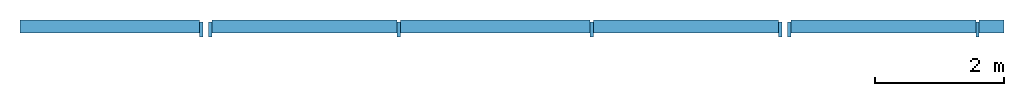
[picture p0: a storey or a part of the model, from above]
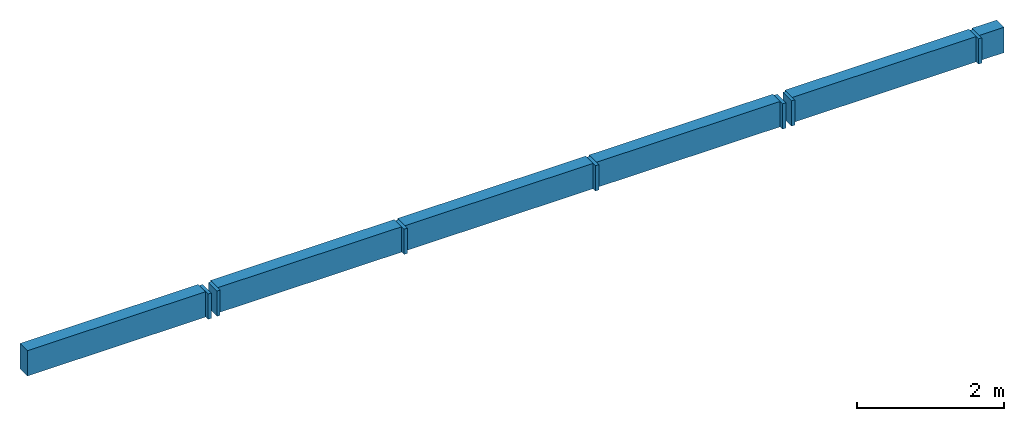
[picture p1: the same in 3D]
Properties of the parts of a building model (IFC2X3), part 1 of 7

# File
Description: ViewDefinition [CoordinationView]
File name: GM.TO-350-207.1 (EDITED).ifc (Edited by Naviate Simple BIM 2022 version 6)
Time: 2026-03-17T17:16:46+01:00
Written by: ODA SDAI 24.12
Made in: Autodesk Revit 25.4.20.11 (ENU) - IFC 25.4.0.27

# IfcProject, 10004870
LongName: 10004870; Phase: Detaljprosjekt

# IfcSite (6)
Name | RefLatitude | RefLongitude | RefElevation (mm) | Reference longitude | Reference elevation | Reference latitude | Name
ENGM | 59, 54, 57, 601318 | 10, 44, 59, 999999 | -4.85124e-10
ENGM | 42, 12, 46, 799999 | -71, -1, -58, -799999 | 0 | -71, -1, -58, -799999 | 0 | 42, 12, 46, 799999 | ENGM
ENGM | 59, 54, 57, 599999 | 10, 44, 59, 999999 | 0 | 10, 44, 59, 999999 | 0 | 59, 54, 57, 599999 | ENGM
ENGM | 42, 24, 53, 508911 | -71, -15, -29, -58837 | 0 | -71, -15, -29, -58837 | 0 | 42, 24, 53, 508911 | ENGM
ENGM | 59, 54, 49, 759826 | 10, 44, 19, 467315 | 0 | 10, 44, 19, 467315 | 0 | 59, 54, 49, 759826 | ENGM
Gardermoen

# IfcBuilding (6)
Name | Building name
TH | LongName: TH; Pset_BuildingCommon - NumberOfStoreys: 14
4 x TH | TH
TH

# IfcBuildingStorey (13)
In: TH
Name | Elevation (mm) | Name
4 x Nivå D + 1,2 m | 205200 | Nivå D + 1,2 m
4 x Nivå F - 0,7 m | 210200 | Nivå F - 0,7 m
Nivå G - 2,0m | 213700 | Nivå G - 2,0m
Nivå F | 210900 | Nivå F
D | 0
G | 0
F | 0

# IfcBuildingStorey: Level:T2 - Kote (7)
In: TH
Name | LongName | Elevation (mm) | Pset_ProductRequirements, Name | Pset_ProductRequirements, sets with these values
Nivå B | Nivå B | 197000 | Nivå B | 2
Nivå D + 1,2 m | Nivå D + 1,2 m | 205200 | Pset_AirSideSystemInformation - Name: Nivå D + 1,2 m; sets with these values: 2
Nivå E | Nivå E | 207370 | Nivå E | 2
Nivå F - 0,7 m | Nivå F - 0,7 m | 210200 | Nivå F - 0,7 m | 2
Nivå F | Nivå F | 210900 | Pset_AirSideSystemInformation - Name: Nivå F; sets with these values: 2
Nivå G - 2,0 m | Nivå G - 2,0 m | 213700 | Nivå G - 2,0 m | 2
Nivå G | Nivå G | 215700 | Pset_AirSideSystemInformation - Name: Nivå G; sets with these values: 2

# IfcBeam: 10*150 (9)
In: G
Description: 10*150; Material: STEEL/S355
AVINOR - 07_Fase: F90; 02_Prosjekt: T1; 04_Kontrakt: FDV; 03_Ansvar: FDV; 08_Status: S2; 10_Objektstatus: 3_Eksisterende/ Existing; 06_Omrade: TH; 01_Lufthavnkode: ENGM
Tekla Common - Grade: S355; Name: STÅLBJELKE; Profile: 10*150; Assembly mark: SB-10449(?); Class: 330
ePset_LocationTool - Splitting: ORIGINAL
Tekla Status - Status: Unknown; Assigned By: Me; Actual: 1; Scheduled: 0; Erection Comment: Missing Value
Pset_BeamCommon - LoadBearing: no
Tekla Quantity - Heigth: 10 mm; Width: 150 mm
ePset_Simplebim - Assembly Level: Leaf
Name | Part mark = Reference | Top elevation | Bottom elevation | Weight, as steel (Simplebim) (kg) | Volume, net (Simplebim) (m3) | Area, sides, net (Simplebim) (m2) = AREA_GROSS (m2) = AREA_NET (m2) | Height (Simplebim) (mm) | Width (Simplebim) (mm) | Length (Simplebim) (mm) | WEIGTH_NET (kg) = WEIGTH_GROSS (kg) | VOLUME_NET (m3) = VOLUME_GROSS (m3) | Length (mm)
3 x STÅLBJELKE | DSB-21652(?) | +213.570 | +213.560 | 4.12125 | 0.000525 | 0.115 | 10 | 150 | 350 | 4.12125 | 0.00054 | 350
3 x STÅLBJELKE | DSB-21605(?) | +213.580 | +213.570 | 3.88575 | 0.000495 | 0.1086 | 10 | 150 | 330 | 3.8858 | 0.00049 | 330.004
3 x STÅLBJELKE | DSB-21653(?) | +213.620 | +213.350 | 3.17925 | 0.000405 | 0.0894 | 270 | 10 | 150 | 3.17925 | 0.00041 | 270

# IfcBeam: 20*140 (2)
In: G
Description: 20*140; Material: STEEL/S355
AVINOR - 07_Fase: F90; 02_Prosjekt: T1; 04_Kontrakt: FDV; 03_Ansvar: FDV; 08_Status: S2; 10_Objektstatus: 3_Eksisterende/ Existing; 06_Omrade: TH; 01_Lufthavnkode: ENGM
Pset_BeamCommon - LoadBearing: no; Reference: DSB-19066(?)
Tekla Quantity - VOLUME_NET: 0.00015 m3; VOLUME_GROSS: 0.00015 m3; Length: 49.9999 mm; WEIGTH_NET: 1.099 kg; WEIGTH_GROSS: 1.099 kg; Heigth: 20 mm; Width: 140 mm; AREA_NET: 0.0216 m2; AREA_GROSS: 0.0216 m2
Tekla Common - Grade: S355; Bottom elevation: +213.560; Top elevation: +213.580; Name: STÅLBJELKE; Profile: 20*140; Assembly mark: SB-10449(?); Part mark: DSB-19066(?); Class: 330
ePset_SimplebimBasicQuantities - Volume, net (Simplebim): 0.00014 m3; Weight, as steel (Simplebim): 1.099 kg; Height (Simplebim): 20 mm; Width (Simplebim): 50 mm; Length (Simplebim): 140 mm; Area, sides, net (Simplebim): 0.0216 m2
Tekla Status - Status: Unknown; Assigned By: Me; Actual: 1; Scheduled: 0; Erection Comment: Missing Value
ePset_LocationTool - Splitting: ORIGINAL
ePset_Simplebim - Assembly Level: Leaf

# IfcBeam: 25*140 (2)
In: G
Description: 25*140; Material: STEEL/S355
AVINOR - 07_Fase: F90; 02_Prosjekt: T1; 04_Kontrakt: FDV; 03_Ansvar: FDV; 08_Status: S2; 10_Objektstatus: 3_Eksisterende/ Existing; 06_Omrade: TH; 01_Lufthavnkode: ENGM
Tekla Common - Grade: S355; Bottom elevation: +213.411; Profile: 25*140; Name: STÅLBJELKE; Part mark: DSB-20613(?); Assembly mark: SB-12403(?); Top elevation: +213.541; Class: 330
ePset_SimplebimBasicQuantities - Weight, as steel (Simplebim): 3.57175 kg; Area, sides, net (Simplebim): 0.0499 m2; Volume, net (Simplebim): 0.000455 m3; Width (Simplebim): 25 mm; Height (Simplebim): 130 mm; Length (Simplebim): 140 mm
ePset_LocationTool - Splitting: ORIGINAL
Tekla Status - Status: Unknown; Assigned By: Me; Actual: 1; Scheduled: 0; Erection Comment: Missing Value
Tekla Quantity - WEIGTH_NET: 3.57175 kg; WEIGTH_GROSS: 3.57175 kg; AREA_GROSS: 0.0499 m2; AREA_NET: 0.0499 m2; Heigth: 25 mm; Length: 130 mm; Width: 140 mm; VOLUME_GROSS: 0.00045 m3; VOLUME_NET: 0.00045 m3
ePset_Simplebim - Assembly Level: Leaf
Pset_BeamCommon - Reference: DSB-20613(?); LoadBearing: no

# IfcBeam: 60*5 (15)
In: G
Description: 60*5; Material: STEEL/S355
Pset_BeamCommon - LoadBearing: no; Reference: DSB-18871(?)
AVINOR - 07_Fase: F90; 02_Prosjekt: T1; 04_Kontrakt: FDV; 03_Ansvar: FDV; 08_Status: S2; 10_Objektstatus: 3_Eksisterende/ Existing; 06_Omrade: TH; 01_Lufthavnkode: ENGM
ePset_SimplebimBasicQuantities - Weight, as steel (Simplebim): 0.35325 kg; Volume, net (Simplebim): 0.000045 m3; Area, sides, net (Simplebim): 0.0201 m2; Height (Simplebim): 5 mm; Width (Simplebim): 60 mm; Length (Simplebim): 150 mm
Tekla Status - Status: Unknown; Assigned By: Me; Actual: 1; Scheduled: 0; Erection Comment: Missing Value
ePset_LocationTool - Splitting: ORIGINAL
Tekla Quantity - VOLUME_NET: 0.00005 m3; VOLUME_GROSS: 0.00005 m3; WEIGTH_GROSS: 0.35325 kg; WEIGTH_NET: 0.35325 kg; AREA_NET: 0.0201 m2; AREA_GROSS: 0.0201 m2; Width: 5 mm; Heigth: 60 mm; Length: 150 mm
Tekla Common - Grade: S355; Name: STÅLBJELKE; Assembly mark: SB-10449(?); Top elevation: +213.665; Bottom elevation: +213.660; Part mark: DSB-18871(?); Class: 330; Profile: 60*5
ePset_Simplebim - Assembly Level: Leaf

# IfcBeam: AAJKORS265*195*30*900*150*700*700 (2)
In: F
Description: AAJKORS265*195*30*900*150*700*700
Tekla Common - Name: PREFABBJELKE; Top elevation: +210.030; Bottom elevation: +209.130; Profile: AAJKORS265*195*30*900*150*700*700; Grade: C45/55; Class: 130
Pset_BeamCommon - LoadBearing: no
ePset_SimplebimBasicQuantities - Height (Simplebim): 900 mm; Width (Simplebim): 1000 mm; Length (Simplebim): 8775 mm
Tekla Status - Status: Unknown; Assigned By: Me; Actual: 1; Scheduled: 0; Erection Comment: Missing Value
ePset_LocationTool - Splitting: RESULT
AVINOR - 07_Fase: F90; 02_Prosjekt: T1; 04_Kontrakt: FDV; 03_Ansvar: FDV; 08_Status: S2; 05_ID-nummer: +TA=223.001; 10_Objektstatus: 3_Eksisterende/ Existing; 06_Omrade: TH; 01_Lufthavnkode: ENGM
ePset_Simplebim - Assembly Level: Leaf
Name | Assembly mark | Part mark = Reference | Volume, net (Simplebim) (m3) | Area, sides, net (Simplebim) (m2) | Weight, as steel (Simplebim) (kg)
PREFABBJELKE | PB-639 | Concrete_PB-1-34 | 5.44013 | 34.8306 | 42705
PREFABBJELKE | PB-644 | Concrete_PB-1-39 | 5.44051 | 34.8266 | 42708

# IfcBeam: B223 - Bjelke - Flatstål:B223 - Bjelke - Flatstål - w240 h 8 (3)
In: Nivå G - 2,0 m
Type - PredefinedType: BEAM
Type - Pset_BeamCommon - LoadBearing: yes
AVINOR - 07_Fase: F90; 03_Ansvar: FDV; 08_Status: S2; 06_Omrade: TH; 01_Lufthavnkode: ENGM
Pset_QuantityTakeOff - Reference: B223 - Bjelke - Flatstål - w240 h 8; sets with these values: 2
ePset_SimplebimBasicQuantities - Width (Simplebim): 8 mm; Height (Simplebim): 240 mm
Pset_BeamCommon - IsExternal: no; Reference: B223 - Bjelke - Flatstål - w240 h 8
ePset_Simplebim - Assembly Level: Leaf
Name (B223 - Bjelke - Flatstål:B223 - Bjelke - Flatstål - w240 h 8:...) | Splitting | Volume, net (Simplebim) (m3) | Weight, as steel (Simplebim) (kg) | Area, sides, net (Simplebim) (m2) | Length (Simplebim) (mm) | Group
37630491 | ORIGINAL | 0.01728 | 135.648 | 4.46784 | 9000 | Model Group:A240 - eksisterende gallerivegg i pir G-2 / generell (members excluded):37630519 | Material: _NSW Stål; Pset_BeamCommon - Slope: 0 deg; Span: 9000 mm
37559219 | RESULT | 0.00554514 | 43.5294 | 1.43633 | 2888 | Model Group:A240 - eksisterende gallerivegg i pir G-2 / bak sjakt (members excluded):37559234
37630725 | RESULT | 0.00654832 | 51.4043 | 1.69549 | 3411 | Model Group:A240 - eksisterende gallerivegg i pir G-2 / generell (members excluded):37630753

# IfcBeam: B223 - Bjelke - HUP2:B223 - HUP 50x50x5mm 2 (15)
In: Nivå F - 0,7 m
Type - PredefinedType: BEAM
Type - Pset_BeamCommon - LoadBearing: yes
Material: _NSW Stål; Group: Model Group:A184862 - Kiosk NSOPØ 05.235 2 (members excluded):47061109
ePset_SimplebimBasicQuantities - Height (Simplebim): 50 mm; Width (Simplebim): 50 mm
Pset_QuantityTakeOff - Reference: B223 - HUP 50x50x5mm 2; sets with these values: 2
ePset_LocationTool - Splitting: ORIGINAL
AVINOR - 08_Status: S4; 07_Fase: F90; 03_Ansvar: 182412; 06_Omrade: TH; 02_Prosjekt: A184862; 05_ID-nummer: +TH=223.042; 01_Lufthavnkode: ENGM
Pset_BeamCommon - IsExternal: no; Slope: 0 deg; Reference: B223 - HUP 50x50x5mm 2
ePset_Simplebim - Assembly Level: Leaf
Name (B223 - Bjelke - HUP2:B223 - HUP 50x50x5mm 2:...) | Volume, net (Simplebim) (m3) | Area, sides, net (Simplebim) (m2) | Length (Simplebim) (mm) = Span (mm) | Weight, as steel (Simplebim) (kg)
47060724 | 0.000333 | 0.135 | 370 | 2.61405
47060726 | 0.000378 | 0.153 | 420 | 2.9673
47060728 | 0.000841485 | 0.338394 | 934.983 | 6.60565
47060730 | 0.000333 | 0.135 | 370 | 2.61405
47060732 | 0.000333 | 0.135 | 370 | 2.61405
47060734 | 0.000333 | 0.135 | 370 | 2.61405
47060736 | 0.000333 | 0.135 | 370 | 2.61405
47060738 | 0.000333 | 0.135 | 370 | 2.61405
47060740 | 0.000333 | 0.135 | 370 | 2.61405
47060742 | 0.000333 | 0.135 | 370 | 2.61405
47060744 | 0.000333 | 0.135 | 370 | 2.61405
47060746 | 0.000333 | 0.135 | 370 | 2.61405
47060752 | 0.000333 | 0.135 | 370 | 2.61405
47060758 | 0.000378 | 0.153 | 420 | 2.9673
47060760 | 0.000333 | 0.135 | 370 | 2.61405

# IfcBeam: B223 - Bjelke - HUP:B223 - HUP 40x80x4mm (3)
In: Nivå G - 2,0 m
Type - PredefinedType: BEAM
Type - Pset_BeamCommon - LoadBearing: yes
ePset_SimplebimBasicQuantities - Height (Simplebim): 80 mm; Width (Simplebim): 40 mm
AVINOR - 07_Fase: F90; 03_Ansvar: FDV; 08_Status: S2; 06_Omrade: TH; 01_Lufthavnkode: ENGM
Pset_QuantityTakeOff - Reference: B223 - HUP 40x80x4mm; sets with these values: 2
Pset_BeamCommon - Reference: B223 - HUP 40x80x4mm; IsExternal: no
ePset_Simplebim - Assembly Level: Leaf
Name (B223 - Bjelke - HUP:B223 - HUP 40x80x4mm:...) | Volume, net (Simplebim) (m3) | Area, sides, net (Simplebim) (m2) | Length (Simplebim) (mm) | Weight, as steel (Simplebim) (kg) | Splitting | Group
37451390 | 0.008064 | 4.03379 | 9000 | 63.3024 | ORIGINAL | Model Group:A254 - eksisterende glassgulv i pir G ved fasade / __generell (members excluded):37451392 | Material: _NSW Stål; Pset_BeamCommon - Slope: 0 deg; Span: 9000 mm
37451328 | 0.00258773 | 1.29566 | 2888 | 20.3137 | RESULT | Model Group:A254 - eksisterende glassgulv i pir G ved fasade / __generell (members excluded):37451330
37451477 | 0.00305588 | 1.52973 | 3411 | 23.9887 | RESULT | Model Group:A254 - eksisterende glassgulv i pir G ved fasade / __generell (members excluded):37451479

# IfcBeam: B223 - Bjelke - L2:B223 - L-profil - 25 x 25 x 5 mm (3)
In: Nivå G - 2,0 m
Type - PredefinedType: BEAM
Type - Pset_BeamCommon - LoadBearing: yes
Material: _NSW Stål; Group: Model Group:A240 - eksisterende gallerivegg i pir G-2 / bak sjakt (members excluded):37559234
AVINOR - 07_Fase: F90; 03_Ansvar: FDV; 08_Status: S2; 06_Omrade: TH; 01_Lufthavnkode: ENGM
Pset_ReinforcementBarPitchOfBeam - Reference: B223 - L-profil - 25 x 25 x 5 mm; sets with these values: 2
Pset_BeamCommon - Reference: B223 - L-profil - 25 x 25 x 5 mm; IsExternal: no; Slope: 0 deg
ePset_LocationTool - Splitting: ORIGINAL
ePset_SimplebimBasicQuantities - Width (Simplebim): 25 mm; Height (Simplebim): 25 mm
ePset_Simplebim - Assembly Level: Leaf
Name (B223 - Bjelke - L2:B223 - L-profil - 25 x 25 x 5 mm:...) | Span (mm) = Length (Simplebim) (mm) | Weight, as steel (Simplebim) (kg) | Volume, net (Simplebim) (m3) | Area, sides, net (Simplebim) (m2)
37559249 | 1335 | 2.35794 | 0.000300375 | 0.13395
37559287 | 590.155 | 1.04236 | 0.000132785 | 0.0594655
37559298 | 285 | 0.503381 | 0.000064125 | 0.02895

# IfcBeam: B223 - Bjelke - L2:B223 - L-profil - 70 x 70 x 7 mm, B223 - Bjelke - L2:B223 - L-profil - 70 x 70 x 7 mm:37559289
In: Nivå G - 2,0 m
Type - PredefinedType: BEAM
Type - Pset_BeamCommon - LoadBearing: yes
Material: _NSW Stål; Group: Model Group:A240 - eksisterende gallerivegg i pir G-2 / bak sjakt (members excluded):37559234
ePset_SimplebimBasicQuantities - Area, sides, net (Simplebim): 0.138639 m2; Volume, net (Simplebim): 0.000454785 m3; Height (Simplebim): 70 mm; Width (Simplebim): 70 mm; Length (Simplebim): 488.491 mm; Weight, as steel (Simplebim): 3.57006 kg
ePset_LocationTool - Splitting: ORIGINAL
AVINOR - 07_Fase: F90; 03_Ansvar: FDV; 08_Status: S2; 06_Omrade: TH; 01_Lufthavnkode: ENGM
Pset_QuantityTakeOff - Reference: B223 - L-profil - 70 x 70 x 7 mm; sets with these values: 2
Pset_BeamCommon - IsExternal: no; Slope: 0 deg; Reference: B223 - L-profil - 70 x 70 x 7 mm; Span: 488.491 mm
ePset_Simplebim - Assembly Level: Leaf

# IfcBeam: B223 - Bjelke - L2:B223 - L-profil - 80 x 25 x 4 mm, B223 - Bjelke - L2:B223 - L-profil - 80 x 25 x 4 mm:37559270
In: Nivå G - 2,0 m
Type - PredefinedType: BEAM
Type - Pset_BeamCommon - LoadBearing: yes
Material: _NSW Stål; Group: Model Group:A240 - eksisterende gallerivegg i pir G-2 / bak sjakt (members excluded):37559234
Pset_ReinforcementBarPitchOfBeam - Reference: B223 - L-profil - 80 x 25 x 4 mm; sets with these values: 2
AVINOR - 07_Fase: F90; 03_Ansvar: FDV; 08_Status: S2; 06_Omrade: TH; 01_Lufthavnkode: ENGM
ePset_SimplebimBasicQuantities - Weight, as steel (Simplebim): 6.6525 kg; Height (Simplebim): 25 mm; Width (Simplebim): 80 mm; Volume, net (Simplebim): 0.000847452 m3; Length (Simplebim): 2097.65 mm; Area, sides, net (Simplebim): 0.441315 m2
ePset_LocationTool - Splitting: ORIGINAL
Pset_BeamCommon - Reference: B223 - L-profil - 80 x 25 x 4 mm; IsExternal: no; Slope: 0 deg; Span: 2097.73 mm
ePset_Simplebim - Assembly Level: Leaf

# IfcBeam: B223 - Bjelke - L:B223 - 25x25x5 (10)
In: Nivå G - 2,0 m
Type - PredefinedType: BEAM
Type - Pset_BeamCommon - LoadBearing: yes
Pset_BeamCommon - Reference: B223 - 25x25x5; IsExternal: no
Pset_QuantityTakeOff - Reference: B223 - 25x25x5; sets with these values: 2
AVINOR - 07_Fase: F90; 03_Ansvar: FDV; 08_Status: S2; 06_Omrade: TH; 01_Lufthavnkode: ENGM
ePset_SimplebimBasicQuantities - Width (Simplebim): 25 mm; Height (Simplebim): 25 mm
ePset_Simplebim - Assembly Level: Leaf
Name (B223 - Bjelke - L:B223 - 25x25x5:...) | Material | Slope (deg) | Span (mm) | Splitting | Volume, net (Simplebim) (m3) | Area, sides, net (Simplebim) (m2) | Length (Simplebim) (mm) | Weight, as steel (Simplebim) (kg) | Group
37630528 | _NSW Stål | 0 | 1485 | ORIGINAL | 0.000334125 | 0.14895 | 1485 | 2.62288 | Model Group:A240 - eksisterende gallerivegg i pir G-2 / generell (members excluded):37630519
37630531 | _NSW Stål | 0 | 1335 | ORIGINAL | 0.000300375 | 0.13395 | 1335 | 2.35794 | Model Group:A240 - eksisterende gallerivegg i pir G-2 / generell (members excluded):37630519
37630534 | _NSW Stål | 0 | 1485 | ORIGINAL | 0.000334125 | 0.14895 | 1485 | 2.62288 | Model Group:A240 - eksisterende gallerivegg i pir G-2 / generell (members excluded):37630519
37630537 | _NSW Stål | 0 | 897.095 | ORIGINAL | 0.000201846 | 0.0901595 | 897.095 | 1.58449 | Model Group:A240 - eksisterende gallerivegg i pir G-2 / generell (members excluded):37630519
37630540 | _NSW Stål | 0 | 302.905 | ORIGINAL | 0.0000681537 | 0.0307405 | 302.905 | 0.535007 | Model Group:A240 - eksisterende gallerivegg i pir G-2 / generell (members excluded):37630519
37630543 | _NSW Stål | 0 | 1335 | ORIGINAL | 0.000300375 | 0.13395 | 1335 | 2.35794 | Model Group:A240 - eksisterende gallerivegg i pir G-2 / generell (members excluded):37630519
37630551 | _NSW Stål | 0 | 285 | ORIGINAL | 0.000064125 | 0.02895 | 285 | 0.503381 | Model Group:A240 - eksisterende gallerivegg i pir G-2 / generell (members excluded):37630519
37630762 | _NSW Stål | 0 | 1485 | ORIGINAL | 0.000334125 | 0.14895 | 1485 | 2.62288 | Model Group:A240 - eksisterende gallerivegg i pir G-2 / generell (members excluded):37630753
37630765 | _NSW Stål | 0 | 1335 | ORIGINAL | 0.000300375 | 0.13395 | 1335 | 2.35794 | Model Group:A240 - eksisterende gallerivegg i pir G-2 / generell (members excluded):37630753
37630768 |  |  |  | RESULT | 0.0000906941 | 0.0407585 | 403 | 0.711949 | Model Group:A240 - eksisterende gallerivegg i pir G-2 / generell (members excluded):37630753

# IfcBeam: B223 - Bjelke - L:B223 - 40x40x4 (6)
In: Nivå G - 2,0 m
Type - PredefinedType: BEAM
Type - Pset_BeamCommon - LoadBearing: yes
AVINOR - 07_Fase: F90; 03_Ansvar: FDV; 08_Status: S2; 06_Omrade: TH; 01_Lufthavnkode: ENGM
ePset_SimplebimBasicQuantities - Width (Simplebim): 40 mm; Height (Simplebim): 40 mm
Pset_ReinforcementBarPitchOfBeam - Reference: B223 - 40x40x4; sets with these values: 2
Pset_BeamCommon - Reference: B223 - 40x40x4; IsExternal: no
ePset_Simplebim - Assembly Level: Leaf
Name (B223 - Bjelke - L:B223 - 40x40x4:...) | Weight, as steel (Simplebim) (kg) | Area, sides, net (Simplebim) (m2) | Volume, net (Simplebim) (m3) | Length (Simplebim) (mm) | Splitting | Group
37451386 | 21.4776 | 1.44061 | 0.002736 | 9000 | ORIGINAL | Model Group:A254 - eksisterende glassgulv i pir G ved fasade / __generell (members excluded):37451392 | Material: _NSW Stål; Pset_BeamCommon - Slope: 0 deg; Span: 9000 mm
37451388 | 21.4776 | 1.44061 | 0.002736 | 9000 | ORIGINAL | Model Group:A254 - eksisterende glassgulv i pir G ved fasade / __generell (members excluded):37451392 | Material: _NSW Stål; Pset_BeamCommon - Slope: 0 deg; Span: 9000 mm
37451324 | 6.89215 | 0.462703 | 0.000877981 | 2888 | RESULT | Model Group:A254 - eksisterende glassgulv i pir G ved fasade / __generell (members excluded):37451330
37451326 | 6.89215 | 0.462703 | 0.000877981 | 2888 | RESULT | Model Group:A254 - eksisterende glassgulv i pir G ved fasade / __generell (members excluded):37451330
37451473 | 8.13902 | 0.546302 | 0.00103682 | 3411 | RESULT | Model Group:A254 - eksisterende glassgulv i pir G ved fasade / __generell (members excluded):37451479
37451475 | 8.13902 | 0.546302 | 0.00103682 | 3411 | RESULT | Model Group:A254 - eksisterende glassgulv i pir G ved fasade / __generell (members excluded):37451479

# IfcBeam: B223 - Bjelke - L:B223 -100x50x8 (3)
In: Nivå F - 0,7 m
Type - PredefinedType: BEAM
Type - Pset_BeamCommon - LoadBearing: yes
AVINOR - 07_Fase: F90; 03_Ansvar: FDV; 08_Status: S2; 06_Omrade: TH; 01_Lufthavnkode: ENGM
ePset_SimplebimBasicQuantities - Height (Simplebim): 50 mm; Width (Simplebim): 100 mm
Pset_BeamCommon - Reference: B223 -100x50x8; IsExternal: no
Pset_ReinforcementBarPitchOfBeam - Reference: B223 -100x50x8; sets with these values: 2
ePset_Simplebim - Assembly Level: Leaf
Name (B223 - Bjelke - L:B223 -100x50x8:...) | Splitting | Volume, net (Simplebim) (m3) | Weight, as steel (Simplebim) (kg) | Length (Simplebim) (mm) | Area, sides, net (Simplebim) (m2)
37344799 | ORIGINAL | 0.0102013 | 80.08 | 8980 | 2.69627 | Material: _NSW Stål; Pset_BeamCommon - Slope: 0 deg; Span: 8980 mm
37344676 | RESULT | 0.00326951 | 25.6657 | 2878 | 0.8657
37344927 | RESULT | 0.00386306 | 30.3251 | 3401 | 1.02245

# IfcBeam: B223 - Bjelke - L:B223 -80x25x4 (2)
In: Nivå G - 2,0 m
Type - PredefinedType: BEAM
Type - Pset_BeamCommon - LoadBearing: yes
AVINOR - 07_Fase: F90; 03_Ansvar: FDV; 08_Status: S2; 06_Omrade: TH; 01_Lufthavnkode: ENGM
Pset_BeamCommon - IsExternal: no; Reference: B223 -80x25x4
Pset_ReinforcementBarPitchOfBeam - Reference: B223 -80x25x4; sets with these values: 2
ePset_SimplebimBasicQuantities - Height (Simplebim): 25 mm; Width (Simplebim): 80 mm
ePset_Simplebim - Assembly Level: Leaf
Name (B223 - Bjelke - L:B223 -80x25x4:...) | Splitting | Length (Simplebim) (mm) | Area, sides, net (Simplebim) (m2) | Weight, as steel (Simplebim) (kg) | Volume, net (Simplebim) (m3) | Group
37630521 | ORIGINAL | 9001.02 | 1.89102 | 28.5458 | 0.00363641 | Model Group:A240 - eksisterende gallerivegg i pir G-2 / generell (members excluded):37630519 | Material: _NSW Stål; Pset_BeamCommon - Span: 9001.02 mm; Slope: 0 deg
37630755 | RESULT | 3411 | 0.717031 | 10.8163 | 0.00137788 | Model Group:A240 - eksisterende gallerivegg i pir G-2 / generell (members excluded):37630753

# IfcBeam: B223 - Bjelke - T:B223 - T-profil - 40 x 40 x 10 mm (5)
In: Nivå G - 2,0 m
Type - PredefinedType: BEAM
Type - Pset_BeamCommon - LoadBearing: yes
Material: _NSW Stål
Pset_ReinforcementBarPitchOfBeam - Reference: B223 - T-profil - 40 x 40 x 10 mm; sets with these values: 2
AVINOR - 07_Fase: F90; 03_Ansvar: FDV; 08_Status: S2; 06_Omrade: TH; 01_Lufthavnkode: ENGM
Pset_BeamCommon - Reference: B223 - T-profil - 40 x 40 x 10 mm; IsExternal: no; Slope: 0 deg; Span: 372 mm
ePset_LocationTool - Splitting: ORIGINAL
ePset_SimplebimBasicQuantities - Area, sides, net (Simplebim): 0.06027 m2; Height (Simplebim): 40 mm; Volume, net (Simplebim): 0.0001395 m3; Width (Simplebim): 40 mm; Length (Simplebim): 372 mm; Weight, as steel (Simplebim): 1.09507 kg
ePset_Simplebim - Assembly Level: Leaf
Name (B223 - Bjelke - T:B223 - T-profil - 40 x 40 x 10 mm:...) | Group
37451393 | Model Group:A254 - eksisterende glassgulv i pir G ved fasade / __generell (members excluded):37451392
37451395 | Model Group:A254 - eksisterende glassgulv i pir G ved fasade / __generell (members excluded):37451392
37451397 | Model Group:A254 - eksisterende glassgulv i pir G ved fasade / __generell (members excluded):37451392
37451482 | Model Group:A254 - eksisterende glassgulv i pir G ved fasade / __generell (members excluded):37451479
37451484 | Model Group:A254 - eksisterende glassgulv i pir G ved fasade / __generell (members excluded):37451479

# IfcBeam: B223 - Bjelke - UNP:B223 - UNP 240 (3)
In: Nivå G - 2,0 m
Type - PredefinedType: BEAM
Type - Pset_BeamCommon - LoadBearing: yes
Pset_BeamCommon - IsExternal: no; Reference: B223 - UNP 240
ePset_SimplebimBasicQuantities - Width (Simplebim): 85 mm; Height (Simplebim): 240 mm
AVINOR - 07_Fase: F90; 03_Ansvar: FDV; 08_Status: S2; 06_Omrade: TH; 01_Lufthavnkode: ENGM
Pset_QuantityTakeOff - Reference: B223 - UNP 240; sets with these values: 2
ePset_Simplebim - Assembly Level: Leaf
Name (B223 - Bjelke - UNP:B223 - UNP 240:...) | Area, sides, net (Simplebim) (m2) | Volume, net (Simplebim) (m3) | Weight, as steel (Simplebim) (kg) | Length (Simplebim) (mm) | Splitting | Group
37630502 | 7.13458 | 0.0377809 | 296.58 | 9000 | ORIGINAL | Model Group:A240 - eksisterende gallerivegg i pir G-2 / generell (members excluded):37630519 | Material: _NSW Stål; Pset_BeamCommon - Slope: 0 deg; Span: 9000 mm
37559226 | 2.29518 | 0.0121239 | 95.1723 | 2888 | RESULT | Model Group:A240 - eksisterende gallerivegg i pir G-2 / bak sjakt (members excluded):37559234
37630736 | 2.70889 | 0.0143172 | 112.39 | 3411 | RESULT | Model Group:A240 - eksisterende gallerivegg i pir G-2 / generell (members excluded):37630753

# IfcBeam: B223 - Bjelke - eks. pir fasade:B223 - 400x100x8 (3)
In: Nivå F - 0,7 m
Type - PredefinedType: BEAM; Material: <Unnamed>, _NSW Stål
Type - Pset_BeamCommon - LoadBearing: yes
AVINOR - 07_Fase: F90; 03_Ansvar: FDV; 08_Status: S2; 06_Omrade: TH; 01_Lufthavnkode: ENGM
ePset_SimplebimBasicQuantities - Width (Simplebim): 100 mm; Height (Simplebim): 400 mm
Pset_BeamCommon - IsExternal: no; Reference: B223 - 400x100x8
Pset_ReinforcementBarPitchOfBeam - Reference: B223 - 400x100x8; sets with these values: 2
ePset_Simplebim - Assembly Level: Leaf
Name (B223 - Bjelke - eks. pir fasade:B223 - 400x100x8:...) | Splitting | Area, sides, net (Simplebim) (m2) | Volume, net (Simplebim) (m3) | Length (Simplebim) (mm) | Weight, as steel (Simplebim) (kg)
37344797 | ORIGINAL | 10.7205 | 0.0429117 | 8980 | 336.857 | Pset_BeamCommon - Slope: 0 deg; Span: 8980 mm
37344674 | RESULT | 3.47039 | 0.0138546 | 2878 | 108.758
37344925 | RESULT | 4.08451 | 0.0163185 | 3401 | 128.1

# IfcBeam: HEA260 (2)
In: F
Description: HEA260
Tekla Common - Bottom elevation: +209.765; Grade: S355; Name: STÅLBJELKE; Top elevation: +210.015; Profile: HEA260; Assembly mark: SB-7607(?); Part mark: DSB-5678(?); Class: 330
Pset_BeamCommon - LoadBearing: no; Reference: DSB-5678(?)
ePset_SimplebimBasicQuantities - Area, sides, net (Simplebim): 3.75315 m2; Height (Simplebim): 250 mm; Width (Simplebim): 260 mm; Length (Simplebim): 2518 mm; Volume, net (Simplebim): 0.0218913 m3; Weight, as steel (Simplebim): 171.847 kg
Tekla Status - Status: Unknown; Assigned By: Me; Actual: 1; Scheduled: 0; Erection Comment: Missing Value
ePset_LocationTool - Splitting: RESULT
AVINOR - 07_Fase: F90; 02_Prosjekt: T1; 04_Kontrakt: FDV; 03_Ansvar: FDV; 08_Status: S2; 05_ID-nummer: +TA=223.002; 10_Objektstatus: 3_Eksisterende/ Existing; 06_Omrade: TH; 01_Lufthavnkode: ENGM
ePset_Simplebim - Assembly Level: Leaf

# IfcBeam: HEA300, STÅLBJELKE
In: D
Description: HEA300
AVINOR - 07_Fase: F90; 02_Prosjekt: T1; 04_Kontrakt: FDV; 03_Ansvar: FDV; 08_Status: S2; 10_Objektstatus: 3_Eksisterende/ Existing; 06_Omrade: TH; 01_Lufthavnkode: ENGM
Tekla Common - Grade: S355; Name: STÅLBJELKE; Top elevation: +209.385; Assembly mark: SB-11844(?); Bottom elevation: +209.095; Part mark: DSB-5549(?); Class: 330; Profile: HEA300
ePset_SimplebimBasicQuantities - Weight, as steel (Simplebim): 303.656 kg; Area, sides, net (Simplebim): 5.91501 m2; Width (Simplebim): 300 mm; Height (Simplebim): 290 mm; Length (Simplebim): 3433 mm; Volume, net (Simplebim): 0.0386823 m3
Pset_BeamCommon - LoadBearing: no; Reference: DSB-5549(?)
Tekla Status - Status: Unknown; Assigned By: Me; Actual: 1; Scheduled: 0; Erection Comment: Missing Value
ePset_LocationTool - Splitting: RESULT
ePset_Simplebim - Assembly Level: Leaf

# IfcBeam: HEB300 (7)
Description: HEB300
ePset_SimplebimBasicQuantities - Width (Simplebim): 300 mm; Height (Simplebim): 300 mm
AVINOR - 10_Objektstatus: 0_Nytt/ New; 08_Status: S4; 07_Fase: F90; 04_Kontrakt: 182251; 06_Omrade: TH; 02_Prosjekt: A146091-1; 03_Ansvar: 181605; 09_Arbeidspakke: AP01; 01_Lufthavnkode: ENGM
Tekla Common - Grade: S355; Name: STÅLBJELKE; Part mark: DSB-0(?); Assembly mark: SB-0(?); Class: 330; Profile: HEB300
Tekla Status - Status: Unknown; Assigned By: Me; Actual: 1; Scheduled: 0; Erection Comment: Missing Value
Pset_BeamCommon - LoadBearing: no; Reference: DSB-0(?)
ePset_Simplebim - Assembly Level: Leaf
Name | In | Volume, net (Simplebim) (m3) | Area, sides, net (Simplebim) (m2) | Length (Simplebim) (mm) | Weight, as steel (Simplebim) (kg) | 05_ID-nummer | Bottom elevation | Top elevation | Splitting
STÅLBJELKE | F | 0.1301 | 15.1679 | 8940 | 1021.28 | +TH=223.017 | +213.120 | +213.420 | ORIGINAL | Material: STEEL/S355; Tekla Quantity - WEIGTH_NET: 977.645 kg; AREA_NET: 15.5713 m2; WEIGTH_GROSS: 1046.37 kg; AREA_GROSS: 15.4841 m2; Width: 300 mm; Heigth: 300 mm; Length: 8940 mm; VOLUME_NET: 0.12454 m3; VOLUME_GROSS: 0.1333 m3
STÅLBJELKE | D | 0.103562 | 12.0456 | 6940 | 812.961 | +TH=223.013 | +209.740 | +210.040 | ORIGINAL | Material: STEEL/S355; Tekla Quantity - WEIGTH_NET: 778.069 kg; AREA_NET: 12.3679 m2; WEIGTH_GROSS: 812.282 kg; AREA_GROSS: 12.0201 m2; Width: 300 mm; Heigth: 300 mm; Length: 6940 mm; VOLUME_NET: 0.09912 m3; VOLUME_GROSS: 0.10348 m3
STÅLBJELKE | F | 0.0409962 | 4.80805 | 2858 | 321.82 | +TH=223.017 | +213.120 | +213.420 | RESULT
2 x STÅLBJELKE | F | 0.037286 | 4.35142 | 2508 | 292.695 | +TH=223.017 | +213.120 | +213.420 | RESULT
STÅLBJELKE | F | 0.0487642 | 5.71269 | 3381 | 382.799 | +TH=223.017 | +213.120 | +213.420 | RESULT
STÅLBJELKE | D | 0.0206017 | 2.42015 | 1381 | 161.724 | +TH=223.013 | +209.740 | +210.040 | RESULT

# IfcBeam: HEB600 (6)
In: D
Description: HEB600
ePset_SimplebimBasicQuantities - Width (Simplebim): 300 mm; Height (Simplebim): 600 mm
AVINOR - 10_Objektstatus: 0_Nytt/ New; 08_Status: S4; 07_Fase: F90; 05_ID-nummer: +TH=223.009; 04_Kontrakt: 182251; 06_Omrade: TH; 02_Prosjekt: A146091-1; 03_Ansvar: 181605; 09_Arbeidspakke: AP01; 01_Lufthavnkode: ENGM
Tekla Status - Status: Unknown; Assigned By: Me; Actual: 1; Scheduled: 0; Erection Comment: Missing Value
Tekla Common - Grade: S355; Bottom elevation: +209.140; Name: STÅLBJELKE; Profile: HEB600; Part mark: DSB-0(?); Assembly mark: SB-0(?); Class: 330
Pset_BeamCommon - LoadBearing: no; Reference: DSB-0(?)
ePset_Simplebim - Assembly Level: Leaf
Name | Weight, as steel (Simplebim) (kg) | Volume, net (Simplebim) (m3) | Area, sides, net (Simplebim) (m2) | Length (Simplebim) (mm) | Top elevation | Splitting
2 x STÅLBJELKE | 848.055 | 0.108032 | 9.83085 | 4735 | +209.740 | ORIGINAL | Material: STEEL/S355; Tekla Quantity - VOLUME_NET: 0.10557 m3; VOLUME_GROSS: 0.12785 m3; WEIGTH_NET: 828.691 kg; AREA_GROSS: 10.9994 m2; AREA_NET: 9.96522 m2; WEIGTH_GROSS: 1003.58 kg; Width: 300 mm; Heigth: 600 mm; Length: 4735 mm
STÅLBJELKE | 1031.26 | 0.131371 | 11.3537 | 4900 | +209.740 | ORIGINAL | Material: STEEL/S355; Tekla Quantity - VOLUME_NET: 0.12825 m3; VOLUME_GROSS: 0.1323 m3; WEIGTH_NET: 1006.78 kg; AREA_GROSS: 11.3827 m2; AREA_NET: 11.5794 m2; WEIGTH_GROSS: 1038.56 kg; Width: 300 mm; Heigth: 600 mm; Length: 4900 mm
STÅLBJELKE | 405.095 | 0.0516045 | 4.59581 | 2239 | +210.040 | RESULT
2 x STÅLBJELKE | 430.786 | 0.0548772 | 4.91618 | 2549 | +210.040 | RESULT

# IfcBeam: HI500-20-70*300, STÅLBJELKE
In: D
Description: HI500-20-70*300
Tekla Common - Grade: S355; Top elevation: +210.040; Name: STÅLBJELKE; Profile: HI500-20-70*300; Part mark: DSB-0(?); Assembly mark: SB-0(?); Class: 330; Bottom elevation: +209.540
AVINOR - 10_Objektstatus: 0_Nytt/ New; 08_Status: S4; 07_Fase: F90; 04_Kontrakt: 182251; 06_Omrade: TH; 05_ID-nummer: +TH=223.013; 02_Prosjekt: A146091-1; 03_Ansvar: 181605; 09_Arbeidspakke: AP01; 01_Lufthavnkode: ENGM
Tekla Status - Status: Unknown; Assigned By: Me; Actual: 1; Scheduled: 0; Erection Comment: Missing Value
ePset_SimplebimBasicQuantities - Volume, net (Simplebim): 0.320547 m3; Area, sides, net (Simplebim): 14.1302 m2; Weight, as steel (Simplebim): 2516.29 kg; Height (Simplebim): 500 mm; Width (Simplebim): 300 mm; Length (Simplebim): 6858 mm
ePset_LocationTool - Splitting: RESULT
Pset_BeamCommon - LoadBearing: no; Reference: DSB-0(?)
ePset_Simplebim - Assembly Level: Leaf

# IfcBeam: HQ265*5-40*130-12*440 (2)
In: G
Description: HQ265*5-40*130-12*440; Material: STEEL/S355
AVINOR - 07_Fase: F90; 02_Prosjekt: T1; 04_Kontrakt: FDV; 03_Ansvar: FDV; 08_Status: S2; 10_Objektstatus: 3_Eksisterende/ Existing; 06_Omrade: TH; 01_Lufthavnkode: ENGM
Tekla Common - Grade: S355; Top elevation: +213.560; Name: STÅLBJELKE; Part mark: DSB-24230(?); Assembly mark: SB-12403(?); Bottom elevation: +213.283; Profile: HQ265*5-40*130-12*440; Class: 330
ePset_SimplebimBasicQuantities - Weight, as steel (Simplebim): 408.16 kg; Length (Simplebim): 4096 mm; Volume, net (Simplebim): 0.0519949 m3; Width (Simplebim): 440.001 mm; Height (Simplebim): 277 mm; Area, sides, net (Simplebim): 8.51048 m2
ePset_LocationTool - Splitting: ORIGINAL
Tekla Quantity - WEIGTH_NET: 408.161 kg; AREA_NET: 8.51048 m2; AREA_GROSS: 8.80808 m2; Width: 440 mm; Heigth: 277 mm; Length: 4096 mm; VOLUME_NET: 0.052 m3; WEIGTH_GROSS: 422.177 kg; VOLUME_GROSS: 0.05378 m3
Tekla Status - Status: Unknown; Assigned By: Me; Actual: 1; Scheduled: 0; Erection Comment: Missing Value
Pset_BeamCommon - Reference: DSB-24230(?); LoadBearing: no
ePset_Simplebim - Assembly Level: Leaf

# IfcBeam: IPE220 (18)
Description: IPE220
AVINOR - 10_Objektstatus: 0_Nytt/ New; 08_Status: S4; 07_Fase: F90; 04_Kontrakt: 182251; 06_Omrade: TH; 02_Prosjekt: A146091-1; 03_Ansvar: 181605; 09_Arbeidspakke: AP01; 01_Lufthavnkode: ENGM
Tekla Status - Status: Unknown; Assigned By: Me; Actual: 1; Scheduled: 0; Erection Comment: Missing Value
Pset_BeamCommon - LoadBearing: no; Reference: DSB-0(?)
Tekla Common - Grade: S355; Name: STÅLBJELKE; Part mark: DSB-0(?); Assembly mark: SB-0(?); Profile: IPE220; Class: 330
ePset_SimplebimBasicQuantities - Width (Simplebim): 110 mm; Height (Simplebim): 220 mm; Length (Simplebim): 2318 mm
ePset_Simplebim - Assembly Level: Leaf
ePset_LocationTool - Splitting: RESULT
Name | In | 05_ID-nummer | Top elevation | Bottom elevation | Weight, as steel (Simplebim) (kg) | Volume, net (Simplebim) (m3) | Area, sides, net (Simplebim) (m2)
8 x STÅLBJELKE | F | +TH=223.017 | +213.420 | +213.200 | 58.5361 | 0.00745683 | 1.90354
4 x STÅLBJELKE | D | +TH=223.013 | +210.040 | +209.820 | 58.8795 | 0.00750058 | 1.91606
6 x STÅLBJELKE | D | +TH=223.013 | +210.040 | +209.820 | 59.1018 | 0.00752889 | 1.92565

# IfcBeam: IPE270 (4)
In: D
Description: IPE270
Tekla Common - Grade: S355; Name: STÅLBJELKE; Assembly mark: SB-11844(?); Profile: IPE270; Part mark: DSB-5549(?); Class: 330
ePset_SimplebimBasicQuantities - Height (Simplebim): 270 mm
Pset_BeamCommon - LoadBearing: no; Reference: DSB-5549(?)
Tekla Status - Status: Unknown; Assigned By: Me; Actual: 1; Scheduled: 0; Erection Comment: Missing Value
AVINOR - 07_Fase: F90; 02_Prosjekt: T1; 04_Kontrakt: FDV; 03_Ansvar: FDV; 08_Status: S2; 10_Objektstatus: 3_Eksisterende/ Existing; 06_Omrade: TH; 13_Undersortering: Eksisterende udokumentert; 11_Delmengde: BHST1; 01_Lufthavnkode: ENGM
ePset_Simplebim - Assembly Level: Leaf
Name | Top elevation | Bottom elevation | Volume, net (Simplebim) (m3) | Area, sides, net (Simplebim) (m2) | Weight, as steel (Simplebim) (kg) | Width (Simplebim) (mm) | Length (Simplebim) (mm) | Splitting
2 x STÅLBJELKE | +209.535 | +209.265 | 0.0352263 | 7.98194 | 276.527 | 135 | 7659.5 | ORIGINAL | Material: STEEL/S355; Tekla Quantity - VOLUME_NET: 0.03371 m3; AREA_GROSS: 7.97354 m2; VOLUME_GROSS: 0.03516 m3; AREA_NET: 8.17996 m2; WEIGTH_GROSS: 275.983 kg; Width: 135 mm; Heigth: 270 mm; Length: 7659.5 mm; WEIGTH_NET: 264.641 kg
2 x STÅLBJELKE | +209.495 | +209.225 | 0.0114338 | 2.59701 | 89.7555 | 136 | 2486 | RESULT

# IfcBeam: L40*4 (2)
In: G
Description: L40*4
AVINOR - 07_Fase: F90; 02_Prosjekt: T1; 04_Kontrakt: FDV; 03_Ansvar: FDV; 08_Status: S2; 10_Objektstatus: 3_Eksisterende/ Existing; 06_Omrade: TH; 01_Lufthavnkode: ENGM
Tekla Common - Grade: S355; Profile: L40*4; Top elevation: +213.700; Name: STÅLBJELKE; Assembly mark: SB-10449(?); Bottom elevation: +213.660; Part mark: DSB-5519(?); Class: 330
ePset_LocationTool - Splitting: RESULT
Tekla Status - Status: Unknown; Assigned By: Me; Actual: 1; Scheduled: 0; Erection Comment: Missing Value
Pset_BeamCommon - LoadBearing: no; Reference: DSB-5519(?)
ePset_Simplebim - Assembly Level: Leaf
ePset_SimplebimBasicQuantities - Weight, as steel (Simplebim): 36.9836 kg; Volume, net (Simplebim): 0.00471128 m3; Width (Simplebim): 40 mm; Height (Simplebim): 40 mm; Length (Simplebim): 15299 mm; Area, sides, net (Simplebim): 2.36915 m2

# IfcBeam: L70*7 (2)
In: F
Description: L70*7; Material: STEEL/AISI304
Pset_BeamCommon - LoadBearing: no; Reference: DSSP-7689
AVINOR - 10_Objektstatus: 0_Nytt/ New; 08_Status: S4; 07_Fase: F90; 04_Kontrakt: 182251; 06_Omrade: TH; 05_ID-nummer: +TH=223.017; 02_Prosjekt: A146091-1; 03_Ansvar: 181605; 09_Arbeidspakke: AP01; 01_Lufthavnkode: ENGM
Tekla Quantity - AREA_GROSS: 0.03264 m2; VOLUME_GROSS: 0.00011 m3; VOLUME_NET: 0.00011 m3; AREA_NET: 0.0356 m2; WEIGTH_NET: 0.85879 kg; WEIGTH_GROSS: 0.88548 kg; Length: 120 mm; Width: 70 mm; Heigth: 70 mm
ePset_LocationTool - Splitting: ORIGINAL
Tekla Status - Status: Unknown; Assigned By: Me; Actual: 1; Scheduled: 0; Erection Comment: Missing Value
Tekla Common - Profile: L70*7; Top elevation: +213.795; Bottom elevation: +213.725; Class: 380; Grade: AISI304; Assembly mark: SSP-691; Part mark: DSSP-7689; Name: STÅLSPESIAL
ePset_SimplebimBasicQuantities - Area, sides, net (Simplebim): 0.0346383 m2; Volume, net (Simplebim): 0.000110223 m3; Weight, as steel (Simplebim): 0.865254 kg; Length (Simplebim): 120 mm; Width (Simplebim): 70 mm; Height (Simplebim): 70 mm
ePset_Simplebim - Assembly Level: Leaf

# IfcBeam: PL10*100 (4)
In: F
Description: PL10*100; Material: STEEL/S355
Tekla Quantity - VOLUME_GROSS: 0.00011 m3; VOLUME_NET: 0.00011 m3; WEIGTH_NET: 0.82425 kg; WEIGTH_GROSS: 0.82425 kg; Width: 10 mm; Heigth: 100 mm; Length: 105 mm; AREA_GROSS: 0.0251 m2; AREA_NET: 0.0251 m2
ePset_LocationTool - Splitting: ORIGINAL
Pset_BeamCommon - Reference: DSSP-7649; LoadBearing: no
Tekla Common - Grade: S355; Bottom elevation: +213.550; Part mark: DSSP-7649; Class: 380; Assembly mark: SSP-694; Profile: PL10*100; Top elevation: +213.650; Name: STÅLSPESIAL
ePset_SimplebimBasicQuantities - Weight, as steel (Simplebim): 0.82425 kg; Width (Simplebim): 10 mm; Height (Simplebim): 100 mm; Length (Simplebim): 105 mm; Area, sides, net (Simplebim): 0.0251 m2; Volume, net (Simplebim): 0.000105 m3
AVINOR - 10_Objektstatus: 0_Nytt/ New; 08_Status: S4; 07_Fase: F90; 04_Kontrakt: 182251; 06_Omrade: TH; 05_ID-nummer: +TH=223.017; 02_Prosjekt: A146091-1; 03_Ansvar: 181605; 09_Arbeidspakke: AP01; 01_Lufthavnkode: ENGM
Tekla Status - Status: Unknown; Assigned By: Me; Actual: 1; Scheduled: 0; Erection Comment: Missing Value
ePset_Simplebim - Assembly Level: Leaf

# IfcBeam: PL10*110, STÅLBJELKE
In: G
Description: PL10*110; Material: STEEL/S355
Tekla Common - Grade: S355; Name: STÅLBJELKE; Bottom elevation: +213.170; Part mark: DSB-5108(?); Profile: PL10*110; Class: 330; Assembly mark: SB-10478(?); Top elevation: +213.280
AVINOR - 07_Fase: F90; 02_Prosjekt: T1; 04_Kontrakt: FDV; 03_Ansvar: FDV; 08_Status: S2; 10_Objektstatus: 3_Eksisterende/ Existing; 06_Omrade: TH; 01_Lufthavnkode: ENGM
ePset_SimplebimBasicQuantities - Width (Simplebim): 10 mm; Height (Simplebim): 110 mm; Length (Simplebim): 315 mm; Weight, as steel (Simplebim): 2.56695 kg; Volume, net (Simplebim): 0.000327 m3; Area, sides, net (Simplebim): 0.0739 m2
Pset_BeamCommon - LoadBearing: no; Reference: DSB-5108(?)
ePset_LocationTool - Splitting: ORIGINAL
Tekla Status - Status: Unknown; Assigned By: Me; Actual: 1; Scheduled: 0; Erection Comment: Missing Value
Tekla Quantity - VOLUME_NET: 0.00034 m3; VOLUME_GROSS: 0.00034 m3; AREA_GROSS: 0.03465 m2; Width: 10 mm; Heigth: 110 mm; Length: 315 mm; WEIGTH_NET: 2.56695 kg; WEIGTH_GROSS: 2.72003 kg; AREA_NET: 0.0739 m2
ePset_Simplebim - Assembly Level: Leaf

# IfcBeam: PL10*120 (4)
In: F
Description: PL10*120; Material: STEEL/S355
Tekla Common - Grade: S355; Bottom elevation: +213.540; Class: 380; Assembly mark: SSP-691; Part mark: DSSP-7687; Profile: PL10*120; Top elevation: +213.660; Name: STÅLSPESIAL
Pset_BeamCommon - LoadBearing: no; Reference: DSSP-7687
ePset_SimplebimBasicQuantities - Area, sides, net (Simplebim): 0.0375 m2; Weight, as steel (Simplebim): 1.2717 kg; Width (Simplebim): 10 mm; Height (Simplebim): 120 mm; Length (Simplebim): 135 mm; Volume, net (Simplebim): 0.000162 m3
AVINOR - 10_Objektstatus: 0_Nytt/ New; 08_Status: S4; 07_Fase: F90; 04_Kontrakt: 182251; 06_Omrade: TH; 05_ID-nummer: +TH=223.017; 02_Prosjekt: A146091-1; 03_Ansvar: 181605; 09_Arbeidspakke: AP01; 01_Lufthavnkode: ENGM
Tekla Status - Status: Unknown; Assigned By: Me; Actual: 1; Scheduled: 0; Erection Comment: Missing Value
Tekla Quantity - AREA_GROSS: 0.0375 m2; AREA_NET: 0.0375 m2; VOLUME_NET: 0.00015 m3; VOLUME_GROSS: 0.00015 m3; WEIGTH_NET: 1.2717 kg; WEIGTH_GROSS: 1.2717 kg; Width: 10 mm; Heigth: 120 mm; Length: 135 mm
ePset_LocationTool - Splitting: ORIGINAL
ePset_Simplebim - Assembly Level: Leaf

# IfcBeam: PL10*150 (2)
In: F
Description: PL10*150; Material: STEEL/S355
AVINOR - 07_Fase: F90; 02_Prosjekt: T1; 04_Kontrakt: FDV; 03_Ansvar: FDV; 08_Status: S2; 10_Objektstatus: 3_Eksisterende/ Existing; 06_Omrade: TH; 01_Lufthavnkode: ENGM
Tekla Quantity - AREA_GROSS: 0.03 m2; VOLUME_NET: 0.0003 m3; VOLUME_GROSS: 0.0003 m3; Width: 10 mm; Length: 200 mm; Heigth: 150 mm; AREA_NET: 0.067 m2; WEIGTH_NET: 2.355 kg; WEIGTH_GROSS: 2.355 kg
ePset_SimplebimBasicQuantities - Volume, net (Simplebim): 0.0003 m3; Height (Simplebim): 10 mm; Length (Simplebim): 200 mm; Width (Simplebim): 150 mm; Area, sides, net (Simplebim): 0.067 m2; Weight, as steel (Simplebim): 2.355 kg
Tekla Common - Top elevation: +209.765; Bottom elevation: +209.755; Grade: S355; Name: INNSTØPNGODS; Part mark: DINN-190; Assembly mark: INN-155; Class: 371; Profile: PL10*150
ePset_LocationTool - Splitting: ORIGINAL
Tekla Status - Status: Unknown; Assigned By: Me; Actual: 1; Scheduled: 0; Erection Comment: Missing Value
Pset_BeamCommon - Reference: DINN-190; LoadBearing: no
ePset_Simplebim - Assembly Level: Leaf

# IfcBeam: PL10*160 (2)
In: G
Description: PL10*160; Material: STEEL/S355J0
AVINOR - 07_Fase: F90; 02_Prosjekt: T1; 04_Kontrakt: FDV; 03_Ansvar: FDV; 08_Status: S2; 10_Objektstatus: 3_Eksisterende/ Existing; 06_Omrade: TH; 01_Lufthavnkode: ENGM
Tekla Common - Name: STÅLBJELKE; Bottom elevation: +213.292; Assembly mark: SB-12403(?); Grade: S355J0; Part mark: DSS-0(?); Profile: PL10*160; Top elevation: +213.552; Class: 330
Pset_BeamCommon - LoadBearing: no; Reference: DSS-0(?)
ePset_SimplebimBasicQuantities - Weight, as steel (Simplebim): 3.2656 kg; Area, sides, net (Simplebim): 0.0916 m2; Width (Simplebim): 10 mm; Length (Simplebim): 160 mm; Height (Simplebim): 260 mm; Volume, net (Simplebim): 0.000416 m3
ePset_LocationTool - Splitting: ORIGINAL
Tekla Status - Status: Unknown; Assigned By: Me; Actual: 1; Scheduled: 0; Erection Comment: Missing Value
Tekla Quantity - WEIGTH_GROSS: 3.2656 kg; WEIGTH_NET: 3.2656 kg; VOLUME_NET: 0.00041 m3; VOLUME_GROSS: 0.00041 m3; AREA_GROSS: 0.0916 m2; AREA_NET: 0.0916 m2; Width: 10 mm; Heigth: 160 mm; Length: 260 mm
ePset_Simplebim - Assembly Level: Leaf

# IfcBeam: PL10*200, INNSTØPNGODS
In: F
Description: PL10*200; Material: STEEL/S355
AVINOR - 07_Fase: F90; 02_Prosjekt: T1; 04_Kontrakt: FDV; 03_Ansvar: FDV; 08_Status: S2; 10_Objektstatus: 3_Eksisterende/ Existing; 06_Omrade: TH; 01_Lufthavnkode: ENGM
Tekla Common - Grade: S355; Assembly mark: INN-161; Name: INNSTØPNGODS; Profile: PL10*200; Part mark: DINN-195; Class: 371; Bottom elevation: +209.570; Top elevation: +209.580
Tekla Quantity - VOLUME_GROSS: 0.00039 m3; VOLUME_NET: 0.00039 m3; WEIGTH_NET: 3.14 kg; WEIGTH_GROSS: 3.14 kg; AREA_NET: 0.088 m2; Width: 10 mm; Heigth: 200 mm; Length: 200 mm; AREA_GROSS: 0.04 m2
ePset_SimplebimBasicQuantities - Weight, as steel (Simplebim): 3.14 kg; Height (Simplebim): 200 mm; Volume, net (Simplebim): 0.0004 m3; Width (Simplebim): 10 mm; Length (Simplebim): 200 mm; Area, sides, net (Simplebim): 0.088 m2
Pset_BeamCommon - Reference: DINN-195; LoadBearing: no
Tekla Status - Status: Unknown; Assigned By: Me; Actual: 1; Scheduled: 0; Erection Comment: Missing Value
ePset_LocationTool - Splitting: ORIGINAL
ePset_Simplebim - Assembly Level: Leaf

# IfcBeam: PL10*210 (3)
In: G
Description: PL10*210; Material: STEEL/S355
AVINOR - 07_Fase: F90; 02_Prosjekt: T1; 04_Kontrakt: FDV; 03_Ansvar: FDV; 08_Status: S2; 10_Objektstatus: 3_Eksisterende/ Existing; 06_Omrade: TH; 01_Lufthavnkode: ENGM
Tekla Quantity - AREA_NET: 0.12906 m2; WEIGTH_GROSS: 5.44012 kg; Length: 330.004 mm; WEIGTH_NET: 4.66296 kg; AREA_GROSS: 0.0693 m2; Width: 10 mm; Heigth: 210 mm; VOLUME_GROSS: 0.00059 m3; VOLUME_NET: 0.00059 m3
Pset_BeamCommon - LoadBearing: no; Reference: DSB-17468(?)
ePset_SimplebimBasicQuantities - Length (Simplebim): 330.004 mm; Area, sides, net (Simplebim): 0.129056 m2; Volume, net (Simplebim): 0.000594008 m3; Weight, as steel (Simplebim): 4.66296 kg; Width (Simplebim): 10 mm; Height (Simplebim): 210 mm
Tekla Status - Status: Unknown; Assigned By: Me; Actual: 1; Scheduled: 0; Erection Comment: Missing Value
ePset_LocationTool - Splitting: ORIGINAL
Tekla Common - Grade: S355; Top elevation: +213.570; Name: STÅLBJELKE; Profile: PL10*210; Bottom elevation: +213.360; Assembly mark: SB-10449(?); Part mark: DSB-17468(?); Class: 330
ePset_Simplebim - Assembly Level: Leaf

# IfcBeam: PL10*50 (4)
In: G
Description: PL10*50; Material: STEEL/S355
AVINOR - 07_Fase: F90; 02_Prosjekt: T1; 04_Kontrakt: FDV; 03_Ansvar: FDV; 08_Status: S2; 10_Objektstatus: 3_Eksisterende/ Existing; 06_Omrade: TH; 01_Lufthavnkode: ENGM
ePset_SimplebimBasicQuantities - Volume, net (Simplebim): 0.000025 m3; Area, sides, net (Simplebim): 0.007 m2; Height (Simplebim): 10 mm; Width (Simplebim): 50 mm; Length (Simplebim): 50 mm; Weight, as steel (Simplebim): 0.19625 kg
Tekla Common - Grade: S355; Name: STÅLBJELKE; Part mark: DSB-17592(?); Profile: PL10*50; Top elevation: +213.410; Bottom elevation: +213.400; Class: 330; Assembly mark: SB-10478(?)
ePset_LocationTool - Splitting: ORIGINAL
Tekla Quantity - AREA_NET: 0.007 m2; Width: 10 mm; Heigth: 50 mm; Length: 50 mm; WEIGTH_NET: 0.19625 kg; WEIGTH_GROSS: 0.19625 kg; VOLUME_GROSS: 0.00003 m3; VOLUME_NET: 0.00003 m3; AREA_GROSS: 0.0025 m2
Tekla Status - Status: Unknown; Assigned By: Me; Actual: 1; Scheduled: 0; Erection Comment: Missing Value
Pset_BeamCommon - Reference: DSB-17592(?); LoadBearing: no
ePset_Simplebim - Assembly Level: Leaf

# IfcBeam: PL10*76 (4)
In: G
Description: PL10*76; Material: STEEL/S355
AVINOR - 07_Fase: F90; 02_Prosjekt: T1; 04_Kontrakt: FDV; 03_Ansvar: FDV; 08_Status: S2; 10_Objektstatus: 3_Eksisterende/ Existing; 06_Omrade: TH; 01_Lufthavnkode: ENGM
Tekla Status - Status: Unknown; Assigned By: Me; Actual: 1; Scheduled: 0; Erection Comment: Missing Value
ePset_LocationTool - Splitting: ORIGINAL
ePset_SimplebimBasicQuantities - Area, sides, net (Simplebim): 0.0382388 m2; Volume, net (Simplebim): 0.000162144 m3; Height (Simplebim): 220.8 mm; Weight, as steel (Simplebim): 1.27283 kg; Width (Simplebim): 10 mm; Length (Simplebim): 75.5 mm
Tekla Common - Grade: S355; Name: STÅLBJELKE; Bottom elevation: +213.170; Part mark: DSB-17516(?); Top elevation: +213.390; Profile: PL10*76; Class: 330; Assembly mark: SB-10478(?)
Tekla Quantity - WEIGTH_NET: 1.27283 kg; Length: 220.8 mm; AREA_GROSS: 0.01667 m2; VOLUME_NET: 0.00015 m3; VOLUME_GROSS: 0.00015 m3; WEIGTH_GROSS: 1.30863 kg; Width: 10 mm; Heigth: 75.5 mm; AREA_NET: 0.03824 m2
Pset_BeamCommon - Reference: DSB-17516(?); LoadBearing: no
ePset_Simplebim - Assembly Level: Leaf

# IfcBeam: PL12*140 (4)
In: F
Description: PL12*140; Material: STEEL/S355
Pset_BeamCommon - LoadBearing: no
ePset_LocationTool - Splitting: ORIGINAL
Tekla Quantity - WEIGTH_GROSS: 1.45068 kg; WEIGTH_NET: 1.45068 kg; VOLUME_NET: 0.00018 m3; VOLUME_GROSS: 0.00018 m3; AREA_NET: 0.0368 m2; AREA_GROSS: 0.0368 m2; Width: 12 mm; Length: 110 mm; Heigth: 140 mm
ePset_SimplebimBasicQuantities - Volume, net (Simplebim): 0.0001848 m3; Weight, as steel (Simplebim): 1.45068 kg; Area, sides, net (Simplebim): 0.0368 m2; Height (Simplebim): 12 mm; Width (Simplebim): 110 mm; Length (Simplebim): 140 mm
Tekla Status - Status: Unknown; Assigned By: Me; Actual: 1; Scheduled: 0; Erection Comment: Missing Value
Tekla Common - Grade: S355; Profile: PL12*140
AVINOR - 10_Objektstatus: 0_Nytt/ New; 08_Status: S4; 07_Fase: F90; 04_Kontrakt: 182251; 06_Omrade: TH; 02_Prosjekt: A146091-1; 03_Ansvar: 181605; 09_Arbeidspakke: AP01; 01_Lufthavnkode: ENGM
ePset_Simplebim - Assembly Level: Leaf
Name | Reference = Part mark | Bottom elevation | Top elevation | Assembly mark | Class | Name | 05_ID-nummer
2 x STÅLSØYLE | 0(?) | +213.096 | +213.108 | SS-0(?) | 320 | STÅLSØYLE | +TH=222.012
2 x STÅLSPESIAL | DSSP-7666 | +213.108 | +213.120 | SSP-714 | 380 | STÅLSPESIAL | +TH=223.017

# IfcBeam: PL12*200 (4)
In: F
Description: PL12*200; Material: STEEL/S355
Pset_BeamCommon - Reference: 0(?); LoadBearing: no
Tekla Common - Grade: S355; Part mark: 0(?); Assembly mark: SS-0(?); Class: 320; Profile: PL12*200; Name: STÅLSØYLE
Tekla Status - Status: Unknown; Assigned By: Me; Actual: 1; Scheduled: 0; Erection Comment: Missing Value
AVINOR - 10_Objektstatus: 0_Nytt/ New; 08_Status: S4; 07_Fase: F90; 04_Kontrakt: 182251; 06_Omrade: TH; 05_ID-nummer: +TH=222.012; 02_Prosjekt: A146091-1; 03_Ansvar: 181605; 09_Arbeidspakke: AP01; 01_Lufthavnkode: ENGM
Tekla Quantity - Width: 12 mm; Heigth: 200 mm
ePset_LocationTool - Splitting: ORIGINAL
ePset_SimplebimBasicQuantities - Height (Simplebim): 12 mm; Width (Simplebim): 200 mm
ePset_Simplebim - Assembly Level: Leaf
Name | Bottom elevation | Top elevation | AREA_GROSS (m2) = AREA_NET (m2) | VOLUME_NET (m3) = VOLUME_GROSS (m3) | WEIGTH_GROSS (kg) = WEIGTH_NET (kg) = Weight, as steel (Simplebim) (kg) | Length (mm) = Length (Simplebim) (mm) | Volume, net (Simplebim) (m3) | Area, sides, net (Simplebim) (m2)
2 x STÅLSØYLE | +213.108 | +213.120 | 0.12776 | 0.0007 | 5.4636 | 290 | 0.000696 | 0.12776
2 x STÅLSØYLE | +210.040 | +210.052 | 0.10147 | 0.00055 | 4.29552 | 228 | 0.0005472 | 0.101472

# IfcBeam: PL15*200, STÅLBJELKE
In: G
Description: PL15*200; Material: STEEL/S355
ePset_SimplebimBasicQuantities - Weight, as steel (Simplebim): 5.8875 kg; Volume, net (Simplebim): 0.00075 m3; Area, sides, net (Simplebim): 0.1135 m2; Height (Simplebim): 15 mm; Width (Simplebim): 200 mm; Length (Simplebim): 250 mm
AVINOR - 07_Fase: F90; 02_Prosjekt: T1; 04_Kontrakt: FDV; 03_Ansvar: FDV; 08_Status: S2; 10_Objektstatus: 3_Eksisterende/ Existing; 06_Omrade: TH; 01_Lufthavnkode: ENGM
Tekla Common - Grade: S355; Name: STÅLBJELKE; Profile: PL15*200; Part mark: DSB-5124(?); Top elevation: +213.295; Class: 330; Assembly mark: SB-10478(?); Bottom elevation: +213.280
Tekla Status - Status: Unknown; Assigned By: Me; Actual: 1; Scheduled: 0; Erection Comment: Missing Value
ePset_LocationTool - Splitting: ORIGINAL
Tekla Quantity - VOLUME_NET: 0.00075 m3; VOLUME_GROSS: 0.00075 m3; WEIGTH_GROSS: 5.8875 kg; WEIGTH_NET: 5.8875 kg; AREA_GROSS: 0.05 m2; AREA_NET: 0.1135 m2; Width: 15 mm; Heigth: 200 mm; Length: 250 mm
Pset_BeamCommon - Reference: DSB-5124(?); LoadBearing: no
ePset_Simplebim - Assembly Level: Leaf

# IfcBeam: PL16*140 (4)
In: D
Description: PL16*140; Material: STEEL/S355
AVINOR - 07_Fase: F90; 02_Prosjekt: T1; 04_Kontrakt: FDV; 03_Ansvar: FDV; 08_Status: S2; 10_Objektstatus: 3_Eksisterende/ Existing; 06_Omrade: TH; 01_Lufthavnkode: ENGM
ePset_SimplebimBasicQuantities - Area, sides, net (Simplebim): 0.0838616 m2; Weight, as steel (Simplebim): 4.49397 kg; Width (Simplebim): 16 mm; Length (Simplebim): 140 mm; Height (Simplebim): 262 mm; Volume, net (Simplebim): 0.00057248 m3
Tekla Common - Grade: S355; Name: STÅLBJELKE; Profile: PL16*140; Assembly mark: SB-11844(?); Top elevation: +209.371; Bottom elevation: +209.109; Class: 330; Part mark: DSB-19646(?)
Tekla Status - Status: Unknown; Assigned By: Me; Actual: 1; Scheduled: 0; Erection Comment: Missing Value
Pset_BeamCommon - LoadBearing: no; Reference: DSB-19646(?)
Tekla Quantity - VOLUME_GROSS: 0.00057 m3; VOLUME_NET: 0.00057 m3; AREA_GROSS: 0.03668 m2; WEIGTH_NET: 4.49397 kg; Width: 16 mm; Heigth: 140 mm; Length: 262 mm; WEIGTH_GROSS: 4.60701 kg; AREA_NET: 0.08386 m2
ePset_LocationTool - Splitting: ORIGINAL
ePset_Simplebim - Assembly Level: Leaf

# IfcBeam: PL30*300 (3)
In: D
Description: PL30*300; Material: STEEL/S355
ePset_LocationTool - Splitting: ORIGINAL
ePset_SimplebimBasicQuantities - Area, sides, net (Simplebim): 0.595119 m2; Length (Simplebim): 875.863 mm; Volume, net (Simplebim): 0.00786918 m3; Height (Simplebim): 30 mm; Width (Simplebim): 300 mm; Weight, as steel (Simplebim): 61.773 kg
AVINOR - 10_Objektstatus: 0_Nytt/ New; 08_Status: S4; 07_Fase: F90; 05_ID-nummer: +TH=223.009; 04_Kontrakt: 182251; 06_Omrade: TH; 02_Prosjekt: A146091-1; 03_Ansvar: 181605; 09_Arbeidspakke: AP01; 01_Lufthavnkode: ENGM
Tekla Status - Status: Unknown; Assigned By: Me; Actual: 1; Scheduled: 0; Erection Comment: Missing Value
Tekla Quantity - WEIGTH_NET: 61.773 kg; VOLUME_NET: 0.00787 m3; VOLUME_GROSS: 0.00787 m3; WEIGTH_GROSS: 61.8798 kg; Length: 875.863 mm; AREA_GROSS: 0.59512 m2; AREA_NET: 0.59512 m2; Width: 30 mm; Heigth: 300 mm
Pset_BeamCommon - LoadBearing: no; Reference: DSB-0(?)
Tekla Common - Grade: S355; Bottom elevation: +210.010; Top elevation: +210.040; Name: STÅLBJELKE; Part mark: DSB-0(?); Assembly mark: SB-0(?); Profile: PL30*300; Class: 330
ePset_Simplebim - Assembly Level: Leaf

# IfcBeam: PL30*330, STÅLSPESIAL
In: D
Description: PL30*330; Material: STEEL/S355
ePset_SimplebimBasicQuantities - Volume, net (Simplebim): 0.010296 m3; Weight, as steel (Simplebim): 80.8236 kg; Area, sides, net (Simplebim): 0.7686 m2; Height (Simplebim): 30 mm; Width (Simplebim): 330 mm; Length (Simplebim): 1040 mm
Pset_BeamCommon - LoadBearing: no; Reference: DSSP-7657
Tekla Common - Grade: S355; Class: 380; Assembly mark: SSP-706; Profile: PL30*330; Name: STÅLSPESIAL; Part mark: DSSP-7657; Top elevation: +209.540; Bottom elevation: +209.510
AVINOR - 10_Objektstatus: 0_Nytt/ New; 08_Status: S4; 07_Fase: F90; 04_Kontrakt: 182251; 06_Omrade: TH; 05_ID-nummer: +TH=223.013; 02_Prosjekt: A146091-1; 03_Ansvar: 181605; 09_Arbeidspakke: AP01; 01_Lufthavnkode: ENGM
Tekla Quantity - WEIGTH_GROSS: 80.8236 kg; WEIGTH_NET: 80.8236 kg; VOLUME_GROSS: 0.0103 m3; VOLUME_NET: 0.0103 m3; AREA_GROSS: 0.7686 m2; AREA_NET: 0.7686 m2; Width: 30 mm; Heigth: 330 mm; Length: 1040 mm
Tekla Status - Status: Unknown; Assigned By: Me; Actual: 1; Scheduled: 0; Erection Comment: Missing Value
ePset_LocationTool - Splitting: ORIGINAL
ePset_Simplebim - Assembly Level: Leaf

# IfcBeam: PL5*100 (4)
In: F
Description: PL5*100; Material: STEEL/AISI304
ePset_LocationTool - Splitting: ORIGINAL
Tekla Common - Bottom elevation: +213.550; Name: STÅLMONTASJE; Class: 370; Profile: PL5*100; Grade: AISI304; Top elevation: +213.650; Part mark: DSM-683; Assembly mark: SM-0(?)
Tekla Quantity - VOLUME_NET: 0.00005 m3; VOLUME_GROSS: 0.00005 m3; AREA_GROSS: 0.022 m2; AREA_NET: 0.022 m2; Width: 5 mm; Heigth: 100 mm; Length: 100 mm; WEIGTH_NET: 0.3925 kg; WEIGTH_GROSS: 0.3925 kg
AVINOR - 10_Objektstatus: 0_Nytt/ New; 08_Status: S4; 07_Fase: F90; 04_Kontrakt: 182251; 06_Omrade: TH; 05_ID-nummer: +TH=223.017; 02_Prosjekt: A146091-1; 03_Ansvar: 181605; 09_Arbeidspakke: AP01; 01_Lufthavnkode: ENGM
Tekla Status - Status: Unknown; Assigned By: Me; Actual: 1; Scheduled: 0; Erection Comment: Missing Value
ePset_SimplebimBasicQuantities - Volume, net (Simplebim): 0.00005 m3; Area, sides, net (Simplebim): 0.022 m2; Width (Simplebim): 5 mm; Height (Simplebim): 100 mm; Length (Simplebim): 100 mm; Weight, as steel (Simplebim): 0.3925 kg
Pset_BeamCommon - LoadBearing: no; Reference: DSM-683
ePset_Simplebim - Assembly Level: Leaf

# IfcBeam: PL5*140 (2)
In: G
Description: PL5*140; Material: STEEL/S355J0
AVINOR - 07_Fase: F90; 02_Prosjekt: T1; 04_Kontrakt: FDV; 03_Ansvar: FDV; 08_Status: S2; 10_Objektstatus: 3_Eksisterende/ Existing; 06_Omrade: TH; 01_Lufthavnkode: ENGM
Pset_BeamCommon - LoadBearing: no; Reference: DSS-0(?)
ePset_SimplebimBasicQuantities - Weight, as steel (Simplebim): 1.41221 kg; Volume, net (Simplebim): 0.0001799 m3; Area, sides, net (Simplebim): 0.07593 m2; Width (Simplebim): 5 mm; Length (Simplebim): 140 mm; Height (Simplebim): 257 mm
ePset_LocationTool - Splitting: ORIGINAL
Tekla Status - Status: Unknown; Assigned By: Me; Actual: 1; Scheduled: 0; Erection Comment: Missing Value
Tekla Quantity - WEIGTH_GROSS: 1.41222 kg; WEIGTH_NET: 1.41222 kg; VOLUME_NET: 0.00018 m3; VOLUME_GROSS: 0.00018 m3; AREA_NET: 0.07593 m2; AREA_GROSS: 0.07593 m2; Width: 5 mm; Heigth: 140 mm; Length: 257 mm
Tekla Common - Top elevation: +213.550; Name: STÅLBJELKE; Assembly mark: SB-12403(?); Grade: S355J0; Bottom elevation: +213.293; Part mark: DSS-0(?); Class: 330; Profile: PL5*140
ePset_Simplebim - Assembly Level: Leaf

# IfcBeam: PLANJA70 (4)
In: F
Description: PLANJA70
Pset_BeamCommon - LoadBearing: no
ePset_SimplebimBasicQuantities - Height (Simplebim): 68 mm; Length (Simplebim): 15299 mm
AVINOR - 10_Objektstatus: 0_Nytt/ New; 08_Status: S4; 07_Fase: F90; 05_ID-nummer: +TH=261.003; 04_Kontrakt: 182251; 06_Omrade: TH; 02_Prosjekt: A146091-1; 03_Ansvar: 181605; 09_Arbeidspakke: AP01; 01_Lufthavnkode: ENGM
Tekla Status - Status: Unknown; Assigned By: Me; Actual: 1; Scheduled: 0; Erection Comment: Missing Value
ePset_LocationTool - Splitting: RESULT
Tekla Common - Profile: PLANJA70; Name: STÅLTAK; Top elevation: +213.488; Bottom elevation: +213.420; Class: 361; Grade: Steel_Undefined
ePset_Simplebim - Assembly Level: Leaf
Name | Reference = Part mark | Area, sides, net (Simplebim) (m2) | Weight, as steel (Simplebim) (kg) | Volume, net (Simplebim) (m3) | Width (Simplebim) (mm) | Assembly mark
3 x STÅLTAK | DST-965 | 34.7673 | 136.333 | 0.0173672 | 750 | ST-837
STÅLTAK | DST-966 | 27.2368 | 106.777 | 0.0136022 | 600 | ST-838

# IfcBeam: PLANNJACD45_H (3)
In: D
Description: PLANNJACD45_H
Tekla Common - Bottom elevation: +210.040; Profile: PLANNJACD45_H; Name: STÅLDEKKE; Class: 360; Top elevation: +210.086; Grade: Steel_Undefined
AVINOR - 10_Objektstatus: 0_Nytt/ New; 08_Status: S4; 07_Fase: F90; 04_Kontrakt: 182251; 06_Omrade: TH; 02_Prosjekt: A146091-1; 05_ID-nummer: +TH=251.011; 03_Ansvar: 181605; 09_Arbeidspakke: AP01; 01_Lufthavnkode: ENGM
ePset_LocationTool - Splitting: RESULT
ePset_SimplebimBasicQuantities - Height (Simplebim): 46 mm; Length (Simplebim): 15299 mm
Tekla Status - Status: Unknown; Assigned By: Me; Actual: 1; Scheduled: 0; Erection Comment: Missing Value
Pset_BeamCommon - LoadBearing: no
ePset_Simplebim - Assembly Level: Leaf
Name | Assembly mark | Part mark = Reference | Area, sides, net (Simplebim) (m2) | Weight, as steel (Simplebim) (kg) | Width (Simplebim) (mm) | Volume, net (Simplebim) (m3)
2 x STÅLDEKKE | SDE-776 | DSDE-860 | 19.8766 | 66.8225 | 448 | 0.00851243
STÅLDEKKE | SDE-778 | DSDE-862 | 16.7978 | 56.334 | 381 | 0.0071763

# IfcBeam: PLANNJACD45_V (3)
In: D
Description: PLANNJACD45_V
ePset_SimplebimBasicQuantities - Area, sides, net (Simplebim): 21.2155 m2; Weight, as steel (Simplebim): 71.289 kg; Height (Simplebim): 46 mm; Width (Simplebim): 488 mm; Length (Simplebim): 15299 mm; Volume, net (Simplebim): 0.0090814 m3
ePset_LocationTool - Splitting: RESULT
AVINOR - 10_Objektstatus: 0_Nytt/ New; 08_Status: S4; 07_Fase: F90; 04_Kontrakt: 182251; 06_Omrade: TH; 02_Prosjekt: A146091-1; 05_ID-nummer: +TH=251.011; 03_Ansvar: 181605; 09_Arbeidspakke: AP01; 01_Lufthavnkode: ENGM
Pset_BeamCommon - Reference: DSDE-861; LoadBearing: no
Tekla Status - Status: Unknown; Assigned By: Me; Actual: 1; Scheduled: 0; Erection Comment: Missing Value
Tekla Common - Bottom elevation: +210.040; Profile: PLANNJACD45_V; Part mark: DSDE-861; Assembly mark: SDE-777; Name: STÅLDEKKE; Class: 360; Top elevation: +210.086; Grade: Steel_Undefined
ePset_Simplebim - Assembly Level: Leaf

# IfcBeam: RHS100*60*6.3 (5)
In: F
Description: RHS100*60*6.3; Material: STEEL/S355
Tekla Quantity - VOLUME_GROSS: 0.00049 m3; VOLUME_NET: 0.00049 m3; Length: 265 mm; AREA_NET: 0.08536 m2; WEIGTH_NET: 3.86353 kg; Width: 60 mm; Heigth: 100 mm; AREA_GROSS: 0.08109 m2; WEIGTH_GROSS: 3.82766 kg
Pset_BeamCommon - Reference: DSSP-7648; LoadBearing: no
ePset_LocationTool - Splitting: ORIGINAL
AVINOR - 10_Objektstatus: 0_Nytt/ New; 08_Status: S4; 07_Fase: F90; 04_Kontrakt: 182251; 06_Omrade: TH; 05_ID-nummer: +TH=223.017; 02_Prosjekt: A146091-1; 03_Ansvar: 181605; 09_Arbeidspakke: AP01; 01_Lufthavnkode: ENGM
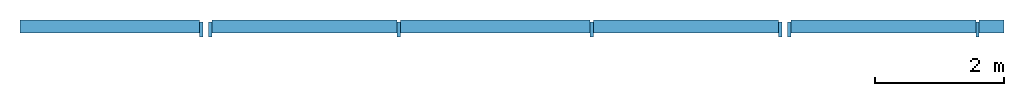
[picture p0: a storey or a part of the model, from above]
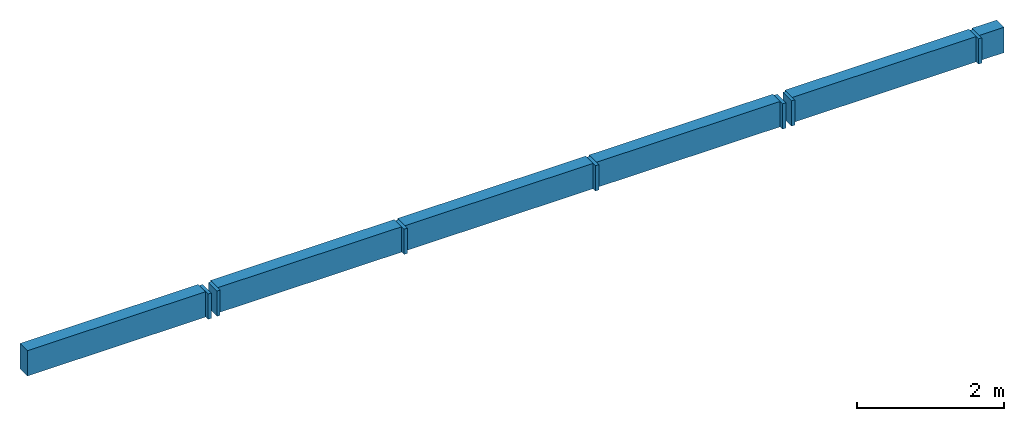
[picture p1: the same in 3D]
Properties of the parts of a building model (IFC2X3), part 2 of 7

# IfcBeam: RHS100*60*6.3 (5)
ePset_SimplebimBasicQuantities - Area, sides, net (Simplebim): 0.1481 m2; Height (Simplebim): 60 mm; Width (Simplebim): 100 mm; Length (Simplebim): 265 mm; Volume, net (Simplebim): 0.00045506 m3; Weight, as steel (Simplebim): 3.57222 kg
Tekla Status - Status: Unknown; Assigned By: Me; Actual: 1; Scheduled: 0; Erection Comment: Missing Value
Tekla Common - Grade: S355; Part mark: DSSP-7648; Class: 380; Profile: RHS100*60*6.3; Name: STÅLSPESIAL
ePset_Simplebim - Assembly Level: Leaf
Name | Bottom elevation | Assembly mark | Top elevation
2 x STÅLSPESIAL | +213.560 | SSP-691 | +213.620
3 x STÅLSPESIAL | +213.580 | SSP-693 | +213.640

# IfcBeam: RHS100*8, STÅLBJELKE
In: D
Description: RHS100*8; Material: STEEL/S355
AVINOR - 07_Fase: F90; 02_Prosjekt: T1; 04_Kontrakt: FDV; 03_Ansvar: FDV; 08_Status: S2; 10_Objektstatus: 3_Eksisterende/ Existing; 06_Omrade: TH; 01_Lufthavnkode: ENGM
Pset_BeamCommon - LoadBearing: no; Reference: DSS-0(?)
Tekla Status - Status: Unknown; Assigned By: Me; Actual: 1; Scheduled: 0; Erection Comment: Missing Value
ePset_SimplebimBasicQuantities - Width (Simplebim): 100 mm; Length (Simplebim): 100 mm; Height (Simplebim): 120 mm; Area, sides, net (Simplebim): 0.0871269 m2; Volume, net (Simplebim): 0.000326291 m3; Weight, as steel (Simplebim): 2.56138 kg
Tekla Quantity - WEIGTH_GROSS: 2.74122 kg; AREA_GROSS: 0.04596 m2; AREA_NET: 0.0512 m2; WEIGTH_NET: 2.77325 kg; VOLUME_NET: 0.00036 m3; VOLUME_GROSS: 0.00036 m3; Width: 100 mm; Heigth: 100 mm; Length: 120 mm
Tekla Common - Grade: S355; Name: STÅLBJELKE; Profile: RHS100*8; Assembly mark: SB-11844(?); Bottom elevation: +209.450; Part mark: DSS-0(?); Class: 330; Top elevation: +209.570
ePset_Simplebim - Assembly Level: Leaf
ePset_LocationTool - Splitting: ORIGINAL

# IfcBeam: RHS120*80*5 (4)
In: F
Description: RHS120*80*5
AVINOR - 07_Fase: F90; 02_Prosjekt: T1; 04_Kontrakt: FDV; 03_Ansvar: FDV; 08_Status: S2; 10_Objektstatus: 3_Eksisterende/ Existing; 06_Omrade: TH; 01_Lufthavnkode: ENGM
Pset_BeamCommon - LoadBearing: no
Tekla Common - Grade: S355; Name: STÅLBJELKE; Assembly mark: SS-578(?); Profile: RHS120*80*5; Class: 330
ePset_SimplebimBasicQuantities - Height (Simplebim): 120 mm; Width (Simplebim): 80 mm
Tekla Status - Status: Unknown; Assigned By: Me; Actual: 1; Scheduled: 0; Erection Comment: Missing Value
ePset_Simplebim - Assembly Level: Leaf
Name | Reference = Part mark | Splitting | Top elevation | Bottom elevation | Volume, net (Simplebim) (m3) | Weight, as steel (Simplebim) (kg) | Area, sides, net (Simplebim) (m2) | Length (Simplebim) (mm)
STÅLBJELKE | DSB-5598(?) | ORIGINAL | +212.510 | +212.390 | 0.00338871 | 26.6014 | 1.36024 | 1870 | Material: STEEL/S355; Tekla Quantity - VOLUME_NET: 0.00355 m3; WEIGTH_GROSS: 27.7443 kg; WEIGTH_NET: 27.891 kg; AREA_NET: 0.74348 m2; Heigth: 120 mm; Width: 80 mm; Length: 1870 mm; VOLUME_GROSS: 0.00353 m3; AREA_GROSS: 0.72743 m2
2 x STÅLBJELKE | DSB-5597(?) | RESULT | +212.510 | +212.390 | 0.00167278 | 13.1313 | 0.673294 | 923
STÅLBJELKE | DSB-5597(?) | RESULT | +211.760 | +211.640 | 0.00167278 | 13.1313 | 0.673294 | 923

# IfcBeam: RHS160*80*6.3 (3)
In: F
Description: RHS160*80*6.3
AVINOR - 07_Fase: F90; 02_Prosjekt: T1; 04_Kontrakt: FDV; 03_Ansvar: FDV; 08_Status: S2; 10_Objektstatus: 3_Eksisterende/ Existing; 06_Omrade: TH; 01_Lufthavnkode: ENGM
Pset_BeamCommon - LoadBearing: no
Tekla Common - Grade: S355; Top elevation: +213.500; Name: STÅLBJELKE; Assembly mark: SS-578(?); Bottom elevation: +213.340; Profile: RHS160*80*6.3; Class: 330
Tekla Status - Status: Unknown; Assigned By: Me; Actual: 1; Scheduled: 0; Erection Comment: Missing Value
ePset_SimplebimBasicQuantities - Width (Simplebim): 80 mm; Height (Simplebim): 160 mm
ePset_Simplebim - Assembly Level: Leaf
Name | Reference = Part mark | Splitting | Volume, net (Simplebim) (m3) | Weight, as steel (Simplebim) (kg) | Length (Simplebim) (mm) | Area, sides, net (Simplebim) (m2)
STÅLBJELKE | DSB-5619(?) | ORIGINAL | 0.00509614 | 40.0047 | 1870 | 1.6247 | Material: STEEL/S355; Tekla Quantity - WEIGTH_NET: 42.0603 kg; AREA_GROSS: 0.87142 m2; AREA_NET: 0.88832 m2; VOLUME_NET: 0.00536 m3; Width: 80 mm; Heigth: 160 mm; Length: 1870 mm; WEIGTH_GROSS: 41.8366 kg; VOLUME_GROSS: 0.00534 m3
2 x STÅLBJELKE | DSB-5618(?) | RESULT | 0.00273364 | 21.4591 | 1003 | 0.874039

# IfcBeam: RHS80*40*5, STÅLBJELKE
In: G
Description: RHS80*40*5
AVINOR - 07_Fase: F90; 02_Prosjekt: T1; 04_Kontrakt: FDV; 03_Ansvar: FDV; 08_Status: S2; 10_Objektstatus: 3_Eksisterende/ Existing; 06_Omrade: TH; 01_Lufthavnkode: ENGM
ePset_SimplebimBasicQuantities - Volume, net (Simplebim): 0.0158205 m3; Width (Simplebim): 40 mm; Height (Simplebim): 80 mm; Length (Simplebim): 15299 mm; Weight, as steel (Simplebim): 124.191 kg; Area, sides, net (Simplebim): 6.3372 m2
Tekla Common - Grade: S355; Bottom elevation: +213.580; Profile: RHS80*40*5; Name: STÅLBJELKE; Assembly mark: SB-10449(?); Top elevation: +213.660; Part mark: DSB-5516(?); Class: 330
Pset_BeamCommon - LoadBearing: no; Reference: DSB-5516(?)
ePset_LocationTool - Splitting: RESULT
Tekla Status - Status: Unknown; Assigned By: Me; Actual: 1; Scheduled: 0; Erection Comment: Missing Value
ePset_Simplebim - Assembly Level: Leaf

# IfcBeam: RHS80*5, STÅLBJELKE
In: D
Description: RHS80*5; Material: STEEL/S355
AVINOR - 07_Fase: F90; 02_Prosjekt: T1; 04_Kontrakt: FDV; 03_Ansvar: FDV; 08_Status: S2; 10_Objektstatus: 3_Eksisterende/ Existing; 06_Omrade: TH; 01_Lufthavnkode: ENGM
Tekla Common - Grade: S355; Profile: RHS80*5; Top elevation: +209.505; Name: STÅLBJELKE; Bottom elevation: +209.385; Assembly mark: SB-11844(?); Part mark: DSS-0(?); Class: 330
Pset_BeamCommon - LoadBearing: no; Reference: DSS-0(?)
ePset_LocationTool - Splitting: ORIGINAL
Tekla Status - Status: Unknown; Assigned By: Me; Actual: 1; Scheduled: 0; Erection Comment: Missing Value
Tekla Quantity - WEIGTH_NET: 1.413 kg; VOLUME_NET: 0.00018 m3; VOLUME_GROSS: 0.00018 m3; Length: 120 mm; Width: 80 mm; Heigth: 80 mm; AREA_GROSS: 0.03708 m2; WEIGTH_GROSS: 1.40358 kg; AREA_NET: 0.04 m2
ePset_SimplebimBasicQuantities - Area, sides, net (Simplebim): 0.0706797 m2; Weight, as steel (Simplebim): 1.33024 kg; Height (Simplebim): 120 mm; Width (Simplebim): 80 mm; Length (Simplebim): 80 mm; Volume, net (Simplebim): 0.000169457 m3
ePset_Simplebim - Assembly Level: Leaf

# IfcBeam: RHS80*60*4 (2)
In: F
Description: RHS80*60*4; Material: STEEL/AISI304
ePset_LocationTool - Splitting: ORIGINAL
Pset_BeamCommon - LoadBearing: no; Reference: DSSP-7686
AVINOR - 10_Objektstatus: 0_Nytt/ New; 08_Status: S4; 07_Fase: F90; 04_Kontrakt: 182251; 06_Omrade: TH; 05_ID-nummer: +TH=223.017; 02_Prosjekt: A146091-1; 03_Ansvar: 181605; 09_Arbeidspakke: AP01; 01_Lufthavnkode: ENGM
Tekla Quantity - AREA_NET: 0.0484 m2; AREA_GROSS: 0.0484 m2; WEIGTH_GROSS: 1.41086 kg; WEIGTH_NET: 1.41086 kg; Length: 171.073 mm; VOLUME_NET: 0.00018 m3; VOLUME_GROSS: 0.00018 m3; Width: 60 mm; Heigth: 80 mm
Tekla Status - Status: Unknown; Assigned By: Me; Actual: 1; Scheduled: 0; Erection Comment: Missing Value
Tekla Common - Top elevation: +213.730; Class: 380; Profile: RHS80*60*4; Grade: AISI304; Assembly mark: SSP-691; Bottom elevation: +213.665; Part mark: DSSP-7686; Name: STÅLSPESIAL
ePset_SimplebimBasicQuantities - Volume, net (Simplebim): 0.00017255 m3; Area, sides, net (Simplebim): 0.0883646 m2; Length (Simplebim): 171.073 mm; Weight, as steel (Simplebim): 1.35451 kg; Height (Simplebim): 60 mm; Width (Simplebim): 80 mm
ePset_Simplebim - Assembly Level: Leaf

# IfcBeam: T40 (5)
In: G
Description: T40; Material: STEEL/S355
Tekla Quantity - AREA_GROSS: 0.05952 m2; VOLUME_GROSS: 0.00015 m3; WEIGTH_NET: 0.98203 kg; AREA_NET: 0.05451 m2; Width: 40 mm; Heigth: 40 mm; Length: 372 mm; VOLUME_NET: 0.00012 m3; WEIGTH_GROSS: 1.10092 kg
AVINOR - 07_Fase: F90; 02_Prosjekt: T1; 04_Kontrakt: FDV; 03_Ansvar: FDV; 08_Status: S2; 10_Objektstatus: 3_Eksisterende/ Existing; 06_Omrade: TH; 01_Lufthavnkode: ENGM
ePset_SimplebimBasicQuantities - Volume, net (Simplebim): 0.000108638 m3; Weight, as steel (Simplebim): 0.852809 kg; Height (Simplebim): 40.0006 mm; Area, sides, net (Simplebim): 0.056198 m2; Length (Simplebim): 372 mm; Width (Simplebim): 40 mm
ePset_LocationTool - Splitting: ORIGINAL
Tekla Status - Status: Unknown; Assigned By: Me; Actual: 1; Scheduled: 0; Erection Comment: Missing Value
Tekla Common - Grade: S355; Profile: T40; Top elevation: +213.700; Name: STÅLBJELKE; Assembly mark: SB-10449(?); Part mark: DSB-18617(?); Bottom elevation: +213.660; Class: 330
Pset_BeamCommon - LoadBearing: no; Reference: DSB-18617(?)
ePset_Simplebim - Assembly Level: Leaf

# IfcBeam: UNP240 (3)
In: G
Description: UNP240
ePset_SimplebimBasicQuantities - Height (Simplebim): 240 mm
AVINOR - 07_Fase: F90; 02_Prosjekt: T1; 04_Kontrakt: FDV; 03_Ansvar: FDV; 08_Status: S2; 10_Objektstatus: 3_Eksisterende/ Existing; 06_Omrade: TH; 01_Lufthavnkode: ENGM
Pset_BeamCommon - LoadBearing: no; Reference: DSB-5420(?)
Tekla Common - Grade: S355; Profile: UNP240; Name: STÅLBJELKE; Bottom elevation: +213.160; Top elevation: +213.400; Class: 330; Part mark: DSB-5420(?); Assembly mark: SB-10478(?)
Tekla Status - Status: Unknown; Assigned By: Me; Actual: 1; Scheduled: 0; Erection Comment: Missing Value
ePset_Simplebim - Assembly Level: Leaf
Name | Area, sides, net (Simplebim) (m2) | Volume, net (Simplebim) (m3) | Width (Simplebim) (mm) | Length (Simplebim) (mm) | Weight, as steel (Simplebim) (kg) | Splitting
STÅLBJELKE | 6.89589 | 0.038655 | 85 | 8980 | 303.442 | ORIGINAL | Material: STEEL/S355; Tekla Quantity - AREA_NET: 7.04412 m2; WEIGTH_NET: 292.788 kg; VOLUME_GROSS: 0.03799 m3; WEIGTH_GROSS: 298.185 kg; Width: 85 mm; Heigth: 240 mm; Length: 8980 mm; AREA_GROSS: 6.9595 m2; VOLUME_NET: 0.0373 m3
STÅLBJELKE | 2.20671 | 0.0123352 | 85 | 2878 | 96.831 | RESULT
STÅLBJELKE | 2.61046 | 0.0146017 | 84 | 3401 | 114.623 | RESULT

# IfcBuildingElementProxy: A225 - Plateinnkledning bjelker - nordside:A225 - Plateinnkledning bjelker - nordside, A225 - Plateinnkledning bjelker - nordside:A225 - Plateinnkledning bjelker - nordside:45659436
In: Nivå E
Type - Material: <Unnamed>
ePset_Simplebim - Assembly Level: Leaf
Pset_BuildingElementProxyCommon - Reference: A225 - Plateinnkledning bjelker - nordside; sets with these values: 2
AVINOR - 08_Status: S4; 07_Fase: F90; 06_Omrade: TH; 03_Ansvar: 182410; 01_Lufthavnkode: ENGM
ePset_LocationTool - Splitting: RESULT
ePset_SimplebimBasicQuantities - Volume, net (Simplebim): 0.666164 m3; Area, largest surface, net (Simplebim): 0.97713 m2; Height (Simplebim): 317 mm; Thickness (Simplebim): 2640 mm; Length (Simplebim): 9105 mm
Group: Model Group:TH - Karnapper (members excluded):45660468

# IfcBuildingElementProxy: A234 - Gitter1:A241 - Gitter 350 x 350_UK_2690_offset 25 (2)
In: Nivå F - 0,7 m
Type - Material: <Unnamed>
ePset_Simplebim - Assembly Level: Leaf
ePset_SimplebimBasicQuantities - Height (Simplebim): 350 mm; Thickness (Simplebim): 350 mm
AVINOR - 08_Status: S4; 07_Fase: F90; 03_Ansvar: 182412; 06_Omrade: TH; 02_Prosjekt: A184862; 01_Lufthavnkode: ENGM
ePset_LocationTool - Splitting: ORIGINAL
Pset_QuantityTakeOff - Reference: A241 - Gitter 350 x 350_UK_2690_offset 25; sets with these values: 2
Group: Model Group:A184862 - Kiosk NSOPØ 05.235 2 (members excluded):47061109
Name (A234 - Gitter1:A241 - Gitter 350 x 350_UK_2690_offset 25:...) | Volume, net (Simplebim) (m3) | Area, largest surface, net (Simplebim) (m2) | Length (Simplebim) (mm) | 05_ID-nummer
47060593 | 0.477361 | 1.36389 | 3896.82 | +TH=243.001-IR0011
47060601 | 0.318111 | 0.908888 | 2596.82 | +TH=243.001-IR0005

# IfcBuildingElementProxy: A240 - eksisterende dekkeforkantbeslag nivå G:A240 - Eksisterende dekkeforkantbeslag - Plate - 1500 mm (13)
In: Nivå F
Type - Material: <Unnamed>
ePset_Simplebim - Assembly Level: Leaf
AVINOR - 07_Fase: F90; 03_Ansvar: FDV; 08_Status: S2; 06_Omrade: TH; 01_Lufthavnkode: ENGM
Pset_QuantityTakeOff - Reference: A240 - Eksisterende dekkeforkantbeslag - Plate - 1500 mm; sets with these values: 2
ePset_SimplebimBasicQuantities - Thickness (Simplebim): 26 mm; Height (Simplebim): 295 mm
Name (A240 - eksisterende dekkeforkantbeslag nivå G:A240 - Eksisterende dekkeforkantbeslag - Plate - 1500 mm:...) | Volume, net (Simplebim) (m3) | Area, largest surface, net (Simplebim) (m2) | Length (Simplebim) (mm) | Splitting | Group
37559248 | 0.00043065 | 0.35235 | 1305 | ORIGINAL | Model Group:A240 - eksisterende gallerivegg i pir G-2 / bak sjakt (members excluded):37559234
37559286 | 0.000189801 | 0.155292 | 575.155 | ORIGINAL | Model Group:A240 - eksisterende gallerivegg i pir G-2 / bak sjakt (members excluded):37559234
37559297 | 0.00008415 | 0.06885 | 255 | ORIGINAL | Model Group:A240 - eksisterende gallerivegg i pir G-2 / bak sjakt (members excluded):37559234
37630520 | 0.00048015 | 0.39285 | 1455 | ORIGINAL | Model Group:A240 - eksisterende gallerivegg i pir G-2 / generell (members excluded):37630519
37630530 | 0.00043065 | 0.35235 | 1305 | ORIGINAL | Model Group:A240 - eksisterende gallerivegg i pir G-2 / generell (members excluded):37630519
37630533 | 0.00048015 | 0.39285 | 1455 | ORIGINAL | Model Group:A240 - eksisterende gallerivegg i pir G-2 / generell (members excluded):37630519
37630536 | 0.00048015 | 0.39285 | 1455 | ORIGINAL | Model Group:A240 - eksisterende gallerivegg i pir G-2 / generell (members excluded):37630519
37630539 | 0.00048015 | 0.39285 | 1455 | ORIGINAL | Model Group:A240 - eksisterende gallerivegg i pir G-2 / generell (members excluded):37630519
37630542 | 0.00043065 | 0.35235 | 1305 | ORIGINAL | Model Group:A240 - eksisterende gallerivegg i pir G-2 / generell (members excluded):37630519
37630550 | 0.00008415 | 0.06885 | 255 | ORIGINAL | Model Group:A240 - eksisterende gallerivegg i pir G-2 / generell (members excluded):37630519
37630754 | 0.00048015 | 0.39285 | 1455 | ORIGINAL | Model Group:A240 - eksisterende gallerivegg i pir G-2 / generell (members excluded):37630753
37630764 | 0.00043065 | 0.35235 | 1305 | ORIGINAL | Model Group:A240 - eksisterende gallerivegg i pir G-2 / generell (members excluded):37630753
37630767 | 0.000128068 | 0.104783 | 388 | RESULT | Model Group:A240 - eksisterende gallerivegg i pir G-2 / generell (members excluded):37630753

# IfcBuildingElementProxy: A267 - FALLSIKRING VAIER - 7mm7:A267 - FALLSIKRING VAIER - 7mm, A267 - FALLSIKRING VAIER - 7mm7:A267 - FALLSIKRING VAIER - 7mm:45659860
In: Nivå G - 2,0 m
Type - Material: <Unnamed>
ePset_Simplebim - Assembly Level: Leaf
AVINOR - 08_Status: S4; 07_Fase: F90; 06_Omrade: TH; 03_Ansvar: 182410; 01_Lufthavnkode: ENGM; 05_ID-nummer: +TH=267.001-IH0016
ePset_SimplebimBasicQuantities - Volume, net (Simplebim): 0.0000839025 m3; Area, largest surface, net (Simplebim): 0.00516522 m2; Height (Simplebim): 7 mm; Thickness (Simplebim): 36 mm; Length (Simplebim): 3375 mm
ePset_LocationTool - Splitting: RESULT
Pset_BuildingElementProxyCommon - Reference: A267 - FALLSIKRING VAIER - 7mm; sets with these values: 2
Group: Model Group:TH - Karnapper (members excluded):45660468

# IfcBuildingElementProxy: A267 - FALLSIKRING VAIER - 7mm8:A267 - FALLSIKRING VAIER - 7mm, A267 - FALLSIKRING VAIER - 7mm8:A267 - FALLSIKRING VAIER - 7mm:45659881
In: Nivå G - 2,0 m
Type - Material: <Unnamed>
ePset_Simplebim - Assembly Level: Leaf
ePset_SimplebimBasicQuantities - Volume, net (Simplebim): 0.000221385 m3; Length (Simplebim): 8927 mm; Height (Simplebim): 7 mm; Thickness (Simplebim): 35.5457 mm; Area, largest surface, net (Simplebim): 0.177625 m2
AVINOR - 08_Status: S4; 07_Fase: F90; 06_Omrade: TH; 03_Ansvar: 182410; 01_Lufthavnkode: ENGM; 05_ID-nummer: +TH=267.001-IH0016
ePset_LocationTool - Splitting: ORIGINAL
Pset_BuildingElementProxyCommon - Reference: A267 - FALLSIKRING VAIER - 7mm; sets with these values: 2
Group: Model Group:TH - Karnapper (members excluded):45660468

# IfcBuildingElementProxy: A267 - FALLSIKRING VAIER - 7mm9:A267 - FALLSIKRING VAIER - 7mm, A267 - FALLSIKRING VAIER - 7mm9:A267 - FALLSIKRING VAIER - 7mm:45659902
In: Nivå G - 2,0 m
Type - Material: <Unnamed>
ePset_Simplebim - Assembly Level: Leaf
ePset_SimplebimBasicQuantities - Area, largest surface, net (Simplebim): 0.000255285 m2; Height (Simplebim): 7 mm; Thickness (Simplebim): 36 mm; Length (Simplebim): 2851 mm; Volume, net (Simplebim): 0.0000713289 m3
ePset_LocationTool - Splitting: RESULT
AVINOR - 08_Status: S4; 07_Fase: F90; 06_Omrade: TH; 03_Ansvar: 182410; 01_Lufthavnkode: ENGM; 05_ID-nummer: +TH=267.001-IH0016
Pset_BuildingElementProxyCommon - Reference: A267 - FALLSIKRING VAIER - 7mm; sets with these values: 2
Group: Model Group:TH - Karnapper (members excluded):45660468

# IfcBuildingElementProxy: B220 - konsoll eksyst pir Vest:B220 - Konsoll eksyst. pir Vest (3)
In: Nivå G - 2,0 m
Type - Material: _NSW Stål
ePset_Simplebim - Assembly Level: Leaf
Pset_BuildingElementProxyCommon - Reference: B220 - Konsoll eksyst. pir Vest; sets with these values: 2
AVINOR - 07_Fase: F90; 03_Ansvar: FDV; 08_Status: S2; 06_Omrade: TH; 01_Lufthavnkode: ENGM
ePset_LocationTool - Splitting: ORIGINAL
ePset_SimplebimBasicQuantities - Area, largest surface, net (Simplebim): 0.0594036 m2; Height (Simplebim): 269.993 mm; Thickness (Simplebim): 150.019 mm; Volume, net (Simplebim): 0.00149397 m3; Length (Simplebim): 339.998 mm
Name (B220 - konsoll eksyst pir Vest:B220 - Konsoll eksyst. pir Vest:...) | Group
37451399 | Model Group:A254 - eksisterende glassgulv i pir G ved fasade / __generell (members excluded):37451392
37451400 | Model Group:A254 - eksisterende glassgulv i pir G ved fasade / __generell (members excluded):37451392
37451487 | Model Group:A254 - eksisterende glassgulv i pir G ved fasade / __generell (members excluded):37451479

# IfcBuildingElementProxy: Stål rekkverk unit + 285 ned:B280 - Stål rekkverk unit + 285 ned (10)
In: Nivå B
Type - Material: <Unnamed>, Steel, Cast
ePset_Simplebim - Assembly Level: Leaf
ePset_SimplebimBasicQuantities - Area, largest surface, net (Simplebim): 0.038675 m2; Thickness (Simplebim): 122 mm; Length (Simplebim): 145 mm; Height (Simplebim): 455 mm; Volume, net (Simplebim): 0.000705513 m3
AVINOR - 07_Fase: F90; 03_Ansvar: FDV; 08_Status: S2; 06_Omrade: TH; 01_Lufthavnkode: ENGM
Pset_QuantityTakeOff - Reference: B280 - Stål rekkverk unit + 285 ned; sets with these values: 2
ePset_LocationTool - Splitting: RESULT
Name (Stål rekkverk unit + 285 ned:B280 - Stål rekkverk unit + 285 ned:...) | Group
37559231 | Model Group:A240 - eksisterende gallerivegg i pir G-2 / bak sjakt (members excluded):37559234
37559292 | Model Group:A240 - eksisterende gallerivegg i pir G-2 / bak sjakt (members excluded):37559234
37630499 | Model Group:A240 - eksisterende gallerivegg i pir G-2 / generell (members excluded):37630519
37630504 | Model Group:A240 - eksisterende gallerivegg i pir G-2 / generell (members excluded):37630519
37630507 | Model Group:A240 - eksisterende gallerivegg i pir G-2 / generell (members excluded):37630519
37630510 | Model Group:A240 - eksisterende gallerivegg i pir G-2 / generell (members excluded):37630519
37630545 | Model Group:A240 - eksisterende gallerivegg i pir G-2 / generell (members excluded):37630519
37630733 | Model Group:A240 - eksisterende gallerivegg i pir G-2 / generell (members excluded):37630753
37630738 | Model Group:A240 - eksisterende gallerivegg i pir G-2 / generell (members excluded):37630753
37630741 | Model Group:A240 - eksisterende gallerivegg i pir G-2 / generell (members excluded):37630753

# IfcColumn: 140*10, STÅLSØYLE
In: D
Description: 140*10; Material: STEEL/S355
ePset_Simplebim - Assembly Level: Leaf
Tekla Common - Top elevation: +209.765; Bottom elevation: +209.755; Grade: S355; Assembly mark: SS-9417(?); Class: 320; Name: STÅLSØYLE; Part mark: DSS-7176(?); Profile: 140*10
Pset_ColumnCommon - LoadBearing: no; Reference: DSS-7176(?)
AVINOR - 07_Fase: F90; 02_Prosjekt: T1; 03_Ansvar: FDV; 04_Kontrakt: FDV; 08_Status: S2; 10_Objektstatus: 3_Eksisterende/ Existing; 06_Omrade: TH; 01_Lufthavnkode: ENGM
ePset_LocationTool - Splitting: ORIGINAL
ePset_SimplebimBasicQuantities - Area, sides, net (Simplebim): 0.0056 m2; Volume, net (Simplebim): 0.000196 m3; Weight, as steel (Simplebim): 1.5386 kg; Width (Simplebim): 10 mm; Height (Simplebim): 140 mm; Depth (Simplebim): 140 mm
Tekla Status - Status: Unknown; Assigned By: Me; Actual: 1; Scheduled: 0; Erection Comment: Missing Value
Tekla Quantity - AREA_NET: 0.0448 m2; AREA_GROSS: 0.0448 m2; VOLUME_NET: 0.0002 m3; VOLUME_GROSS: 0.0002 m3; WEIGTH_NET: 1.5386 kg; WEIGTH_GROSS: 1.5386 kg; Width: 10 mm; Length: 140 mm; Heigth: 140 mm

# IfcColumn: A241 - Glassramme Book Shop:A241 - 100x40mm (8)
Type - PredefinedType: COLUMN; Material: _NSW Stål
Type - Pset_ColumnCommon - LoadBearing: yes
ePset_Simplebim - Assembly Level: Leaf
ePset_LocationTool - Splitting: ORIGINAL
AVINOR - 08_Status: S4; 07_Fase: F90; 03_Ansvar: 182412; 06_Omrade: TH; 02_Prosjekt: A184862; 01_Lufthavnkode: ENGM
ePset_SimplebimBasicQuantities - Width (Simplebim): 40 mm; Depth (Simplebim): 100 mm
Pset_ColumnCommon - Reference: A241 - 100x40mm; IsExternal: no
Pset_ReinforcementBarPitchOfColumn - Reference: A241 - 100x40mm; sets with these values: 2
Group: Model Group:A184862 - Kiosk NSOPØ 05.235 2 (members excluded):47061109
Name (A241 - Glassramme Book Shop:A241 - 100x40mm:...) | In | 05_ID-nummer | Weight, as steel (Simplebim) (kg) | Area, sides, net (Simplebim) (m2) | Height (Simplebim) (mm) | Volume, net (Simplebim) (m3)
47060602 | Nivå F - 0,7 m | +TH = 243.001- IG0037 | 6.31925 | 0.329 | 700 | 0.000805
47060602 | Nivå F | +TH = 243.001- IG0037 | 17.4682 | 0.90945 | 1935 | 0.00222525
47061044 | Nivå F - 0,7 m | +TH = 243.001- IG0037 | 6.31925 | 0.329 | 700 | 0.000805
47061044 | Nivå F | +TH = 243.001- IG0037 | 17.4682 | 0.90945 | 1935 | 0.00222525
47061053 | Nivå F - 0,7 m | +TH = 243.001- IG0037 | 6.31925 | 0.329 | 700 | 0.000805
47061053 | Nivå F | +TH = 243.001- IG0037 | 17.4682 | 0.90945 | 1935 | 0.00222525
47061062 | Nivå F - 0,7 m | +TH = 243.001- IG0036 | 6.31925 | 0.329 | 700 | 0.000805
47061062 | Nivå F | +TH = 243.001- IG0036 | 17.4682 | 0.90945 | 1935 | 0.00222525

# IfcColumn: A241 - Glassramme Book Shop:A241 - 30x27mm (4)
Type - PredefinedType: COLUMN; Material: _NSW Stål
Type - Pset_ColumnCommon - LoadBearing: yes
ePset_Simplebim - Assembly Level: Leaf
ePset_LocationTool - Splitting: ORIGINAL
ePset_SimplebimBasicQuantities - Width (Simplebim): 27 mm; Depth (Simplebim): 30 mm
AVINOR - 08_Status: S4; 07_Fase: F90; 03_Ansvar: 182412; 06_Omrade: TH; 02_Prosjekt: A184862; 01_Lufthavnkode: ENGM
Pset_ColumnCommon - IsExternal: no; Reference: A241 - 30x27mm
Pset_ReinforcementBarPitchOfColumn - Reference: A241 - 30x27mm; sets with these values: 2
Group: Model Group:A184862 - Kiosk NSOPØ 05.235 2 (members excluded):47061109
Name (A241 - Glassramme Book Shop:A241 - 30x27mm:...) | In | Area, sides, net (Simplebim) (m2) | Volume, net (Simplebim) (m3) | Weight, as steel (Simplebim) (kg) | Height (Simplebim) (mm) | 05_ID-nummer
47060594 | Nivå F - 0,7 m | 0.119 | 0.0001162 | 0.91217 | 700 | +TH = 243.001- IG0035
47060594 | Nivå F | 0.32895 | 0.00032121 | 2.5215 | 1935 | +TH = 243.001- IG0035
47060608 | Nivå F - 0,7 m | 0.119 | 0.0001162 | 0.91217 | 700 | +TH = 243.001- IG0038
47060608 | Nivå F | 0.32895 | 0.00032121 | 2.5215 | 1935 | +TH = 243.001- IG0038

# IfcColumn: A243 - Rullegardinskinner:A243 - Portskinne Book Shop (8)
Type - PredefinedType: COLUMN; Material: _NSW Stål
Type - Pset_ColumnCommon - LoadBearing: yes
ePset_Simplebim - Assembly Level: Leaf
Pset_ColumnCommon - IsExternal: no; Reference: A243 - Portskinne Book Shop
Pset_ReinforcementBarPitchOfColumn - Reference: A243 - Portskinne Book Shop; sets with these values: 2
ePset_LocationTool - Splitting: ORIGINAL
AVINOR - 08_Status: S4; 07_Fase: F90; 03_Ansvar: 182412; 06_Omrade: TH; 02_Prosjekt: A184862; 01_Lufthavnkode: ENGM
ePset_SimplebimBasicQuantities - Width (Simplebim): 40 mm; Depth (Simplebim): 100 mm
Group: Model Group:A184862 - Kiosk NSOPØ 05.235 2 (members excluded):47061109
Name (A243 - Rullegardinskinner:A243 - Portskinne Book Shop:...) | In | 05_ID-nummer | Weight, as steel (Simplebim) (kg) | Volume, net (Simplebim) (m3) | Area, sides, net (Simplebim) (m2) | Height (Simplebim) (mm)
47060599 | Nivå F - 0,7 m | +TH=243.001-IR0005 | 4.74768 | 0.0006048 | 0.3836 | 700
47060599 | Nivå F | +TH=243.001-IR0005 | 13.09 | 0.00166752 | 1.05764 | 1930
47061042 | Nivå F - 0,7 m | +TH=243.001-IR0005 | 4.74768 | 0.0006048 | 0.3836 | 700
47061042 | Nivå F | +TH=243.001-IR0005 | 13.09 | 0.00166752 | 1.05764 | 1930
47061051 | Nivå F - 0,7 m | +TH=243.001-IR0011 | 4.74768 | 0.0006048 | 0.3836 | 700
47061051 | Nivå F | +TH=243.001-IR0011 | 13.09 | 0.00166752 | 1.05764 | 1930
47061060 | Nivå F - 0,7 m | +TH=243.001-IR0011 | 4.74768 | 0.0006048 | 0.3836 | 700
47061060 | Nivå F | +TH=243.001-IR0011 | 13.09 | 0.00166752 | 1.05764 | 1930

# IfcColumn: AAJOVAL470*770 (2)
In: F
Description: AAJOVAL470*770; Material: CONCRETE/C45/55
Pset_ColumnCommon - Reference: Concrete-820; LoadBearing: no
ePset_Simplebim - Assembly Level: Leaf
Tekla Common - Name: PREFABSØYLE; Bottom elevation: +210.080; Class: 120; Part mark: Concrete-820; Top elevation: +210.350; Assembly mark: PS-370; Grade: C45/55; Profile: AAJOVAL470*770
ePset_SimplebimBasicQuantities - Weight, as steel (Simplebim): 666.129 kg; Height (Simplebim): 769.577 mm; Volume, net (Simplebim): 0.0848572 m3; Area, sides, net (Simplebim): 0.560548 m2; Depth (Simplebim): 470 mm; Width (Simplebim): 270 mm
Tekla Quantity - AREA_GROSS: 1.18912 m2; AREA_NET: 1.18912 m2; VOLUME_NET: 0.08486 m3; VOLUME_GROSS: 0.08486 m3; Heigth: 769.577 mm; Length: 270 mm; Width: 470 mm; WEIGTH_NET: 203.657 kg; WEIGTH_GROSS: 203.657 kg
ePset_LocationTool - Splitting: ORIGINAL
AVINOR - 07_Fase: F90; 02_Prosjekt: T1; 03_Ansvar: FDV; 04_Kontrakt: FDV; 08_Status: S2; 05_ID-nummer: +TA=222.001; 10_Objektstatus: 3_Eksisterende/ Existing; 06_Omrade: TH; 01_Lufthavnkode: ENGM
Tekla Status - Status: Unknown; Assigned By: Me; Actual: 1; Scheduled: 0; Erection Comment: Missing Value

# IfcColumn: AAJOVAL500*800 (2)
In: F
Description: AAJOVAL500*800
ePset_Simplebim - Assembly Level: Leaf
ePset_SimplebimBasicQuantities - Width (Simplebim): 500 mm; Depth (Simplebim): 800 mm; Height (Simplebim): 3550 mm; Area, sides, net (Simplebim): 7.69494 m2; Volume, net (Simplebim): 1.22602 m3; Weight, as steel (Simplebim): 9624.22 kg
ePset_LocationTool - Splitting: RESULT
AVINOR - 07_Fase: F90; 02_Prosjekt: T1; 03_Ansvar: FDV; 04_Kontrakt: FDV; 08_Status: S2; 05_ID-nummer: +TA=222.001; 10_Objektstatus: 3_Eksisterende/ Existing; 06_Omrade: TH; 01_Lufthavnkode: ENGM
Tekla Status - Status: Unknown; Assigned By: Me; Actual: 1; Scheduled: 0; Erection Comment: Missing Value
Pset_ColumnCommon - Reference: Concrete_PS-1-21; LoadBearing: no
Tekla Common - Name: PREFABSØYLE; Part mark: Concrete_PS-1-21; Class: 120; Bottom elevation: +210.350; Assembly mark: PS-370; Top elevation: +216.206; Grade: C45/55; Profile: AAJOVAL500*800

# IfcColumn: B222 - HUP7:B222 - HUP 100x50x5 (16)
Type - PredefinedType: COLUMN; Material: _NSW Stål
Type - Pset_ColumnCommon - LoadBearing: yes
ePset_Simplebim - Assembly Level: Leaf
Pset_QuantityTakeOff - Reference: B222 - HUP 100x50x5; sets with these values: 2
Pset_ColumnCommon - Reference: B222 - HUP 100x50x5; IsExternal: no
ePset_LocationTool - Splitting: ORIGINAL
ePset_SimplebimBasicQuantities - Width (Simplebim): 50 mm; Depth (Simplebim): 100 mm
AVINOR - 08_Status: S4; 07_Fase: F90; 05_ID-nummer: +TH=222.031; 03_Ansvar: 182412; 06_Omrade: TH; 02_Prosjekt: A184862; 01_Lufthavnkode: ENGM
Group: Model Group:A184862 - Kiosk NSOPØ 05.235 2 (members excluded):47061109
Name (B222 - HUP7:B222 - HUP 100x50x5:...) | In | Weight, as steel (Simplebim) (kg) | Volume, net (Simplebim) (m3) | Area, sides, net (Simplebim) (m2) | Height (Simplebim) (mm)
47060762 | Nivå F - 0,7 m | 7.693 | 0.00098 | 0.392 | 700
47060762 | Nivå F | 21.2657 | 0.002709 | 1.0836 | 1935
47060785 | Nivå F - 0,7 m | 7.693 | 0.00098 | 0.392 | 700
47060785 | Nivå F | 21.2657 | 0.002709 | 1.0836 | 1935
47061047 | Nivå F - 0,7 m | 7.693 | 0.00098 | 0.392 | 700
47061047 | Nivå F | 21.2657 | 0.002709 | 1.0836 | 1935
47061049 | Nivå F - 0,7 m | 7.693 | 0.00098 | 0.392 | 700
47061049 | Nivå F | 21.2657 | 0.002709 | 1.0836 | 1935
47061056 | Nivå F - 0,7 m | 7.693 | 0.00098 | 0.392 | 700
47061056 | Nivå F | 21.2657 | 0.002709 | 1.0836 | 1935
47061058 | Nivå F - 0,7 m | 7.693 | 0.00098 | 0.392 | 700
47061058 | Nivå F | 21.2657 | 0.002709 | 1.0836 | 1935
47061065 | Nivå F - 0,7 m | 7.693 | 0.00098 | 0.392 | 700
47061065 | Nivå F | 21.2657 | 0.002709 | 1.0836 | 1935
47061067 | Nivå F - 0,7 m | 7.693 | 0.00098 | 0.392 | 700
47061067 | Nivå F | 21.2657 | 0.002709 | 1.0836 | 1935

# IfcColumn: B222 - HUP7:B222 - HUP 50x50x5 (48)
Type - PredefinedType: COLUMN; Material: _NSW Stål
Type - Pset_ColumnCommon - LoadBearing: yes
ePset_Simplebim - Assembly Level: Leaf
ePset_SimplebimBasicQuantities - Width (Simplebim): 50 mm; Depth (Simplebim): 50 mm
Pset_ReinforcementBarPitchOfColumn - Reference: B222 - HUP 50x50x5; sets with these values: 2
Pset_ColumnCommon - IsExternal: no; Reference: B222 - HUP 50x50x5
AVINOR - 08_Status: S4; 07_Fase: F90; 05_ID-nummer: +TH=222.030; 03_Ansvar: 182412; 06_Omrade: TH; 02_Prosjekt: A184862; 01_Lufthavnkode: ENGM
ePset_LocationTool - Splitting: ORIGINAL
Group: Model Group:A184862 - Kiosk NSOPØ 05.235 2 (members excluded):47061109
Name (B222 - HUP7:B222 - HUP 50x50x5:...) | In | Volume, net (Simplebim) (m3) | Weight, as steel (Simplebim) (kg) | Area, sides, net (Simplebim) (m2) | Height (Simplebim) (mm)
47060748 | Nivå F - 0,7 m | 0.0007515 | 5.89928 | 0.3006 | 835
47060748 | Nivå F | 0.0016785 | 13.1762 | 0.6714 | 1865
47060750 | Nivå F - 0,7 m | 0.0007515 | 5.89928 | 0.3006 | 835
47060750 | Nivå F | 0.0016785 | 13.1762 | 0.6714 | 1865
47060754 | Nivå F - 0,7 m | 0.00063 | 4.9455 | 0.252 | 700
47060754 | Nivå F | 0.0016785 | 13.1762 | 0.6714 | 1865
47060756 | Nivå F - 0,7 m | 0.00063 | 4.9455 | 0.252 | 700
47060756 | Nivå F | 0.0016785 | 13.1762 | 0.6714 | 1865
47060788 | Nivå F - 0,7 m | 0.00063 | 4.9455 | 0.252 | 700
47060788 | Nivå F | 0.0016785 | 13.1762 | 0.6714 | 1865
47060790 | Nivå F - 0,7 m | 0.00063 | 4.9455 | 0.252 | 700
47060790 | Nivå F | 0.0016785 | 13.1762 | 0.6714 | 1865
47060792 | Nivå F - 0,7 m | 0.00063 | 4.9455 | 0.252 | 700
47060792 | Nivå F | 0.0016785 | 13.1762 | 0.6714 | 1865
47060794 | Nivå F - 0,7 m | 0.0007515 | 5.89928 | 0.3006 | 835
47060794 | Nivå F | 0.0016785 | 13.1762 | 0.6714 | 1865
47060796 | Nivå F - 0,7 m | 0.0007515 | 5.89928 | 0.3006 | 835
47060796 | Nivå F | 0.0016785 | 13.1762 | 0.6714 | 1865
47060798 | Nivå F - 0,7 m | 0.0007515 | 5.89928 | 0.3006 | 835
47060798 | Nivå F | 0.0016785 | 13.1762 | 0.6714 | 1865
47060800 | Nivå F - 0,7 m | 0.0007515 | 5.89928 | 0.3006 | 835
47060800 | Nivå F | 0.0016785 | 13.1762 | 0.6714 | 1865
47060802 | Nivå F - 0,7 m | 0.0007515 | 5.89928 | 0.3006 | 835
47060802 | Nivå F | 0.0016785 | 13.1762 | 0.6714 | 1865
47060804 | Nivå F - 0,7 m | 0.0007515 | 5.89928 | 0.3006 | 835
47060804 | Nivå F | 0.0016785 | 13.1762 | 0.6714 | 1865
47060806 | Nivå F - 0,7 m | 0.0007515 | 5.89928 | 0.3006 | 835
47060806 | Nivå F | 0.0016785 | 13.1762 | 0.6714 | 1865
47060808 | Nivå F - 0,7 m | 0.0007515 | 5.89928 | 0.3006 | 835
47060808 | Nivå F | 0.0016785 | 13.1762 | 0.6714 | 1865
47060810 | Nivå F - 0,7 m | 0.0007515 | 5.89928 | 0.3006 | 835
47060810 | Nivå F | 0.0016785 | 13.1762 | 0.6714 | 1865
47060812 | Nivå F - 0,7 m | 0.0007515 | 5.89928 | 0.3006 | 835
47060812 | Nivå F | 0.0016785 | 13.1762 | 0.6714 | 1865
47060814 | Nivå F - 0,7 m | 0.0007515 | 5.89928 | 0.3006 | 835
47060814 | Nivå F | 0.0016785 | 13.1762 | 0.6714 | 1865
47060816 | Nivå F - 0,7 m | 0.0007515 | 5.89928 | 0.3006 | 835
47060816 | Nivå F | 0.0016785 | 13.1762 | 0.6714 | 1865
47060818 | Nivå F - 0,7 m | 0.0007515 | 5.89928 | 0.3006 | 835
47060818 | Nivå F | 0.0016785 | 13.1762 | 0.6714 | 1865
47060820 | Nivå F - 0,7 m | 0.0007515 | 5.89928 | 0.3006 | 835
47060820 | Nivå F | 0.0016785 | 13.1762 | 0.6714 | 1865
47060822 | Nivå F - 0,7 m | 0.0007515 | 5.89928 | 0.3006 | 835
47060822 | Nivå F | 0.0016785 | 13.1762 | 0.6714 | 1865
47060824 | Nivå F - 0,7 m | 0.0007515 | 5.89928 | 0.3006 | 835
47060824 | Nivå F | 0.0016785 | 13.1762 | 0.6714 | 1865
47060826 | Nivå F - 0,7 m | 0.0007515 | 5.89928 | 0.3006 | 835
47060826 | Nivå F | 0.0016785 | 13.1762 | 0.6714 | 1865

# IfcColumn: B222 - Vinkelprofil:B222 - 100x50x8 (8)
Type - PredefinedType: COLUMN; Material: _NSW Stål
Type - Pset_ColumnCommon - LoadBearing: yes
ePset_Simplebim - Assembly Level: Leaf
ePset_LocationTool - Splitting: ORIGINAL
ePset_SimplebimBasicQuantities - Width (Simplebim): 50 mm; Depth (Simplebim): 100 mm
AVINOR - 07_Fase: F90; 03_Ansvar: FDV; 08_Status: S2; 06_Omrade: TH; 01_Lufthavnkode: ENGM
Pset_QuantityTakeOff - Reference: B222 - 100x50x8; sets with these values: 2
Pset_ColumnCommon - Reference: B222 - 100x50x8; IsExternal: no
Name (B222 - Vinkelprofil:B222 - 100x50x8:...) | In | Volume, net (Simplebim) (m3) | Weight, as steel (Simplebim) (kg) | Area, sides, net (Simplebim) (m2) | Height (Simplebim) (mm)
37344672 | Nivå F - 0,7 m | 0.000856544 | 6.72387 | 0.2262 | 754
37344672 | Nivå F | 0.0031808 | 24.9693 | 0.84 | 2800
37344795 | Nivå F - 0,7 m | 0.000856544 | 6.72387 | 0.2262 | 754
37344795 | Nivå F | 0.0031808 | 24.9693 | 0.84 | 2800
37344801 | Nivå F - 0,7 m | 0.000856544 | 6.72387 | 0.2262 | 754
37344801 | Nivå F | 0.0031808 | 24.9693 | 0.84 | 2800
37344929 | Nivå F - 0,7 m | 0.000856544 | 6.72387 | 0.2262 | 754
37344929 | Nivå F | 0.0031808 | 24.9693 | 0.84 | 2800

# IfcColumn: HEA140 (4)
In: F
Description: HEA140; Material: STEEL/S355
ePset_Simplebim - Assembly Level: Leaf
Tekla Common - Grade: S355; Class: 320; Name: STÅLSØYLE; Profile: HEA140
Tekla Quantity - Heigth: 133 mm; Width: 140 mm
Pset_ColumnCommon - LoadBearing: no
ePset_SimplebimBasicQuantities - Width (Simplebim): 133 mm; Depth (Simplebim): 140 mm
ePset_LocationTool - Splitting: ORIGINAL
Tekla Status - Status: Unknown; Assigned By: Me; Actual: 1; Scheduled: 0; Erection Comment: Missing Value
AVINOR - 07_Fase: F90; 06_Omrade: TH; 01_Lufthavnkode: ENGM
Name | Top elevation | Assembly mark | Bottom elevation | Part mark = Reference | AREA_GROSS (m2) | WEIGTH_NET (kg) | VOLUME_GROSS (m3) | AREA_NET (m2) | Length (mm) = Height (Simplebim) (mm) | VOLUME_NET (m3) | WEIGTH_GROSS (kg) | Weight, as steel (Simplebim) (kg) | Volume, net (Simplebim) (m3) | Area, sides, net (Simplebim) (m2) | 10_Objektstatus | 08_Status | 04_Kontrakt | 02_Prosjekt | 03_Ansvar
2 x STÅLSØYLE | +213.108 | SS-0(?) | +210.052 | DSS-0(?) | 2.42646 | 72.4006 | 0.0096 | 2.49668 | 3056 | 0.00922 | 75.3753 | 75.4356 | 0.00960963 | 2.42731 | 0_Nytt/ New | S4 | 182251 | A146091-1 | 181605 | AVINOR - 05_ID-nummer: +TH=222.012; 09_Arbeidspakke: AP01
2 x STÅLSØYLE | +213.273 | SS-8790(?) | +210.145 | DSS-6485(?) | 2.48363 | 74.1064 | 0.00983 | 2.55536 | 3128 | 0.00944 | 77.1512 | 77.2129 | 0.00983603 | 2.4845 | 3_Eksisterende/ Existing | S2 | FDV | T1 | FDV

# IfcColumn: PL10*120 (10)
In: F
Description: PL10*120; Material: STEEL/S355
ePset_Simplebim - Assembly Level: Leaf
ePset_SimplebimBasicQuantities - Width (Simplebim): 10 mm; Height (Simplebim): 120 mm
AVINOR - 10_Objektstatus: 0_Nytt/ New; 08_Status: S4; 07_Fase: F90; 04_Kontrakt: 182251; 06_Omrade: TH; 05_ID-nummer: +TH=223.017; 02_Prosjekt: A146091-1; 03_Ansvar: 181605; 09_Arbeidspakke: AP01; 01_Lufthavnkode: ENGM
Pset_ColumnCommon - LoadBearing: no
Tekla Status - Status: Unknown; Assigned By: Me; Actual: 1; Scheduled: 0; Erection Comment: Missing Value
ePset_LocationTool - Splitting: ORIGINAL
Tekla Common - Grade: S355; Class: 380; Profile: PL10*120; Name: STÅLSPESIAL
Tekla Quantity - Width: 10 mm; Heigth: 120 mm
Name | Volume, net (Simplebim) (m3) | Area, sides, net (Simplebim) (m2) | Depth (Simplebim) (mm) = Length (mm) | Weight, as steel (Simplebim) (kg) = WEIGTH_GROSS (kg) = WEIGTH_NET (kg) | Reference = Part mark | Bottom elevation | Assembly mark | Top elevation | AREA_NET (m2) = AREA_GROSS (m2) | VOLUME_GROSS (m3) = VOLUME_NET (m3)
2 x STÅLSPESIAL | 0.000144 | 0.0312 | 120 | 1.1304 | DSSP-7690 | +213.540 | SSP-691 | +213.660 | 0.0336 | 0.00015
2 x STÅLSPESIAL | 0.000072 | 0.0156 | 60 | 0.5652 | DSSP-7684 | +213.560 | SSP-691 | +213.620 | 0.018 | 0.00006
3 x STÅLSPESIAL | 0.000144 | 0.0312 | 120 | 1.1304 | DSSP-7690 | +213.560 | SSP-693 | +213.680 | 0.0336 | 0.00015
3 x STÅLSPESIAL | 0.000072 | 0.0156 | 60 | 0.5652 | DSSP-7684 | +213.580 | SSP-693 | +213.640 | 0.018 | 0.00006

# IfcColumn: PL10*160 (2)
In: F
Description: PL10*160; Material: STEEL/S355J0
ePset_Simplebim - Assembly Level: Leaf
AVINOR - 07_Fase: F90; 02_Prosjekt: T1; 03_Ansvar: FDV; 04_Kontrakt: FDV; 08_Status: S2; 10_Objektstatus: 3_Eksisterende/ Existing; 06_Omrade: TH; 01_Lufthavnkode: ENGM
Tekla Quantity - AREA_GROSS: 0.05522 m2; AREA_NET: 0.05522 m2; WEIGTH_NET: 1.92168 kg; WEIGTH_GROSS: 1.92168 kg; Width: 10 mm; Length: 153 mm; Heigth: 160 mm; VOLUME_GROSS: 0.00024 m3; VOLUME_NET: 0.00024 m3
Tekla Common - Part mark: DSS-5802(?); Name: STÅLBJELKE; Class: 120; Assembly mark: SS-8790(?); Grade: S355J0; Top elevation: +213.283; Bottom elevation: +213.273; Profile: PL10*160
Pset_ColumnCommon - Reference: DSS-5802(?); LoadBearing: no
Tekla Status - Status: Unknown; Assigned By: Me; Actual: 1; Scheduled: 0; Erection Comment: Missing Value
ePset_LocationTool - Splitting: ORIGINAL
ePset_SimplebimBasicQuantities - Weight, as steel (Simplebim): 1.92168 kg; Volume, net (Simplebim): 0.0002448 m3; Area, sides, net (Simplebim): 0.00626 m2; Width (Simplebim): 10 mm; Height (Simplebim): 160 mm; Depth (Simplebim): 153 mm

# IfcColumn: PL15*160 (2)
In: F
Description: PL15*160; Material: STEEL/S355J0
ePset_Simplebim - Assembly Level: Leaf
AVINOR - 07_Fase: F90; 02_Prosjekt: T1; 03_Ansvar: FDV; 04_Kontrakt: FDV; 08_Status: S2; 10_Objektstatus: 3_Eksisterende/ Existing; 06_Omrade: TH; 01_Lufthavnkode: ENGM
ePset_SimplebimBasicQuantities - Volume, net (Simplebim): 0.0003672 m3; Weight, as steel (Simplebim): 2.88252 kg; Width (Simplebim): 15 mm; Area, sides, net (Simplebim): 0.00939 m2; Height (Simplebim): 160 mm; Depth (Simplebim): 153 mm
ePset_LocationTool - Splitting: ORIGINAL
Pset_ColumnCommon - Reference: DSS-5487(?); LoadBearing: no
Tekla Common - Profile: PL15*160; Part mark: DSS-5487(?); Name: STÅLBJELKE; Class: 120; Top elevation: +210.145; Bottom elevation: +210.130; Assembly mark: SS-8790(?); Grade: S355J0
Tekla Status - Status: Unknown; Assigned By: Me; Actual: 1; Scheduled: 0; Erection Comment: Missing Value
Tekla Quantity - VOLUME_NET: 0.00037 m3; VOLUME_GROSS: 0.00037 m3; WEIGTH_GROSS: 2.88252 kg; WEIGTH_NET: 2.88252 kg; AREA_GROSS: 0.05835 m2; AREA_NET: 0.05835 m2; Width: 15 mm; Length: 153 mm; Heigth: 160 mm

# IfcColumn: PL20*180 (2)
In: F
Description: PL20*180; Material: STEEL/S355
ePset_Simplebim - Assembly Level: Leaf
Tekla Quantity - VOLUME_NET: 0.00126 m3; VOLUME_GROSS: 0.00126 m3; Length: 350 mm; WEIGTH_NET: 9.89099 kg; WEIGTH_GROSS: 9.89099 kg; AREA_GROSS: 0.1472 m2; AREA_NET: 0.1472 m2; Width: 20 mm; Heigth: 180 mm
AVINOR - 07_Fase: F90; 02_Prosjekt: T1; 03_Ansvar: FDV; 04_Kontrakt: FDV; 08_Status: S2; 10_Objektstatus: 3_Eksisterende/ Existing; 06_Omrade: TH; 01_Lufthavnkode: ENGM
ePset_SimplebimBasicQuantities - Volume, net (Simplebim): 0.00126 m3; Area, sides, net (Simplebim): 0.14 m2; Width (Simplebim): 20 mm; Height (Simplebim): 350 mm; Depth (Simplebim): 180 mm; Weight, as steel (Simplebim): 9.891 kg
Pset_ColumnCommon - Reference: DINN-185; LoadBearing: no
ePset_LocationTool - Splitting: ORIGINAL
Tekla Common - Grade: S355; Name: INNSTØPNGODS; Assembly mark: INN-150; Part mark: DINN-185; Class: 371; Top elevation: +213.615; Profile: PL20*180; Bottom elevation: +213.265
Tekla Status - Status: Unknown; Assigned By: Me; Actual: 1; Scheduled: 0; Erection Comment: Missing Value

# IfcColumn: PL30*230 (2)
In: D
Description: PL30*230; Material: STEEL/S355
ePset_Simplebim - Assembly Level: Leaf
ePset_SimplebimBasicQuantities - Area, sides, net (Simplebim): 0.182 m2; Width (Simplebim): 30 mm; Height (Simplebim): 350 mm; Weight, as steel (Simplebim): 18.9578 kg; Depth (Simplebim): 230 mm; Volume, net (Simplebim): 0.002415 m3
Pset_ColumnCommon - LoadBearing: no; Reference: DSSP-7653
AVINOR - 10_Objektstatus: 0_Nytt/ New; 08_Status: S4; 07_Fase: F90; 05_ID-nummer: +TH=223.009; 04_Kontrakt: 182251; 06_Omrade: TH; 02_Prosjekt: A146091-1; 03_Ansvar: 181605; 09_Arbeidspakke: AP01; 01_Lufthavnkode: ENGM
ePset_LocationTool - Splitting: ORIGINAL
Tekla Quantity - VOLUME_GROSS: 0.00242 m3; VOLUME_NET: 0.00242 m3; Width: 30 mm; Heigth: 230 mm; Length: 350 mm; AREA_NET: 0.1958 m2; AREA_GROSS: 0.1958 m2; WEIGTH_NET: 18.9578 kg; WEIGTH_GROSS: 18.9578 kg
Tekla Status - Status: Unknown; Assigned By: Me; Actual: 1; Scheduled: 0; Erection Comment: Missing Value
Tekla Common - Grade: S355; Top elevation: +209.525; Profile: PL30*230; Bottom elevation: +209.175; Class: 380; Name: STÅLSPESIAL; Part mark: DSSP-7653
Name | Assembly mark
STÅLSPESIAL | SSP-700
STÅLSPESIAL | SSP-699

# IfcColumn: PL30*300 (4)
In: D
Description: PL30*300; Material: STEEL/S355
ePset_Simplebim - Assembly Level: Leaf
ePset_SimplebimBasicQuantities - Volume, net (Simplebim): 0.00252 m3; Area, sides, net (Simplebim): 0.1848 m2; Width (Simplebim): 30 mm; Height (Simplebim): 300 mm; Depth (Simplebim): 280 mm; Weight, as steel (Simplebim): 19.782 kg
Tekla Common - Grade: S355; Top elevation: +210.030; Name: STÅLBJELKE; Part mark: DSS-0(?); Assembly mark: SB-0(?); Profile: PL30*300; Class: 330; Bottom elevation: +209.750
Pset_ColumnCommon - LoadBearing: no; Reference: DSS-0(?)
Tekla Quantity - AREA_NET: 0.2028 m2; AREA_GROSS: 0.2028 m2; VOLUME_NET: 0.00252 m3; VOLUME_GROSS: 0.00252 m3; Width: 30 mm; Length: 280 mm; Heigth: 300 mm; WEIGTH_NET: 19.782 kg; WEIGTH_GROSS: 19.782 kg
AVINOR - 10_Objektstatus: 0_Nytt/ New; 08_Status: S4; 07_Fase: F90; 04_Kontrakt: 182251; 06_Omrade: TH; 05_ID-nummer: +TH=223.013; 02_Prosjekt: A146091-1; 03_Ansvar: 181605; 09_Arbeidspakke: AP01; 01_Lufthavnkode: ENGM
ePset_LocationTool - Splitting: ORIGINAL
Tekla Status - Status: Unknown; Assigned By: Me; Actual: 1; Scheduled: 0; Erection Comment: Missing Value

# IfcColumn: RHS100*5 (2)
In: F
Description: RHS100*5; Material: STEEL/S355
ePset_Simplebim - Assembly Level: Leaf
Tekla Quantity - WEIGTH_GROSS: 1.48365 kg; VOLUME_GROSS: 0.00018 m3; VOLUME_NET: 0.00018 m3; AREA_NET: 0.042 m2; WEIGTH_NET: 1.4915 kg; Width: 100 mm; Length: 100 mm; Heigth: 100 mm; AREA_GROSS: 0.0389 m2
AVINOR - 07_Fase: F90; 02_Prosjekt: T1; 03_Ansvar: FDV; 04_Kontrakt: FDV; 08_Status: S2; 10_Objektstatus: 3_Eksisterende/ Existing; 06_Omrade: TH; 01_Lufthavnkode: ENGM
ePset_SimplebimBasicQuantities - Area, sides, net (Simplebim): 0.0725462 m2; Width (Simplebim): 100 mm; Height (Simplebim): 100 mm; Depth (Simplebim): 100 mm; Weight, as steel (Simplebim): 1.42253 kg; Volume, net (Simplebim): 0.000181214 m3
Tekla Common - Grade: S355; Bottom elevation: +210.030; Profile: RHS100*5; Class: 320; Top elevation: +210.130; Part mark: DSS-6795(?); Name: STÅLSØYLE; Assembly mark: SS-8790(?)
Tekla Status - Status: Unknown; Assigned By: Me; Actual: 1; Scheduled: 0; Erection Comment: Missing Value
ePset_LocationTool - Splitting: ORIGINAL
Pset_ColumnCommon - Reference: DSS-6795(?); LoadBearing: no

# IfcColumn: RHS140*8, STÅLSØYLE
In: D
Description: RHS140*8; Material: STEEL/S355
Tekla Quantity - WEIGTH_GROSS: 9.53854 kg; AREA_NET: 0.16688 m2; AREA_GROSS: 0.15747 m2; VOLUME_GROSS: 0.00122 m3; VOLUME_NET: 0.00122 m3; WEIGTH_NET: 9.61594 kg; Width: 140 mm; Heigth: 140 mm; Length: 290 mm
ePset_Simplebim - Assembly Level: Leaf
Pset_ColumnCommon - LoadBearing: no; Reference: DSS-6871(?)
AVINOR - 07_Fase: F90; 02_Prosjekt: T1; 03_Ansvar: FDV; 04_Kontrakt: FDV; 08_Status: S2; 10_Objektstatus: 3_Eksisterende/ Existing; 06_Omrade: TH; 01_Lufthavnkode: ENGM
Tekla Common - Top elevation: +209.755; Grade: S355; Assembly mark: SS-9417(?); Profile: RHS140*8; Class: 320; Bottom elevation: +209.465; Name: STÅLSØYLE; Part mark: DSS-6871(?)
ePset_SimplebimBasicQuantities - Area, sides, net (Simplebim): 0.290214 m2; Volume, net (Simplebim): 0.00115974 m3; Width (Simplebim): 140 mm; Height (Simplebim): 290 mm; Weight, as steel (Simplebim): 9.10393 kg; Depth (Simplebim): 140 mm
Tekla Status - Status: Unknown; Assigned By: Me; Actual: 1; Scheduled: 0; Erection Comment: Missing Value
ePset_LocationTool - Splitting: ORIGINAL

# IfcColumn: RHS150*5, STÅLSØYLE
In: D
Description: RHS150*5
ePset_Simplebim - Assembly Level: Leaf
Pset_ColumnCommon - LoadBearing: no; Reference: DSS-7400(?)
ePset_LocationTool - Splitting: RESULT
Tekla Common - Grade: S355; Assembly mark: SS-9417(?); Profile: RHS150*5; Class: 320; Top elevation: +209.665; Name: STÅLSØYLE; Bottom elevation: +205.240; Part mark: DSS-7400(?)
AVINOR - 07_Fase: F90; 02_Prosjekt: T1; 03_Ansvar: FDV; 04_Kontrakt: FDV; 08_Status: S2; 10_Objektstatus: 3_Eksisterende/ Existing; 06_Omrade: TH; 01_Lufthavnkode: ENGM
ePset_SimplebimBasicQuantities - Area, sides, net (Simplebim): 0.52334 m2; Width (Simplebim): 150 mm; Depth (Simplebim): 150 mm; Height (Simplebim): 465 mm; Volume, net (Simplebim): 0.00130765 m3; Weight, as steel (Simplebim): 10.265 kg
Tekla Status - Status: Unknown; Assigned By: Me; Actual: 1; Scheduled: 0; Erection Comment: Missing Value

# IfcColumn: RHS80*3 (2)
In: F
Description: RHS80*3; Material: STEEL/AISI304
ePset_Simplebim - Assembly Level: Leaf
Pset_ColumnCommon - LoadBearing: no; Reference: DSSP-7685
Tekla Quantity - WEIGTH_NET: 0.50774 kg; WEIGTH_GROSS: 0.50774 kg; AREA_NET: 0.02336 m2; AREA_GROSS: 0.02336 m2; Length: 70 mm; Width: 80 mm; Heigth: 80 mm; VOLUME_GROSS: 0.00006 m3; VOLUME_NET: 0.00006 m3
AVINOR - 10_Objektstatus: 0_Nytt/ New; 08_Status: S4; 07_Fase: F90; 04_Kontrakt: 182251; 06_Omrade: TH; 05_ID-nummer: +TH=223.017; 02_Prosjekt: A146091-1; 03_Ansvar: 181605; 09_Arbeidspakke: AP01; 01_Lufthavnkode: ENGM
Tekla Common - Profile: RHS80*3; Top elevation: +213.730; Class: 380; Grade: AISI304; Assembly mark: SSP-691; Part mark: DSSP-7685; Bottom elevation: +213.660; Name: STÅLSPESIAL
Tekla Status - Status: Unknown; Assigned By: Me; Actual: 1; Scheduled: 0; Erection Comment: Missing Value
ePset_LocationTool - Splitting: ORIGINAL
ePset_SimplebimBasicQuantities - Area, sides, net (Simplebim): 0.0420321 m2; Weight, as steel (Simplebim): 0.494703 kg; Depth (Simplebim): 80 mm; Height (Simplebim): 80 mm; Width (Simplebim): 70 mm; Volume, net (Simplebim): 0.0000630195 m3

# IfcColumn: RHS80*80*5 (6)
In: F
Description: RHS80*80*5
ePset_Simplebim - Assembly Level: Leaf
AVINOR - 07_Fase: F90; 02_Prosjekt: T1; 03_Ansvar: FDV; 04_Kontrakt: FDV; 08_Status: S2; 10_Objektstatus: 3_Eksisterende/ Existing; 06_Omrade: TH; 01_Lufthavnkode: ENGM
ePset_SimplebimBasicQuantities - Width (Simplebim): 80 mm
Pset_ColumnCommon - LoadBearing: no
Tekla Common - Grade: S355; Profile: RHS80*80*5; Class: 320; Assembly mark: SS-578(?); Name: STÅLSØYLE
Tekla Status - Status: Unknown; Assigned By: Me; Actual: 1; Scheduled: 0; Erection Comment: Missing Value
Name | Material | Depth (Simplebim) (mm) | Weight, as steel (Simplebim) (kg) | Area, sides, net (Simplebim) (m2) | Height (Simplebim) (mm) | Volume, net (Simplebim) (m3) | Reference = Part mark | Splitting | Bottom elevation | Top elevation | AREA_GROSS (m2) | VOLUME_NET (m3) | VOLUME_GROSS (m3) | WEIGTH_NET (kg) | AREA_NET (m2) | Width (mm) = Heigth (mm) | Length (mm) | WEIGTH_GROSS (kg)
2 x STÅLSØYLE | STEEL/S355 | 80.0001 | 26.2168 | 1.33732 | 2365 | 0.00333972 | DSS-815(?) | ORIGINAL | +210.025 | +212.390 | 0.73078 | 0.00355 | 0.00352 | 27.8479 | 0.7584 | 80 | 2365 | 27.6622
2 x STÅLSØYLE | STEEL/S355 | 80.0001 | 36.7479 | 1.87451 | 3315 | 0.00468126 | DSS-814(?) | ORIGINAL | +210.025 | +213.340 | 1.02433 | 0.00497 | 0.00494 | 39.0341 | 1.0624 | 80 | 3315 | 38.7739
2 x STÅLSØYLE |  | 80 | 4.43413 | 0.226185 | 400 | 0.000564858 | DSS-813(?) | RESULT | +213.500 | +215.850

# IfcCovering (117)
PredefinedType: INSULATION
ePset_Simplebim - Assembly Level: Leaf
Name | In | Description | Splitting | Width (Simplebim) (mm) | Area, largest surface, net (Simplebim) (m2) | Length (Simplebim) (mm) | Height (Simplebim) (mm) | Volume, net (Simplebim) (m3)
T=25mm | Nivå D + 1,2 m | 25mm lamellmatte | ORIGINAL | 25.8 | 0.1575 | 450 | 350 | 0.0040635 | MagiCAD Pset_Plug - ConnectionSize_mm: 0 mm; pTot_SizingFlow_kPa: 0 Pa; Insulation_thickness_mm: 25 mm
T=50mm | Nivå D + 1,2 m | BI054T - Term.isol. Lamellmatte 50mm | ORIGINAL | 50.8 | 0.4 | 800 | 500 | 0.02032 | MagiCAD Pset_Plug - ConnectionSize_mm: 0 mm; pTot_SizingFlow_kPa: 0 Pa; Insulation_thickness_mm: 50 mm; National code: VB3.29112; Description: Endelokk; Product variable 4: 2
T=25mm | Nivå D + 1,2 m | 25mm lamellmatte | ORIGINAL | 81.096 | 0.585 | 1300 | 450 | 0.0474412
BI17T - Cellegummi 13 mm SPV fett | Nivå D + 1,2 m | BI17T - Cellegummi 13 mm SPV fett | ORIGINAL | 178 | 0.0530125 | 272.365 | 242.763 | 0.00943622 | MagiCAD Pset_TBranch - qv_SizingFlow_ls: 0 m3/s; pTot_SizingFlow_Pa: 0 Pa; dpTot_SizingFlow_Pa: 0 Pa; v_SizingFlow_ms: 0 m/s; ConnectionSize_mm: 0 mm; Insulation_thickness_mm: 29 mm
BI20T - Cellegummi 13 mm kalde rør | Nivå D + 1,2 m | BI20T - Cellegummi 13 mm kalde rør | ORIGINAL | 58 | 0.00237551 | 3 | 58 | 0.00000712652 | MagiCAD Pset_Pipe - User Code: Cu; SystemName: +TH=310.001; NationalCode: UB1.111713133; qv_SizingFlow_ls: 0 m3/s; Material: Kobberrør; Length_mm: 3 mm; ConnectionSize_mm: 18 mm; Insulation_thickness_mm: 20 mm; SystemType: KV; SystemClass: Domestic Cold Water; MagiCAD Pset_Heating - v_SizingFlow_ms: 0 m/s; pTot_SizingFlow_kPa: 0 Pa; dpTot_SizingFlow_kPa: 0 Pa; MagiCAD Pset_Water - dpTot_SizingFlow_kPa: 0 Pa; pTot_SizingFlow_kPa: 0 Pa; v_SizingFlow_ms: 0 m/s
BI17T - Cellegummi 13 mm SPV fett | Nivå D + 1,2 m | BI17T - Cellegummi 13 mm SPV fett | ORIGINAL | 150.9 | 0.0795421 | 168 | 168 | 0.00190127 | MagiCAD Pset_Pipe - User Code: SUPER MA; SystemName: +TH=313.304; NationalCode: UB2.1115131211; qv_SizingFlow_ls: 0 m3/s; Material: MA; Length_mm: 150.856 mm; ConnectionSize_mm: 110 mm; Insulation_thickness_mm: 29 mm; SystemType: SPV FETT; SystemClass: Sanitary; MagiCAD Pset_Heating - v_SizingFlow_ms: 0 m/s; pTot_SizingFlow_kPa: 0 Pa; dpTot_SizingFlow_kPa: 0 Pa; MagiCAD Pset_Water - dpTot_SizingFlow_kPa: 0 Pa; pTot_SizingFlow_kPa: 0 Pa; v_SizingFlow_ms: 0 m/s
BI16T - Rørskål m/Al.folie - VV 40mm | Nivå D + 1,2 m | BI16T - Rørskål m/Al.folie - VV 40mm | ORIGINAL | 55 | 0.76063 | 4407.7 | 55 | 0.0096439 | MagiCAD Pset_Pipe - User Code: Cu; SystemName: +TH=310.002; NationalCode: UB1.111713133; qv_SizingFlow_ls: 0 m3/s; Material: Kobberrør; Length_mm: 4407.7 mm; ConnectionSize_mm: 15 mm; Insulation_thickness_mm: 20 mm; SystemType: 31 VV; SystemClass: Domestic Hot Water; MagiCAD Pset_Heating - v_SizingFlow_ms: 0 m/s; pTot_SizingFlow_kPa: 0 Pa; dpTot_SizingFlow_kPa: 0 Pa; MagiCAD Pset_Water - dpTot_SizingFlow_kPa: 0 Pa; pTot_SizingFlow_kPa: 0 Pa; v_SizingFlow_ms: 0 m/s
BI20T - Cellegummi 13 mm kalde rør | Nivå D + 1,2 m | BI20T - Cellegummi 13 mm kalde rør | ORIGINAL | 58 | 0.128497 | 706.1 | 58 | 0.00167735 | MagiCAD Pset_Pipe - User Code: Cu; SystemName: +TH=310.001; NationalCode: UB1.111713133; qv_SizingFlow_ls: 0 m3/s; Material: Kobberrør; Length_mm: 706.076 mm; ConnectionSize_mm: 18 mm; Insulation_thickness_mm: 20 mm; SystemType: KV; SystemClass: Domestic Cold Water; MagiCAD Pset_Heating - v_SizingFlow_ms: 0 m/s; pTot_SizingFlow_kPa: 0 Pa; dpTot_SizingFlow_kPa: 0 Pa; MagiCAD Pset_Water - dpTot_SizingFlow_kPa: 0 Pa; pTot_SizingFlow_kPa: 0 Pa; v_SizingFlow_ms: 0 m/s
BI16T - Rørskål m/Al.folie - VV 40mm | Nivå D + 1,2 m | BI16T - Rørskål m/Al.folie - VV 40mm | ORIGINAL | 55 | 0.132377 | 767.1 | 55 | 0.00167839 | MagiCAD Pset_Pipe - User Code: Cu; SystemName: +TH=310.002; NationalCode: UB1.111713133; qv_SizingFlow_ls: 0 m3/s; Material: Kobberrør; Length_mm: 767.079 mm; ConnectionSize_mm: 15 mm; Insulation_thickness_mm: 20 mm; SystemType: 31 VV; SystemClass: Domestic Hot Water; MagiCAD Pset_Heating - v_SizingFlow_ms: 0 m/s; pTot_SizingFlow_kPa: 0 Pa; dpTot_SizingFlow_kPa: 0 Pa; MagiCAD Pset_Water - dpTot_SizingFlow_kPa: 0 Pa; pTot_SizingFlow_kPa: 0 Pa; v_SizingFlow_ms: 0 m/s
BI20T - Cellegummi 13 mm kalde rør | Nivå D + 1,2 m | BI20T - Cellegummi 13 mm kalde rør | ORIGINAL | 47 | 0.00520671 | 58 | 47 | 0.0000756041 | MagiCAD Pset_Elbow - qv_SizingFlow_ls: 0 m3/s; pTot_SizingFlow_Pa: 0 Pa; dpTot_SizingFlow_Pa: 0 Pa; v_SizingFlow_ms: 0 m/s; ConnectionSize_mm: 0 mm; Description: MagiCAD - default bend; Insulation_thickness_mm: 20 mm
BI16T - Rørskål m/Al.folie - VV 40mm | Nivå D + 1,2 m | BI16T - Rørskål m/Al.folie - VV 40mm | ORIGINAL | 42.4999 | 0.00439111 | 55 | 42.5 | 0.0000578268 | MagiCAD Pset_Elbow - qv_SizingFlow_ls: 0 m3/s; pTot_SizingFlow_Pa: 0 Pa; dpTot_SizingFlow_Pa: 0 Pa; v_SizingFlow_ms: 0 m/s; ConnectionSize_mm: 0 mm; Description: MagiCAD - default bend; Insulation_thickness_mm: 20 mm
BI16T - Rørskål m/Al.folie - VV 40mm | Nivå D + 1,2 m | BI16T - Rørskål m/Al.folie - VV 40mm | ORIGINAL | 55 | 0.0658693 | 381.7 | 55 | 0.000835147 | MagiCAD Pset_Pipe - User Code: Cu; SystemName: +TH=310.002; NationalCode: UB1.111713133; qv_SizingFlow_ls: 0 m3/s; Material: Kobberrør; Length_mm: 381.74 mm; ConnectionSize_mm: 15 mm; Insulation_thickness_mm: 20 mm; SystemType: 31 VV; SystemClass: Domestic Hot Water; MagiCAD Pset_Heating - v_SizingFlow_ms: 0 m/s; pTot_SizingFlow_kPa: 0 Pa; dpTot_SizingFlow_kPa: 0 Pa; MagiCAD Pset_Water - dpTot_SizingFlow_kPa: 0 Pa; pTot_SizingFlow_kPa: 0 Pa; v_SizingFlow_ms: 0 m/s
BI20T - Cellegummi 13 mm kalde rør | Nivå D + 1,2 m | BI20T - Cellegummi 13 mm kalde rør | ORIGINAL | 58 | 0.0652039 | 358.3 | 58 | 0.000851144 | MagiCAD Pset_Pipe - User Code: Cu; SystemName: +TH=310.001; NationalCode: UB1.111713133; qv_SizingFlow_ls: 0 m3/s; Material: Kobberrør; Length_mm: 358.32 mm; ConnectionSize_mm: 18 mm; Insulation_thickness_mm: 20 mm; SystemType: KV; SystemClass: Domestic Cold Water; MagiCAD Pset_Heating - v_SizingFlow_ms: 0 m/s; pTot_SizingFlow_kPa: 0 Pa; dpTot_SizingFlow_kPa: 0 Pa; MagiCAD Pset_Water - dpTot_SizingFlow_kPa: 0 Pa; pTot_SizingFlow_kPa: 0 Pa; v_SizingFlow_ms: 0 m/s
BI20T - Cellegummi 13 mm kalde rør | Nivå D + 1,2 m | BI20T - Cellegummi 13 mm kalde rør | ORIGINAL | 83 | 0.0130211 | 83 | 50 | 0.000221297 | MagiCAD Pset_Pipe - User Code: Cu; SystemName: +TH=310.001; NationalCode: UB1.111713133; qv_SizingFlow_ls: 0 m3/s; Material: Kobberrør; Length_mm: 50 mm; ConnectionSize_mm: 35 mm; Insulation_thickness_mm: 24 mm; SystemType: KV; SystemClass: Domestic Cold Water; MagiCAD Pset_Heating - v_SizingFlow_ms: 0 m/s; pTot_SizingFlow_kPa: 0 Pa; dpTot_SizingFlow_kPa: 0 Pa; MagiCAD Pset_Water - dpTot_SizingFlow_kPa: 0 Pa; pTot_SizingFlow_kPa: 0 Pa; v_SizingFlow_ms: 0 m/s
Rørskål m/Al.folje - Varme 55 (uisolert oppheng) | Nivå D + 1,2 m | BI16T - Rørskål m/Al.folje - Varme 55 (uisolert oppheng)12mn | ORIGINAL | 58 | 0.18957 | 1041.7 | 58 | 0.00247457 | MagiCAD Pset_Pipe - User Code: Cu; SystemName: +TH=310.002; NationalCode: UB1.111713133; qv_SizingFlow_ls: 0 m3/s; Material: Kobberrør; Length_mm: 1041.72 mm; ConnectionSize_mm: 18 mm; Insulation_thickness_mm: 20 mm; SystemType: 31 VV; SystemClass: Domestic Hot Water; MagiCAD Pset_Heating - v_SizingFlow_ms: 0 m/s; pTot_SizingFlow_kPa: 0 Pa; dpTot_SizingFlow_kPa: 0 Pa; MagiCAD Pset_Water - dpTot_SizingFlow_kPa: 0 Pa; pTot_SizingFlow_kPa: 0 Pa; v_SizingFlow_ms: 0 m/s
Rørskål m/Al.folje - Varme 55 (uisolert oppheng) | Nivå D + 1,2 m | BI16T - Rørskål m/Al.folje - Varme 55 (uisolert oppheng)12mn | ORIGINAL | 55 | 0.00899081 | 55 | 52.1 | 0.000113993 | MagiCAD Pset_Pipe - User Code: Cu; SystemName: +TH=310.003; NationalCode: UB1.111713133; qv_SizingFlow_ls: 0 m3/s; Material: Kobberrør; Length_mm: 52.132 mm; ConnectionSize_mm: 15 mm; Insulation_thickness_mm: 20 mm; SystemType: 31 VVC; SystemClass: Hydronic Return; MagiCAD Pset_Heating - v_SizingFlow_ms: 0 m/s; pTot_SizingFlow_kPa: 0 Pa; dpTot_SizingFlow_kPa: 0 Pa; MagiCAD Pset_Water - dpTot_SizingFlow_kPa: 0 Pa; pTot_SizingFlow_kPa: 0 Pa; v_SizingFlow_ms: 0 m/s
Rørskål m/Al.folje - Varme 55 (uisolert oppheng) | Nivå D + 1,2 m | BI16T - Rørskål m/Al.folje - Varme 55 (uisolert oppheng)12mn | ORIGINAL | 55 | 0.254521 | 1474.9 | 55 | 0.00322703 | MagiCAD Pset_Pipe - User Code: Cu; SystemName: +TH=310.003; NationalCode: UB1.111713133; qv_SizingFlow_ls: 0 m3/s; Material: Kobberrør; Length_mm: 1474.93 mm; ConnectionSize_mm: 15 mm; Insulation_thickness_mm: 20 mm; SystemType: 31 VVC; SystemClass: Hydronic Return; MagiCAD Pset_Heating - v_SizingFlow_ms: 0 m/s; pTot_SizingFlow_kPa: 0 Pa; dpTot_SizingFlow_kPa: 0 Pa; MagiCAD Pset_Water - dpTot_SizingFlow_kPa: 0 Pa; pTot_SizingFlow_kPa: 0 Pa; v_SizingFlow_ms: 0 m/s
BI20T - Cellegummi 13 mm kalde rør | Nivå D + 1,2 m | BI20T - Cellegummi 13 mm kalde rør | ORIGINAL | 104 | 0.0950871 | 291.4 | 104 | 0.00189359 | MagiCAD Pset_Pipe - User Code: DN; SystemName: 32= R 27° Kopi 5; NationalCode: UB3.144613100; qv_SizingFlow_ls: 0 m3/s; Material: Stålrør normaltykke; Length_mm: 291.433 mm; ConnectionSize_mm: 50 mm; Insulation_thickness_mm: 27 mm; SystemType: GULVVARME R; SystemClass: Hydronic Return; Product variable 1: DN; MagiCAD Pset_Heating - v_SizingFlow_ms: 0 m/s; pTot_SizingFlow_kPa: 0 Pa; dpTot_SizingFlow_kPa: 0 Pa; MagiCAD Pset_Water - dpTot_SizingFlow_kPa: 0 Pa; pTot_SizingFlow_kPa: 0 Pa; v_SizingFlow_ms: 0 m/s
BI20T - Cellegummi 13 mm kalde rør | Nivå D + 1,2 m | BI20T - Cellegummi 13 mm kalde rør | ORIGINAL | 104 | 0.147754 | 452.8 | 104 | 0.00294241 | MagiCAD Pset_Pipe - User Code: DN; SystemName: 32= T 35° Kopi 1; NationalCode: UB3.144613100; qv_SizingFlow_ls: 0 m3/s; Material: Stålrør normaltykke; Length_mm: 452.781 mm; ConnectionSize_mm: 50 mm; Insulation_thickness_mm: 27 mm; SystemType: GULVVARME T; SystemClass: Hydronic Supply; Product variable 1: DN; MagiCAD Pset_Heating - v_SizingFlow_ms: 0 m/s; pTot_SizingFlow_kPa: 0 Pa; dpTot_SizingFlow_kPa: 0 Pa; MagiCAD Pset_Water - dpTot_SizingFlow_kPa: 0 Pa; pTot_SizingFlow_kPa: 0 Pa; v_SizingFlow_ms: 0 m/s
Rørskål m/Al.folje - Varme 55 (uisolert oppheng) | Nivå D + 1,2 m | BI16T - Rørskål m/Al.folje - Varme 55 (uisolert oppheng)12mn | ORIGINAL | 55 | 0.0780009 | 452 | 55 | 0.000988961 | MagiCAD Pset_Pipe - User Code: Cu; SystemName: +TH=310.003; NationalCode: UB1.111713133; qv_SizingFlow_ls: 0 m3/s; Material: Kobberrør; Length_mm: 452.009 mm; ConnectionSize_mm: 15 mm; Insulation_thickness_mm: 20 mm; SystemType: 31 VVC; SystemClass: Hydronic Return; MagiCAD Pset_Heating - v_SizingFlow_ms: 0 m/s; pTot_SizingFlow_kPa: 0 Pa; dpTot_SizingFlow_kPa: 0 Pa; MagiCAD Pset_Water - dpTot_SizingFlow_kPa: 0 Pa; pTot_SizingFlow_kPa: 0 Pa; v_SizingFlow_ms: 0 m/s
BI20T - Cellegummi 13 mm kalde rør | Nivå D + 1,2 m | BI20T - Cellegummi 13 mm kalde rør | ORIGINAL | 55 | 0.0785186 | 455 | 55 | 0.000995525 | MagiCAD Pset_Pipe - User Code: Cu; SystemName: +TH=310.001; NationalCode: UB1.111713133; qv_SizingFlow_ls: 0 m3/s; Material: Kobberrør; Length_mm: 455 mm; ConnectionSize_mm: 15 mm; Insulation_thickness_mm: 20 mm; SystemType: KV; SystemClass: Domestic Cold Water; MagiCAD Pset_Heating - v_SizingFlow_ms: 0 m/s; pTot_SizingFlow_kPa: 0 Pa; dpTot_SizingFlow_kPa: 0 Pa; MagiCAD Pset_Water - dpTot_SizingFlow_kPa: 0 Pa; pTot_SizingFlow_kPa: 0 Pa; v_SizingFlow_ms: 0 m/s
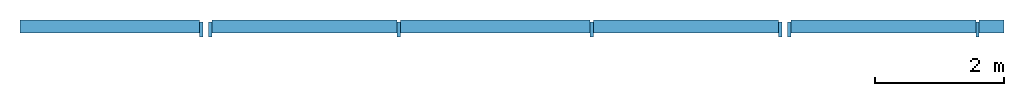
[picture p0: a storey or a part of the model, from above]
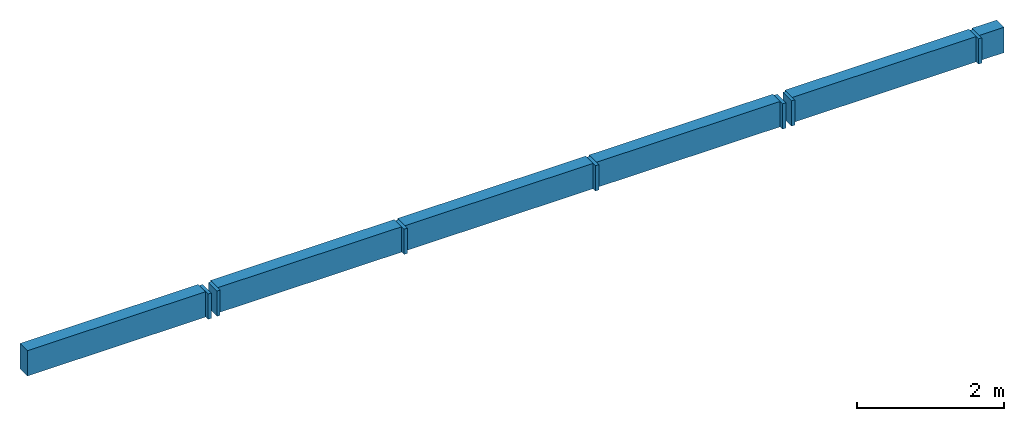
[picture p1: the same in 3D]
Properties of the parts of a building model (IFC2X3), part 3 of 7

# IfcCovering (117)
Name | In | Description | Splitting | Width (Simplebim) (mm) | Area, largest surface, net (Simplebim) (m2) | Length (Simplebim) (mm) | Height (Simplebim) (mm) | Volume, net (Simplebim) (m3)
Rørskål m/Al.folje - Varme 55 (uisolert oppheng) | Nivå D + 1,2 m | BI16T - Rørskål m/Al.folje - Varme 55 (uisolert oppheng)12mn | ORIGINAL | 58 | 0.0597626 | 328.4 | 58 | 0.000780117 | MagiCAD Pset_Pipe - User Code: Cu; SystemName: +TH=310.002; NationalCode: UB1.111713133; qv_SizingFlow_ls: 0 m3/s; Material: Kobberrør; Length_mm: 328.44 mm; ConnectionSize_mm: 18 mm; Insulation_thickness_mm: 20 mm; SystemType: 31 VV; SystemClass: Domestic Hot Water; MagiCAD Pset_Heating - v_SizingFlow_ms: 0 m/s; pTot_SizingFlow_kPa: 0 Pa; dpTot_SizingFlow_kPa: 0 Pa; MagiCAD Pset_Water - dpTot_SizingFlow_kPa: 0 Pa; pTot_SizingFlow_kPa: 0 Pa; v_SizingFlow_ms: 0 m/s
BI20T - Cellegummi 13 mm kalde rør | Nivå D + 1,2 m | BI20T - Cellegummi 13 mm kalde rør | ORIGINAL | 83 | 0.188285 | 723 | 83 | 0.00319996 | MagiCAD Pset_Pipe - User Code: Cu; SystemName: +TH=310.001; NationalCode: UB1.111713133; qv_SizingFlow_ls: 0 m3/s; Material: Kobberrør; Length_mm: 723.004 mm; ConnectionSize_mm: 35 mm; Insulation_thickness_mm: 24 mm; SystemType: KV; SystemClass: Domestic Cold Water; MagiCAD Pset_Heating - v_SizingFlow_ms: 0 m/s; pTot_SizingFlow_kPa: 0 Pa; dpTot_SizingFlow_kPa: 0 Pa; MagiCAD Pset_Water - dpTot_SizingFlow_kPa: 0 Pa; pTot_SizingFlow_kPa: 0 Pa; v_SizingFlow_ms: 0 m/s
Rørskål m/Al.folje - Varme 55 (uisolert oppheng) | Nivå D + 1,2 m | BI16T - Rørskål m/Al.folje - Varme 55 (uisolert oppheng)12mn | ORIGINAL | 58 | 0.0149771 | 82.3 | 58 | 0.000195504 | MagiCAD Pset_Pipe - User Code: Cu; SystemName: +TH=310.002; NationalCode: UB1.111713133; qv_SizingFlow_ls: 0 m3/s; Material: Kobberrør; Length_mm: 82.252 mm; ConnectionSize_mm: 18 mm; Insulation_thickness_mm: 20 mm; SystemType: 31 VV; SystemClass: Domestic Hot Water; MagiCAD Pset_Heating - v_SizingFlow_ms: 0 m/s; pTot_SizingFlow_kPa: 0 Pa; dpTot_SizingFlow_kPa: 0 Pa; MagiCAD Pset_Water - dpTot_SizingFlow_kPa: 0 Pa; pTot_SizingFlow_kPa: 0 Pa; v_SizingFlow_ms: 0 m/s
Rørskål m/Al.folje - Varme 55 (uisolert oppheng) | Nivå D + 1,2 m | BI16T - Rørskål m/Al.folje - Varme 55 (uisolert oppheng)12mn | ORIGINAL | 107.88 | 0.019601 | 58 | 107.88 | 0.000524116 | MagiCAD Pset_Valve - Description: Ball valve, threaded, brass; User Code: SMA.001; qv_SizingFlow_ls: 0 m3/s; pTot_SizingFlow_kPa: 0 Pa; dpTot_SizingFlow_kPa: 0 Pa; Manufacturer: Armatec; Product variable 2: 001; Product Code: AT3600-20; Product variable 4: 4; Insulation_thickness_mm: 30 mm; Product variable 1: SMA; NationalCode: UC1.30001
BI20T - Cellegummi 13 mm kalde rør | Nivå D + 1,2 m | BI20T - Cellegummi 13 mm kalde rør | ORIGINAL | 83 | 0.050652 | 194.5 | 83 | 0.000860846 | MagiCAD Pset_Pipe - User Code: Cu; SystemName: +TH=310.001; NationalCode: UB1.111713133; qv_SizingFlow_ls: 0 m3/s; Material: Kobberrør; Length_mm: 194.456 mm; ConnectionSize_mm: 35 mm; Insulation_thickness_mm: 24 mm; SystemType: KV; SystemClass: Domestic Cold Water; MagiCAD Pset_Heating - v_SizingFlow_ms: 0 m/s; pTot_SizingFlow_kPa: 0 Pa; dpTot_SizingFlow_kPa: 0 Pa; MagiCAD Pset_Water - dpTot_SizingFlow_kPa: 0 Pa; pTot_SizingFlow_kPa: 0 Pa; v_SizingFlow_ms: 0 m/s
BI20T - Cellegummi 13 mm kalde rør | Nivå D + 1,2 m | BI20T - Cellegummi 13 mm kalde rør | ORIGINAL | 107.64 | 0.0273129 | 81 | 107.64 | 0.000728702 | MagiCAD Pset_Valve - Description: Ball valve, threaded, brass; User Code: SMA.001; qv_SizingFlow_ls: 0 m3/s; pTot_SizingFlow_kPa: 0 Pa; dpTot_SizingFlow_kPa: 0 Pa; Manufacturer: Armatec; Product variable 2: 001; Product Code: AT3600-32; Product variable 4: 4; Insulation_thickness_mm: 24 mm; Product variable 1: SMA; NationalCode: UC1.30001
2 x Rørskål m/Al.folje - Varme 55 (uisolert oppheng) | Nivå D + 1,2 m | BI16T - Rørskål m/Al.folje - Varme 55 (uisolert oppheng)12mn | ORIGINAL | 80 | 0.0048 | 2 | 80 | 0.0000096 | MagiCAD Pset_Reduction - qv_SizingFlow_ls: 0 m3/s; pTot_SizingFlow_Pa: 0 Pa; dpTot_SizingFlow_Pa: 0 Pa; v_SizingFlow_ms: 0 m/s; ConnectionSize_mm: 0 mm; Insulation_thickness_mm: 30 mm; Description: MagiCAD - default reduction
2 x Rørskål m/Al.folje - Varme 55 (uisolert oppheng) | Nivå D + 1,2 m | BI16T - Rørskål m/Al.folje - Varme 55 (uisolert oppheng)12mn | ORIGINAL | 47 | 0.00520685 | 58 | 47 | 0.0000756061 | MagiCAD Pset_Elbow - qv_SizingFlow_ls: 0 m3/s; pTot_SizingFlow_Pa: 0 Pa; dpTot_SizingFlow_Pa: 0 Pa; v_SizingFlow_ms: 0 m/s; ConnectionSize_mm: 0 mm; Description: MagiCAD - default bend; Insulation_thickness_mm: 20 mm
2 x BI20T - Cellegummi 13 mm kalde rør | Nivå D + 1,2 m | BI20T - Cellegummi 13 mm kalde rør | ORIGINAL | 83 | 0.00516675 | 3 | 83 | 0.0000155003 | MagiCAD Pset_Reduction - qv_SizingFlow_ls: 0 m3/s; pTot_SizingFlow_Pa: 0 Pa; dpTot_SizingFlow_Pa: 0 Pa; v_SizingFlow_ms: 0 m/s; ConnectionSize_mm: 0 mm; Insulation_thickness_mm: 24 mm; Description: MagiCAD - default reduction
BI16T - Rørskål m/Al.folie - VV 40mm | Nivå D + 1,2 m | BI16T - Rørskål m/Al.folie - VV 40mm | ORIGINAL | 55 | 0.105922 | 613.8 | 55 | 0.00134297 | MagiCAD Pset_Pipe - User Code: Cu; SystemName: +TH=310.002; NationalCode: UB1.111713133; qv_SizingFlow_ls: 0 m3/s; Material: Kobberrør; Length_mm: 613.808 mm; ConnectionSize_mm: 15 mm; Insulation_thickness_mm: 20 mm; SystemType: 31 VV; SystemClass: Domestic Hot Water; MagiCAD Pset_Heating - v_SizingFlow_ms: 0 m/s; pTot_SizingFlow_kPa: 0 Pa; dpTot_SizingFlow_kPa: 0 Pa; MagiCAD Pset_Water - dpTot_SizingFlow_kPa: 0 Pa; pTot_SizingFlow_kPa: 0 Pa; v_SizingFlow_ms: 0 m/s
BI16T - Rørskål m/Al.folie - VV 40mm | Nivå D + 1,2 m | BI16T - Rørskål m/Al.folie - VV 40mm | ORIGINAL | 84.52 | 0.0129737 | 49 | 84.52 | 0.000271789 | MagiCAD Pset_Valve - Description: Ball valve, threaded, brass; User Code: SMA.001; qv_SizingFlow_ls: 0 m3/s; pTot_SizingFlow_kPa: 0 Pa; dpTot_SizingFlow_kPa: 0 Pa; Manufacturer: Armatec; Product variable 2: 001; Product Code: AT3600-15; Product variable 4: 4; Insulation_thickness_mm: 20 mm; Product variable 1: SMA; NationalCode: UC1.30001
BI20T - Cellegummi 13 mm kalde rør | Nivå D + 1,2 m | BI20T - Cellegummi 13 mm kalde rør | ORIGINAL | 58 | 0.020946 | 115.1 | 58 | 0.000273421 | MagiCAD Pset_Pipe - User Code: Cu; SystemName: +TH=310.001; NationalCode: UB1.111713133; qv_SizingFlow_ls: 0 m3/s; Material: Kobberrør; Length_mm: 115.121 mm; ConnectionSize_mm: 18 mm; Insulation_thickness_mm: 20 mm; SystemType: KV; SystemClass: Domestic Cold Water; MagiCAD Pset_Heating - v_SizingFlow_ms: 0 m/s; pTot_SizingFlow_kPa: 0 Pa; dpTot_SizingFlow_kPa: 0 Pa; MagiCAD Pset_Water - dpTot_SizingFlow_kPa: 0 Pa; pTot_SizingFlow_kPa: 0 Pa; v_SizingFlow_ms: 0 m/s
BI20T - Cellegummi 13 mm kalde rør | Nivå D + 1,2 m | BI20T - Cellegummi 13 mm kalde rør | ORIGINAL | 89.88 | 0.0163305 | 58 | 89.88 | 0.000363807 | MagiCAD Pset_Valve - Description: Ball valve, threaded, brass; User Code: SMA.001; qv_SizingFlow_ls: 0 m3/s; pTot_SizingFlow_kPa: 0 Pa; dpTot_SizingFlow_kPa: 0 Pa; Manufacturer: Armatec; Product variable 2: 001; Product Code: AT3600-20; Product variable 4: 4; Insulation_thickness_mm: 21 mm; Product variable 1: SMA; NationalCode: UC1.30001
BI20T - Cellegummi 13 mm kalde rør | Nivå D + 1,2 m | BI20T - Cellegummi 13 mm kalde rør | ORIGINAL | 62 | 0.002883 | 2 | 62 | 0.000005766 | MagiCAD Pset_Reduction - qv_SizingFlow_ls: 0 m3/s; pTot_SizingFlow_Pa: 0 Pa; dpTot_SizingFlow_Pa: 0 Pa; v_SizingFlow_ms: 0 m/s; ConnectionSize_mm: 0 mm; Insulation_thickness_mm: 21 mm; Description: MagiCAD - default reduction
6 x BI20T - Cellegummi 13 mm kalde rør | Nivå D + 1,2 m | BI20T - Cellegummi 13 mm kalde rør | ORIGINAL | 47 | 0.00520685 | 58 | 47 | 0.0000756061 | MagiCAD Pset_Elbow - qv_SizingFlow_ls: 0 m3/s; pTot_SizingFlow_Pa: 0 Pa; dpTot_SizingFlow_Pa: 0 Pa; v_SizingFlow_ms: 0 m/s; ConnectionSize_mm: 0 mm; Description: MagiCAD - default bend; Insulation_thickness_mm: 20 mm
BI17T - Cellegummi 13 mm SPV fett | Nivå D + 1,2 m | BI17T - Cellegummi 13 mm SPV fett | ORIGINAL | 168 | 1.16019 | 2201 | 168 | 0.0277316 | MagiCAD Pset_Pipe - User Code: SUPER MA; SystemName: +TH=313.304; NationalCode: UB2.1115131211; qv_SizingFlow_ls: 0 m3/s; Material: MA; Length_mm: 2201.04 mm; ConnectionSize_mm: 110 mm; Insulation_thickness_mm: 29 mm; SystemType: SPV FETT; SystemClass: Sanitary; MagiCAD Pset_Heating - v_SizingFlow_ms: 0 m/s; pTot_SizingFlow_kPa: 0 Pa; dpTot_SizingFlow_kPa: 0 Pa; MagiCAD Pset_Water - dpTot_SizingFlow_kPa: 0 Pa; pTot_SizingFlow_kPa: 0 Pa; v_SizingFlow_ms: 0 m/s
BI17T - Cellegummi 13 mm SPV fett | Nivå D + 1,2 m | BI17T - Cellegummi 13 mm SPV fett | ORIGINAL | 168 | 0.544407 | 1032.8 | 168 | 0.0130128 | MagiCAD Pset_Pipe - User Code: SUPER MA; SystemName: +TH=313.304; NationalCode: UB2.1115131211; qv_SizingFlow_ls: 0 m3/s; Material: MA; Length_mm: 1032.76 mm; ConnectionSize_mm: 110 mm; Insulation_thickness_mm: 29 mm; SystemType: SPV FETT; SystemClass: Sanitary; MagiCAD Pset_Heating - v_SizingFlow_ms: 0 m/s; pTot_SizingFlow_kPa: 0 Pa; dpTot_SizingFlow_kPa: 0 Pa; MagiCAD Pset_Water - dpTot_SizingFlow_kPa: 0 Pa; pTot_SizingFlow_kPa: 0 Pa; v_SizingFlow_ms: 0 m/s
BI17T - Cellegummi 13 mm SPV fett | Nivå D + 1,2 m | BI17T - Cellegummi 13 mm SPV fett | ORIGINAL | 168 | 0.271149 | 514.4 | 168 | 0.00648122 | MagiCAD Pset_Pipe - User Code: SUPER MA; SystemName: +TH=313.304; NationalCode: UB2.1115131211; qv_SizingFlow_ls: 0 m3/s; Material: MA; Length_mm: 514.373 mm; ConnectionSize_mm: 110 mm; Insulation_thickness_mm: 29 mm; SystemType: SPV FETT; SystemClass: Sanitary; MagiCAD Pset_Heating - v_SizingFlow_ms: 0 m/s; pTot_SizingFlow_kPa: 0 Pa; dpTot_SizingFlow_kPa: 0 Pa; MagiCAD Pset_Water - dpTot_SizingFlow_kPa: 0 Pa; pTot_SizingFlow_kPa: 0 Pa; v_SizingFlow_ms: 0 m/s
BI17T - Cellegummi 13 mm SPV fett | Nivå D + 1,2 m | BI17T - Cellegummi 13 mm SPV fett | ORIGINAL | 148.822 | 0.0530085 | 188.223 | 179 | 0.00234833 | MagiCAD Pset_Elbow - qv_SizingFlow_ls: 0 m3/s; pTot_SizingFlow_Pa: 0 Pa; dpTot_SizingFlow_Pa: 0 Pa; v_SizingFlow_ms: 0 m/s; ConnectionSize_mm: 0 mm; Insulation_thickness_mm: 29 mm
BI17T - Cellegummi 13 mm SPV fett | Nivå D + 1,2 m | BI17T - Cellegummi 13 mm SPV fett | ORIGINAL | 168 | 0.394706 | 748.8 | 168 | 0.00943455 | MagiCAD Pset_Pipe - User Code: SUPER MA; SystemName: +TH=313.304; NationalCode: UB2.1115131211; qv_SizingFlow_ls: 0 m3/s; Material: MA; Length_mm: 748.826 mm; ConnectionSize_mm: 110 mm; Insulation_thickness_mm: 29 mm; SystemType: SPV FETT; SystemClass: Sanitary; MagiCAD Pset_Heating - v_SizingFlow_ms: 0 m/s; pTot_SizingFlow_kPa: 0 Pa; dpTot_SizingFlow_kPa: 0 Pa; MagiCAD Pset_Water - dpTot_SizingFlow_kPa: 0 Pa; pTot_SizingFlow_kPa: 0 Pa; v_SizingFlow_ms: 0 m/s
2 x BI17T - Cellegummi 13 mm SPV fett | Nivå D + 1,2 m | BI17T - Cellegummi 13 mm SPV fett | ORIGINAL | 148.846 | 0.0530193 | 188.226 | 179 | 0.00234881 | MagiCAD Pset_Elbow - qv_SizingFlow_ls: 0 m3/s; pTot_SizingFlow_Pa: 0 Pa; dpTot_SizingFlow_Pa: 0 Pa; v_SizingFlow_ms: 0 m/s; ConnectionSize_mm: 0 mm; Insulation_thickness_mm: 29 mm
BI17T - Cellegummi 13 mm SPV fett | Nivå D + 1,2 m | BI17T - Cellegummi 13 mm SPV fett | ORIGINAL | 189 | 0.10984 | 215.47 | 215.059 | 0.00519465 | MagiCAD Pset_Elbow - qv_SizingFlow_ls: 0 m3/s; pTot_SizingFlow_Pa: 0 Pa; dpTot_SizingFlow_Pa: 0 Pa; v_SizingFlow_ms: 0 m/s; ConnectionSize_mm: 0 mm; Insulation_thickness_mm: 29 mm
BI17T - Cellegummi 13 mm SPV fett | Nivå D + 1,2 m | BI17T - Cellegummi 13 mm SPV fett | ORIGINAL | 168 | 0.58995 | 1119.2 | 168 | 0.0141014 | MagiCAD Pset_Pipe - User Code: SUPER MA; SystemName: 31= SPV Kopi 74; NationalCode: UB2.1115131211; qv_SizingFlow_ls: 0 m3/s; Material: MA; Length_mm: 1119.2 mm; ConnectionSize_mm: 110 mm; Insulation_thickness_mm: 29 mm; SystemType: SPV; SystemClass: Sanitary; MagiCAD Pset_Heating - v_SizingFlow_ms: 0 m/s; pTot_SizingFlow_kPa: 0 Pa; dpTot_SizingFlow_kPa: 0 Pa; MagiCAD Pset_Water - dpTot_SizingFlow_kPa: 0 Pa; pTot_SizingFlow_kPa: 0 Pa; v_SizingFlow_ms: 0 m/s
2 x BI20T - Cellegummi 13 mm kalde rør | Nivå D + 1,2 m | BI20T - Cellegummi 13 mm kalde rør | ORIGINAL | 114.4 | 0.027162 | 117.6 | 117.6 | 0.000957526 | MagiCAD Pset_Elbow - qv_SizingFlow_ls: 0 m3/s; pTot_SizingFlow_Pa: 0 Pa; dpTot_SizingFlow_Pa: 0 Pa; v_SizingFlow_ms: 0 m/s; ConnectionSize_mm: 0 mm; Insulation_thickness_mm: 27 mm
BI17T - Cellegummi 13 mm SPV fett | Nivå D + 1,2 m | BI17T - Cellegummi 13 mm SPV fett | ORIGINAL | 148.834 | 0.0530142 | 188.224 | 179 | 0.00234858 | MagiCAD Pset_Elbow - qv_SizingFlow_ls: 0 m3/s; pTot_SizingFlow_Pa: 0 Pa; dpTot_SizingFlow_Pa: 0 Pa; v_SizingFlow_ms: 0 m/s; ConnectionSize_mm: 0 mm; Insulation_thickness_mm: 29 mm
BI17T - Cellegummi 13 mm SPV fett | Nivå D + 1,2 m | BI17T - Cellegummi 13 mm SPV fett | ORIGINAL | 168 | 0.283273 | 537.4 | 168 | 0.00677101 | MagiCAD Pset_Pipe - User Code: SUPER MA; SystemName: +TH=313.304; NationalCode: UB2.1115131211; qv_SizingFlow_ls: 0 m3/s; Material: MA; Length_mm: 537.417 mm; ConnectionSize_mm: 110 mm; Insulation_thickness_mm: 29 mm; SystemType: SPV FETT; SystemClass: Sanitary; MagiCAD Pset_Heating - v_SizingFlow_ms: 0 m/s; pTot_SizingFlow_kPa: 0 Pa; dpTot_SizingFlow_kPa: 0 Pa; MagiCAD Pset_Water - dpTot_SizingFlow_kPa: 0 Pa; pTot_SizingFlow_kPa: 0 Pa; v_SizingFlow_ms: 0 m/s
BI17T - Cellegummi 13 mm SPV fett | Nivå D + 1,2 m | BI17T - Cellegummi 13 mm SPV fett | ORIGINAL | 148.827 | 0.0530109 | 188.223 | 179 | 0.00234844 | MagiCAD Pset_Elbow - qv_SizingFlow_ls: 0 m3/s; pTot_SizingFlow_Pa: 0 Pa; dpTot_SizingFlow_Pa: 0 Pa; v_SizingFlow_ms: 0 m/s; ConnectionSize_mm: 0 mm; Insulation_thickness_mm: 29 mm
BI17T - Cellegummi 13 mm SPV fett | Nivå D + 1,2 m | BI17T - Cellegummi 13 mm SPV fett | ORIGINAL | 148.835 | 0.0530142 | 188.224 | 179 | 0.00234858 | MagiCAD Pset_Elbow - qv_SizingFlow_ls: 0 m3/s; pTot_SizingFlow_Pa: 0 Pa; dpTot_SizingFlow_Pa: 0 Pa; v_SizingFlow_ms: 0 m/s; ConnectionSize_mm: 0 mm; Insulation_thickness_mm: 29 mm
BI20T - Cellegummi 13 mm kalde rør | Nivå D + 1,2 m | BI20T - Cellegummi 13 mm kalde rør | ORIGINAL | 58 | 0.423579 | 2327.6 | 58 | 0.00552923 | MagiCAD Pset_Pipe - User Code: Cu; SystemName: +TH=310.001; NationalCode: UB1.111713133; qv_SizingFlow_ls: 0 m3/s; Material: Kobberrør; Length_mm: 2327.57 mm; ConnectionSize_mm: 18 mm; Insulation_thickness_mm: 20 mm; SystemType: KV; SystemClass: Domestic Cold Water; MagiCAD Pset_Heating - v_SizingFlow_ms: 0 m/s; pTot_SizingFlow_kPa: 0 Pa; dpTot_SizingFlow_kPa: 0 Pa; MagiCAD Pset_Water - dpTot_SizingFlow_kPa: 0 Pa; pTot_SizingFlow_kPa: 0 Pa; v_SizingFlow_ms: 0 m/s
BI20T - Cellegummi 13 mm kalde rør | Nivå D + 1,2 m | BI20T - Cellegummi 13 mm kalde rør | ORIGINAL | 58 | 0.796204 | 4375.2 | 58 | 0.0103933 | MagiCAD Pset_Pipe - User Code: Cu; SystemName: +TH=310.001; NationalCode: UB1.111713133; qv_SizingFlow_ls: 0 m3/s; Material: Kobberrør; Length_mm: 4375.17 mm; ConnectionSize_mm: 18 mm; Insulation_thickness_mm: 20 mm; SystemType: KV; SystemClass: Domestic Cold Water; MagiCAD Pset_Heating - v_SizingFlow_ms: 0 m/s; pTot_SizingFlow_kPa: 0 Pa; dpTot_SizingFlow_kPa: 0 Pa; MagiCAD Pset_Water - dpTot_SizingFlow_kPa: 0 Pa; pTot_SizingFlow_kPa: 0 Pa; v_SizingFlow_ms: 0 m/s
3 x BI20T - Cellegummi 13 mm kalde rør | Nivå D + 1,2 m | BI20T - Cellegummi 13 mm kalde rør | ORIGINAL | 58 | 0.002612 | 10 | 58 | 0.00002612 | MagiCAD Pset_Joint - Description: MagiCAD - default joint; qv_SizingFlow_ls: 0 m3/s; pTot_SizingFlow_Pa: 0 Pa; dpTot_SizingFlow_Pa: 0 Pa; v_SizingFlow_ms: 0 m/s; ConnectionSize_mm: 0 mm; Insulation_thickness_mm: 20 mm
3 x BI20T - Cellegummi 13 mm kalde rør | Nivå D + 1,2 m | BI20T - Cellegummi 13 mm kalde rør | ORIGINAL | 60 | 0.0027 | 2 | 60 | 0.0000054 | MagiCAD Pset_Reduction - qv_SizingFlow_ls: 0 m3/s; pTot_SizingFlow_Pa: 0 Pa; dpTot_SizingFlow_Pa: 0 Pa; v_SizingFlow_ms: 0 m/s; ConnectionSize_mm: 0 mm; Insulation_thickness_mm: 20 mm; Description: MagiCAD - default reduction
BI20T - Cellegummi 13 mm kalde rør | Nivå D + 1,2 m | BI20T - Cellegummi 13 mm kalde rør | ORIGINAL | 58 | 0.0306638 | 168.5 | 58 | 0.000400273 | MagiCAD Pset_Pipe - User Code: Cu; SystemName: +TH=310.001; NationalCode: UB1.111713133; qv_SizingFlow_ls: 0 m3/s; Material: Kobberrør; Length_mm: 168.5 mm; ConnectionSize_mm: 18 mm; Insulation_thickness_mm: 20 mm; SystemType: KV; SystemClass: Domestic Cold Water; MagiCAD Pset_Heating - v_SizingFlow_ms: 0 m/s; pTot_SizingFlow_kPa: 0 Pa; dpTot_SizingFlow_kPa: 0 Pa; MagiCAD Pset_Water - dpTot_SizingFlow_kPa: 0 Pa; pTot_SizingFlow_kPa: 0 Pa; v_SizingFlow_ms: 0 m/s
BI20T - Cellegummi 13 mm kalde rør | Nivå D + 1,2 m | BI20T - Cellegummi 13 mm kalde rør | ORIGINAL | 36 | 0.002465 | 58 | 42.5 | 0.00008874 | MagiCAD Pset_TBranch - qv_SizingFlow_ls: 0 m3/s; pTot_SizingFlow_Pa: 0 Pa; dpTot_SizingFlow_Pa: 0 Pa; v_SizingFlow_ms: 0 m/s; ConnectionSize_mm: 0 mm; Insulation_thickness_mm: 20 mm; Description: MagiCAD - default T-branch
BI20T - Cellegummi 13 mm kalde rør | Nivå D + 1,2 m | BI20T - Cellegummi 13 mm kalde rør | ORIGINAL | 58 | 0.107278 | 589.5 | 58 | 0.00140036 | MagiCAD Pset_Pipe - User Code: Cu; SystemName: +TH=310.001; NationalCode: UB1.111713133; qv_SizingFlow_ls: 0 m3/s; Material: Kobberrør; Length_mm: 589.469 mm; ConnectionSize_mm: 18 mm; Insulation_thickness_mm: 20 mm; SystemType: KV; SystemClass: Domestic Cold Water; MagiCAD Pset_Heating - v_SizingFlow_ms: 0 m/s; pTot_SizingFlow_kPa: 0 Pa; dpTot_SizingFlow_kPa: 0 Pa; MagiCAD Pset_Water - dpTot_SizingFlow_kPa: 0 Pa; pTot_SizingFlow_kPa: 0 Pa; v_SizingFlow_ms: 0 m/s
2 x BI20T - Cellegummi 13 mm kalde rør | Nivå D + 1,2 m | BI20T - Cellegummi 13 mm kalde rør | ORIGINAL | 58 | 0.0271516 | 149.2 | 58 | 0.000354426 | MagiCAD Pset_Pipe - User Code: Cu; SystemName: +TH=310.001; NationalCode: UB1.111713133; qv_SizingFlow_ls: 0 m3/s; Material: Kobberrør; Length_mm: 149.227 mm; ConnectionSize_mm: 18 mm; Insulation_thickness_mm: 20 mm; SystemType: KV; SystemClass: Domestic Cold Water; MagiCAD Pset_Heating - v_SizingFlow_ms: 0 m/s; pTot_SizingFlow_kPa: 0 Pa; dpTot_SizingFlow_kPa: 0 Pa; MagiCAD Pset_Water - dpTot_SizingFlow_kPa: 0 Pa; pTot_SizingFlow_kPa: 0 Pa; v_SizingFlow_ms: 0 m/s
BI20T - Cellegummi 13 mm kalde rør | Nivå D + 1,2 m | BI20T - Cellegummi 13 mm kalde rør | ORIGINAL | 42.5 | 0.00439181 | 55 | 42.5 | 0.0000578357 | MagiCAD Pset_Elbow - qv_SizingFlow_ls: 0 m3/s; pTot_SizingFlow_Pa: 0 Pa; dpTot_SizingFlow_Pa: 0 Pa; v_SizingFlow_ms: 0 m/s; ConnectionSize_mm: 0 mm; Description: MagiCAD - default bend; Insulation_thickness_mm: 20 mm
BI20T - Cellegummi 13 mm kalde rør | Nivå D + 1,2 m | BI20T - Cellegummi 13 mm kalde rør | ORIGINAL | 58 | 0.002523 | 3 | 58 | 0.000007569 | MagiCAD Pset_Reduction - qv_SizingFlow_ls: 0 m3/s; pTot_SizingFlow_Pa: 0 Pa; dpTot_SizingFlow_Pa: 0 Pa; v_SizingFlow_ms: 0 m/s; ConnectionSize_mm: 0 mm; Insulation_thickness_mm: 20 mm; Description: MagiCAD - default reduction
BI20T - Cellegummi 13 mm kalde rør | Nivå D + 1,2 m | BI20T - Cellegummi 13 mm kalde rør | ORIGINAL | 87.88 | 0.0159671 | 58 | 87.88 | 0.000347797 | MagiCAD Pset_Valve - Description: Ball valve, threaded, brass; User Code: SMA.001; qv_SizingFlow_ls: 0 m3/s; pTot_SizingFlow_kPa: 0 Pa; dpTot_SizingFlow_kPa: 0 Pa; Manufacturer: Armatec; Product variable 2: 001; Product Code: AT3600-20; Product variable 4: 4; Insulation_thickness_mm: 20 mm; Product variable 1: SMA; NationalCode: UC1.30001
BI20T - Cellegummi 13 mm kalde rør | Nivå D + 1,2 m | BI20T - Cellegummi 13 mm kalde rør | ORIGINAL | 58 | 0.107278 | 589.5 | 58 | 0.00140036 | MagiCAD Pset_Pipe - User Code: Cu; SystemName: +TH=310.001; NationalCode: UB1.111713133; qv_SizingFlow_ls: 0 m3/s; Material: Kobberrør; Length_mm: 590.07 mm; ConnectionSize_mm: 18 mm; Insulation_thickness_mm: 20 mm; SystemType: KV; SystemClass: Domestic Cold Water; MagiCAD Pset_Heating - v_SizingFlow_ms: 0 m/s; pTot_SizingFlow_kPa: 0 Pa; dpTot_SizingFlow_kPa: 0 Pa; MagiCAD Pset_Water - dpTot_SizingFlow_kPa: 0 Pa; pTot_SizingFlow_kPa: 0 Pa; v_SizingFlow_ms: 0 m/s
BI20T - Cellegummi 13 mm kalde rør | Nivå D + 1,2 m | BI20T - Cellegummi 13 mm kalde rør | ORIGINAL | 36 | 0.00562325 | 83 | 67.75 | 0.000202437 | MagiCAD Pset_TBranch - qv_SizingFlow_ls: 0 m3/s; pTot_SizingFlow_Pa: 0 Pa; dpTot_SizingFlow_Pa: 0 Pa; v_SizingFlow_ms: 0 m/s; ConnectionSize_mm: 0 mm; Insulation_thickness_mm: 24 mm; Description: MagiCAD - default T-branch
BI20T - Cellegummi 13 mm kalde rør | Nivå D + 1,2 m | BI20T - Cellegummi 13 mm kalde rør | ORIGINAL | 83 | 0.0578396 | 222.1 | 83 | 0.000983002 | MagiCAD Pset_Pipe - User Code: Cu; SystemName: +TH=310.001; NationalCode: UB1.111713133; qv_SizingFlow_ls: 0 m3/s; Material: Kobberrør; Length_mm: 222.086 mm; ConnectionSize_mm: 35 mm; Insulation_thickness_mm: 24 mm; SystemType: KV; SystemClass: Domestic Cold Water; MagiCAD Pset_Heating - v_SizingFlow_ms: 0 m/s; pTot_SizingFlow_kPa: 0 Pa; dpTot_SizingFlow_kPa: 0 Pa; MagiCAD Pset_Water - dpTot_SizingFlow_kPa: 0 Pa; pTot_SizingFlow_kPa: 0 Pa; v_SizingFlow_ms: 0 m/s
BI16T - Rørskål m/Al.folie - VV 40mm | Nivå D + 1,2 m | BI16T - Rørskål m/Al.folie - VV 40mm | ORIGINAL | 55 | 0.107061 | 620.4 | 55 | 0.00135741 | MagiCAD Pset_Pipe - User Code: Cu; SystemName: +TH=310.002; NationalCode: UB1.111713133; qv_SizingFlow_ls: 0 m3/s; Material: Kobberrør; Length_mm: 620.448 mm; ConnectionSize_mm: 15 mm; Insulation_thickness_mm: 20 mm; SystemType: 31 VV; SystemClass: Domestic Hot Water; MagiCAD Pset_Heating - v_SizingFlow_ms: 0 m/s; pTot_SizingFlow_kPa: 0 Pa; dpTot_SizingFlow_kPa: 0 Pa; MagiCAD Pset_Water - dpTot_SizingFlow_kPa: 0 Pa; pTot_SizingFlow_kPa: 0 Pa; v_SizingFlow_ms: 0 m/s
Rørskål m/Al.folje - Varme 55 (uisolert oppheng) | Nivå D + 1,2 m | BI16T - Rørskål m/Al.folje - Varme 55 (uisolert oppheng)12mn | ORIGINAL | 30 | 0.002465 | 58 | 42.5 | 0.00007395 | MagiCAD Pset_TBranch - qv_SizingFlow_ls: 0 m3/s; pTot_SizingFlow_Pa: 0 Pa; dpTot_SizingFlow_Pa: 0 Pa; v_SizingFlow_ms: 0 m/s; ConnectionSize_mm: 0 mm; Insulation_thickness_mm: 20 mm; Description: MagiCAD - default T-branch
Rørskål m/Al.folje - Varme 55 (uisolert oppheng) | Nivå D + 1,2 m | BI16T - Rørskål m/Al.folje - Varme 55 (uisolert oppheng)12mn | ORIGINAL | 58 | 0.021401 | 117.6 | 58 | 0.00027936 | MagiCAD Pset_Pipe - User Code: Cu; SystemName: +TH=310.002; NationalCode: UB1.111713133; qv_SizingFlow_ls: 0 m3/s; Material: Kobberrør; Length_mm: 117.612 mm; ConnectionSize_mm: 18 mm; Insulation_thickness_mm: 20 mm; SystemType: 31 VV; SystemClass: Domestic Hot Water; MagiCAD Pset_Heating - v_SizingFlow_ms: 0 m/s; pTot_SizingFlow_kPa: 0 Pa; dpTot_SizingFlow_kPa: 0 Pa; MagiCAD Pset_Water - dpTot_SizingFlow_kPa: 0 Pa; pTot_SizingFlow_kPa: 0 Pa; v_SizingFlow_ms: 0 m/s
2 x BI20T - Cellegummi 13 mm kalde rør | Nivå D + 1,2 m | BI20T - Cellegummi 13 mm kalde rør | ORIGINAL | 76.5 | 0.0145104 | 83 | 76.5 | 0.000292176 | MagiCAD Pset_Elbow - qv_SizingFlow_ls: 0 m3/s; pTot_SizingFlow_Pa: 0 Pa; dpTot_SizingFlow_Pa: 0 Pa; v_SizingFlow_ms: 0 m/s; ConnectionSize_mm: 0 mm; Description: MagiCAD - default bend; Insulation_thickness_mm: 24 mm
2 x Rørskål m/Al.folje - Varme 55 (uisolert oppheng) | Nivå D + 1,2 m | BI16T - Rørskål m/Al.folje - Varme 55 (uisolert oppheng)12mn | ORIGINAL | 42.5 | 0.00439181 | 55 | 42.5 | 0.0000578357 | MagiCAD Pset_Elbow - qv_SizingFlow_ls: 0 m3/s; pTot_SizingFlow_Pa: 0 Pa; dpTot_SizingFlow_Pa: 0 Pa; v_SizingFlow_ms: 0 m/s; ConnectionSize_mm: 0 mm; Description: MagiCAD - default bend; Insulation_thickness_mm: 20 mm
Rørskål m/Al.folje - Varme 55 (uisolert oppheng) | Nivå D + 1,2 m | BI16T - Rørskål m/Al.folje - Varme 55 (uisolert oppheng)12mn | ORIGINAL | 55 | 0.601901 | 3487.9 | 55 | 0.00763141 | MagiCAD Pset_Pipe - User Code: Cu; SystemName: +TH=310.003; NationalCode: UB1.111713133; qv_SizingFlow_ls: 0 m3/s; Material: Kobberrør; Length_mm: 3487.87 mm; ConnectionSize_mm: 15 mm; Insulation_thickness_mm: 20 mm; SystemType: 31 VVC; SystemClass: Hydronic Return; MagiCAD Pset_Heating - v_SizingFlow_ms: 0 m/s; pTot_SizingFlow_kPa: 0 Pa; dpTot_SizingFlow_kPa: 0 Pa; MagiCAD Pset_Water - dpTot_SizingFlow_kPa: 0 Pa; pTot_SizingFlow_kPa: 0 Pa; v_SizingFlow_ms: 0 m/s
2 x Rørskål m/Al.folje - Varme 55 (uisolert oppheng) | Nivå D + 1,2 m | BI16T - Rørskål m/Al.folje - Varme 55 (uisolert oppheng)12mn | ORIGINAL | 55 | 0.00234878 | 10 | 55 | 0.0000234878 | MagiCAD Pset_Joint - Description: MagiCAD - default joint; qv_SizingFlow_ls: 0 m3/s; pTot_SizingFlow_Pa: 0 Pa; dpTot_SizingFlow_Pa: 0 Pa; v_SizingFlow_ms: 0 m/s; ConnectionSize_mm: 0 mm; Insulation_thickness_mm: 20 mm
BI20T - Cellegummi 13 mm kalde rør | Nivå D + 1,2 m | BI20T - Cellegummi 13 mm kalde rør | ORIGINAL | 58 | 0.0880789 | 484 | 58 | 0.00114975 | MagiCAD Pset_Pipe - User Code: Cu; SystemName: +TH=310.001; NationalCode: UB1.111713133; qv_SizingFlow_ls: 0 m3/s; Material: Kobberrør; Length_mm: 484 mm; ConnectionSize_mm: 18 mm; Insulation_thickness_mm: 20 mm; SystemType: KV; SystemClass: Domestic Cold Water; MagiCAD Pset_Heating - v_SizingFlow_ms: 0 m/s; pTot_SizingFlow_kPa: 0 Pa; dpTot_SizingFlow_kPa: 0 Pa; MagiCAD Pset_Water - dpTot_SizingFlow_kPa: 0 Pa; pTot_SizingFlow_kPa: 0 Pa; v_SizingFlow_ms: 0 m/s
BI16T - Rørskål m/Al.folie - VV 40mm | Nivå D + 1,2 m | BI16T - Rørskål m/Al.folie - VV 40mm | ORIGINAL | 55 | 0.0811071 | 470 | 55 | 0.00102834 | MagiCAD Pset_Pipe - User Code: Cu; SystemName: +TH=310.002; NationalCode: UB1.111713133; qv_SizingFlow_ls: 0 m3/s; Material: Kobberrør; Length_mm: 470 mm; ConnectionSize_mm: 15 mm; Insulation_thickness_mm: 20 mm; SystemType: 31 VV; SystemClass: Domestic Hot Water; MagiCAD Pset_Heating - v_SizingFlow_ms: 0 m/s; pTot_SizingFlow_kPa: 0 Pa; dpTot_SizingFlow_kPa: 0 Pa; MagiCAD Pset_Water - dpTot_SizingFlow_kPa: 0 Pa; pTot_SizingFlow_kPa: 0 Pa; v_SizingFlow_ms: 0 m/s
2 x BI16T - Rørskål m/Al.folie - VV 40mm | Nivå D + 1,2 m | BI16T - Rørskål m/Al.folie - VV 40mm | ORIGINAL | 42.5 | 0.00439181 | 55 | 42.5 | 0.0000578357 | MagiCAD Pset_Elbow - qv_SizingFlow_ls: 0 m3/s; pTot_SizingFlow_Pa: 0 Pa; dpTot_SizingFlow_Pa: 0 Pa; v_SizingFlow_ms: 0 m/s; ConnectionSize_mm: 0 mm; Description: MagiCAD - default bend; Insulation_thickness_mm: 20 mm
BI20T - Cellegummi 13 mm kalde rør | Nivå D + 1,2 m | BI20T - Cellegummi 13 mm kalde rør | ORIGINAL | 58 | 0.038944 | 214 | 58 | 0.000508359 | MagiCAD Pset_Pipe - User Code: Cu; SystemName: +TH=310.001; NationalCode: UB1.111713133; qv_SizingFlow_ls: 0 m3/s; Material: Kobberrør; Length_mm: 214 mm; ConnectionSize_mm: 18 mm; Insulation_thickness_mm: 20 mm; SystemType: KV; SystemClass: Domestic Cold Water; MagiCAD Pset_Heating - v_SizingFlow_ms: 0 m/s; pTot_SizingFlow_kPa: 0 Pa; dpTot_SizingFlow_kPa: 0 Pa; MagiCAD Pset_Water - dpTot_SizingFlow_kPa: 0 Pa; pTot_SizingFlow_kPa: 0 Pa; v_SizingFlow_ms: 0 m/s
BI16T - Rørskål m/Al.folie - VV 40mm | Nivå D + 1,2 m | BI16T - Rørskål m/Al.folie - VV 40mm | ORIGINAL | 55 | 0.00987091 | 57.2 | 55 | 0.000125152 | MagiCAD Pset_Pipe - User Code: Cu; SystemName: +TH=310.002; NationalCode: UB1.111713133; qv_SizingFlow_ls: 0 m3/s; Material: Kobberrør; Length_mm: 57.208 mm; ConnectionSize_mm: 15 mm; Insulation_thickness_mm: 20 mm; SystemType: 31 VV; SystemClass: Domestic Hot Water; MagiCAD Pset_Heating - v_SizingFlow_ms: 0 m/s; pTot_SizingFlow_kPa: 0 Pa; dpTot_SizingFlow_kPa: 0 Pa; MagiCAD Pset_Water - dpTot_SizingFlow_kPa: 0 Pa; pTot_SizingFlow_kPa: 0 Pa; v_SizingFlow_ms: 0 m/s
BI16T - Rørskål m/Al.folie - VV 40mm | Nivå D + 1,2 m | BI16T - Rørskål m/Al.folie - VV 40mm | ORIGINAL | 42.5 | 0.00439181 | 55 | 42.5 | 0.0000578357 | MagiCAD Pset_Elbow - qv_SizingFlow_ls: 0 m3/s; pTot_SizingFlow_Pa: 0 Pa; dpTot_SizingFlow_Pa: 0 Pa; v_SizingFlow_ms: 0 m/s; ConnectionSize_mm: 15 mm; Description: MagiCAD - default bend; Insulation_thickness_mm: 20 mm
BI20T - Cellegummi 13 mm kalde rør | Nivå D + 1,2 m | BI20T - Cellegummi 13 mm kalde rør | ORIGINAL | 83 | 0.0516155 | 198.2 | 83 | 0.000877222 | MagiCAD Pset_Pipe - User Code: Cu; SystemName: +TH=310.001; NationalCode: UB1.111713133; qv_SizingFlow_ls: 0 m3/s; Material: Kobberrør; Length_mm: 198.181 mm; ConnectionSize_mm: 35 mm; Insulation_thickness_mm: 24 mm; SystemType: KV; SystemClass: Domestic Cold Water; MagiCAD Pset_Heating - v_SizingFlow_ms: 0 m/s; pTot_SizingFlow_kPa: 0 Pa; dpTot_SizingFlow_kPa: 0 Pa; MagiCAD Pset_Water - dpTot_SizingFlow_kPa: 0 Pa; pTot_SizingFlow_kPa: 0 Pa; v_SizingFlow_ms: 0 m/s
BI20T - Cellegummi 13 mm kalde rør | Nivå D + 1,2 m | BI20T - Cellegummi 13 mm kalde rør | ORIGINAL | 83 | 0.00534901 | 10 | 83 | 0.0000534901 | MagiCAD Pset_Joint - Description: MagiCAD - default joint; qv_SizingFlow_ls: 0 m3/s; pTot_SizingFlow_Pa: 0 Pa; dpTot_SizingFlow_Pa: 0 Pa; v_SizingFlow_ms: 0 m/s; ConnectionSize_mm: 0 mm; Insulation_thickness_mm: 24 mm
Rørskål m/Al.folje - Varme 55 (uisolert oppheng) | Nivå D + 1,2 m | BI16T - Rørskål m/Al.folje - Varme 55 (uisolert oppheng)12mn | ORIGINAL | 58 | 0.002612 | 10 | 58 | 0.00002612 | MagiCAD Pset_Joint - Description: MagiCAD - default joint; qv_SizingFlow_ls: 0 m3/s; pTot_SizingFlow_Pa: 0 Pa; dpTot_SizingFlow_Pa: 0 Pa; v_SizingFlow_ms: 0 m/s; ConnectionSize_mm: 0 mm; Insulation_thickness_mm: 20 mm
BI20T - Cellegummi 13 mm kalde rør | Nivå D + 1,2 m | BI20T - Cellegummi 13 mm kalde rør | ORIGINAL | 58 | 0.428566 | 2355 | 58 | 0.00559432 | MagiCAD Pset_Pipe - User Code: Cu; SystemName: +TH=310.001; NationalCode: UB1.111713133; qv_SizingFlow_ls: 0 m3/s; Material: Kobberrør; Length_mm: 2355 mm; ConnectionSize_mm: 18 mm; Insulation_thickness_mm: 20 mm; SystemType: KV; SystemClass: Domestic Cold Water; MagiCAD Pset_Heating - v_SizingFlow_ms: 0 m/s; pTot_SizingFlow_kPa: 0 Pa; dpTot_SizingFlow_kPa: 0 Pa; MagiCAD Pset_Water - dpTot_SizingFlow_kPa: 0 Pa; pTot_SizingFlow_kPa: 0 Pa; v_SizingFlow_ms: 0 m/s
BI16T - Rørskål m/Al.folie - VV 40mm | Nivå D + 1,2 m | BI16T - Rørskål m/Al.folie - VV 40mm | ORIGINAL | 38.75 | 0.00213125 | 55 | 30 | 0.0000639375 | MagiCAD Pset_TBranch - qv_SizingFlow_ls: 0 m3/s; pTot_SizingFlow_Pa: 0 Pa; dpTot_SizingFlow_Pa: 0 Pa; v_SizingFlow_ms: 0 m/s; ConnectionSize_mm: 0 mm; Insulation_thickness_mm: 20 mm; Description: MagiCAD - default T-branch
BI20T - Cellegummi 13 mm kalde rør | Nivå F - 0,7 m | BI20T - Cellegummi 13 mm kalde rør | ORIGINAL | 129 | 0.0155829 | 129 | 38.5 | 0.000331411 | MagiCAD Pset_Pipe - User Code: MA; SystemName: 31= SPV Kopi 132; NationalCode: UB2.1115131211; qv_SizingFlow_ls: 0 m3/s; Material: MA; Length_mm: 38.549 mm; ConnectionSize_mm: 75 mm; Insulation_thickness_mm: 27 mm; SystemType: 31 Overvann; SystemClass: Sanitary; Product variable 1: MA; MagiCAD Pset_Heating - v_SizingFlow_ms: 0 m/s; pTot_SizingFlow_kPa: 0 Pa; dpTot_SizingFlow_kPa: 0 Pa; MagiCAD Pset_Water - dpTot_SizingFlow_kPa: 0 Pa; pTot_SizingFlow_kPa: 0 Pa; v_SizingFlow_ms: 0 m/s
BI20T - Cellegummi 13 mm kalde rør | Nivå F - 0,7 m | BI20T - Cellegummi 13 mm kalde rør | ORIGINAL | 102 | 0.0139907 | 139.387 | 125.801 | 0.00142705 | MagiCAD Pset_TBranch - qv_SizingFlow_ls: 0 m3/s; pTot_SizingFlow_Pa: 0 Pa; dpTot_SizingFlow_Pa: 0 Pa; v_SizingFlow_ms: 0 m/s; ConnectionSize_mm: 0 mm; Insulation_thickness_mm: 25 mm
BI20T - Cellegummi 13 mm kalde rør | Nivå F - 0,7 m | BI20T - Cellegummi 13 mm kalde rør | ORIGINAL | 83 | 0.00442594 | 83 | 7.4 | 0.000032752 | MagiCAD Pset_Pipe - User Code: Cu; SystemName: 31= SPV Kopi 132; NationalCode: UB1.111713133; qv_SizingFlow_ls: 0 m3/s; Material: Kobberrør; Length_mm: 7.373 mm; ConnectionSize_mm: 35 mm; Insulation_thickness_mm: 24 mm; SystemType: 31 Overvann; SystemClass: Sanitary; MagiCAD Pset_Heating - v_SizingFlow_ms: 0 m/s; pTot_SizingFlow_kPa: 0 Pa; dpTot_SizingFlow_kPa: 0 Pa; MagiCAD Pset_Water - dpTot_SizingFlow_kPa: 0 Pa; pTot_SizingFlow_kPa: 0 Pa; v_SizingFlow_ms: 0 m/s
BI20T - Cellegummi 13 mm kalde rør | Nivå F - 0,7 m | BI20T - Cellegummi 13 mm kalde rør | ORIGINAL | 83 | 0.00908871 | 34.9 | 83 | 0.000154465 | MagiCAD Pset_Pipe - User Code: Cu; SystemName: 31= SPV Kopi 132; NationalCode: UB1.111713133; qv_SizingFlow_ls: 0 m3/s; Material: Kobberrør; Length_mm: 34.875 mm; ConnectionSize_mm: 35 mm; Insulation_thickness_mm: 24 mm; SystemType: 31 Overvann; SystemClass: Sanitary; MagiCAD Pset_Heating - v_SizingFlow_ms: 0 m/s; pTot_SizingFlow_kPa: 0 Pa; dpTot_SizingFlow_kPa: 0 Pa; MagiCAD Pset_Water - dpTot_SizingFlow_kPa: 0 Pa; pTot_SizingFlow_kPa: 0 Pa; v_SizingFlow_ms: 0 m/s
BI20T - Cellegummi 13 mm kalde rør | Nivå F - 0,7 m | BI20T - Cellegummi 13 mm kalde rør | ORIGINAL | 76.3411 | 0.00623872 | 83 | 54.0937 | 0.0000995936 | MagiCAD Pset_Elbow - qv_SizingFlow_ls: 0 m3/s; pTot_SizingFlow_Pa: 0 Pa; dpTot_SizingFlow_Pa: 0 Pa; v_SizingFlow_ms: 0 m/s; ConnectionSize_mm: 0 mm; Description: MagiCAD - default bend; Insulation_thickness_mm: 24 mm
BI20T - Cellegummi 13 mm kalde rør | Nivå F - 0,7 m | BI20T - Cellegummi 13 mm kalde rør | ORIGINAL | 129 | 0.0161067 | 129 | 40 | 0.000509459 | MagiCAD Pset_Reduction - qv_SizingFlow_ls: 0 m3/s; pTot_SizingFlow_Pa: 0 Pa; dpTot_SizingFlow_Pa: 0 Pa; v_SizingFlow_ms: 0 m/s; ConnectionSize_mm: 0 mm; Insulation_thickness_mm: 27 mm; Description: MagiCAD - default reduction
2 x BI20T - Cellegummi 13 mm kalde rør | Nivå F - 0,7 m | BI20T - Cellegummi 13 mm kalde rør | ORIGINAL | 118 | 0.0326341 | 88.6 | 118 | 0.000944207 | MagiCAD Pset_Reduction - qv_SizingFlow_ls: 0 m3/s; pTot_SizingFlow_Pa: 0 Pa; dpTot_SizingFlow_Pa: 0 Pa; v_SizingFlow_ms: 0 m/s; ConnectionSize_mm: 0 mm; Insulation_thickness_mm: 25 mm
BI16T - Rørskål m/Al.folie - VV 40mm | Nivå F - 0,7 m | BI16T - Rørskål m/Al.folie - VV 40mm | ORIGINAL | 55 | 0.013978 | 81 | 55 | 0.000177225 | MagiCAD Pset_Pipe - User Code: Cu; SystemName: +TH=310.002; NationalCode: UB1.111713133; qv_SizingFlow_ls: 0 m3/s; Material: Kobberrør; Length_mm: 80.985 mm; ConnectionSize_mm: 15 mm; Insulation_thickness_mm: 20 mm; SystemType: 31 VV; SystemClass: Domestic Hot Water; MagiCAD Pset_Heating - v_SizingFlow_ms: 0 m/s; pTot_SizingFlow_kPa: 0 Pa; dpTot_SizingFlow_kPa: 0 Pa; MagiCAD Pset_Water - dpTot_SizingFlow_kPa: 0 Pa; pTot_SizingFlow_kPa: 0 Pa; v_SizingFlow_ms: 0 m/s
BI16T - Rørskål m/Al.folie - VV 40mm | Nivå F - 0,7 m | BI16T - Rørskål m/Al.folie - VV 40mm | ORIGINAL | 21.25 | 0.00194394 | 55 | 42.3266 | 0.0000192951 | MagiCAD Pset_Elbow - qv_SizingFlow_ls: 0 m3/s; pTot_SizingFlow_Pa: 0 Pa; dpTot_SizingFlow_Pa: 0 Pa; v_SizingFlow_ms: 0 m/s; ConnectionSize_mm: 0 mm; Description: MagiCAD - default bend; Insulation_thickness_mm: 20 mm
BI20T - Cellegummi 13 mm kalde rør | Nivå F - 0,7 m | BI20T - Cellegummi 13 mm kalde rør | RESULT | 108 | 0.0948846 | 10081 | 108 | 0.0653788 | MagiCAD Pset_Pipe - User Code: MA; SystemName: 31= SPV Kopi 132; NationalCode: UB2.1115131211; Material: MA; SystemType: 31 Overvann; SystemClass: Sanitary; Product variable 1: MA
BI20T - Cellegummi 13 mm kalde rør | Nivå F - 0,7 m | BI20T - Cellegummi 13 mm kalde rør | RESULT | 108 | 0.0462668 | 4915 | 108 | 0.0318794 | MagiCAD Pset_Pipe - User Code: MA; SystemName: 31= SPV Kopi 132; NationalCode: UB2.1115131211; Material: MA; SystemType: 31 Overvann; SystemClass: Sanitary; Product variable 1: MA
T=25mm | Nivå D + 1,2 m | 25mm lamellmatte | RESULT | 450 | 0.77484 | 1722 | 292 | 0.0423468 | MagiCAD Pset_Duct - NationalCode: VB2.111212; UserCode: Rect; Description: Rektangulære, Forsinket stål
BI20T - Cellegummi 13 mm kalde rør | Nivå D + 1,2 m | BI20T - Cellegummi 13 mm kalde rør | RESULT | 104 | 0.00649826 | 391 | 104 | 0.00253766 | MagiCAD Pset_Pipe - User Code: DN; SystemName: 32= T 35° Kopi 1; NationalCode: UB3.144613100; Material: Stålrør normaltykke; SystemType: GULVVARME T; SystemClass: Hydronic Supply; Product variable 1: DN
T=50mm | Nivå D + 1,2 m | BI054T - Term.isol. Lamellmatte 50mm | RESULT | 800 | 1.90845 | 2386 | 330 | 0.162218 | MagiCAD Pset_Duct - NationalCode: VB2.111212; UserCode: Rect; Description: Rektangulære, Forsinket stål
BI17T - Cellegummi 13 mm SPV fett | Nivå D + 1,2 m | BI17T - Cellegummi 13 mm SPV fett | RESULT | 168 | 0.0596227 | 4072 | 168 | 0.0512842 | MagiCAD Pset_Pipe - User Code: SUPER MA; SystemName: +TH=313.304; NationalCode: UB2.1115131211; Material: MA; SystemType: SPV FETT; SystemClass: Sanitary
T=25mm | Nivå D + 1,2 m | 25mm lamellmatte | RESULT | 1300 | 3.34154 | 2570 | 325 | 0.122095 | MagiCAD Pset_Duct - NationalCode: VB2.111212; UserCode: Rect; Description: Rektangulære, Forsinket stål

# IfcCovering: A255 - eksisterende beslag mellom himling - pirF_type__A:A255 - eksisterende beslag mellom himling - Type A (100mm sprang) (6)
In: Nivå F
Pset_QuantityTakeOff - Reference: A255 - eksisterende beslag mellom himling - Type A (100mm sprang); sets with these values: 2
ePset_Simplebim - Assembly Level: Leaf
AVINOR - 07_Fase: F90; 03_Ansvar: FDV; 08_Status: S2; 06_Omrade: TH; 01_Lufthavnkode: ENGM
ePset_SimplebimBasicQuantities - Height (Simplebim): 101 mm; Width (Simplebim): 50 mm
Name (A255 - eksisterende beslag mellom himling - pirF_type__A:A255 - eksisterende beslag mellom himling - Type A (100mm sprang):...) | Volume, net (Simplebim) (m3) | Area, largest surface, net (Simplebim) (m2) | Length (Simplebim) (mm) | Splitting | Group
38014421 | 0.000567 | 0.303 | 3000 | ORIGINAL | Model Group:A255 - eksisterende himling i pir F-0,7 / TG-TH__bak_sjakt_212,800:38014405
38014429 | 0.000567 | 0.303 | 3000 | ORIGINAL | Model Group:A255 - eksisterende himling i pir F-0,7 / TG-TH__bak_sjakt_212,800:38014405
38014508 | 0.001701 | 0.909 | 9000 | ORIGINAL | Model Group:A255 - eksisterende himling i pir F-0,7 / TG-TH__generell_(2001-A-TAG-20-6307):38014505
38014509 | 0.001701 | 0.909 | 9000 | ORIGINAL | Model Group:A255 - eksisterende himling i pir F-0,7 / TG-TH__generell_(2001-A-TAG-20-6307):38014505
38014585 | 0.000644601 | 0.344467 | 3411 | RESULT | Model Group:A255 - eksisterende himling i pir F-0,7 / TG-TH__generell_(2001-A-TAG-20-6307):38014582
38014586 | 0.000644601 | 0.344467 | 3411 | RESULT | Model Group:A255 - eksisterende himling i pir F-0,7 / TG-TH__generell_(2001-A-TAG-20-6307):38014582

# IfcCovering: A255 - eksisterende beslag mellom himling - pirF_type__B:A255 - eksisterende beslag mellom himling - Type B (305mm sprang) (3)
In: Nivå F
ePset_SimplebimBasicQuantities - Width (Simplebim): 50 mm; Height (Simplebim): 306 mm
ePset_Simplebim - Assembly Level: Leaf
AVINOR - 07_Fase: F90; 03_Ansvar: FDV; 08_Status: S2; 06_Omrade: TH; 01_Lufthavnkode: ENGM
Pset_CoveringCommon - Reference: A255 - eksisterende beslag mellom himling - Type B (305mm sprang); sets with these values: 2
Name (A255 - eksisterende beslag mellom himling - pirF_type__B:A255 - eksisterende beslag mellom himling - Type B (305mm sprang):...) | Area, largest surface, net (Simplebim) (m2) | Volume, net (Simplebim) (m3) | Length (Simplebim) (mm) | Splitting | Group
38014420 | 0.918 | 0.001182 | 3000 | ORIGINAL | Model Group:A255 - eksisterende himling i pir F-0,7 / TG-TH__bak_sjakt_212,800:38014405
38014510 | 2.754 | 0.003546 | 9000 | ORIGINAL | Model Group:A255 - eksisterende himling i pir F-0,7 / TG-TH__generell_(2001-A-TAG-20-6307):38014505
38014587 | 1.04363 | 0.00134377 | 3411 | RESULT | Model Group:A255 - eksisterende himling i pir F-0,7 / TG-TH__generell_(2001-A-TAG-20-6307):38014582

# IfcCovering: A255 - eksisterende beslag mellom himling - pirF_type__C:A255 - eksisterende beslag mellom himling - Type C (3)
In: Nivå F
ePset_Simplebim - Assembly Level: Leaf
Pset_CoveringCommon - Reference: A255 - eksisterende beslag mellom himling - Type C; sets with these values: 2
AVINOR - 07_Fase: F90; 03_Ansvar: FDV; 08_Status: S2; 06_Omrade: TH; 01_Lufthavnkode: ENGM
ePset_SimplebimBasicQuantities - Height (Simplebim): 315 mm; Width (Simplebim): 130 mm
Name (A255 - eksisterende beslag mellom himling - pirF_type__C:A255 - eksisterende beslag mellom himling - Type C:...) | Volume, net (Simplebim) (m3) | Area, largest surface, net (Simplebim) (m2) | Length (Simplebim) (mm) | Splitting | Group
38014511 | 0.00504 | 2.61 | 9000 | ORIGINAL | Model Group:A255 - eksisterende himling i pir F-0,7 / TG-TH__generell_(2001-A-TAG-20-6307):38014505
38014411 | 0.00161733 | 0.837556 | 2888 | RESULT | Model Group:A255 - eksisterende himling i pir F-0,7 / TG-TH__bak_sjakt_212,800:38014405
38014588 | 0.00190993 | 0.989063 | 3411 | RESULT | Model Group:A255 - eksisterende himling i pir F-0,7 / TG-TH__generell_(2001-A-TAG-20-6307):38014582

# IfcCovering: A255 - eksisterende beslag mellom himling - pirF_type__D:A255 - eksisterende beslag mellom himling - Type D (3)
In: Nivå F
ePset_Simplebim - Assembly Level: Leaf
AVINOR - 07_Fase: F90; 03_Ansvar: FDV; 08_Status: S2; 06_Omrade: TH; 01_Lufthavnkode: ENGM
Pset_QuantityTakeOff - Reference: A255 - eksisterende beslag mellom himling - Type D; sets with these values: 2
ePset_SimplebimBasicQuantities - Width (Simplebim): 81 mm; Height (Simplebim): 155 mm
Name (A255 - eksisterende beslag mellom himling - pirF_type__D:A255 - eksisterende beslag mellom himling - Type D:...) | Volume, net (Simplebim) (m3) | Area, largest surface, net (Simplebim) (m2) | Length (Simplebim) (mm) | Splitting | Group
38014437 | 0.001086 | 0.24 | 3000 | ORIGINAL | Model Group:A255 - eksisterende himling i pir F-0,7 / TG-TH__bak_sjakt_212,800:38014405
38014512 | 0.003258 | 0.72 | 9000 | ORIGINAL | Model Group:A255 - eksisterende himling i pir F-0,7 / TG-TH__generell_(2001-A-TAG-20-6307):38014505
38014589 | 0.00123463 | 0.272845 | 3411 | RESULT | Model Group:A255 - eksisterende himling i pir F-0,7 / TG-TH__generell_(2001-A-TAG-20-6307):38014582

# IfcCovering: Compound Ceiling:A255 - Eksisterende - Gips - 12.5 mm, Compound Ceiling:A255 - Eksisterende - Gips - 12.5 mm:38014447
In: Nivå F - 0,7 m
Type - PredefinedType: CEILING
Type - Pset_CoveringCommon - TotalThickness: 12.5 mm
Material: T2_Gips Standard 12.5 mm; Group: Model Group:A255 - eksisterende himling i pir F-0,7 / TG-TH__bak_sjakt_212,800:38014405
ePset_Simplebim - Assembly Level: Leaf
ePset_SimplebimBasicQuantities - Width (Simplebim): 376 mm; Area, largest surface, net (Simplebim): 0.329493 m2; Volume, net (Simplebim): 0.00411867 m3; Height (Simplebim): 12.5 mm; Length (Simplebim): 876.313 mm
AVINOR - 07_Fase: F90; 03_Ansvar: FDV; 08_Status: S2; 06_Omrade: TH; 01_Lufthavnkode: ENGM
Pset_CoveringCommon - Reference: A255 - Eksisterende - Gips - 12.5 mm; sets with these values: 2
ePset_LocationTool - Splitting: ORIGINAL

# IfcCovering: Compound Ceiling:A255 - HI-F02 (3)
In: Nivå F - 0,7 m
Type - PredefinedType: CEILING
Type - Pset_CoveringCommon - TotalThickness: 30 mm
Material: _NSW Himlingsplate 600x600 mm 30 mm; Group: Model Group:A184862 - Kiosk NSOPØ 05.235 2 (members excluded):47061109
ePset_Simplebim - Assembly Level: Leaf
Pset_CoveringCommon - Reference: A255 - HI-F02; sets with these values: 2
ePset_LocationTool - Splitting: ORIGINAL
AVINOR - 08_Status: S4; 07_Fase: F90; 03_Ansvar: 182412; 06_Omrade: TH; 02_Prosjekt: A184862; 01_Lufthavnkode: ENGM
ePset_SimplebimBasicQuantities - Height (Simplebim): 30 mm
Name (Compound Ceiling:A255 - HI-F02:...) | Width (Simplebim) (mm) | Volume, net (Simplebim) (m3) | Length (Simplebim) (mm) | Area, largest surface, net (Simplebim) (m2)
47060856 | 3764.5 | 1.24958 | 11166.4 | 41.6523
47060865 | 5173.95 | 0.920686 | 9669.83 | 22.9962
47061014 | 2387.99 | 0.334897 | 4913 | 11.1633

# IfcCovering: Compound Ceiling:A255 - Himling perfo. metall kassetter - 1800x600mm, Compound Ceiling:A255 - Himling perfo. metall kassetter - 1800x600mm:45657513
In: Nivå F - 0,7 m
Type - PredefinedType: CEILING
Type - Pset_CoveringCommon - TotalThickness: 30 mm
ePset_Simplebim - Assembly Level: Leaf
AVINOR - 08_Status: S4; 07_Fase: F90; 06_Omrade: TH; 03_Ansvar: 182410; 05_ID-nummer: +TH=255.001-ID0020; 01_Lufthavnkode: ENGM
ePset_LocationTool - Splitting: RESULT
Pset_CoveringCommon - Reference: A255 - Himling perfo. metall kassetter - 1800x600mm; sets with these values: 2
ePset_SimplebimBasicQuantities - Volume, net (Simplebim): 1.01321 m3; Area, largest surface, net (Simplebim): 33.7738 m2; Height (Simplebim): 30 mm; Width (Simplebim): 2208 mm; Length (Simplebim): 15299 mm
Group: Model Group:TH - Karnapper (members excluded):45660468

# IfcCovering: Compound Ceiling:A255 - Metall beslag - 2mm, Compound Ceiling:A255 - Metall beslag - 2mm:45657520
In: Nivå F - 0,7 m
Type - PredefinedType: CEILING
Type - Pset_CoveringCommon - TotalThickness: 2 mm
ePset_Simplebim - Assembly Level: Leaf
ePset_SimplebimBasicQuantities - Area, largest surface, net (Simplebim): 4.82674 m2; Height (Simplebim): 2 mm; Width (Simplebim): 315 mm; Length (Simplebim): 15299 mm; Volume, net (Simplebim): 0.00965347 m3
ePset_LocationTool - Splitting: RESULT
AVINOR - 08_Status: S4; 07_Fase: F90; 06_Omrade: TH; 03_Ansvar: 182410; 05_ID-nummer: +TH=255.001-ID0020; 01_Lufthavnkode: ENGM
Pset_CoveringCommon - Reference: A255 - Metall beslag - 2mm; sets with these values: 2
Group: Model Group:TH - Karnapper (members excluded):45660468

# IfcCovering: Compound Ceiling:A255 - Perforerte metallkasetter 3000x600 (8)
In: Nivå D + 1,2 m
Type - PredefinedType: CEILING
Type - Pset_CoveringCommon - TotalThickness: 30 mm
ePset_SimplebimBasicQuantities - Height (Simplebim): 30 mm
ePset_Simplebim - Assembly Level: Leaf
AVINOR - 08_Status: S4; 07_Fase: F90; 06_Omrade: TH; 03_Ansvar: 182410; 01_Lufthavnkode: ENGM; 05_ID-nummer: +TH=255.001-ID0032
Pset_QuantityTakeOff - Reference: A255 - Perforerte metallkasetter 3000x600; sets with these values: 2
Group: Model Group:TH - Karnapper (members excluded):45660468
Name (Compound Ceiling:A255 - Perforerte metallkasetter 3000x600:...) | Splitting | Volume, net (Simplebim) (m3) | Area, largest surface, net (Simplebim) (m2) | Length (Simplebim) (mm) | Width (Simplebim) (mm)
45658411 | ORIGINAL | 0.156689 | 5.22299 | 7304.86 | 715 | Material: T2_Himling Perforerte Metallkassetter 600 x 3000mm 30 mm
45658419 | ORIGINAL | 0.0147974 | 0.493261 | 715 | 689.856 | Material: T2_Himling Perforerte Metallkassetter 600 x 3000mm 30 mm
45657714 | RESULT | 0.218116 | 7.27056 | 3868 | 2058
45658403 | RESULT | 0.0750342 | 2.50116 | 3498 | 715
45657707 | RESULT | 0.451011 | 15.0337 | 7305 | 2058
45657672 | RESULT | 0.046871 | 1.5624 | 2058 | 1430
45657679 | RESULT | 0.16642 | 5.54729 | 2696 | 2058
45658427 | RESULT | 0.0578172 | 1.92724 | 2696 | 715

# IfcCovering: Compound Ceiling:A255 - eksisterende himling perfo. metall kassetter 600mm pir-nivåF (15)
In: Nivå F - 0,7 m
Type - PredefinedType: CEILING
Type - Pset_CoveringCommon - TotalThickness: 40 mm
ePset_Simplebim - Assembly Level: Leaf
AVINOR - 07_Fase: F90; 03_Ansvar: FDV; 08_Status: S2; 06_Omrade: TH; 01_Lufthavnkode: ENGM
ePset_SimplebimBasicQuantities - Height (Simplebim): 40 mm
Pset_CoveringCommon - Reference: A255 - eksisterende himling perfo. metall kassetter 600mm pir-nivåF; sets with these values: 2
Name (Compound Ceiling:A255 - eksisterende himling perfo. metall kassetter 600mm pir-nivåF:...) | Material | Length (Simplebim) (mm) | Area, largest surface, net (Simplebim) (m2) | Width (Simplebim) (mm) | Volume, net (Simplebim) (m3) | Splitting | Group
38014415 | _NSW Himlingsplate 600mm 40 mm | 3000 | 4.5 | 1500 | 0.18 | ORIGINAL | Model Group:A255 - eksisterende himling i pir F-0,7 / TG-TH__bak_sjakt_212,800:38014405
38014424 | _NSW Himlingsplate 600mm 40 mm | 3000 | 2.58 | 860 | 0.1032 | ORIGINAL | Model Group:A255 - eksisterende himling i pir F-0,7 / TG-TH__bak_sjakt_212,800:38014405
38014432 | _NSW Himlingsplate 600mm 40 mm | 3000 | 2.58 | 860 | 0.1032 | ORIGINAL | Model Group:A255 - eksisterende himling i pir F-0,7 / TG-TH__bak_sjakt_212,800:38014405
38014480 | _NSW Himlingsplate 600mm 40 mm | 9000 | 10.8375 | 1500 | 0.532524 | ORIGINAL | Model Group:A255 - eksisterende himling i pir F-0,7 / TG-TH__generell_(2001-A-TAG-20-6307):38014505
38014487 | _NSW Himlingsplate 600mm 40 mm | 9000 | 6.2135 | 860 | 0.305314 | ORIGINAL | Model Group:A255 - eksisterende himling i pir F-0,7 / TG-TH__generell_(2001-A-TAG-20-6307):38014505
38014494 | _NSW Himlingsplate 600mm 40 mm | 9000 | 6.2135 | 860 | 0.305314 | ORIGINAL | Model Group:A255 - eksisterende himling i pir F-0,7 / TG-TH__generell_(2001-A-TAG-20-6307):38014505
38014501 | _NSW Himlingsplate 600mm 40 mm | 9000 | 4.05 | 450 | 0.162 | ORIGINAL | Model Group:A255 - eksisterende himling i pir F-0,7 / TG-TH__generell_(2001-A-TAG-20-6307):38014505
48606585 | _NSW Himlingsplate 600mm 40 mm | 1500 | 0.2325 | 155 | 0.0093 | ORIGINAL | Model Group:A255 - eksisterende himling i pir F-0,7 / TG-TH__generell_(2001-A-TAG-20-6307):38014505
48606592 | _NSW Himlingsplate 600mm 40 mm | 860 | 0.1333 | 155 | 0.005332 | ORIGINAL | Model Group:A255 - eksisterende himling i pir F-0,7 / TG-TH__generell_(2001-A-TAG-20-6307):38014505
48606599 | _NSW Himlingsplate 600mm 40 mm | 860 | 0.1333 | 155 | 0.005332 | ORIGINAL | Model Group:A255 - eksisterende himling i pir F-0,7 / TG-TH__generell_(2001-A-TAG-20-6307):38014505
38014401 |  | 2888 | 1.29966 | 450 | 0.0519857 | RESULT | Model Group:A255 - eksisterende himling i pir F-0,7 / TG-TH__bak_sjakt_212,800:38014405
38014578 |  | 3411 | 1.53475 | 450 | 0.0613905 | RESULT | Model Group:A255 - eksisterende himling i pir F-0,7 / TG-TH__generell_(2001-A-TAG-20-6307):38014582
38014557 |  | 3411 | 5.11584 | 1500 | 0.204635 | RESULT | Model Group:A255 - eksisterende himling i pir F-0,7 / TG-TH__generell_(2001-A-TAG-20-6307):38014582
38014564 |  | 3411 | 2.93308 | 860 | 0.117324 | RESULT | Model Group:A255 - eksisterende himling i pir F-0,7 / TG-TH__generell_(2001-A-TAG-20-6307):38014582
38014571 |  | 3411 | 2.93308 | 860 | 0.117324 | RESULT | Model Group:A255 - eksisterende himling i pir F-0,7 / TG-TH__generell_(2001-A-TAG-20-6307):38014582

# IfcCovering: Compound Ceiling:A255 - eksisterende himling perfo. metall kassetter 600x600, Compound Ceiling:A255 - eksisterende himling perfo. metall kassetter 600x600:47060984
In: Nivå F - 0,7 m
Type - PredefinedType: CEILING
Type - Pset_CoveringCommon - TotalThickness: 30 mm
Material: _NSW Himlingsplate 600x600 mm 30 mm; Group: Model Group:A184862 - Kiosk NSOPØ 05.235 2 (members excluded):47061109
ePset_Simplebim - Assembly Level: Leaf
ePset_LocationTool - Splitting: ORIGINAL
ePset_SimplebimBasicQuantities - Width (Simplebim): 427.697 mm; Length (Simplebim): 2028.75 mm; Height (Simplebim): 30 mm; Area, largest surface, net (Simplebim): 0.867671 m2; Volume, net (Simplebim): 0.0260307 m3
Pset_CoveringCommon - Reference: A255 - eksisterende himling perfo. metall kassetter 600x600; sets with these values: 2
AVINOR - 08_Status: S4; 07_Fase: F90; 03_Ansvar: 182412; 06_Omrade: TH; 02_Prosjekt: A184862; 01_Lufthavnkode: ENGM

# IfcCovering: Compound Ceiling:A255 - eksisterende mineralullsystemhimling 1200x600 (2)
In: Nivå D + 1,2 m
Type - PredefinedType: CEILING
Type - Pset_CoveringCommon - TotalThickness: 50 mm
ePset_Simplebim - Assembly Level: Leaf
Pset_CoveringCommon - Reference: A255 - eksisterende mineralullsystemhimling 1200x600; sets with these values: 2
AVINOR - 07_Fase: F90; 03_Ansvar: FDV; 08_Status: S2; 06_Omrade: TH; 01_Lufthavnkode: ENGM
ePset_LocationTool - Splitting: RESULT
ePset_SimplebimBasicQuantities - Height (Simplebim): 50 mm
Name (Compound Ceiling:A255 - eksisterende mineralullsystemhimling 1200x600:...) | Area, largest surface, net (Simplebim) (m2) | Width (Simplebim) (mm) | Length (Simplebim) (mm) | Volume, net (Simplebim) (m3)
37736253 | 54.6294 | 7465 | 7800 | 2.73148
37736275 | 20.9817 | 2811 | 7465 | 1.0491

# IfcCurtainWall: Curtain Wall:A232 - UGV - Glass 30 mm (3)
In: Nivå G
AVINOR - 07_Fase: F90; 03_Ansvar: FDV; 08_Status: S2; 06_Omrade: TH; 01_Lufthavnkode: ENGM
ePset_SimplebimBasicQuantities - Length: 8910 mm; Width: 265 mm; Height: 4160 mm; Volume, net (Simplebim): 3.63083 m3
Pset_QuantityTakeOff - Reference: A232 - UGV - Glass 30 mm
Pset_CurtainWallCommon - IsExternal: yes; Reference: A232 - UGV - Glass 30 mm
ePset_Simplebim - Assembly Level: Topmost
Name (Curtain Wall:A232 - UGV - Glass 30 mm:...)
37344680
37344803
37344931

# IfcCurtainWall: Curtain Wall:A242 - IGV, Curtain Wall:A242 - IGV:45766944
In: Nivå G - 2,0 m
Pset_CurtainWallCommon - IsExternal: no; Reference: A242 - IGV
AVINOR - 08_Status: S4; 07_Fase: F90; 06_Omrade: TH; 03_Ansvar: 182410; 01_Lufthavnkode: ENGM
ePset_Simplebim - Assembly Level: Topmost
ePset_SimplebimBasicQuantities - Length: 97500 mm; Volume, net (Simplebim): 9.00534 m3; Width: 150 mm; Height: 3200 mm
Pset_QuantityTakeOff - Reference: A242 - IGV

# IfcCurtainWall: Curtain Wall:A242 - IGV 50 x 150mm (Glass 20mm) (3)
In: Nivå D + 1,2 m
Pset_CurtainWallCommon - Reference: A242 - IGV 50 x 150mm (Glass 20mm); IsExternal: no
AVINOR - 07_Fase: F90; 06_Omrade: TH; 01_Lufthavnkode: ENGM
ePset_Simplebim - Assembly Level: Topmost
Pset_QuantityTakeOff - Reference: A242 - IGV 50 x 150mm (Glass 20mm)
ePset_SimplebimBasicQuantities - Width: 200 mm
Name (Curtain Wall:A242 - IGV 50 x 150mm (Glass 20mm):...) | 08_Status | 03_Ansvar | Volume, net (Simplebim) (m3) | Height (mm) | Length (mm) | Group
6817487 | S1 | FDV | 0.798598 | 3250 | 8435
45658195 | S4 | 182410 | 0.156119 | 1700 | 2225 | Model Group:TH - Karnapper (members excluded):45660468
45658212 | S4 | 182410 | 0.124227 | 1700 | 1660 | Model Group:TH - Karnapper (members excluded):45660468

# IfcCurtainWall: Curtain Wall:A242 - T1 - IGV - Opal Glass - 14 mm, Curtain Wall:A242 - T1 - IGV - Opal Glass - 14 mm:47060834
In: Nivå F - 0,7 m
Pset_CurtainWallCommon - Reference: A242 - T1 - IGV - Opal Glass - 14 mm; IsExternal: no
Pset_QuantityTakeOff - Reference: A242 - T1 - IGV - Opal Glass - 14 mm
ePset_Simplebim - Assembly Level: Topmost
AVINOR - 08_Status: S4; 07_Fase: F90; 03_Ansvar: 182412; 06_Omrade: TH; 02_Prosjekt: A184862; 01_Lufthavnkode: ENGM
ePset_SimplebimBasicQuantities - Volume, net (Simplebim): 0.175259 m3; Width: 10 mm; Height: 2550 mm; Length: 6872.95 mm
Group: Model Group:A184862 - Kiosk NSOPØ 05.235 2 (members excluded):47061109

# IfcCurtainWall: Curtain Wall:A245 - BIM av T1 - IMK 20mm - Offset 30mm (3)
In: Nivå F - 0,7 m
Pset_QuantityTakeOff - Reference: A245 - BIM av T1 - IMK 20mm - Offset 30mm
Pset_CurtainWallCommon - Reference: A245 - BIM av T1 - IMK 20mm - Offset 30mm; IsExternal: no
AVINOR - 07_Fase: F90; 08_Status: S1; 03_Ansvar: FDV; 06_Omrade: TH; 01_Lufthavnkode: ENGM
ePset_SimplebimBasicQuantities - Width: 110 mm; Height: 5850 mm
ePset_Simplebim - Assembly Level: Topmost
Name (Curtain Wall:A245 - BIM av T1 - IMK 20mm - Offset 30mm:...) | Volume, net (Simplebim) (m3) | Length (mm)
37418633 | 0.484846 | 5280
37418738 | 0.672809 | 5390
37419040 | 0.219528 | 2082.27

# IfcCurtainWall: Curtain Wall:A245 - IMK - Metal Kledning (2)
In: Nivå F - 0,7 m
ePset_Simplebim - Assembly Level: Topmost
Pset_QuantityTakeOff - Reference: A245 - IMK - Metal Kledning
Pset_CurtainWallCommon - IsExternal: no; Reference: A245 - IMK - Metal Kledning
ePset_SimplebimBasicQuantities - Height: 2900 mm; Width: 20 mm
AVINOR - 08_Status: S4; 07_Fase: F90; 03_Ansvar: 182412; 06_Omrade: TH; 02_Prosjekt: A184862; 01_Lufthavnkode: ENGM
Group: Model Group:A184862 - Kiosk NSOPØ 05.235 2 (members excluded):47061109
Name (Curtain Wall:A245 - IMK - Metal Kledning:...) | Length (mm) | Volume, net (Simplebim) (m3)
47060833 | 2361.41 | 0.0901197
47060912 | 1392.7 | 0.0807767

# IfcDistributionControlElement: BUS Binærutgang 4-kanals
In: Nivå F - 0,7 m
Type - Description: BUS Binærutgang 4-kanals
ePset_Simplebim - Assembly Level: Leaf
ePset_LocationTool - Splitting: ORIGINAL
MagiCAD Pset_Device - System code: 5624; Host: +TH=433.065; Length [mm]: 0 mm; Height [mm]: 0 mm; Width [mm]: 0 mm; Circuit order no: 10; Manufacturer: General
Group: KNX Binærutgang

# IfcDistributionControlElement: Brann Spjeld (2)
In: Nivå F
Type - Description: Brann Spjeld
ePset_LocationTool - Splitting: ORIGINAL
ePset_Simplebim - Assembly Level: Leaf
MagiCAD Pset_Device - System code: 542; Host: +TH=434.666; Length [mm]: 0 mm; Height [mm]: 0 mm; Width [mm]: 0 mm; Product code: Addressable Luminaire; Installation Code: 2; Manufacturer: General
Group: Brannalarm
Name | Circuit order no
Brann Spjeld | 8
Brann Spjeld | 7

# IfcDistributionControlElement: Optisk Røykdetektor (7)
Type - Description: Brannalarm Røykdetektor
Classification: XJ1.1115 Not defined (NS3420); Group: Brannalarm
ePset_Simplebim - Assembly Level: Leaf
Pset_ElectricalDeviceCommon - IP_Code: IP20
ePset_LocationTool - Splitting: ORIGINAL
MagiCAD Pset_Device - System code: 542; User code: -TY; National code: XJ1.1115; IP_Code: IP20; Length [mm]: 0 mm; Installation Code: 2; Manufacturer: General
Name | In | P1 | Host | Circuit order no | Height [mm] (mm) | Width [mm] (mm)
2 x Optisk røykdetektor | Nivå D + 1,2 m | -TY | +TH=542.006 | SØLYFE 80, (17) | 45 | 100 | MagiCAD Pset_Device - Product code: Smoke detector 2
2 x Optisk Røykdetektor | Nivå D + 1,2 m | -RY |  |  | 0 | 0 | MagiCAD Pset_Device - O1: revet
3 x Optisk Røykdetektor | Nivå F | -RY | +TH=542.006 | (7) | 0 | 0

# IfcDistributionControlElement: Optisk røykdetektor over himling
In: Nivå F
Type - Description: Brannalarm Røykdetektor over himling
ePset_Simplebim - Assembly Level: Leaf
MagiCAD Pset_Device - System code: 542; User code: -TY; Host: +TH=542.006; Circuit order no: (7); Length [mm]: 0 mm; Height [mm]: 0 mm; Width [mm]: 0 mm; Installation Code: 2
ePset_LocationTool - Splitting: ORIGINAL
Group: Brannalarm

# IfcDoor: A20 - Slagdør - Enkel2:A243 - DI_LTO - 1090 x 2090 mm, A20 - Slagdør - Enkel2:A243 - DI_LTO - 1090 x 2090 mm:47060831
In: Nivå F - 0,7 m
Type - OperationType: SINGLE_SWING_RIGHT; ParameterTakesPrecedence: no; Sizeable: no; Material: N_Door - Handle, _NSW Stål - rustfritt, _NSW Dør - karm, hvit, N_Door - Threshold, N_Door - Panel
Type - IfcDoorPanelProperties - PanelOperation: SWINGING
OverallHeight: 2110 mm; OverallWidth: 1110 mm; Group: Model Group:A184862 - Kiosk NSOPØ 05.235 2 (members excluded):47061109
Pset_QuantityTakeOff - Reference: A243 - DI_LTO - 1090 x 2090 mm
ePset_Simplebim - Assembly Level: Leaf
ePset_LocationTool - Splitting: ORIGINAL
Pset_DoorCommon - Reference: A243 - DI_LTO - 1090 x 2090 mm; IsExternal: no
ePset_SimplebimBasicQuantities - Area, opening (Simplebim): 2.3421 m2; Height, opening (Simplebim): 2110 mm; Area (Simplebim): 2.2781 m2; Width, opening (Simplebim): 1110 mm; Width (Simplebim): 1090 mm; Height (Simplebim): 2090 mm; Length, frame (Simplebim): 5270 mm
AVINOR - 08_Status: S4; 07_Fase: F90; 03_Ansvar: 182412; 06_Omrade: TH; 02_Prosjekt: A184862; 05_ID-nummer: +TH=243.001-IP0243; 01_Lufthavnkode: ENGM

# IfcDoor: A20 - Slagdør - Enkel:A243 - DI_LTO - 0790 x 2240 mm, A20 - Slagdør - Enkel:A243 - DI_LTO - 0790 x 2240 mm:2640284
In: Nivå F - 0,7 m
Type - OperationType: SINGLE_SWING_RIGHT; ParameterTakesPrecedence: no; Sizeable: no; Material: N_Door - Handle, _NSW Stål - rustfritt, _NSW Dør - karm, hvit, N_Door - Threshold, N_Door - Panel
Type - IfcDoorPanelProperties - PanelOperation: SWINGING
OverallHeight: 2260 mm; OverallWidth: 810 mm
Pset_DoorCommon - Reference: A243 - DI_LTO - 0790 x 2240 mm; IsExternal: no
Pset_QuantityTakeOff - Reference: A243 - DI_LTO - 0790 x 2240 mm
ePset_Simplebim - Assembly Level: Leaf
AVINOR - 07_Fase: F90; 03_Ansvar: FDV; 08_Status: S2; 06_Omrade: TH; 01_Lufthavnkode: ENGM
ePset_SimplebimBasicQuantities - Height, opening (Simplebim): 2260 mm; Area, opening (Simplebim): 1.8306 m2; Area (Simplebim): 1.7696 m2; Width (Simplebim): 790 mm; Width, opening (Simplebim): 810 mm; Height (Simplebim): 2240 mm; Length, frame (Simplebim): 5270 mm
ePset_LocationTool - Splitting: ORIGINAL

# IfcElectricalCircuit (8)
Name | Description
Belysningsutstyr | 442
Kursopplegg belysningsutstyr | 441
Kursopplegg driftsteknisk | 461
Utstyr for nødlys | 443
Kursopplegg for underfordelinger | 4332
KNX Ventilmotor | 5625
Gulvboks | 4115
Nødlys | 443

# IfcEnergyConversionDevice: GCS2.UWW.K01 (3)
In: Nivå F - 0,7 m
Type - Description: Casette fancoil; PredefinedType: WATERHEATINGCOIL
ePset_LocationTool - Splitting: ORIGINAL
ePset_Simplebim - Assembly Level: Leaf
MagiCAD Pset_FanCoilUnit - ProductCode: GCS2.UWW.K01; Description: Casette fancoil; qv_SizingFlow_ls: 0 m3/s; dpTot_SizingFlow_Pa: 0 Pa; qv_SizingFlow_ms: 0 m/s; Manufacturer: GEA; User Code: FC05

# IfcFlowController: 2006015
In: Nivå F - 0,7 m
Type - Description: Bryter 2-polet påvegg
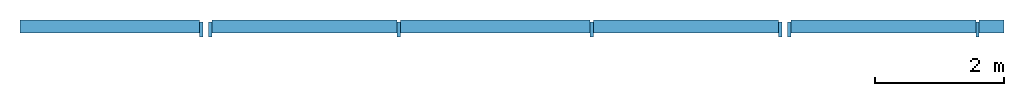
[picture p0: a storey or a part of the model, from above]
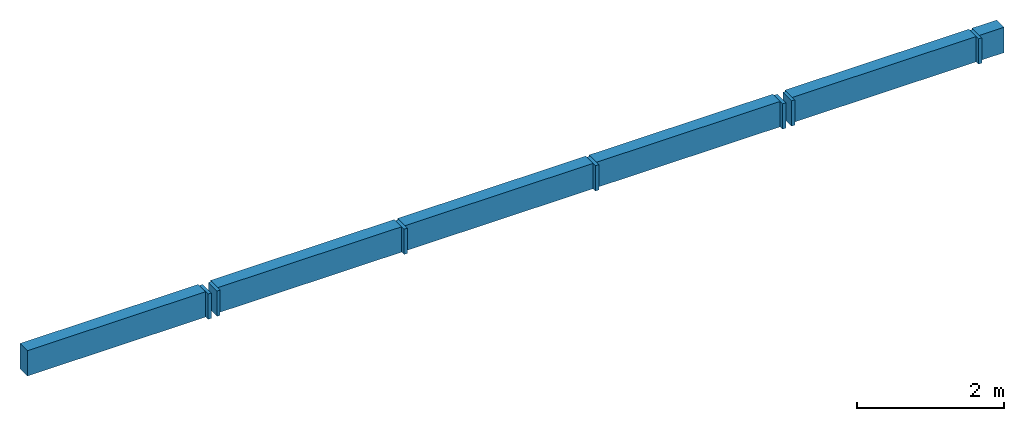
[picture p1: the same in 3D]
Properties of the parts of a building model (IFC2X3), part 4 of 7

# IfcFlowController: 2006015
Description: Bryter 1-polet påvegg; Classification: WL1.311 Not defined (NS3420); Group: Kursopplegg belysningsutstyr
Pset_ElectricalDeviceCommon - ElectricalDeviceNominalPower: 0 W; NumberOfPoles: 1; NominalVoltage: 230; IP_Code: IP21
ePset_Simplebim - Assembly Level: Leaf
MagiCAD Pset_Device - System code: 441; Product code: 2006015; National code: WL1.311; Circuit order no: 32; Switchboard: +TH=433.055; P1: -XS; Length [mm]: 0 mm; Number of Poles: 1; Active Power: 0 W; User code: 50; Manufacturer: General; Power Factor: 1; Width [mm]: 10 mm; Height [mm]: 60 mm; Voltage: 230; IP_Code: IP21
ePset_LocationTool - Splitting: ORIGINAL

# IfcFlowController: AT3600-15 (2)
In: Nivå D + 1,2 m
Type - Description: Ball valve, threaded, brass
ePset_Simplebim - Assembly Level: Leaf
MagiCAD Pset_Valve - Description: Ball valve, threaded, brass; User Code: SMA.001; qv_SizingFlow_ls: 0 m3/s; pTot_SizingFlow_kPa: 0 Pa; dpTot_SizingFlow_kPa: 0 Pa; Manufacturer: Armatec; Product variable 2: 001; Product variable 4: 4; Product variable 1: SMA; NationalCode: UC1.30001; Product Code: AT3600-15
ePset_LocationTool - Splitting: ORIGINAL
Group: +TH=310.002
Name | Insulation_thickness_mm (mm)
AT3600-15 | 20
AT3600-15 | 0

# IfcFlowController: AT3600-20 (4)
Type - Description: Ball valve, threaded, brass
ePset_Simplebim - Assembly Level: Leaf
ePset_LocationTool - Splitting: ORIGINAL
MagiCAD Pset_Valve - Description: Ball valve, threaded, brass; qv_SizingFlow_ls: 0 m3/s; pTot_SizingFlow_kPa: 0 Pa; dpTot_SizingFlow_kPa: 0 Pa; Manufacturer: Armatec; Product Code: AT3600-20
Name | In | User Code | Product variable 2 | Product variable 4 | Insulation_thickness_mm (mm) | Product variable 1 | NationalCode | Group
AT3600-20 | Nivå D + 1,2 m | SMA.001 | 001 | 4 | 30 | SMA | UC1.30001 | +TH=310.002
AT3600-20 | Nivå D + 1,2 m | SMA.001 | 001 | 4 | 21 | SMA | UC1.30001 | +TH=310.001
AT3600-20 | Nivå D + 1,2 m | SMA.001 | 001 | 4 | 20 | SMA | UC1.30001 | +TH=310.001
AT3600-20 | Nivå F - 0,7 m | SM01T |  |  | 0 |  |  | 37= T 9° Kopi 2

# IfcFlowController: AT3600-25
In: Nivå F - 0,7 m
Type - Description: Ball valve, threaded, brass
ePset_Simplebim - Assembly Level: Leaf
MagiCAD Pset_Valve - Description: Ball valve, threaded, brass; qv_SizingFlow_ls: 0 m3/s; pTot_SizingFlow_kPa: 0 Pa; dpTot_SizingFlow_kPa: 0 Pa; Insulation_thickness_mm: 0 mm; Manufacturer: Armatec; Product Code: AT3600-25; User Code: SM01T
ePset_LocationTool - Splitting: ORIGINAL
Group: 31=KV Kopi 23

# IfcFlowController: AT3600-32 (2)
Type - Description: Ball valve, threaded, brass
ePset_Simplebim - Assembly Level: Leaf
MagiCAD Pset_Valve - Product Code: AT3600-32; Description: Ball valve, threaded, brass; qv_SizingFlow_ls: 0 m3/s; pTot_SizingFlow_kPa: 0 Pa; dpTot_SizingFlow_kPa: 0 Pa; Manufacturer: Armatec
ePset_LocationTool - Splitting: ORIGINAL
Name | In | User Code | Insulation_thickness_mm (mm) | Group
AT3600-32 | Nivå D + 1,2 m | SMA.001 | 24 | +TH=310.001 | MagiCAD Pset_Valve - Product variable 2: 001; Product variable 4: 4; Product variable 1: SMA; NationalCode: UC1.30001
AT3600-32 | Nivå F - 0,7 m | SM01T | 0 | 37= T 9° Kopi 2

# IfcFlowController: IGNIS-C-EI120-400
In: Nivå D + 1,2 m
Type - Description: BRANNSPJELD EI120 Ø200; PredefinedType: FIREDAMPER
Description: CIRCULAR FIRE DAMPER CLASS EI120 ø100-160; Group: +TH=360.031 TL (1)
ePset_Simplebim - Assembly Level: Leaf
ePset_LocationTool - Splitting: ORIGINAL
MagiCAD Pset_FireDamper - Product Code: IGNIS-C-EI60-400; User Code: SWEGON 120; Manufacturer: Swegon AB; qv_SizingFlow_ls: 0 m3/s; pTot_SizingFlow_Pa: 0 Pa; dpTot_SizingFlow_Pa: 0 Pa; v_SizingFlow_ms: 0 m/s; ConnectionSize_mm: 400; Description: CIRCULAR FIRE DAMPER CLASS EI120 ø100-160

# IfcFlowController: IGNIS-C-EI60-315
In: Nivå D + 1,2 m
Type - Description: CIRCULAR FIRE DAMPER CLASS EI60; PredefinedType: FIREDAMPER
ePset_Simplebim - Assembly Level: Leaf
MagiCAD Pset_FireDamper - Product Code: IGNIS-C-EI60-315; Manufacturer: Swegon AB; qv_SizingFlow_ls: 0 m3/s; pTot_SizingFlow_Pa: 0 Pa; dpTot_SizingFlow_Pa: 0 Pa; v_SizingFlow_ms: 0 m/s; Description: CIRCULAR FIRE DAMPER CLASS EI60; User Code: SWEGON 60
ePset_LocationTool - Splitting: ORIGINAL
Group: +TH=360.031

# IfcFlowController: IRIS-160
In: Nivå F - 0,7 m
Type - Description: Balancing damper; PredefinedType: BALANCINGDAMPER
Description: INNREG SPJELD; Classification: - Not defined (NS3420); Group: 36= Avtrekk 15
ePset_Simplebim - Assembly Level: Leaf
MagiCAD Pset_FlowDamper - Manufacturer: Flakt Woods; User Code: SR001T; qv_SizingFlow_ls: 0 m3/s; pTot_SizingFlow_Pa: 0 Pa; dpTot_SizingFlow_Pa: 0 Pa; v_SizingFlow_ms: 0 m/s; ConnectionSize_mm: 400; Product variable 4: 4; NationalCode: -; Product Code: IRIS-160; Description: INNREG SPJELD
ePset_LocationTool - Splitting: ORIGINAL

# IfcFlowController: IRIS-315 2
In: Nivå F - 0,7 m
Type - PredefinedType: BALANCINGDAMPER
MagiCAD Pset_FlowDamper - ConnectionSize_mm: 315; qv_SizingFlow_ls: 0 m3/s; pTot_SizingFlow_Pa: 0 Pa; dpTot_SizingFlow_Pa: 0 Pa; v_SizingFlow_ms: 0 m/s; Product Code: IRIS-315; Manufacturer: Oeland
ePset_Simplebim - Assembly Level: Leaf
ePset_LocationTool - Splitting: ORIGINAL
Group: +TH=360.031 TL (1)

# IfcFlowController: IRIS-400
In: Nivå F - 0,7 m
Type - Description: INNREG SPJELD; PredefinedType: BALANCINGDAMPER
ePset_LocationTool - Splitting: ORIGINAL
ePset_Simplebim - Assembly Level: Leaf
MagiCAD Pset_FlowDamper - Product Code: IRIS-400; qv_SizingFlow_ls: 0 m3/s; pTot_SizingFlow_Pa: 0 Pa; dpTot_SizingFlow_Pa: 0 Pa; v_SizingFlow_ms: 0 m/s; ConnectionSize_mm: 400; Manufacturer: Oeland
Group: +TH=360.031 TL (1)

# IfcFlowController: Light dimmer (2)
In: Nivå F - 0,7 m
Type - Description: Snorbryter m/boks
Classification: WL1.311 Not defined (NS3420); Group: Kursopplegg for underfordelinger
ePset_Simplebim - Assembly Level: Leaf
ePset_LocationTool - Splitting: ORIGINAL
MagiCAD Pset_Device - National code: WL1.311; System code: 4332; P1: -XS; Length [mm]: 0 mm; Number of Poles: 1; Active Power: 0 W; IP_Code: 20; Manufacturer: General; Product code: Light dimmer; Power Factor: 1; Width [mm]: 56 mm; Height [mm]: 85 mm; Voltage: 230; User code: 06
Pset_ElectricalDeviceCommon - ElectricalDeviceNominalPower: 0 W; NumberOfPoles: 1; IP_Code: 20; NominalVoltage: 230

# IfcFlowController: STAD/F-32 (2)
In: Nivå F - 0,7 m
Type - Description: Presetting of flow, shut-off valve, flow measuring,pressure reading 10-50
MagiCAD Pset_Valve - Product Code: STAD/F-32; Manufacturer: TA; qv_SizingFlow_ls: 0 m3/s; pTot_SizingFlow_kPa: 0 Pa; dpTot_SizingFlow_kPa: 0 Pa; Insulation_thickness_mm: 0 mm; Description: Presetting of flow, shut-off valve, flow measuring,pressure reading 10-50; NationalCode: UL5.11091; User Code: SV01T
ePset_LocationTool - Splitting: ORIGINAL
ePset_Simplebim - Assembly Level: Leaf
Group: 37= R 18° Kopi 1

# IfcFlowFitting: +TH=360.030-AP9001-2000x1000x500
In: Nivå F - 0,7 m
Type - PredefinedType: BEND
MagiCAD Pset_Elbow - Insulation_thickness_mm: 0 mm; qv_SizingFlow_ls: 0 m3/s; pTot_SizingFlow_Pa: 0 Pa; dpTot_SizingFlow_Pa: 0 Pa; v_SizingFlow_ms: 0 m/s; ConnectionSize_mm: 0 mm
ePset_LocationTool - Splitting: ORIGINAL
ePset_Simplebim - Assembly Level: Leaf

# IfcFlowFitting: Kabelbro, bend
In: Nivå D + 1,2 m
Type - PredefinedType: BEND
ePset_Simplebim - Assembly Level: Leaf
ePset_LocationTool - Splitting: ORIGINAL
MagiCAD Pset_Cabletray - System code: 4111; Width [mm]: 0 mm; Height [mm]: 0 mm; Length [mm]: 0 mm
Group: Bæresystem for elkraft

# IfcFlowFitting: Kabelbro, bend vertikal (Inside) (4)
In: Nivå D + 1,2 m
Type - PredefinedType: BEND
ePset_LocationTool - Splitting: ORIGINAL
ePset_Simplebim - Assembly Level: Leaf
MagiCAD Pset_Cabletray - Width [mm]: 0 mm; Height [mm]: 0 mm; Length [mm]: 0 mm
Name | System code | Group
3 x Kabelbro, bend vertikal (Inside) | 4111 | Bæresystem for elkraft
Kabelbro, bend vertikal (Inside) | 410 | Bæresystem generelt

# IfcFlowFitting: Kabelbro, bend vertikal (Outside) (4)
In: Nivå D + 1,2 m
Type - PredefinedType: BEND
ePset_Simplebim - Assembly Level: Leaf
MagiCAD Pset_Cabletray - Width [mm]: 0 mm; Height [mm]: 0 mm; Length [mm]: 0 mm
ePset_LocationTool - Splitting: ORIGINAL
Name | System code | Group
3 x Kabelbro, bend vertikal (Outside) | 4111 | Bæresystem for elkraft
Kabelbro, bend vertikal (Outside) | 410 | Bæresystem generelt

# IfcFlowFitting: Koblingsboks åpen (12)
Type - Description: Koblingsboks åpen
Pset_ElectricalDeviceCommon - IP_Code: IP20; ElectricalDeviceNominalPower: 0 W; NumberOfPoles: 1; NominalVoltage: 230
ePset_Simplebim - Assembly Level: Leaf
ePset_LocationTool - Splitting: ORIGINAL
MagiCAD Pset_Device - IP_Code: IP20; P1: -XD; Length [mm]: 0 mm; Number of Poles: 1; Active Power: 0 W; Manufacturer: General; Power Factor: 1; Width [mm]: 46 mm; Height [mm]: 104 mm; Voltage: 230; Product code: Junction box1
Name | In | System code | Group | Circuit order no | Switchboard
Koblingsboks åpen | Nivå D + 1,2 m | 461 | Kursopplegg driftsteknisk
2 x Koblingsboks åpen | Nivå D + 1,2 m | 441 | Kursopplegg belysningsutstyr
Koblingsboks åpen | Nivå D + 1,2 m | 441 | Kursopplegg belysningsutstyr | <unnamed>
Koblingsboks åpen | Nivå D + 1,2 m | 4332 | Kursopplegg for underfordelinger | 1 | +TH=443.432 | MagiCAD Pset_Device - O1: KOBLINGSBOKS FOR: +TH=443.442-WC0601, -WD0601
2 x Koblingsboks åpen | Nivå D + 1,2 m | 4332 | Kursopplegg for underfordelinger | 1 | +TH=443.432 | MagiCAD Pset_Device - O1: KOBLINGSBOKS FOR: +TH=443.432-WC0601, -WD0601
Koblingsboks åpen | Nivå F - 0,7 m | 441 | Kursopplegg belysningsutstyr | 32 | +TH=433.055
2 x Koblingsboks åpen | Nivå F - 0,7 m | 461 | Kursopplegg driftsteknisk | 6 | +TH=433.065
2 x Koblingsboks åpen | Nivå F - 0,7 m | 4332 | Kursopplegg for underfordelinger | 7 | +TH=433.065

# IfcFlowFitting: LEPR (4)
Type - PredefinedType: OBSTRUCTION
ePset_Simplebim - Assembly Level: Leaf
Name | In | Splitting | Group
LEPR | Nivå D + 1,2 m | ORIGINAL | +TH=360.031 TL (1) | MagiCAD Pset_Plug - ConnectionSize_mm: 0 mm; pTot_SizingFlow_kPa: 0 Pa; Insulation_thickness_mm: 25 mm
LEPR | Nivå D + 1,2 m | ORIGINAL | +TH=360.031 TL (1) | MagiCAD Pset_Plug - ConnectionSize_mm: 0 mm; pTot_SizingFlow_kPa: 0 Pa; Insulation_thickness_mm: 50 mm; National code: VB3.29112; Description: Endelokk; Product variable 4: 2; Description: Endelokk
2 x LEPR | Nivå F - 0,7 m | RESULT | +TH=360.010 (28)

# IfcFlowFitting: NedføringsStaver (3)
In: Nivå F - 0,7 m
ePset_LocationTool - Splitting: ORIGINAL
ePset_Simplebim - Assembly Level: Leaf
Group: Bæresystem generelt

# IfcFlowFitting: WA
In: Nivå D + 1,2 m
Type - PredefinedType: BEND
ePset_Simplebim - Assembly Level: Leaf
ePset_LocationTool - Splitting: RESULT

# IfcFlowFitting: magi_pipe_cu_elbow_short_001 (54)
Type - Description: MagiCAD - default bend; PredefinedType: BEND
ePset_LocationTool - Splitting: ORIGINAL
ePset_Simplebim - Assembly Level: Leaf
MagiCAD Pset_Elbow - qv_SizingFlow_ls: 0 m3/s; pTot_SizingFlow_Pa: 0 Pa; dpTot_SizingFlow_Pa: 0 Pa; v_SizingFlow_ms: 0 m/s; Description: MagiCAD - default bend
Name | In | Insulation_thickness_mm (mm) | ConnectionSize_mm (mm) | Group
magi_pipe_cu_elbow_short_001 | Nivå D + 1,2 m | 0 | 0 | 31=KV Kopi 23
magi_pipe_cu_elbow_short_001 | Nivå D + 1,2 m | 0 | 0 | +TH=310.002
8 x magi_pipe_cu_elbow_short_001 | Nivå D + 1,2 m | 20 | 0 | +TH=310.001
5 x magi_pipe_cu_elbow_short_001 | Nivå D + 1,2 m | 20 | 0 | +TH=310.002
5 x magi_pipe_cu_elbow_short_001 | Nivå D + 1,2 m | 0 | 0 | 31= SPV Kopi 47
2 x magi_pipe_cu_elbow_short_001 | Nivå D + 1,2 m | 24 | 0 | +TH=310.001
2 x magi_pipe_cu_elbow_short_001 | Nivå D + 1,2 m | 20 | 0 | +TH=310.003
magi_pipe_cu_elbow_short_001 | Nivå D + 1,2 m | 0 | 0 | +TH=310.003
magi_pipe_cu_elbow_short_001 | Nivå D + 1,2 m | 20 | 15 | +TH=310.002
7 x magi_pipe_cu_elbow_short_001 | Nivå F - 0,7 m | 0 | 0 | 31=KV Kopi 23
4 x magi_pipe_cu_elbow_short_001 | Nivå F - 0,7 m | 0 | 0 | +TH=310.002
magi_pipe_cu_elbow_short_001 | Nivå F - 0,7 m | 24 | 0 | 31= SPV Kopi 132
3 x magi_pipe_cu_elbow_short_001 | Nivå F - 0,7 m | 0 | 0 | +TH=310.001
magi_pipe_cu_elbow_short_001 | Nivå F - 0,7 m | 20 | 0 | +TH=310.002
10 x magi_pipe_cu_elbow_short_001 | Nivå F - 0,7 m | 0 | 0 | 31= SPV Kopi 47
2 x magi_pipe_cu_elbow_short_001 | Nivå F - 0,7 m | 0 | 0 | +TH=310.003

# IfcFlowFitting: magi_pipe_cu_joint_001 (9)
In: Nivå D + 1,2 m
Type - PredefinedType: CONNECTOR
Description: MagiCAD - default joint
MagiCAD Pset_Joint - Description: MagiCAD - default joint; qv_SizingFlow_ls: 0 m3/s; pTot_SizingFlow_Pa: 0 Pa; dpTot_SizingFlow_Pa: 0 Pa; v_SizingFlow_ms: 0 m/s; ConnectionSize_mm: 0 mm
ePset_Simplebim - Assembly Level: Leaf
ePset_LocationTool - Splitting: ORIGINAL
Name | Insulation_thickness_mm (mm) | Group
magi_pipe_cu_joint_001 | 0 | +TH=310.001
magi_pipe_cu_joint_001 | 0 | +TH=310.002
3 x magi_pipe_cu_joint_001 | 20 | +TH=310.001
2 x magi_pipe_cu_joint_001 | 20 | +TH=310.003
magi_pipe_cu_joint_001 | 24 | +TH=310.001
magi_pipe_cu_joint_001 | 20 | +TH=310.002

# IfcFlowFitting: magi_pipe_cu_reducer_centric_short_001 (15)
Type - PredefinedType: TRANSITION
Description: MagiCAD - default reduction
ePset_Simplebim - Assembly Level: Leaf
MagiCAD Pset_Reduction - qv_SizingFlow_ls: 0 m3/s; pTot_SizingFlow_Pa: 0 Pa; dpTot_SizingFlow_Pa: 0 Pa; v_SizingFlow_ms: 0 m/s; ConnectionSize_mm: 0 mm; Description: MagiCAD - default reduction
ePset_LocationTool - Splitting: ORIGINAL
Name | In | Insulation_thickness_mm (mm) | Group
magi_pipe_cu_reducer_centric_short_001 | Nivå D + 1,2 m | 0 | +TH=310.001
2 x magi_pipe_cu_reducer_centric_short_001 | Nivå D + 1,2 m | 30 | +TH=310.002
2 x magi_pipe_cu_reducer_centric_short_001 | Nivå D + 1,2 m | 24 | +TH=310.001
magi_pipe_cu_reducer_centric_short_001 | Nivå D + 1,2 m | 21 | +TH=310.001
4 x magi_pipe_cu_reducer_centric_short_001 | Nivå D + 1,2 m | 20 | +TH=310.001
4 x magi_pipe_cu_reducer_centric_short_001 | Nivå F - 0,7 m | 0 | 31=KV Kopi 23
magi_pipe_cu_reducer_centric_short_001 | Nivå F - 0,7 m | 27 | 31= SPV Kopi 132

# IfcFlowFitting: magi_pipe_cu_tee_centric_90_001 (7)
Type - Description: MagiCAD - default T-branch; PredefinedType: JUNCTION
ePset_Simplebim - Assembly Level: Leaf
MagiCAD Pset_TBranch - qv_SizingFlow_ls: 0 m3/s; pTot_SizingFlow_Pa: 0 Pa; dpTot_SizingFlow_Pa: 0 Pa; v_SizingFlow_ms: 0 m/s; ConnectionSize_mm: 0 mm; Description: MagiCAD - default T-branch
ePset_LocationTool - Splitting: ORIGINAL
Name | In | Insulation_thickness_mm (mm) | Group
magi_pipe_cu_tee_centric_90_001 | Nivå D + 1,2 m | 0 | 31= SPV Kopi 47
magi_pipe_cu_tee_centric_90_001 | Nivå D + 1,2 m | 20 | +TH=310.001
magi_pipe_cu_tee_centric_90_001 | Nivå D + 1,2 m | 24 | +TH=310.001
2 x magi_pipe_cu_tee_centric_90_001 | Nivå D + 1,2 m | 20 | +TH=310.002
magi_pipe_cu_tee_centric_90_001 | Nivå F - 0,7 m | 0 | 31=KV Kopi 23
magi_pipe_cu_tee_centric_90_001 | Nivå F - 0,7 m | 0 | +TH=310.002

# IfcFlowFitting: magi_pipe_fe_cross_centric_90_001 (4)
In: Nivå F - 0,7 m
Type - PredefinedType: JUNCTION
MagiCAD Pset_XBranch - Insulation_thickness_mm: 0 mm; qv_SizingFlow_ls: 0 m3/s; pTot_SizingFlow_Pa: 0 Pa; dpTot_SizingFlow_Pa: 0 Pa; v_SizingFlow_ms: 0 m/s; ConnectionSize_mm: 0 mm
ePset_LocationTool - Splitting: ORIGINAL
ePset_Simplebim - Assembly Level: Leaf
Name | Group
magi_pipe_fe_cross_centric_90_001 | +TH=332.003
magi_pipe_fe_cross_centric_90_001 | 33= Våt Kopi 36
magi_pipe_fe_cross_centric_90_001 | 33= Våt Kopi 37
magi_pipe_fe_cross_centric_90_001 | 33= Våt Kopi 39

# IfcFlowFitting: magi_pipe_fe_elbow_short_001 (114)
Type - PredefinedType: BEND
MagiCAD Pset_Elbow - qv_SizingFlow_ls: 0 m3/s; pTot_SizingFlow_Pa: 0 Pa; dpTot_SizingFlow_Pa: 0 Pa; v_SizingFlow_ms: 0 m/s; ConnectionSize_mm: 0 mm
ePset_Simplebim - Assembly Level: Leaf
ePset_LocationTool - Splitting: ORIGINAL
Name | In | Insulation_thickness_mm (mm) | Group
10 x magi_pipe_fe_elbow_short_001 | Nivå D + 1,2 m | 0 | 33= Våt Kopi 163
7 x magi_pipe_fe_elbow_short_001 | Nivå F - 0,7 m | 0 | 33= Våt Kopi 64
37 x magi_pipe_fe_elbow_short_001 | Nivå F - 0,7 m | 0 | +TH=332.003
magi_pipe_fe_elbow_short_001 | Nivå F - 0,7 m | 0 | 33= Våt Kopi 98
2 x magi_pipe_fe_elbow_short_001 | Nivå F - 0,7 m | 0 | 33= Våt Kopi 36
2 x magi_pipe_fe_elbow_short_001 | Nivå F - 0,7 m | 0 | 33= Våt Kopi 37
2 x magi_pipe_fe_elbow_short_001 | Nivå F - 0,7 m | 0 | 33= Våt Kopi 39
2 x magi_pipe_fe_elbow_short_001 | Nivå D + 1,2 m | 0 | 32= R 27° Kopi 5
2 x magi_pipe_fe_elbow_short_001 | Nivå D + 1,2 m | 0 | 32= T 35° Kopi 1
4 x magi_pipe_fe_elbow_short_001 | Nivå D + 1,2 m | 0 | +TH=313.310
2 x magi_pipe_fe_elbow_short_001 | Nivå D + 1,2 m | 0 | 37= T 9° Kopi 2
2 x magi_pipe_fe_elbow_short_001 | Nivå D + 1,2 m | 0 | 37= R 18° Kopi 1
magi_pipe_fe_elbow_short_001 | Nivå D + 1,2 m | 0 | 31= SPV Kopi 61
magi_pipe_fe_elbow_short_001 | Nivå D + 1,2 m | 27 | 32= R 27° Kopi 5
magi_pipe_fe_elbow_short_001 | Nivå D + 1,2 m | 27 | 32= T 35° Kopi 1
18 x magi_pipe_fe_elbow_short_001 | Nivå F - 0,7 m | 0 | 37= T 9° Kopi 2
18 x magi_pipe_fe_elbow_short_001 | Nivå F - 0,7 m | 0 | 37= R 18° Kopi 1
magi_pipe_fe_elbow_short_001 | Nivå F - 0,7 m | 0 | 32= R 27° Kopi 5
magi_pipe_fe_elbow_short_001 | Nivå F - 0,7 m | 0 | 32= T 35° Kopi 1

# IfcFlowFitting: magi_pipe_fe_joint_001
In: Nivå D + 1,2 m
Type - PredefinedType: CONNECTOR
MagiCAD Pset_Joint - Insulation_thickness_mm: 0 mm; qv_SizingFlow_ls: 0 m3/s; pTot_SizingFlow_Pa: 0 Pa; dpTot_SizingFlow_Pa: 0 Pa; v_SizingFlow_ms: 0 m/s; ConnectionSize_mm: 0 mm
ePset_Simplebim - Assembly Level: Leaf
ePset_LocationTool - Splitting: ORIGINAL
Group: 31= SPV Kopi 61

# IfcFlowFitting: magi_pipe_fe_plug_001 (3)
In: Nivå D + 1,2 m
Type - PredefinedType: OBSTRUCTION
MagiCAD Pset_Plug - ConnectionSize_mm: 0 mm; pTot_SizingFlow_kPa: 0 Pa; Insulation_thickness_mm: 0 mm
ePset_Simplebim - Assembly Level: Leaf
ePset_LocationTool - Splitting: ORIGINAL
Name | Group
magi_pipe_fe_plug_001 | 37= R 18° Kopi 1
magi_pipe_fe_plug_001 | 37= T 9° Kopi 2
magi_pipe_fe_plug_001 | +TH=310.002

# IfcFlowFitting: magi_pipe_fe_reducer_centric_short_NOR (64)
Type - PredefinedType: TRANSITION
MagiCAD Pset_Reduction - Insulation_thickness_mm: 0 mm; qv_SizingFlow_ls: 0 m3/s; pTot_SizingFlow_Pa: 0 Pa; dpTot_SizingFlow_Pa: 0 Pa; v_SizingFlow_ms: 0 m/s; ConnectionSize_mm: 0 mm
ePset_LocationTool - Splitting: ORIGINAL
ePset_Simplebim - Assembly Level: Leaf
Name | In | Group
14 x magi_pipe_fe_reducer_centric_short_NOR | Nivå D + 1,2 m | 33= Våt Kopi 163
3 x magi_pipe_fe_reducer_centric_short_NOR | Nivå F - 0,7 m | 33= Våt Kopi 64
32 x magi_pipe_fe_reducer_centric_short_NOR | Nivå F - 0,7 m | +TH=332.003
magi_pipe_fe_reducer_centric_short_NOR | Nivå F - 0,7 m | 33= Våt Kopi 98
2 x magi_pipe_fe_reducer_centric_short_NOR | Nivå F - 0,7 m | 33= Våt Kopi 36
2 x magi_pipe_fe_reducer_centric_short_NOR | Nivå F - 0,7 m | 33= Våt Kopi 37
2 x magi_pipe_fe_reducer_centric_short_NOR | Nivå F - 0,7 m | 33= Våt Kopi 39
5 x magi_pipe_fe_reducer_centric_short_NOR | Nivå F - 0,7 m | 37= R 18° Kopi 1
3 x magi_pipe_fe_reducer_centric_short_NOR | Nivå F - 0,7 m | 37= T 9° Kopi 2

# IfcFlowFitting: magi_pipe_fe_tee_centric_90_NOR (38)
In: Nivå F - 0,7 m
Type - PredefinedType: JUNCTION
ePset_LocationTool - Splitting: ORIGINAL
MagiCAD Pset_TBranch - Insulation_thickness_mm: 0 mm; qv_SizingFlow_ls: 0 m3/s; pTot_SizingFlow_Pa: 0 Pa; dpTot_SizingFlow_Pa: 0 Pa; v_SizingFlow_ms: 0 m/s; ConnectionSize_mm: 0 mm
ePset_Simplebim - Assembly Level: Leaf
Name | Group
7 x magi_pipe_fe_tee_centric_90_NOR | 33= Våt Kopi 64
25 x magi_pipe_fe_tee_centric_90_NOR | +TH=332.003
3 x magi_pipe_fe_tee_centric_90_NOR | 37= R 18° Kopi 1
3 x magi_pipe_fe_tee_centric_90_NOR | 37= T 9° Kopi 2

# IfcFlowFitting: magi_pipe_fe_tee_centric_90_NOR 2 (6)
In: Nivå D + 1,2 m
Type - PredefinedType: JUNCTION
MagiCAD Pset_TBranch - Insulation_thickness_mm: 0 mm; qv_SizingFlow_ls: 0 m3/s; pTot_SizingFlow_Pa: 0 Pa; dpTot_SizingFlow_Pa: 0 Pa; v_SizingFlow_ms: 0 m/s; ConnectionSize_mm: 0 mm; Product variable 4: 2
ePset_Simplebim - Assembly Level: Leaf
ePset_LocationTool - Splitting: ORIGINAL
Group: 33= Våt Kopi 163

# IfcFlowFitting: magi_sewer_bend_001 (9)
In: Nivå D + 1,2 m
Type - PredefinedType: BEND
MagiCAD Pset_Elbow - qv_SizingFlow_ls: 0 m3/s; pTot_SizingFlow_Pa: 0 Pa; dpTot_SizingFlow_Pa: 0 Pa; v_SizingFlow_ms: 0 m/s; ConnectionSize_mm: 0 mm
ePset_Simplebim - Assembly Level: Leaf
ePset_LocationTool - Splitting: ORIGINAL
Name | Insulation_thickness_mm (mm) | Group
2 x magi_sewer_bend_001 | 0 | 31= SPV Kopi 74
6 x magi_sewer_bend_001 | 29 | +TH=313.304
magi_sewer_bend_001 | 29 | 31= SPV Kopi 74

# IfcFlowFitting: magi_sewer_bend_001 2 (12)
Type - PredefinedType: BEND
MagiCAD Pset_Elbow - Insulation_thickness_mm: 0 mm; qv_SizingFlow_ls: 0 m3/s; pTot_SizingFlow_Pa: 0 Pa; dpTot_SizingFlow_Pa: 0 Pa; v_SizingFlow_ms: 0 m/s; ConnectionSize_mm: 0 mm
ePset_LocationTool - Splitting: ORIGINAL
ePset_Simplebim - Assembly Level: Leaf
Name | In | Group
2 x magi_sewer_bend_001 2 | Nivå D + 1,2 m | 31= SPV Kopi 77
7 x magi_sewer_bend_001 2 | Nivå D + 1,2 m | +TH=313.000.
magi_sewer_bend_001 2 | Nivå F - 0,7 m | 31= SPV Kopi 77
2 x magi_sewer_bend_001 2 | Nivå F - 0,7 m | +TH=313.000.

# IfcFlowFitting: magi_sewer_bend_NOR (7)
In: Nivå D + 1,2 m
Type - PredefinedType: BEND
MagiCAD Pset_Elbow - Product variable 4: 2
ePset_Simplebim - Assembly Level: Leaf
Name | Insulation_thickness_mm (mm) = qv_SizingFlow_ls (m3/s) = pTot_SizingFlow_Pa (Pa) = dpTot_SizingFlow_Pa (Pa) = v_SizingFlow_ms (m/s) = ConnectionSize_mm (mm) | Splitting | Group
5 x magi_sewer_bend_NOR | 0 | ORIGINAL | +TH=313.000.
magi_sewer_bend_NOR | 0 | ORIGINAL | 31= SPV Kopi 77
magi_sewer_bend_NOR |  | RESULT | +TH=313.000.

# IfcFlowFitting: magi_sewer_endcap_001 (2)
In: Nivå D + 1,2 m
Type - Description: Generic PVC Plug; PredefinedType: OBSTRUCTION
ePset_Simplebim - Assembly Level: Leaf
ePset_LocationTool - Splitting: ORIGINAL
MagiCAD Pset_Plug - Description: Generic PVC Plug; ConnectionSize_mm: 0 mm; pTot_SizingFlow_kPa: 0 Pa; Insulation_thickness_mm: 0 mm
Name | Group
magi_sewer_endcap_001 | 31= SPV Kopi 61
magi_sewer_endcap_001 | 31= SPV Kopi 77

# IfcFlowFitting: magi_sewer_tee_wye_NOR (8)
Type - PredefinedType: JUNCTION
MagiCAD Pset_TBranch - qv_SizingFlow_ls: 0 m3/s; pTot_SizingFlow_Pa: 0 Pa; dpTot_SizingFlow_Pa: 0 Pa; v_SizingFlow_ms: 0 m/s; ConnectionSize_mm: 0 mm
ePset_Simplebim - Assembly Level: Leaf
ePset_LocationTool - Splitting: ORIGINAL
Name | In | Insulation_thickness_mm (mm) | Group
magi_sewer_tee_wye_NOR | Nivå D + 1,2 m | 0 | 31= SPV Kopi 77
magi_sewer_tee_wye_NOR | Nivå D + 1,2 m | 0 | 31= SPV Kopi 61
magi_sewer_tee_wye_NOR | Nivå D + 1,2 m | 29 | +TH=313.304
2 x magi_sewer_tee_wye_NOR | Nivå D + 1,2 m | 0 | +TH=313.310
magi_sewer_tee_wye_NOR | Nivå D + 1,2 m | 0 | +TH=313.000.
magi_sewer_tee_wye_NOR | Nivå F - 0,7 m | 25 | 31= SPV Kopi 132
magi_sewer_tee_wye_NOR | Nivå F - 0,7 m | 0 | +TH=313.000. | MagiCAD Pset_TBranch - Product variable 4: 2

# IfcFlowFitting: magi_sewer_transition_001
In: Nivå D + 1,2 m
Type - Description: Generic PVC Reducer; PredefinedType: TRANSITION
ePset_Simplebim - Assembly Level: Leaf
MagiCAD Pset_Reduction - Insulation_thickness_mm: 0 mm; qv_SizingFlow_ls: 0 m3/s; pTot_SizingFlow_Pa: 0 Pa; dpTot_SizingFlow_Pa: 0 Pa; v_SizingFlow_ms: 0 m/s; ConnectionSize_mm: 0 mm; Description: Generic PVC Reducer
ePset_LocationTool - Splitting: ORIGINAL
Group: 31= SPV Kopi 74

# IfcFlowFitting: magi_sewer_transition_NOR (2)
In: Nivå F - 0,7 m
Type - PredefinedType: TRANSITION
ePset_LocationTool - Splitting: ORIGINAL
ePset_Simplebim - Assembly Level: Leaf
MagiCAD Pset_Reduction - qv_SizingFlow_ls: 0 m3/s; pTot_SizingFlow_Pa: 0 Pa; dpTot_SizingFlow_Pa: 0 Pa; v_SizingFlow_ms: 0 m/s; ConnectionSize_mm: 0 mm; Insulation_thickness_mm: 25 mm
Group: 31= SPV Kopi 132

# IfcFlowFitting: magi_sewer_union_NOR
In: Nivå D + 1,2 m
Type - PredefinedType: CONNECTOR
MagiCAD Pset_Joint - Insulation_thickness_mm: 0 mm; qv_SizingFlow_ls: 0 m3/s; pTot_SizingFlow_Pa: 0 Pa; dpTot_SizingFlow_Pa: 0 Pa; v_SizingFlow_ms: 0 m/s; ConnectionSize_mm: 0 mm
ePset_LocationTool - Splitting: ORIGINAL
ePset_Simplebim - Assembly Level: Leaf
Group: 31= SPV Kopi 77

# IfcFlowFitting: magicirc_elbow_full_radius_001 (13)
In: Nivå D + 1,2 m
Type - Description: Bend, Sirkulært; PredefinedType: BEND
Description: Circular, smooth,R=D; Group: +TH=360.031 TL (1)
ePset_Simplebim - Assembly Level: Leaf
ePset_LocationTool - Splitting: ORIGINAL
MagiCAD Pset_Elbow - Description: Circular, smooth,R=D; Insulation_thickness_mm: 0 mm; qv_SizingFlow_ls: 0 m3/s; pTot_SizingFlow_Pa: 0 Pa; dpTot_SizingFlow_Pa: 0 Pa; v_SizingFlow_ms: 0 m/s; ConnectionSize_mm: 0 mm

# IfcFlowFitting: magicirc_elbow_short_001 (27)
Type - PredefinedType: BEND
MagiCAD Pset_Elbow - Insulation_thickness_mm: 0 mm; qv_SizingFlow_ls: 0 m3/s; pTot_SizingFlow_Pa: 0 Pa; dpTot_SizingFlow_Pa: 0 Pa; v_SizingFlow_ms: 0 m/s; ConnectionSize_mm: 0 mm
ePset_Simplebim - Assembly Level: Leaf
ePset_LocationTool - Splitting: ORIGINAL
Name | In | Group
2 x magicirc_elbow_short_001 | Nivå D + 1,2 m | +TH=360.031 TL (1)
2 x magicirc_elbow_short_001 | Nivå D + 1,2 m
18 x magicirc_elbow_short_001 | Nivå F - 0,7 m | +TH=360.031 TL (1)
4 x magicirc_elbow_short_001 | Nivå F - 0,7 m | 36= Avtrekk 15
magicirc_elbow_short_001 | Nivå F - 0,7 m | +TH=360.010 (12)

# IfcFlowFitting: magicirc_joint_001
In: Nivå D + 1,2 m
Type - PredefinedType: CONNECTOR
MagiCAD Pset_Joint - Insulation_thickness_mm: 0 mm; qv_SizingFlow_ls: 0 m3/s; pTot_SizingFlow_Pa: 0 Pa; dpTot_SizingFlow_Pa: 0 Pa; v_SizingFlow_ms: 0 m/s; ConnectionSize_mm: 0 mm
ePset_Simplebim - Assembly Level: Leaf
ePset_LocationTool - Splitting: ORIGINAL
Group: +TH=360.031

# IfcFlowFitting: magicirc_reduction_001 (6)
In: Nivå F - 0,7 m
Type - PredefinedType: TRANSITION
Description: Circular, concentric and eccentric, 60 deg (short); Group: +TH=360.031 TL (1)
MagiCAD Pset_Reduction - Description: Circular, concentric and eccentric, 60 deg (short); Insulation_thickness_mm: 0 mm; qv_SizingFlow_ls: 0 m3/s; pTot_SizingFlow_Pa: 0 Pa; dpTot_SizingFlow_Pa: 0 Pa; v_SizingFlow_ms: 0 m/s; ConnectionSize_mm: 0 mm
ePset_Simplebim - Assembly Level: Leaf
ePset_LocationTool - Splitting: ORIGINAL

# IfcFlowFitting: magicirc_tapoutlet_001 (12)
Type - Description: Påstikk; PredefinedType: CONNECTOR
Description: Rectangular/circular; Group: +TH=360.031 TL (1)
ePset_Simplebim - Assembly Level: Leaf
ePset_LocationTool - Splitting: ORIGINAL
Name | In
6 x magicirc_tapoutlet_001 | Nivå D + 1,2 m
6 x magicirc_tapoutlet_001 | Nivå F - 0,7 m

# IfcFlowFitting: magirect_outlet1_001 2
In: Nivå D + 1,2 m
Type - PredefinedType: CONNECTOR
ePset_Simplebim - Assembly Level: Leaf
ePset_LocationTool - Splitting: ORIGINAL
Group: +TH=360.031 TL (1)

# IfcFlowFitting: magirect_reduction1_001
In: Nivå D + 1,2 m
Type - PredefinedType: TRANSITION
ePset_Simplebim - Assembly Level: Leaf
ePset_LocationTool - Splitting: RESULT

# IfcFlowSegment: 2 - Spiro kanaler, Forsinket stål (45)
Type - Description: Spiro kanaler, Forsinket stål; PredefinedType: RIGIDSEGMENT
MagiCAD Pset_Duct - UserCode: Circ; Description: Spiro kanaler, Forsinket stål
ePset_Simplebim - Assembly Level: Leaf
Name | In | qv_SizingFlow_ls (m3/s) = dpTot_SizingFlow_Pa (Pa) = pTot_SizingFlow_Pa (Pa) = v_SizingFlow_ms (m/s) = Insulation_thickness_mm (mm) | Length_mm (mm) | Splitting | Height (Simplebim) (mm) | Width (Simplebim) (mm) | Length (Simplebim) (mm) | Group
2 - Spiro kanaler, Forsinket stål | Nivå D + 1,2 m | 0 | 2585.07 | ORIGINAL | 400 | 400 | 2585.1 | +TH=360.031 TL (1)
2 - Spiro kanaler, Forsinket stål | Nivå D + 1,2 m | 0 | 1105.38 | ORIGINAL | 400 | 400 | 1105.4
2 - Spiro kanaler, Forsinket stål | Nivå D + 1,2 m | 0 | 3860 | ORIGINAL | 400 | 400 | 3860
2 - Spiro kanaler, Forsinket stål | Nivå D + 1,2 m | 0 | 118.901 | ORIGINAL | 118.9 | 400 | 400 | +TH=360.031 TL (1)
2 - Spiro kanaler, Forsinket stål | Nivå F - 0,7 m | 0 | 426.808 | ORIGINAL | 400 | 400 | 426.8 | +TH=360.031 TL (1)
2 - Spiro kanaler, Forsinket stål | Nivå F - 0,7 m | 0 | 625 | ORIGINAL | 400 | 400 | 625 | +TH=360.031 TL (1)
2 - Spiro kanaler, Forsinket stål | Nivå F - 0,7 m | 0 | 2605 | ORIGINAL | 200 | 200 | 2605 | +TH=360.031 TL (1)
2 - Spiro kanaler, Forsinket stål | Nivå F - 0,7 m | 0 | 95 | ORIGINAL | 200 | 200 | 95 | +TH=360.031 TL (1)
2 - Spiro kanaler, Forsinket stål | Nivå F - 0,7 m | 0 | 159.999 | ORIGINAL | 160 | 200 | 200 | +TH=360.010 (12)
2 - Spiro kanaler, Forsinket stål | Nivå F - 0,7 m | 0 | 753.338 | ORIGINAL | 200 | 200 | 753.3 | +TH=360.031 TL (1)
2 - Spiro kanaler, Forsinket stål | Nivå F - 0,7 m | 0 | 833.209 | ORIGINAL | 200 | 200 | 833.2 | +TH=360.010 (12)
2 - Spiro kanaler, Forsinket stål | Nivå F - 0,7 m | 0 | 158.246 | ORIGINAL | 200 | 200 | 158.1 | +TH=360.031 TL (1)
2 - Spiro kanaler, Forsinket stål | Nivå F - 0,7 m | 0 | 1517.34 | ORIGINAL | 315 | 315 | 1517.3 | +TH=360.031 TL (1)
2 - Spiro kanaler, Forsinket stål | Nivå F - 0,7 m | 0 | 1705 | ORIGINAL | 250 | 250 | 1705 | +TH=360.031 TL (1)
2 - Spiro kanaler, Forsinket stål | Nivå F - 0,7 m | 0 | 215.746 | ORIGINAL | 200 | 200 | 215.7 | +TH=360.031 TL (1)
2 - Spiro kanaler, Forsinket stål | Nivå F - 0,7 m | 0 | 124.563 | ORIGINAL | 125 | 315 | 315 | +TH=360.031 TL (1)
2 - Spiro kanaler, Forsinket stål | Nivå F - 0,7 m | 0 | 323.464 | ORIGINAL | 315 | 315 | 323.5 | +TH=360.031 TL (1)
2 - Spiro kanaler, Forsinket stål | Nivå F - 0,7 m | 0 | 219.766 | ORIGINAL | 315 | 315 | 220.3 | +TH=360.031 TL (1)
2 - Spiro kanaler, Forsinket stål | Nivå F - 0,7 m | 0 | 180 | ORIGINAL | 200 | 200 | 180 | +TH=360.031 TL (1)
2 - Spiro kanaler, Forsinket stål | Nivå F - 0,7 m | 0 | 445.903 | ORIGINAL | 200 | 200 | 445.9 | +TH=360.031 TL (1)
2 - Spiro kanaler, Forsinket stål | Nivå F - 0,7 m | 0 | 1734.36 | ORIGINAL | 250 | 250 | 1734.4 | +TH=360.031 TL (1)
2 - Spiro kanaler, Forsinket stål | Nivå F - 0,7 m | 0 | 845.519 | ORIGINAL | 100 | 100 | 845.5 | +TH=360.031 TL (1)
2 - Spiro kanaler, Forsinket stål | Nivå F - 0,7 m | 0 | 43.2 | ORIGINAL | 43.2 | 100 | 100 | +TH=360.031 TL (1)
2 - Spiro kanaler, Forsinket stål | Nivå F - 0,7 m | 0 | 303.357 | ORIGINAL | 160 | 160 | 303.4 | 36= Avtrekk 15
2 - Spiro kanaler, Forsinket stål | Nivå F - 0,7 m | 0 | 30.366 | ORIGINAL | 160 | 160 | 30.2 | 36= Avtrekk 15
2 - Spiro kanaler, Forsinket stål | Nivå F - 0,7 m | 0 | 133.66 | ORIGINAL | 160 | 160 | 133.7 | 36= Avtrekk 15
2 - Spiro kanaler, Forsinket stål | Nivå F - 0,7 m | 0 | 52.551 | ORIGINAL | 160 | 160 | 52.6 | 36= Avtrekk 15
2 - Spiro kanaler, Forsinket stål | Nivå F - 0,7 m | 0 | 204 | ORIGINAL | 160 | 160 | 204 | 36= Avtrekk 15
2 - Spiro kanaler, Forsinket stål | Nivå F - 0,7 m | 0 | 62.898 | ORIGINAL | 160 | 160 | 62.9 | 36= Avtrekk 15
2 - Spiro kanaler, Forsinket stål | Nivå F - 0,7 m | 0 | 72.551 | ORIGINAL | 160 | 160 | 72.6 | 36= Avtrekk 15
2 - Spiro kanaler, Forsinket stål | Nivå F - 0,7 m | 0 | 1433.17 | ORIGINAL | 315 | 315 | 1433.2 | +TH=360.031 TL (1)
2 - Spiro kanaler, Forsinket stål | Nivå F - 0,7 m | 0 | 306.203 | ORIGINAL | 315 | 315 | 306.2 | +TH=360.031 TL (1)
2 - Spiro kanaler, Forsinket stål | Nivå F - 0,7 m | 0 | 4931.29 | ORIGINAL | 315 | 315 | 4931.3 | +TH=360.031 TL (1)
2 - Spiro kanaler, Forsinket stål | Nivå F - 0,7 m | 0 | 80.838 | ORIGINAL | 400 | 400 | 80.8 | +TH=360.031 TL (1)
2 - Spiro kanaler, Forsinket stål | Nivå F - 0,7 m | 0 | 531.71 | ORIGINAL | 400 | 400 | 531.7 | +TH=360.031 TL (1)
2 - Spiro kanaler, Forsinket stål | Nivå F - 0,7 m | 0 | 410 | ORIGINAL | 400 | 400 | 410 | +TH=360.031 TL (1)
2 - Spiro kanaler, Forsinket stål | Nivå F - 0,7 m | 0 | 546.398 | ORIGINAL | 200 | 200 | 546.4 | +TH=360.031 TL (1)
2 - Spiro kanaler, Forsinket stål | Nivå F - 0,7 m | 0 | 30.941 | ORIGINAL | 200 | 200 | 30.9 | +TH=360.031 TL (1)
2 - Spiro kanaler, Forsinket stål | Nivå F - 0,7 m | 0 | 66.271 | ORIGINAL | 200 | 200 | 65.8 | +TH=360.031 TL (1)
2 - Spiro kanaler, Forsinket stål | Nivå F - 0,7 m | 0 | 185.913 | ORIGINAL | 200 | 200 | 185.9 | +TH=360.031 TL (1)
2 - Spiro kanaler, Forsinket stål | Nivå F - 0,7 m | 0 | 960 | ORIGINAL | 400 | 400 | 960 | +TH=360.031 TL (1)
2 - Spiro kanaler, Forsinket stål | Nivå F - 0,7 m | 0 | 186.643 | ORIGINAL | 200 | 200 | 186.6 | +TH=360.031 TL (1)
2 - Spiro kanaler, Forsinket stål | Nivå F - 0,7 m | 0 | 886.529 | ORIGINAL | 315 | 315 | 886.5 | +TH=360.031 TL (1)
2 - Spiro kanaler, Forsinket stål | Nivå F - 0,7 m | 0 | 852.329 | ORIGINAL | 200 | 200 | 852.3 | +TH=360.031 TL (1)
2 - Spiro kanaler, Forsinket stål | Nivå D + 1,2 m |  |  | RESULT | 355 | 400 | 627

# IfcFlowSegment: 4 - Spiro kanaler, korte bend (18)
In: Nivå D + 1,2 m
Type - Description: Spiro kanaler, korte bend; PredefinedType: RIGIDSEGMENT
ePset_LocationTool - Splitting: ORIGINAL
ePset_Simplebim - Assembly Level: Leaf
MagiCAD Pset_Duct - Description: Spiro kanaler, korte bend; UserCode: Circ; qv_SizingFlow_ls: 0 m3/s; dpTot_SizingFlow_Pa: 0 Pa; pTot_SizingFlow_Pa: 0 Pa; v_SizingFlow_ms: 0 m/s; Insulation_thickness_mm: 0 mm
ePset_SimplebimBasicQuantities - Width (Simplebim): 200 mm
Group: +TH=360.031 TL (1)
Name | Length_mm (mm) | Height (Simplebim) (mm) | Length (Simplebim) (mm)
4 - Spiro kanaler, korte bend | 282.157 | 200 | 282.2
3 x 4 - Spiro kanaler, korte bend | 176.71 | 200 | 176.7
4 - Spiro kanaler, korte bend | 7.157 | 200 | 7.2
4 - Spiro kanaler, korte bend | 552.157 | 200 | 552.2
3 x 4 - Spiro kanaler, korte bend | 80 | 80 | 200
2 x 4 - Spiro kanaler, korte bend | 117.157 | 200 | 117.2
2 x 4 - Spiro kanaler, korte bend | 717.157 | 200 | 717.2
4 - Spiro kanaler, korte bend | 78.865 | 200 | 78.9
4 - Spiro kanaler, korte bend | 10 | 10 | 200
4 - Spiro kanaler, korte bend | 617.054 | 200 | 617.1
4 - Spiro kanaler, korte bend | 57.157 | 200 | 57.2
4 - Spiro kanaler, korte bend | 197.585 | 200 | 197.6

# IfcFlowSegment: Gulvkanal (8)
In: Nivå F - 0,7 m
Type - PredefinedType: CABLETRAYSEGMENT
ePset_Simplebim - Assembly Level: Leaf
ePset_SimplebimBasicQuantities - Height (Simplebim): 50 mm; Width (Simplebim): 350 mm
MagiCAD Pset_Cabletray - System code: 4115
Group: Gulvkanal
Name | Splitting | Length (Simplebim) (mm) | NominalLength (mm) = Length [mm] (mm) | NominalHeight (mm) = Height [mm] (mm) | NominalWidth (mm) = Width [mm] (mm)
4 x Gulvkanal | ORIGINAL | 2572.16 | 2572.16 | 50 | 350
Gulvkanal | ORIGINAL | 5095 | 5095 | 50 | 350
Gulvkanal | RESULT | 1168
Gulvkanal | RESULT | 1703
Gulvkanal | RESULT | 10676

# IfcFlowSegment: KK002T - Rektangulære, Forsinket stål (5)
Type - Description: Rektangulære, Forsinket stål; PredefinedType: RIGIDSEGMENT
Classification: VB2.111212 Not defined (NS3420)
ePset_LocationTool - Splitting: RESULT
MagiCAD Pset_Duct - NationalCode: VB2.111212; UserCode: Rect; Description: Rektangulære, Forsinket stål
ePset_Simplebim - Assembly Level: Leaf
Name | In | Width (Simplebim) (mm) | Height (Simplebim) (mm) | Length (Simplebim) (mm) | Group
KK002T - Rektangulære, Forsinket stål | Nivå F - 0,7 m | 130 | 545 | 1570 | +TH=360.010 (28)
KK002T - Rektangulære, Forsinket stål | Nivå D + 1,2 m | 400 | 267 | 1722 | +TH=360.031 TL (1)
KK002T - Rektangulære, Forsinket stål | Nivå D + 1,2 m | 700 | 280 | 2386 | +TH=360.031 TL (1)
KK002T - Rektangulære, Forsinket stål | Nivå D + 1,2 m | 128 | 340 | 360
KK002T - Rektangulære, Forsinket stål | Nivå D + 1,2 m | 1250 | 300 | 2570 | +TH=360.031 TL (1)

# IfcFlowSegment: KK002T - Spiro kanaler, Forsinket stål, korte bend (8)
Type - Description: Spiro kanaler, Forsinket stål; PredefinedType: RIGIDSEGMENT
Classification: VB2.121212 Not defined (NS3420)
ePset_Simplebim - Assembly Level: Leaf
MagiCAD Pset_Duct - UserCode: Circ; Description: Spiro kanaler, Forsinket stål; NationalCode: VB2.121212
Name | In | Splitting | Length (Simplebim) (mm) | Height (Simplebim) (mm) | Width (Simplebim) (mm) | qv_SizingFlow_ls (m3/s) = dpTot_SizingFlow_Pa (Pa) = pTot_SizingFlow_Pa (Pa) = v_SizingFlow_ms (m/s) = Insulation_thickness_mm (mm) | Length_mm (mm) | Group
KK002T - Spiro kanaler, Forsinket stål, korte bend | Nivå D + 1,2 m | ORIGINAL | 500 | 315 | 315 | 0 | 500 | +TH=360.031
KK002T - Spiro kanaler, Forsinket stål, korte bend | Nivå D + 1,2 m | ORIGINAL | 460 | 350 | 350 | 0 | 460
KK002T - Spiro kanaler, Forsinket stål, korte bend | Nivå D + 1,2 m | ORIGINAL | 315 | 174.3 | 315 | 0 | 174.25 | +TH=360.031
KK002T - Spiro kanaler, Forsinket stål, korte bend | Nivå F - 0,7 m | ORIGINAL | 796.9 | 200 | 200 | 0 | 796.941 | +TH=360.031 TL (1)
KK002T - Spiro kanaler, Forsinket stål, korte bend | Nivå F - 0,7 m | ORIGINAL | 708.1 | 200 | 200 | 0 | 708.14 | +TH=360.031 TL (1)
KK002T - Spiro kanaler, Forsinket stål, korte bend | Nivå F - 0,7 m | ORIGINAL | 226.1 | 200 | 200 | 0 | 226.05 | +TH=360.031 TL (1)
KK002T - Spiro kanaler, Forsinket stål, korte bend | Nivå F - 0,7 m | ORIGINAL | 1502.3 | 200 | 200 | 0 | 1502.28 | +TH=360.031 TL (1)
KK002T - Spiro kanaler, Forsinket stål, korte bend | Nivå D + 1,2 m | RESULT | 317 | 316 | 316 |  |  | +TH=360.031

# IfcFlowSegment: Kabelbro (12)
Type - PredefinedType: CABLELADDERSEGMENT
ePset_Simplebim - Assembly Level: Leaf
Name | In | Splitting | Length [mm] (mm) = NominalLength (mm) | System code | Height [mm] (mm) = NominalHeight (mm) | Width [mm] (mm) = NominalWidth (mm) | Length (Simplebim) (mm) | Height (Simplebim) (mm) | Width (Simplebim) (mm) | Group
Kabelbro | Nivå D + 1,2 m | ORIGINAL | 4679.86 | 410 | 60 | 300 | 4679.86 | 60 | 300 | Bæresystem generelt
Kabelbro | Nivå D + 1,2 m | ORIGINAL | 2890.75 | 4111 | 100 | 600 | 2890.75 | 100 | 600 | Bæresystem for elkraft
Kabelbro | Nivå D + 1,2 m | ORIGINAL | 1431.2 | 4111 | 100 | 600 | 1431.2 | 100 | 600 | Bæresystem for elkraft
Kabelbro | Nivå D + 1,2 m | ORIGINAL | 1413.57 | 4111 | 100 | 600 | 1413.57 | 100 | 600 | Bæresystem for elkraft
3 x Kabelbro | Nivå D + 1,2 m | ORIGINAL | 262.563 | 4111 | 100 | 600 | 600 | 100 | 262.563 | Bæresystem for elkraft
Kabelbro | Nivå D + 1,2 m | ORIGINAL | 4.623 | 410 | 100 | 300 | 300 | 100 | 4.62335 | Bæresystem generelt
Kabelbro | Nivå D + 1,2 m | ORIGINAL | 262.563 | 410 | 100 | 300 | 300 | 100 | 262.563 | Bæresystem generelt
Kabelbro | Nivå D + 1,2 m | ORIGINAL | 40.534 | 4111 | 100 | 600 | 600 | 100 | 40.5344 | Bæresystem for elkraft
Kabelbro | Nivå F - 0,7 m | RESULT |  | 410 |  |  | 15299 | 100 | 600 | Bæresystem generelt
Kabelbro | Nivå D + 1,2 m | RESULT |  | 4111 |  |  | 1882 | 100 | 600 | Bæresystem for elkraft

# IfcFlowSegment: Kobberrør (90)
Type - PredefinedType: RIGIDSEGMENT
ePset_Simplebim - Assembly Level: Leaf
MagiCAD Pset_Pipe - User Code: Cu; NationalCode: UB1.111713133; Material: Kobberrør
Name | In | Height (Simplebim) (mm) | Width (Simplebim) (mm) | Length (Simplebim) (mm) | MagiCAD Pset_Water, dpTot_SizingFlow_kPa (Pa) = MagiCAD Pset_Water, pTot_SizingFlow_kPa (Pa) = MagiCAD Pset_Water, v_SizingFlow_ms (m/s) = MagiCAD Pset_Heating, v_SizingFlow_ms (m/s) = MagiCAD Pset_Heating, pTot_SizingFlow_kPa (Pa) = MagiCAD Pset_Heating, dpTot_SizingFlow_kPa (Pa) = qv_SizingFlow_ls (m3/s) | SystemName = Group | Insulation_thickness_mm (mm) | ConnectionSize_mm (mm) | Length_mm (mm) | SystemType | SystemClass | Splitting
Kobberrør | Nivå D + 1,2 m | 35 | 35 | 1330 | 0 | +TH=310.001 | 0 | 35 | 1330 | KV | Domestic Cold Water | ORIGINAL
Kobberrør | Nivå D + 1,2 m | 18 | 18 | 28.8 | 0 | +TH=310.002 | 0 | 18 | 28.842 | 31 VV | Domestic Hot Water | ORIGINAL
Kobberrør | Nivå D + 1,2 m | 18 | 18 | 3625.2 | 0 | +TH=310.002 | 0 | 18 | 3625.16 | 31 VV | Domestic Hot Water | ORIGINAL
Kobberrør | Nivå D + 1,2 m | 3.2 | 18 | 18 | 0 | +TH=310.001 | 20 | 18 | 3 | KV | Domestic Cold Water | ORIGINAL
Kobberrør | Nivå D + 1,2 m | 15 | 15 | 4407.7 | 0 | +TH=310.002 | 20 | 15 | 4407.7 | 31 VV | Domestic Hot Water | ORIGINAL
Kobberrør | Nivå D + 1,2 m | 18 | 18 | 706.1 | 0 | +TH=310.001 | 20 | 18 | 706.076 | KV | Domestic Cold Water | ORIGINAL
Kobberrør | Nivå D + 1,2 m | 15 | 15 | 767.1 | 0 | +TH=310.002 | 20 | 15 | 767.079 | 31 VV | Domestic Hot Water | ORIGINAL
Kobberrør | Nivå D + 1,2 m | 22 | 22 | 21 | 0 | 31= SPV Kopi 47 | 0 | 22 | 21 | SPV PL | Sanitary | ORIGINAL
Kobberrør | Nivå D + 1,2 m | 22 | 22 | 371 | 0 | 31= SPV Kopi 47 | 0 | 22 | 371 | SPV PL | Sanitary | ORIGINAL
Kobberrør | Nivå D + 1,2 m | 22 | 22 | 2456.9 | 0 | 31= SPV Kopi 47 | 0 | 22 | 2456.86 | SPV PL | Sanitary | ORIGINAL
Kobberrør | Nivå D + 1,2 m | 22 | 22 | 43 | 0 | 31= SPV Kopi 47 | 0 | 22 | 43 | SPV PL | Sanitary | ORIGINAL
Kobberrør | Nivå D + 1,2 m | 22 | 22 | 376.5 | 0 | 31= SPV Kopi 47 | 0 | 22 | 376.5 | SPV PL | Sanitary | ORIGINAL
Kobberrør | Nivå D + 1,2 m | 22 | 22 | 4126 | 0 | 31= SPV Kopi 47 | 0 | 22 | 4126 | SPV PL | Sanitary | ORIGINAL
Kobberrør | Nivå D + 1,2 m | 15 | 15 | 381.7 | 0 | +TH=310.002 | 20 | 15 | 381.74 | 31 VV | Domestic Hot Water | ORIGINAL
Kobberrør | Nivå D + 1,2 m | 18 | 18 | 358.3 | 0 | +TH=310.001 | 20 | 18 | 358.32 | KV | Domestic Cold Water | ORIGINAL
Kobberrør | Nivå D + 1,2 m | 35 | 35 | 50 | 0 | +TH=310.001 | 24 | 35 | 50 | KV | Domestic Cold Water | ORIGINAL
Kobberrør | Nivå D + 1,2 m | 18 | 18 | 50 | 0 | +TH=310.002 | 0 | 18 | 50 | 31 VV | Domestic Hot Water | ORIGINAL
Kobberrør | Nivå D + 1,2 m | 18 | 18 | 1041.7 | 0 | +TH=310.002 | 20 | 18 | 1041.72 | 31 VV | Domestic Hot Water | ORIGINAL
Kobberrør | Nivå D + 1,2 m | 15 | 15 | 52.1 | 0 | +TH=310.003 | 20 | 15 | 52.132 | 31 VVC | Hydronic Return | ORIGINAL
Kobberrør | Nivå D + 1,2 m | 15 | 15 | 1474.9 | 0 | +TH=310.003 | 20 | 15 | 1474.93 | 31 VVC | Hydronic Return | ORIGINAL
Kobberrør | Nivå D + 1,2 m | 15 | 15 | 452 | 0 | +TH=310.003 | 20 | 15 | 452.009 | 31 VVC | Hydronic Return | ORIGINAL
Kobberrør | Nivå D + 1,2 m | 15 | 15 | 455 | 0 | +TH=310.001 | 20 | 15 | 455 | KV | Domestic Cold Water | ORIGINAL
Kobberrør | Nivå D + 1,2 m | 18 | 18 | 328.4 | 0 | +TH=310.002 | 20 | 18 | 328.44 | 31 VV | Domestic Hot Water | ORIGINAL
Kobberrør | Nivå D + 1,2 m | 35 | 35 | 723 | 0 | +TH=310.001 | 24 | 35 | 723.004 | KV | Domestic Cold Water | ORIGINAL
Kobberrør | Nivå D + 1,2 m | 18 | 18 | 82.3 | 0 | +TH=310.002 | 20 | 18 | 82.252 | 31 VV | Domestic Hot Water | ORIGINAL
Kobberrør | Nivå D + 1,2 m | 35 | 35 | 194.5 | 0 | +TH=310.001 | 24 | 35 | 194.456 | KV | Domestic Cold Water | ORIGINAL
Kobberrør | Nivå D + 1,2 m | 15 | 15 | 613.8 | 0 | +TH=310.002 | 20 | 15 | 613.808 | 31 VV | Domestic Hot Water | ORIGINAL
Kobberrør | Nivå D + 1,2 m | 18 | 18 | 115.1 | 0 | +TH=310.001 | 20 | 18 | 115.121 | KV | Domestic Cold Water | ORIGINAL
Kobberrør | Nivå D + 1,2 m | 18 | 18 | 2327.6 | 0 | +TH=310.001 | 20 | 18 | 2327.57 | KV | Domestic Cold Water | ORIGINAL
Kobberrør | Nivå D + 1,2 m | 18 | 18 | 4375.2 | 0 | +TH=310.001 | 20 | 18 | 4375.17 | KV | Domestic Cold Water | ORIGINAL
Kobberrør | Nivå D + 1,2 m | 18 | 18 | 168.5 | 0 | +TH=310.001 | 20 | 18 | 168.5 | KV | Domestic Cold Water | ORIGINAL
Kobberrør | Nivå D + 1,2 m | 18 | 18 | 589.5 | 0 | +TH=310.001 | 20 | 18 | 589.469 | KV | Domestic Cold Water | ORIGINAL
2 x Kobberrør | Nivå D + 1,2 m | 18 | 18 | 149.2 | 0 | +TH=310.001 | 20 | 18 | 149.227 | KV | Domestic Cold Water | ORIGINAL
Kobberrør | Nivå D + 1,2 m | 18 | 18 | 589.5 | 0 | +TH=310.001 | 20 | 18 | 590.07 | KV | Domestic Cold Water | ORIGINAL
Kobberrør | Nivå D + 1,2 m | 35 | 35 | 222.1 | 0 | +TH=310.001 | 24 | 35 | 222.086 | KV | Domestic Cold Water | ORIGINAL
Kobberrør | Nivå D + 1,2 m | 15 | 15 | 620.4 | 0 | +TH=310.002 | 20 | 15 | 620.448 | 31 VV | Domestic Hot Water | ORIGINAL
Kobberrør | Nivå D + 1,2 m | 18 | 18 | 117.6 | 0 | +TH=310.002 | 20 | 18 | 117.612 | 31 VV | Domestic Hot Water | ORIGINAL
Kobberrør | Nivå D + 1,2 m | 15 | 15 | 3487.9 | 0 | +TH=310.003 | 20 | 15 | 3487.87 | 31 VVC | Hydronic Return | ORIGINAL
Kobberrør | Nivå D + 1,2 m | 18 | 18 | 484 | 0 | +TH=310.001 | 20 | 18 | 484 | KV | Domestic Cold Water | ORIGINAL
Kobberrør | Nivå D + 1,2 m | 15 | 15 | 470 | 0 | +TH=310.002 | 20 | 15 | 470 | 31 VV | Domestic Hot Water | ORIGINAL
Kobberrør | Nivå D + 1,2 m | 18 | 18 | 214 | 0 | +TH=310.001 | 20 | 18 | 214 | KV | Domestic Cold Water | ORIGINAL
Kobberrør | Nivå D + 1,2 m | 15 | 15 | 57.2 | 0 | +TH=310.002 | 20 | 15 | 57.208 | 31 VV | Domestic Hot Water | ORIGINAL
Kobberrør | Nivå D + 1,2 m | 35 | 35 | 198.2 | 0 | +TH=310.001 | 24 | 35 | 198.181 | KV | Domestic Cold Water | ORIGINAL
Kobberrør | Nivå D + 1,2 m | 18 | 18 | 2355 | 0 | +TH=310.001 | 20 | 18 | 2355 | KV | Domestic Cold Water | ORIGINAL
Kobberrør | Nivå D + 1,2 m | 18 | 18 | 84.8 | 0 | +TH=310.001 | 0 | 18 | 85 | KV | Domestic Cold Water | ORIGINAL
Kobberrør | Nivå D + 1,2 m | 15 | 15 | 25.7 | 0 | +TH=310.002 | 0 | 15 | 26.199 | 31 VV | Domestic Hot Water | ORIGINAL
Kobberrør | Nivå D + 1,2 m | 15 | 15 | 65 | 0 | +TH=310.002 | 0 | 15 | 64.801 | 31 VV | Domestic Hot Water | ORIGINAL
Kobberrør | Nivå F - 0,7 m | 28 | 28 | 63 | 0 | 31=KV Kopi 23 | 0 | 28 | 63.189 | KV | Domestic Cold Water | ORIGINAL
Kobberrør | Nivå F - 0,7 m | 28 | 28 | 367.3 | 0 | 31=KV Kopi 23 | 0 | 28 | 367.29 | KV | Domestic Cold Water | ORIGINAL
Kobberrør | Nivå F - 0,7 m | 35 | 35 | 95 | 0 | 31=KV Kopi 23 | 0 | 35 | 95 | KV | Domestic Cold Water | ORIGINAL
Kobberrør | Nivå F - 0,7 m | 28 | 28 | 557.9 | 0 | 31=KV Kopi 23 | 0 | 28 | 557.5 | KV | Domestic Cold Water | ORIGINAL
Kobberrør | Nivå F - 0,7 m | 14.2 | 28 | 28 | 0 | 31=KV Kopi 23 | 0 | 28 | 13.743 | KV | Domestic Cold Water | ORIGINAL
Kobberrør | Nivå F - 0,7 m | 28 | 28 | 1130.5 | 0 | 31=KV Kopi 23 | 0 | 28 | 1130.47 | KV | Domestic Cold Water | ORIGINAL
Kobberrør | Nivå F - 0,7 m | 28 | 28 | 895.9 | 0 | 31=KV Kopi 23 | 0 | 28 | 895.755 | KV | Domestic Cold Water | ORIGINAL
Kobberrør | Nivå F - 0,7 m | 35 | 35 | 52.7 | 0 | 31=KV Kopi 23 | 0 | 35 | 52.684 | KV | Domestic Cold Water | ORIGINAL
Kobberrør | Nivå F - 0,7 m | 28 | 28 | 224 | 0 | 31=KV Kopi 23 | 0 | 28 | 224.362 | KV | Domestic Cold Water | ORIGINAL
Kobberrør | Nivå F - 0,7 m | 13 | 28 | 28 | 0 | 31=KV Kopi 23 | 0 | 28 | 13.346 | KV | Domestic Cold Water | ORIGINAL
Kobberrør | Nivå F - 0,7 m | 18 | 18 | 93.5 | 0 | +TH=310.002 | 0 | 18 | 93.497 | 31 VV | Domestic Hot Water | ORIGINAL
Kobberrør | Nivå F - 0,7 m | 18 | 18 | 26.1 | 0 | +TH=310.002 | 0 | 18 | 26.41 | 31 VV | Domestic Hot Water | ORIGINAL
Kobberrør | Nivå F - 0,7 m | 15 | 15 | 270 | 0 | +TH=310.002 | 0 | 15 | 270.262 | 31 VV | Domestic Hot Water | ORIGINAL
Kobberrør | Nivå F - 0,7 m | 15 | 15 | 103.7 | 0 | +TH=310.003 | 0 | 15 | 104.228 | 31 VVC | Hydronic Return | ORIGINAL
Kobberrør | Nivå F - 0,7 m | 7.4 | 35 | 35 | 0 | 31= SPV Kopi 132 | 24 | 35 | 7.373 | 31 Overvann | Sanitary | ORIGINAL
Kobberrør | Nivå F - 0,7 m | 35 | 35 | 34.9 | 0 | 31= SPV Kopi 132 | 24 | 35 | 34.875 | 31 Overvann | Sanitary | ORIGINAL
Kobberrør | Nivå F - 0,7 m | 18 | 18 | 590.6 | 0 | +TH=310.001 | 0 | 18 | 590.608 | KV | Domestic Cold Water | ORIGINAL
Kobberrør | Nivå F - 0,7 m | 18 | 18 | 824 | 0 | +TH=310.001 | 0 | 18 | 824 | KV | Domestic Cold Water | ORIGINAL
Kobberrør | Nivå F - 0,7 m | 15 | 15 | 81 | 0 | +TH=310.002 | 20 | 15 | 80.985 | 31 VV | Domestic Hot Water | ORIGINAL
Kobberrør | Nivå F - 0,7 m | 15 | 15 | 521 | 0 | +TH=310.002 | 0 | 15 | 520.981 | 31 VV | Domestic Hot Water | ORIGINAL
Kobberrør | Nivå F - 0,7 m | 15 | 15 | 795 | 0 | +TH=310.002 | 0 | 15 | 795 | 31 VV | Domestic Hot Water | ORIGINAL
Kobberrør | Nivå F - 0,7 m | 18 | 18 | 764 | 0 | +TH=310.001 | 0 | 18 | 764.042 | KV | Domestic Cold Water | ORIGINAL
Kobberrør | Nivå F - 0,7 m | 18 | 18 | 182 | 0 | +TH=310.001 | 0 | 18 | 182.012 | KV | Domestic Cold Water | ORIGINAL
Kobberrør | Nivå F - 0,7 m | 22 | 22 | 1421 | 0 | 31= SPV Kopi 47 | 0 | 22 | 1421 | SPV PL | Sanitary | ORIGINAL
Kobberrør | Nivå F - 0,7 m | 22 | 22 | 2740.1 | 0 | 31= SPV Kopi 47 | 0 | 22 | 2740.12 | SPV PL | Sanitary | ORIGINAL
Kobberrør | Nivå F - 0,7 m | 22 | 22 | 426 | 0 | 31= SPV Kopi 47 | 0 | 22 | 426 | SPV PL | Sanitary | ORIGINAL
Kobberrør | Nivå F - 0,7 m | 22 | 22 | 276 | 0 | 31= SPV Kopi 47 | 0 | 22 | 276 | SPV PL | Sanitary | ORIGINAL
Kobberrør | Nivå F - 0,7 m | 22 | 22 | 554.5 | 0 | 31= SPV Kopi 47 | 0 | 22 | 554.525 | SPV PL | Sanitary | ORIGINAL
Kobberrør | Nivå F - 0,7 m | 22 | 22 | 1594.8 | 0 | 31= SPV Kopi 47 | 0 | 22 | 1594.8 | SPV PL | Sanitary | ORIGINAL
Kobberrør | Nivå F - 0,7 m | 22 | 22 | 43 | 0 | 31= SPV Kopi 47 | 0 | 22 | 43.003 | SPV PL | Sanitary | ORIGINAL
Kobberrør | Nivå F - 0,7 m | 22 | 22 | 2837.8 | 0 | 31= SPV Kopi 47 | 0 | 22 | 2837.81 | SPV PL | Sanitary | ORIGINAL
Kobberrør | Nivå F - 0,7 m | 22 | 22 | 387.2 | 0 | 31= SPV Kopi 47 | 0 | 22 | 387.155 | SPV PL | Sanitary | ORIGINAL
Kobberrør | Nivå F - 0,7 m | 22 | 22 | 381.8 | 0 | 31= SPV Kopi 47 | 0 | 22 | 381.791 | SPV PL | Sanitary | ORIGINAL
Kobberrør | Nivå F - 0,7 m | 22 | 22 | 487.1 | 0 | 31= SPV Kopi 47 | 0 | 22 | 487.062 | SPV PL | Sanitary | ORIGINAL
Kobberrør | Nivå F - 0,7 m | 22 | 22 | 204.1 | 0 | 31= SPV Kopi 47 | 0 | 22 | 204.076 | SPV PL | Sanitary | ORIGINAL
Kobberrør | Nivå F - 0,7 m | 22 | 22 | 43 | 0 | 31= SPV Kopi 47 | 0 | 22 | 43 | SPV PL | Sanitary | ORIGINAL
Kobberrør | Nivå F - 0,7 m | 15 | 15 | 40.5 | 0 | +TH=310.003 | 0 | 15 | 40.128 | 31 VVC | Hydronic Return | ORIGINAL
Kobberrør | Nivå D + 1,2 m | 16 | 16 | 655 |  | +TH=310.003 |  |  |  | 31 VVC | Hydronic Return | RESULT
Kobberrør | Nivå D + 1,2 m | 18 | 18 | 442 |  | +TH=310.002 |  |  |  | 31 VV | Domestic Hot Water | RESULT
Kobberrør | Nivå F - 0,7 m | 16 | 16 | 435 |  | 31=KV Kopi 23 |  |  |  | KV | Domestic Cold Water | RESULT
Kobberrør | Nivå F - 0,7 m | 16 | 16 | 393 |  | +TH=310.002 |  |  |  | 31 VV | Domestic Hot Water | RESULT
Kobberrør | Nivå D + 1,2 m | 28 | 28 | 494 |  | 31=KV Kopi 23 |  |  |  | KV | Domestic Cold Water | RESULT

# IfcFlowSegment: MA (26)
Type - PredefinedType: RIGIDSEGMENT
MagiCAD Pset_Pipe - User Code: MA; Material: MA; Product variable 1: MA; SystemClass: Sanitary; NationalCode: UB2.1115131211
ePset_Simplebim - Assembly Level: Leaf
Name | In | MagiCAD Pset_Water, dpTot_SizingFlow_kPa (Pa) = MagiCAD Pset_Water, pTot_SizingFlow_kPa (Pa) = MagiCAD Pset_Water, v_SizingFlow_ms (m/s) = MagiCAD Pset_Heating, v_SizingFlow_ms (m/s) = MagiCAD Pset_Heating, pTot_SizingFlow_kPa (Pa) = MagiCAD Pset_Heating, dpTot_SizingFlow_kPa (Pa) = qv_SizingFlow_ls (m3/s) | SystemName = Group | Length_mm (mm) | Insulation_thickness_mm (mm) | SystemType | ConnectionSize_mm (mm) | Splitting | Height (Simplebim) (mm) | Width (Simplebim) (mm) | Length (Simplebim) (mm)
MA | Nivå D + 1,2 m | 0 | 31= SPV Kopi 77 | 652.408 | 0 | SPV | 110 | ORIGINAL | 110 | 110 | 652.4
MA | Nivå D + 1,2 m | 0 | 31= SPV Kopi 77 | 73.107 | 0 | SPV | 110 | ORIGINAL | 110 | 73.2 | 110
MA | Nivå D + 1,2 m | 0 | 31= SPV Kopi 77 | 5.667 | 0 | SPV | 110 | ORIGINAL | 6.4 | 110 | 110
MA | Nivå D + 1,2 m | 0 | 31= SPV Kopi 61 | 192.743 | 0 | SPV LUFT | 110 | ORIGINAL | 110 | 110 | 192.7
MA | Nivå D + 1,2 m | 0 | +TH=313.000. | 23.169 | 0 | SPV | 110 | ORIGINAL | 110 | 110 | 23.2
MA | Nivå D + 1,2 m | 0 | +TH=313.000. | 344.662 | 0 | SPV | 110 | ORIGINAL | 110 | 110 | 344.7
MA | Nivå D + 1,2 m | 0 | +TH=313.000. | 186.363 | 0 | SPV | 110 | ORIGINAL | 110 | 110 | 186.4
MA | Nivå D + 1,2 m | 0 | +TH=313.000. | 574.876 | 0 | SPV | 110 | ORIGINAL | 110 | 110 | 574.9
MA | Nivå D + 1,2 m | 0 | +TH=313.000. | 2008.39 | 0 | SPV | 110 | ORIGINAL | 110 | 110 | 2008.4
MA | Nivå D + 1,2 m | 0 | +TH=313.000. | 712.264 | 0 | SPV | 58 | ORIGINAL | 58 | 58 | 712.3
MA | Nivå D + 1,2 m | 0 | +TH=313.000. | 1703.18 | 0 | SPV | 58 | ORIGINAL | 58 | 58 | 1703.2
MA | Nivå D + 1,2 m | 0 | +TH=313.000. | 980.89 | 0 | SPV | 58 | ORIGINAL | 58 | 58 | 980.9
MA | Nivå D + 1,2 m | 0 | +TH=313.000. | 4073.86 | 0 | SPV | 110 | ORIGINAL | 110 | 110 | 4073.9
MA | Nivå D + 1,2 m | 0 | 31= SPV Kopi 77 | 2764.78 | 0 | SPV | 110 | ORIGINAL | 110 | 110 | 2764.8
MA | Nivå D + 1,2 m | 0 | +TH=313.000. | 1033.26 | 0 | SPV | 110 | ORIGINAL | 110 | 110 | 1033.3
MA | Nivå D + 1,2 m | 0 | +TH=313.000. | 970.136 | 0 | SPV | 110 | ORIGINAL | 110 | 110 | 969.9
MA | Nivå D + 1,2 m | 0 | +TH=313.000. | 137.339 | 0 | SPV | 58 | ORIGINAL | 58 | 58 | 137.3
MA | Nivå D + 1,2 m | 0 | +TH=313.000. | 775.205 | 0 | SPV | 110 | ORIGINAL | 110 | 110 | 775.2
MA | Nivå D + 1,2 m | 0 | 31= SPV Kopi 77 | 550.807 | 0 | SPV | 110 | ORIGINAL | 110 | 110 | 550.8
MA | Nivå D + 1,2 m | 0 | 31= SPV Kopi 77 | 182.233 | 0 | SPV | 110 | ORIGINAL | 110 | 110 | 182.2
MA | Nivå D + 1,2 m | 0 | +TH=313.000. | 624.913 | 0 | SPV | 110 | ORIGINAL | 110 | 110 | 625.4
MA | Nivå F - 0,7 m | 0 | 31= SPV Kopi 77 | 118.984 | 0 | SPV | 110 | ORIGINAL | 110 | 110 | 119
MA | Nivå F - 0,7 m | 0 | 31= SPV Kopi 132 | 38.549 | 27 | 31 Overvann | 75 | ORIGINAL | 37.8 | 75 | 75
MA | Nivå F - 0,7 m |  | 31= SPV Kopi 132 |  |  | 31 Overvann |  | RESULT | 58 | 58 | 10081
MA | Nivå F - 0,7 m |  | 31= SPV Kopi 77 |  |  | SPV |  | RESULT | 110 | 110 | 509
MA | Nivå F - 0,7 m |  | 31= SPV Kopi 132 |  |  | 31 Overvann |  | RESULT | 58 | 58 | 4915

# IfcFlowSegment: PP avløpsrør (7)
Type - PredefinedType: RIGIDSEGMENT
ePset_LocationTool - Splitting: ORIGINAL
MagiCAD Pset_Water - dpTot_SizingFlow_kPa: 0 Pa; pTot_SizingFlow_kPa: 0 Pa; v_SizingFlow_ms: 0 m/s
MagiCAD Pset_Heating - v_SizingFlow_ms: 0 m/s; pTot_SizingFlow_kPa: 0 Pa; dpTot_SizingFlow_kPa: 0 Pa
MagiCAD Pset_Pipe - SystemName: +TH=313.000.; Insulation_thickness_mm: 0 mm; qv_SizingFlow_ls: 0 m3/s; User Code: PP; SystemType: SPV; NationalCode: UB2.1114431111; SystemClass: Sanitary; ConnectionSize_mm: 50 mm
ePset_Simplebim - Assembly Level: Leaf
Group: +TH=313.000.
Name | In | Length_mm (mm) | Height (Simplebim) (mm) | Width (Simplebim) (mm) | Length (Simplebim) (mm)
PP avløpsrør | Nivå D + 1,2 m | 12 | 12 | 50 | 50
PP avløpsrør | Nivå D + 1,2 m | 210.263 | 50 | 50 | 210.3
PP avløpsrør | Nivå F - 0,7 m | 192.587 | 50 | 50 | 192.6
PP avløpsrør | Nivå F - 0,7 m | 106.88 | 50 | 50 | 106.9
PP avløpsrør | Nivå F - 0,7 m | 27.985 | 50 | 28 | 50
PP avløpsrør | Nivå F - 0,7 m | 275.285 | 50 | 50 | 275.3
PP avløpsrør | Nivå F - 0,7 m | 45.758 | 46.2 | 50 | 50

# IfcFlowSegment: SSt (12)
In: Nivå D + 1,2 m
Type - PredefinedType: RIGIDSEGMENT
ePset_Simplebim - Assembly Level: Leaf
MagiCAD Pset_Pipe - Material: Rustfritt stål - systemrør; User Code: SSt
Name | Length (Simplebim) (mm) | Height (Simplebim) (mm) | Width (Simplebim) (mm) | MagiCAD Pset_Water, dpTot_SizingFlow_kPa (Pa) = MagiCAD Pset_Water, pTot_SizingFlow_kPa (Pa) = MagiCAD Pset_Water, v_SizingFlow_ms (m/s) = MagiCAD Pset_Heating, v_SizingFlow_ms (m/s) = MagiCAD Pset_Heating, pTot_SizingFlow_kPa (Pa) = MagiCAD Pset_Heating, dpTot_SizingFlow_kPa (Pa) = Insulation_thickness_mm (mm) = qv_SizingFlow_ls (m3/s) | Splitting | SystemType | Length_mm (mm) | SystemClass | ConnectionSize_mm (mm) | SystemName = Group
SSt | 242.7 | 160 | 160 | 0 | ORIGINAL | SPV LUFT | 242.653 | Sanitary | 160 | 31= SPV Kopi 61
SSt | 108 | 19.5 | 108 | 0 | ORIGINAL | SPV LUFT | 19.501 | Sanitary | 108 | +TH=313.310
SSt | 44.4 | 108 | 108 | 0 | ORIGINAL | SPV LUFT | 44.445 | Sanitary | 108 | +TH=313.310
SSt | 108 | 100 | 108 | 0 | ORIGINAL | SPV LUFT | 100.027 | Sanitary | 108 | +TH=313.310
SSt | 145.5 | 108 | 108 | 0 | ORIGINAL | SPV LUFT | 145.479 | Sanitary | 108 | +TH=313.310
SSt | 38.2 | 108 | 108 | 0 | ORIGINAL | SPV LUFT | 38.185 | Sanitary | 108 | +TH=313.310
SSt | 45.5 | 108 | 108 | 0 | ORIGINAL | SPV LUFT | 45.494 | Sanitary | 108 | +TH=313.310
SSt | 72.1 | 108 | 108 | 0 | ORIGINAL | SPV LUFT | 72.141 | Sanitary | 108 | +TH=313.310
SSt | 3186 | 60 | 60 | 0 | ORIGINAL | KV | 3186 | Domestic Cold Water | 60 | +TH=310.001
SSt | 3869.2 | 160 | 160 | 0 | ORIGINAL | SPV LUFT | 3869.24 | Sanitary | 160 | 31= SPV Kopi 61
SSt | 445.3 | 160 | 160 | 0 | ORIGINAL | SPV LUFT | 445.314 | Sanitary | 160 | 31= SPV Kopi 61
SSt | 3434 | 108 | 108 |  | RESULT | SPV LUFT |  | Sanitary |  | +TH=313.310

# IfcFlowSegment: SUPER MA (11)
In: Nivå D + 1,2 m
Type - PredefinedType: RIGIDSEGMENT
ePset_Simplebim - Assembly Level: Leaf
MagiCAD Pset_Pipe - Material: MA; User Code: SUPER MA; SystemClass: Sanitary; NationalCode: UB2.1115131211
Name | Length (Simplebim) (mm) | Height (Simplebim) (mm) = Width (Simplebim) (mm) | MagiCAD Pset_Water, dpTot_SizingFlow_kPa (Pa) = MagiCAD Pset_Water, pTot_SizingFlow_kPa (Pa) = MagiCAD Pset_Water, v_SizingFlow_ms (m/s) = MagiCAD Pset_Heating, v_SizingFlow_ms (m/s) = MagiCAD Pset_Heating, pTot_SizingFlow_kPa (Pa) = MagiCAD Pset_Heating, dpTot_SizingFlow_kPa (Pa) = qv_SizingFlow_ls (m3/s) | Splitting | SystemType | SystemName = Group | Length_mm (mm) | Insulation_thickness_mm (mm) | ConnectionSize_mm (mm)
SUPER MA | 150.9 | 110 | 0 | ORIGINAL | SPV FETT | +TH=313.304 | 150.856 | 29 | 110
SUPER MA | 416.4 | 110 | 0 | ORIGINAL | SPV | 31= SPV Kopi 74 | 415.68 | 0 | 110
SUPER MA | 147.1 | 58 | 0 | ORIGINAL | SPV | 31= SPV Kopi 74 | 147.102 | 0 | 58
SUPER MA | 387.5 | 58 | 0 | ORIGINAL | SPV | 31= SPV Kopi 74 | 387.524 | 0 | 58
SUPER MA | 2201 | 110 | 0 | ORIGINAL | SPV FETT | +TH=313.304 | 2201.04 | 29 | 110
SUPER MA | 1033.3 | 110 | 0 | ORIGINAL | SPV FETT | +TH=313.304 | 1032.76 | 29 | 110
SUPER MA | 514 | 110 | 0 | ORIGINAL | SPV FETT | +TH=313.304 | 514.373 | 29 | 110
SUPER MA | 748.8 | 110 | 0 | ORIGINAL | SPV FETT | +TH=313.304 | 748.826 | 29 | 110
SUPER MA | 1119.2 | 110 | 0 | ORIGINAL | SPV | 31= SPV Kopi 74 | 1119.2 | 29 | 110
SUPER MA | 537.4 | 110 | 0 | ORIGINAL | SPV FETT | +TH=313.304 | 537.417 | 29 | 110
SUPER MA | 4071 | 110 |  | RESULT | SPV FETT | +TH=313.304

# IfcFlowSegment: Stålrør normaltykke (223)
Type - PredefinedType: RIGIDSEGMENT
MagiCAD Pset_Pipe - NationalCode: UB3.144613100; User Code: DN; Material: Stålrør normaltykke
ePset_Simplebim - Assembly Level: Leaf
Name | In | Splitting | MagiCAD Pset_Water, dpTot_SizingFlow_kPa (Pa) = MagiCAD Pset_Water, pTot_SizingFlow_kPa (Pa) = MagiCAD Pset_Water, v_SizingFlow_ms (m/s) = MagiCAD Pset_Heating, v_SizingFlow_ms (m/s) = MagiCAD Pset_Heating, pTot_SizingFlow_kPa (Pa) = MagiCAD Pset_Heating, dpTot_SizingFlow_kPa (Pa) = qv_SizingFlow_ls (m3/s) | SystemType | SystemClass | SystemName = Group | Insulation_thickness_mm (mm) | Length_mm (mm) | ConnectionSize_mm (mm) | Height (Simplebim) (mm) | Width (Simplebim) (mm) | Length (Simplebim) (mm)
Stålrør normaltykke | Nivå D + 1,2 m | ORIGINAL | 0 | 33 Brannslokking våt | Fire Protection Wet | 33= Våt Kopi 163 | 0 | 2926.99 | 25 | 33.8 | 33.8 | 2927
Stålrør normaltykke | Nivå D + 1,2 m | ORIGINAL | 0 | 33 Brannslokking våt | Fire Protection Wet | 33= Våt Kopi 163 | 0 | 492.4 | 25 | 33.8 | 33.8 | 492.4
Stålrør normaltykke | Nivå D + 1,2 m | ORIGINAL | 0 | 33 Brannslokking våt | Fire Protection Wet | 33= Våt Kopi 163 | 0 | 570.587 | 25 | 33.8 | 33.8 | 570.6
Stålrør normaltykke | Nivå D + 1,2 m | ORIGINAL | 0 | 33 Brannslokking våt | Fire Protection Wet | 33= Våt Kopi 163 | 0 | 408.492 | 25 | 33.8 | 33.8 | 408.5
Stålrør normaltykke | Nivå D + 1,2 m | ORIGINAL | 0 | 33 Brannslokking våt | Fire Protection Wet | 33= Våt Kopi 163 | 0 | 13.45 | 25 | 13.3 | 33.8 | 33.8
Stålrør normaltykke | Nivå D + 1,2 m | ORIGINAL | 0 | 33 Brannslokking våt | Fire Protection Wet | 33= Våt Kopi 163 | 0 | 523.152 | 25 | 33.8 | 33.8 | 523.2
Stålrør normaltykke | Nivå D + 1,2 m | ORIGINAL | 0 | 33 Brannslokking våt | Fire Protection Wet | 33= Våt Kopi 163 | 0 | 8.211 | 25 | 8.3 | 33.8 | 33.8
Stålrør normaltykke | Nivå D + 1,2 m | ORIGINAL | 0 | 33 Brannslokking våt | Fire Protection Wet | 33= Våt Kopi 163 | 0 | 14.055 | 25 | 14.1 | 33.8 | 33.8
Stålrør normaltykke | Nivå D + 1,2 m | ORIGINAL | 0 | 33 Brannslokking våt | Fire Protection Wet | 33= Våt Kopi 163 | 0 | 20.287 | 25 | 20.3 | 33.8 | 33.8
Stålrør normaltykke | Nivå D + 1,2 m | ORIGINAL | 0 | 33 Brannslokking våt | Fire Protection Wet | 33= Våt Kopi 163 | 0 | 2916.97 | 25 | 33.8 | 33.8 | 2917
Stålrør normaltykke | Nivå D + 1,2 m | ORIGINAL | 0 | 33 Brannslokking våt | Fire Protection Wet | 33= Våt Kopi 163 | 0 | 14.426 | 25 | 14.1 | 33.8 | 33.8
Stålrør normaltykke | Nivå D + 1,2 m | ORIGINAL | 0 | 33 Brannslokking våt | Fire Protection Wet | 33= Våt Kopi 163 | 0 | 18.052 | 25 | 17.8 | 33.8 | 33.8
Stålrør normaltykke | Nivå D + 1,2 m | ORIGINAL | 0 | 33 Brannslokking våt | Fire Protection Wet | 33= Våt Kopi 163 | 0 | 3420.54 | 25 | 33.8 | 33.8 | 3419.9
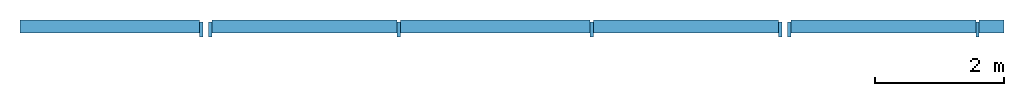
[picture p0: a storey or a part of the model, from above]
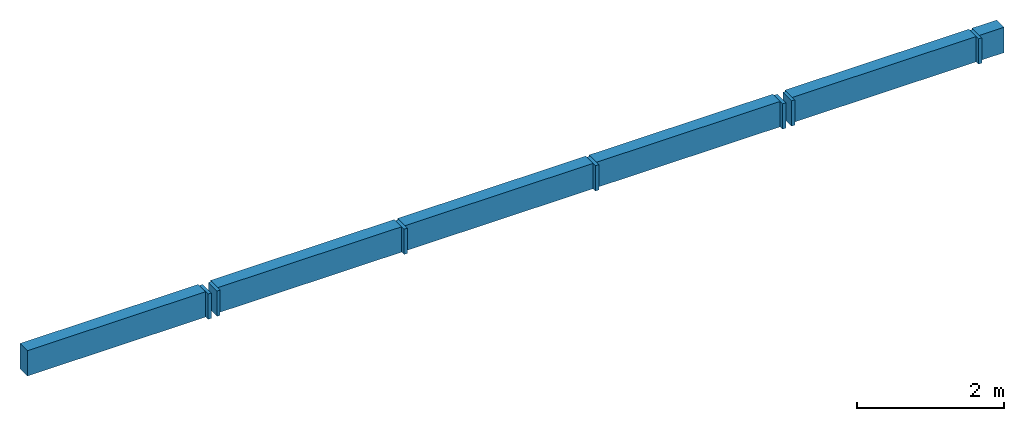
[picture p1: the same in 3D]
Properties of the parts of a building model (IFC2X3), part 5 of 7

# IfcFlowSegment: Stålrør normaltykke (223)
Name | In | Splitting | MagiCAD Pset_Water, dpTot_SizingFlow_kPa (Pa) = MagiCAD Pset_Water, pTot_SizingFlow_kPa (Pa) = MagiCAD Pset_Water, v_SizingFlow_ms (m/s) = MagiCAD Pset_Heating, v_SizingFlow_ms (m/s) = MagiCAD Pset_Heating, pTot_SizingFlow_kPa (Pa) = MagiCAD Pset_Heating, dpTot_SizingFlow_kPa (Pa) = qv_SizingFlow_ls (m3/s) | SystemType | SystemClass | SystemName = Group | Insulation_thickness_mm (mm) | Length_mm (mm) | ConnectionSize_mm (mm) | Height (Simplebim) (mm) | Width (Simplebim) (mm) | Length (Simplebim) (mm)
Stålrør normaltykke | Nivå D + 1,2 m | ORIGINAL | 0 | 33 Brannslokking våt | Fire Protection Wet | 33= Våt Kopi 163 | 0 | 13.148 | 25 | 13.3 | 33.8 | 33.8
Stålrør normaltykke | Nivå D + 1,2 m | ORIGINAL | 0 | 33 Brannslokking våt | Fire Protection Wet | 33= Våt Kopi 163 | 0 | 17.375 | 25 | 17.4 | 33.8 | 33.8
Stålrør normaltykke | Nivå D + 1,2 m | ORIGINAL | 0 | 33 Brannslokking våt | Fire Protection Wet | 33= Våt Kopi 163 | 0 | 50.143 | 25 | 33.8 | 33.8 | 49.9
Stålrør normaltykke | Nivå D + 1,2 m | ORIGINAL | 0 | 33 Brannslokking våt | Fire Protection Wet | 33= Våt Kopi 163 | 0 | 17.721 | 25 | 17.8 | 33.8 | 33.8
Stålrør normaltykke | Nivå D + 1,2 m | ORIGINAL | 0 | 33 Brannslokking våt | Fire Protection Wet | 33= Våt Kopi 163 | 0 | 18.787 | 25 | 18.8 | 33.8 | 33.8
Stålrør normaltykke | Nivå D + 1,2 m | ORIGINAL | 0 | 33 Brannslokking våt | Fire Protection Wet | 33= Våt Kopi 163 | 0 | 2574.91 | 50 | 60.2 | 60.2 | 2574.9
Stålrør normaltykke | Nivå D + 1,2 m | ORIGINAL | 0 | 33 Brannslokking våt | Fire Protection Wet | 33= Våt Kopi 163 | 0 | 30.45 | 25 | 33.8 | 33.8 | 30.1
Stålrør normaltykke | Nivå D + 1,2 m | ORIGINAL | 0 | 33 Brannslokking våt | Fire Protection Wet | 33= Våt Kopi 163 | 0 | 916.411 | 25 | 33.8 | 33.8 | 916.4
Stålrør normaltykke | Nivå D + 1,2 m | ORIGINAL | 0 | 33 Brannslokking våt | Fire Protection Wet | 33= Våt Kopi 163 | 0 | 901.811 | 40 | 48.2 | 48.2 | 901.8
Stålrør normaltykke | Nivå F - 0,7 m | ORIGINAL | 0 | 33 Brannslokking våt | Fire Protection Wet | 33= Våt Kopi 64 | 0 | 50.1 | 40 | 48.2 | 48.2 | 50.4
Stålrør normaltykke | Nivå F - 0,7 m | ORIGINAL | 0 | 33 Brannslokking våt | Fire Protection Wet | 33= Våt Kopi 64 | 0 | 49.973 | 50 | 60.2 | 60.2 | 50
Stålrør normaltykke | Nivå F - 0,7 m | ORIGINAL | 0 | 33 Brannslokking våt | Fire Protection Wet | 33= Våt Kopi 64 | 0 | 2038.42 | 65 | 76 | 76 | 2038.4
Stålrør normaltykke | Nivå F - 0,7 m | ORIGINAL | 0 | 33 Brannslokking våt | Fire Protection Wet | 33= Våt Kopi 64 | 0 | 291.962 | 65 | 76 | 76 | 292.5
Stålrør normaltykke | Nivå F - 0,7 m | ORIGINAL | 0 | 33 Brannslokking våt | Fire Protection Wet | 33= Våt Kopi 64 | 0 | 1224.08 | 65 | 76 | 76 | 1224.1
5 x Stålrør normaltykke | Nivå F - 0,7 m | ORIGINAL | 0 | 33 Brannslokking våt | Fire Protection Wet | 33= Våt Kopi 64 | 0 | 482.452 | 25 | 33.8 | 33.8 | 482.4
2 x Stålrør normaltykke | Nivå F - 0,7 m | ORIGINAL | 0 | 33 Brannslokking våt | Fire Protection Wet | 33= Våt Kopi 64 | 0 | 39.221 | 25 | 33.8 | 33.8 | 38.8
Stålrør normaltykke | Nivå F - 0,7 m | ORIGINAL | 0 | 33 Brannslokking våt | Fire Protection Wet | 33= Våt Kopi 64 | 0 | 1754.16 | 50 | 60.2 | 60.2 | 1754.3
Stålrør normaltykke | Nivå F - 0,7 m | ORIGINAL | 0 | 33 Brannslokking våt | Fire Protection Wet | 33= Våt Kopi 64 | 0 | 2932.4 | 50 | 60.2 | 60.2 | 2932.4
2 x Stålrør normaltykke | Nivå F - 0,7 m | ORIGINAL | 0 | 33 Brannslokking våt | Fire Protection Wet | 33= Våt Kopi 64 | 0 | 48.221 | 25 | 33.8 | 33.8 | 48.2
Stålrør normaltykke | Nivå F - 0,7 m | ORIGINAL | 0 | 33 Brannslokking våt | Fire Protection Wet | 33= Våt Kopi 64 | 0 | 2932.4 | 40 | 48.2 | 48.2 | 2931.9
Stålrør normaltykke | Nivå F - 0,7 m | ORIGINAL | 0 | 33 Brannslokking våt | Fire Protection Wet | 33= Våt Kopi 64 | 0 | 52.721 | 25 | 33.8 | 33.8 | 53
Stålrør normaltykke | Nivå F - 0,7 m | ORIGINAL | 0 | 33 Brannslokking våt | Fire Protection Wet | 33= Våt Kopi 64 | 0 | 2876.3 | 32 | 42.4 | 42.4 | 2876.3
Stålrør normaltykke | Nivå F - 0,7 m | ORIGINAL | 0 | 33 Brannslokking våt | Fire Protection Wet | 33= Våt Kopi 64 | 0 | 2870.43 | 40 | 48.2 | 48.2 | 2870.4
Stålrør normaltykke | Nivå F - 0,7 m | ORIGINAL | 0 | SPRINKEL | Fire Protection Wet | +TH=332.003 | 0 | 935.083 | 65 | 76 | 76 | 935.1
Stålrør normaltykke | Nivå F - 0,7 m | ORIGINAL | 0 | SPRINKEL | Fire Protection Wet | +TH=332.003 | 0 | 1562.16 | 40 | 48.2 | 48.2 | 1562.2
Stålrør normaltykke | Nivå F - 0,7 m | ORIGINAL | 0 | SPRINKEL | Fire Protection Wet | +TH=332.003 | 0 | 2318.77 | 25 | 33.8 | 33.8 | 2318.8
Stålrør normaltykke | Nivå F - 0,7 m | ORIGINAL | 0 | SPRINKEL | Fire Protection Wet | +TH=332.003 | 0 | 18.73 | 40 | 48.2 | 48.2 | 19.1
Stålrør normaltykke | Nivå F - 0,7 m | ORIGINAL | 0 | SPRINKEL | Fire Protection Wet | +TH=332.003 | 0 | 17.325 | 32 | 42.4 | 42.4 | 17.3
Stålrør normaltykke | Nivå F - 0,7 m | ORIGINAL | 0 | SPRINKEL | Fire Protection Wet | +TH=332.003 | 0 | 47.728 | 25 | 33.8 | 33.8 | 48.2
Stålrør normaltykke | Nivå F - 0,7 m | ORIGINAL | 0 | SPRINKEL | Fire Protection Wet | +TH=332.003 | 0 | 2932.4 | 25 | 33.8 | 33.8 | 2932.4
Stålrør normaltykke | Nivå F - 0,7 m | ORIGINAL | 0 | SPRINKEL | Fire Protection Wet | +TH=332.003 | 0 | 24.078 | 15 | 21.4 | 21.4 | 24.1
Stålrør normaltykke | Nivå F - 0,7 m | ORIGINAL | 0 | SPRINKEL | Fire Protection Wet | +TH=332.003 | 0 | 729.178 | 25 | 33.8 | 33.8 | 729.2
Stålrør normaltykke | Nivå F - 0,7 m | ORIGINAL | 0 | SPRINKEL | Fire Protection Wet | +TH=332.003 | 0 | 373.074 | 25 | 33.8 | 33.8 | 372.9
Stålrør normaltykke | Nivå F - 0,7 m | ORIGINAL | 0 | SPRINKEL | Fire Protection Wet | +TH=332.003 | 0 | 107.6 | 25 | 33.8 | 33.8 | 108
Stålrør normaltykke | Nivå F - 0,7 m | ORIGINAL | 0 | SPRINKEL | Fire Protection Wet | +TH=332.003 | 0 | 45.251 | 40 | 48.2 | 48.2 | 45.3
Stålrør normaltykke | Nivå F - 0,7 m | ORIGINAL | 0 | SPRINKEL | Fire Protection Wet | +TH=332.003 | 0 | 263.2 | 40 | 48.2 | 48.2 | 263.2
Stålrør normaltykke | Nivå F - 0,7 m | ORIGINAL | 0 | SPRINKEL | Fire Protection Wet | +TH=332.003 | 0 | 1096.7 | 40 | 48.2 | 48.2 | 1096.7
Stålrør normaltykke | Nivå F - 0,7 m | ORIGINAL | 0 | SPRINKEL | Fire Protection Wet | +TH=332.003 | 0 | 1324.74 | 40 | 48.2 | 48.2 | 1324.7
Stålrør normaltykke | Nivå F - 0,7 m | ORIGINAL | 0 | SPRINKEL | Fire Protection Wet | +TH=332.003 | 0 | 139.509 | 40 | 48.2 | 48.2 | 139.5
3 x Stålrør normaltykke | Nivå F - 0,7 m | ORIGINAL | 0 | SPRINKEL | Fire Protection Wet | +TH=332.003 | 0 | 151.3 | 25 | 33.8 | 33.8 | 151.4
Stålrør normaltykke | Nivå F - 0,7 m | ORIGINAL | 0 | SPRINKEL | Fire Protection Wet | +TH=332.003 | 0 | 2929.9 | 40 | 48.2 | 48.2 | 2929.9
Stålrør normaltykke | Nivå F - 0,7 m | ORIGINAL | 0 | SPRINKEL | Fire Protection Wet | +TH=332.003 | 0 | 17 | 40 | 48.2 | 48.2 | 17
Stålrør normaltykke | Nivå F - 0,7 m | ORIGINAL | 0 | SPRINKEL | Fire Protection Wet | +TH=332.003 | 0 | 113.8 | 25 | 33.8 | 33.8 | 114.5
Stålrør normaltykke | Nivå F - 0,7 m | ORIGINAL | 0 | SPRINKEL | Fire Protection Wet | +TH=332.003 | 0 | 1358.13 | 25 | 33.8 | 33.8 | 1358.1
Stålrør normaltykke | Nivå F - 0,7 m | ORIGINAL | 0 | SPRINKEL | Fire Protection Wet | +TH=332.003 | 0 | 870.219 | 25 | 33.8 | 33.8 | 870.2
Stålrør normaltykke | Nivå F - 0,7 m | ORIGINAL | 0 | SPRINKEL | Fire Protection Wet | +TH=332.003 | 0 | 147.294 | 25 | 33.8 | 33.8 | 147.3
Stålrør normaltykke | Nivå F - 0,7 m | ORIGINAL | 0 | SPRINKEL | Fire Protection Wet | +TH=332.003 | 0 | 745.484 | 65 | 76 | 76 | 745.6
Stålrør normaltykke | Nivå F - 0,7 m | ORIGINAL | 0 | SPRINKEL | Fire Protection Wet | +TH=332.003 | 0 | 118.05 | 25 | 33.8 | 33.8 | 118
Stålrør normaltykke | Nivå F - 0,7 m | ORIGINAL | 0 | SPRINKEL | Fire Protection Wet | +TH=332.003 | 0 | 60.098 | 15 | 21.4 | 21.4 | 60.1
Stålrør normaltykke | Nivå F - 0,7 m | ORIGINAL | 0 | SPRINKEL | Fire Protection Wet | +TH=332.003 | 0 | 506.418 | 25 | 33.8 | 33.8 | 506.1
Stålrør normaltykke | Nivå F - 0,7 m | ORIGINAL | 0 | SPRINKEL | Fire Protection Wet | +TH=332.003 | 0 | 187.505 | 25 | 33.8 | 33.8 | 188
Stålrør normaltykke | Nivå F - 0,7 m | ORIGINAL | 0 | SPRINKEL | Fire Protection Wet | +TH=332.003 | 0 | 3147.35 | 25 | 33.8 | 33.8 | 3147.4
Stålrør normaltykke | Nivå F - 0,7 m | ORIGINAL | 0 | SPRINKEL | Fire Protection Wet | +TH=332.003 | 0 | 506.738 | 25 | 33.8 | 33.8 | 507.4
Stålrør normaltykke | Nivå F - 0,7 m | ORIGINAL | 0 | SPRINKEL | Fire Protection Wet | +TH=332.003 | 0 | 306.445 | 25 | 33.8 | 33.8 | 306.2
Stålrør normaltykke | Nivå F - 0,7 m | ORIGINAL | 0 | SPRINKEL | Fire Protection Wet | +TH=332.003 | 0 | 136.832 | 25 | 33.8 | 33.8 | 136.8
Stålrør normaltykke | Nivå F - 0,7 m | ORIGINAL | 0 | SPRINKEL | Fire Protection Wet | +TH=332.003 | 0 | 2832.4 | 25 | 33.8 | 33.8 | 2832.4
Stålrør normaltykke | Nivå F - 0,7 m | ORIGINAL | 0 | 33 Brannslokking våt | Fire Protection Wet | 33= Våt Kopi 98 | 0 | 316.467 | 25 | 33.8 | 33.8 | 315.5
Stålrør normaltykke | Nivå F - 0,7 m | ORIGINAL | 0 | 33 Brannslokking våt | Fire Protection Wet | 33= Våt Kopi 98 | 0 | 331.246 | 15 | 21.4 | 21.4 | 331.2
Stålrør normaltykke | Nivå F - 0,7 m | ORIGINAL | 0 | SPRINKEL | Fire Protection Wet | +TH=332.003 | 0 | 506.477 | 25 | 33.8 | 33.8 | 506.1
Stålrør normaltykke | Nivå F - 0,7 m | ORIGINAL | 0 | SPRINKEL | Fire Protection Wet | +TH=332.003 | 0 | 147.163 | 25 | 33.8 | 33.8 | 147.3
Stålrør normaltykke | Nivå F - 0,7 m | ORIGINAL | 0 | SPRINKEL | Fire Protection Wet | +TH=332.003 | 0 | 201.6 | 25 | 33.8 | 33.8 | 201.6
Stålrør normaltykke | Nivå F - 0,7 m | ORIGINAL | 0 | SPRINKEL | Fire Protection Wet | +TH=332.003 | 0 | 16.2 | 40 | 16 | 48.2 | 48.2
Stålrør normaltykke | Nivå F - 0,7 m | ORIGINAL | 0 | SPRINKEL | Fire Protection Wet | +TH=332.003 | 0 | 11.2 | 40 | 10.6 | 48.2 | 48.2
4 x Stålrør normaltykke | Nivå F - 0,7 m | ORIGINAL | 0 | SPRINKEL | Fire Protection Wet | +TH=332.003 | 0 | 65.298 | 25 | 33.8 | 33.8 | 65.4
4 x Stålrør normaltykke | Nivå F - 0,7 m | ORIGINAL | 0 | SPRINKEL | Fire Protection Wet | +TH=332.003 | 0 | 52.018 | 25 | 33.8 | 33.8 | 51.8
4 x Stålrør normaltykke | Nivå F - 0,7 m | ORIGINAL | 0 | SPRINKEL | Fire Protection Wet | +TH=332.003 | 0 | 248.848 | 25 | 33.8 | 33.8 | 249.3
Stålrør normaltykke | Nivå F - 0,7 m | ORIGINAL | 0 | SPRINKEL | Fire Protection Wet | +TH=332.003 | 0 | 313.739 | 25 | 33.8 | 33.8 | 314
2 x Stålrør normaltykke | Nivå F - 0,7 m | ORIGINAL | 0 | SPRINKEL | Fire Protection Wet | +TH=332.003 | 0 | 311.239 | 25 | 33.8 | 33.8 | 310.6
Stålrør normaltykke | Nivå F - 0,7 m | ORIGINAL | 0 | SPRINKEL | Fire Protection Wet | +TH=332.003 | 0 | 364.157 | 25 | 33.8 | 33.8 | 364.3
Stålrør normaltykke | Nivå F - 0,7 m | ORIGINAL | 0 | SPRINKEL | Fire Protection Wet | +TH=332.003 | 0 | 2353.6 | 40 | 48.2 | 48.2 | 2353.6
Stålrør normaltykke | Nivå F - 0,7 m | ORIGINAL | 0 | SPRINKEL | Fire Protection Wet | +TH=332.003 | 0 | 2798.6 | 40 | 48.2 | 48.2 | 2798.6
Stålrør normaltykke | Nivå F - 0,7 m | ORIGINAL | 0 | SPRINKEL | Fire Protection Wet | +TH=332.003 | 0 | 402.657 | 40 | 48.2 | 48.2 | 403.2
Stålrør normaltykke | Nivå F - 0,7 m | ORIGINAL | 0 | SPRINKEL | Fire Protection Wet | +TH=332.003 | 0 | 73.33 | 25 | 33.8 | 33.8 | 72.7
Stålrør normaltykke | Nivå F - 0,7 m | ORIGINAL | 0 | SPRINKEL | Fire Protection Wet | +TH=332.003 | 0 | 60.126 | 25 | 33.8 | 33.8 | 60
Stålrør normaltykke | Nivå F - 0,7 m | ORIGINAL | 0 | SPRINKEL | Fire Protection Wet | +TH=332.003 | 0 | 336.65 | 65 | 76 | 76 | 336.6
Stålrør normaltykke | Nivå F - 0,7 m | ORIGINAL | 0 | SPRINKEL | Fire Protection Wet | +TH=332.003 | 0 | 192.804 | 65 | 76 | 76 | 192.8
Stålrør normaltykke | Nivå F - 0,7 m | ORIGINAL | 0 | SPRINKEL | Fire Protection Wet | +TH=332.003 | 0 | 1305.45 | 65 | 76 | 76 | 1305.5
Stålrør normaltykke | Nivå F - 0,7 m | ORIGINAL | 0 | 33 Brannslokking våt | Fire Protection Wet | 33= Våt Kopi 64 | 0 | 474.87 | 65 | 76 | 76 | 475
Stålrør normaltykke | Nivå F - 0,7 m | ORIGINAL | 0 | 33 Brannslokking våt | Fire Protection Wet | 33= Våt Kopi 64 | 0 | 66.117 | 65 | 76 | 76 | 65.8
Stålrør normaltykke | Nivå F - 0,7 m | ORIGINAL | 0 | SPRINKEL | Fire Protection Wet | +TH=332.003 | 0 | 10.313 | 65 | 10.4 | 76 | 76
Stålrør normaltykke | Nivå F - 0,7 m | ORIGINAL | 0 | SPRINKEL | Fire Protection Wet | +TH=332.003 | 0 | 149.917 | 25 | 33.8 | 33.8 | 149.8
Stålrør normaltykke | Nivå F - 0,7 m | ORIGINAL | 0 | SPRINKEL | Fire Protection Wet | +TH=332.003 | 0 | 1017.93 | 65 | 76 | 76 | 1017.6
Stålrør normaltykke | Nivå F - 0,7 m | ORIGINAL | 0 | SPRINKEL | Fire Protection Wet | +TH=332.003 | 0 | 15.962 | 65 | 76 | 76 | 16
Stålrør normaltykke | Nivå F - 0,7 m | ORIGINAL | 0 | SPRINKEL | Fire Protection Wet | +TH=332.003 | 0 | 129.61 | 40 | 48.2 | 48.2 | 129.5
Stålrør normaltykke | Nivå F - 0,7 m | ORIGINAL | 0 | SPRINKEL | Fire Protection Wet | +TH=332.003 | 0 | 1970.82 | 65 | 76 | 76 | 1970.8
Stålrør normaltykke | Nivå F - 0,7 m | ORIGINAL | 0 | SPRINKEL | Fire Protection Wet | +TH=332.003 | 0 | 42.975 | 15 | 21.4 | 21.4 | 43
Stålrør normaltykke | Nivå F - 0,7 m | ORIGINAL | 0 | SPRINKEL | Fire Protection Wet | +TH=332.003 | 0 | 18.064 | 20 | 26.6 | 26.6 | 18.1
Stålrør normaltykke | Nivå F - 0,7 m | ORIGINAL | 0 | SPRINKEL | Fire Protection Wet | +TH=332.003 | 0 | 2487.6 | 65 | 76 | 76 | 2487.6
Stålrør normaltykke | Nivå F - 0,7 m | ORIGINAL | 0 | SPRINKEL | Fire Protection Wet | +TH=332.003 | 0 | 8.148 | 15 | 8.2 | 21.4 | 21.4
Stålrør normaltykke | Nivå F - 0,7 m | ORIGINAL | 0 | SPRINKEL | Fire Protection Wet | +TH=332.003 | 0 | 60.099 | 20 | 26.6 | 26.6 | 60.1
Stålrør normaltykke | Nivå F - 0,7 m | ORIGINAL | 0 | SPRINKEL | Fire Protection Wet | +TH=332.003 | 0 | 260.873 | 20 | 26.6 | 26.6 | 260.9
Stålrør normaltykke | Nivå F - 0,7 m | ORIGINAL | 0 | SPRINKEL | Fire Protection Wet | 33= Våt Kopi 36 | 0 | 42.975 | 15 | 21.4 | 21.4 | 43
Stålrør normaltykke | Nivå F - 0,7 m | ORIGINAL | 0 | SPRINKEL | Fire Protection Wet | 33= Våt Kopi 36 | 0 | 118.064 | 20 | 26.6 | 26.6 | 118.1
Stålrør normaltykke | Nivå F - 0,7 m | ORIGINAL | 0 | SPRINKEL | Fire Protection Wet | 33= Våt Kopi 36 | 0 | 33.148 | 15 | 21.4 | 21.4 | 33.1
Stålrør normaltykke | Nivå F - 0,7 m | ORIGINAL | 0 | SPRINKEL | Fire Protection Wet | 33= Våt Kopi 36 | 0 | 60.099 | 20 | 26.6 | 26.6 | 60.1
Stålrør normaltykke | Nivå F - 0,7 m | ORIGINAL | 0 | SPRINKEL | Fire Protection Wet | 33= Våt Kopi 36 | 0 | 260.873 | 20 | 26.6 | 26.6 | 260.9
Stålrør normaltykke | Nivå F - 0,7 m | ORIGINAL | 0 | SPRINKEL | Fire Protection Wet | 33= Våt Kopi 37 | 0 | 42.975 | 15 | 21.4 | 21.4 | 43
Stålrør normaltykke | Nivå F - 0,7 m | ORIGINAL | 0 | SPRINKEL | Fire Protection Wet | 33= Våt Kopi 37 | 0 | 118.064 | 20 | 26.6 | 26.6 | 118.1
Stålrør normaltykke | Nivå F - 0,7 m | ORIGINAL | 0 | SPRINKEL | Fire Protection Wet | 33= Våt Kopi 37 | 0 | 33.148 | 15 | 21.4 | 21.4 | 33.1
Stålrør normaltykke | Nivå F - 0,7 m | ORIGINAL | 0 | SPRINKEL | Fire Protection Wet | 33= Våt Kopi 37 | 0 | 60.099 | 20 | 26.6 | 26.6 | 60.1
Stålrør normaltykke | Nivå F - 0,7 m | ORIGINAL | 0 | SPRINKEL | Fire Protection Wet | 33= Våt Kopi 37 | 0 | 260.873 | 20 | 26.6 | 26.6 | 260.9
Stålrør normaltykke | Nivå F - 0,7 m | ORIGINAL | 0 | SPRINKEL | Fire Protection Wet | 33= Våt Kopi 39 | 0 | 42.975 | 15 | 21.4 | 21.4 | 43
Stålrør normaltykke | Nivå F - 0,7 m | ORIGINAL | 0 | SPRINKEL | Fire Protection Wet | 33= Våt Kopi 39 | 0 | 118.064 | 20 | 26.6 | 26.6 | 118.1
Stålrør normaltykke | Nivå F - 0,7 m | ORIGINAL | 0 | SPRINKEL | Fire Protection Wet | 33= Våt Kopi 39 | 0 | 33.148 | 15 | 21.4 | 21.4 | 33.1
Stålrør normaltykke | Nivå F - 0,7 m | ORIGINAL | 0 | SPRINKEL | Fire Protection Wet | 33= Våt Kopi 39 | 0 | 60.099 | 20 | 26.6 | 26.6 | 60.1
Stålrør normaltykke | Nivå F - 0,7 m | ORIGINAL | 0 | SPRINKEL | Fire Protection Wet | 33= Våt Kopi 39 | 0 | 260.873 | 20 | 26.6 | 26.6 | 260.9
Stålrør normaltykke | Nivå F - 0,7 m | ORIGINAL | 0 | SPRINKEL | Fire Protection Wet | +TH=332.003 | 0 | 5481.07 | 65 | 76 | 76 | 5481.1
Stålrør normaltykke | Nivå F - 0,7 m | ORIGINAL | 0 | SPRINKEL | Fire Protection Wet | +TH=332.003 | 0 | 214.634 | 65 | 76 | 76 | 214.6
Stålrør normaltykke | Nivå F - 0,7 m | ORIGINAL | 0 | SPRINKEL | Fire Protection Wet | +TH=332.003 | 0 | 489.848 | 25 | 33.8 | 33.8 | 490.5
Stålrør normaltykke | Nivå F - 0,7 m | ORIGINAL | 0 | SPRINKEL | Fire Protection Wet | +TH=332.003 | 0 | 112.505 | 25 | 33.8 | 33.8 | 111.6
Stålrør normaltykke | Nivå F - 0,7 m | ORIGINAL | 0 | SPRINKEL | Fire Protection Wet | +TH=332.003 | 0 | 39.9 | 25 | 33.8 | 33.8 | 39.6
Stålrør normaltykke | Nivå F - 0,7 m | ORIGINAL | 0 | SPRINKEL | Fire Protection Wet | +TH=332.003 | 0 | 19.138 | 25 | 18.8 | 33.8 | 33.8
2 x Stålrør normaltykke | Nivå F - 0,7 m | ORIGINAL | 0 | SPRINKEL | Fire Protection Wet | +TH=332.003 | 0 | 707.6 | 65 | 76 | 76 | 707.6
Stålrør normaltykke | Nivå F - 0,7 m | ORIGINAL | 0 | SPRINKEL | Fire Protection Wet | +TH=332.003 | 0 | 547.6 | 65 | 76 | 76 | 547.6
Stålrør normaltykke | Nivå F - 0,7 m | ORIGINAL | 0 | SPRINKEL | Fire Protection Wet | +TH=332.003 | 0 | 404.034 | 65 | 76 | 76 | 403.8
Stålrør normaltykke | Nivå F - 0,7 m | ORIGINAL | 0 | SPRINKEL | Fire Protection Wet | +TH=332.003 | 0 | 70.12 | 15 | 21.4 | 21.4 | 70.1
Stålrør normaltykke | Nivå F - 0,7 m | ORIGINAL | 0 | SPRINKEL | Fire Protection Wet | +TH=332.003 | 0 | 236.834 | 25 | 33.8 | 33.8 | 237.2
Stålrør normaltykke | Nivå F - 0,7 m | ORIGINAL | 0 | SPRINKEL | Fire Protection Wet | +TH=332.003 | 0 | 6.475 | 25 | 5.8 | 33.8 | 33.8
Stålrør normaltykke | Nivå F - 0,7 m | ORIGINAL | 0 | SPRINKEL | Fire Protection Wet | +TH=332.003 | 0 | 246.281 | 25 | 33.8 | 33.8 | 246.2
Stålrør normaltykke | Nivå F - 0,7 m | ORIGINAL | 0 | SPRINKEL | Fire Protection Wet | +TH=332.003 | 0 | 267.646 | 32 | 42.4 | 42.4 | 267.6
Stålrør normaltykke | Nivå D + 1,2 m | ORIGINAL | 0 | KJØL T | Hydronic Supply | 37= T 9° Kopi 2 | 0 | 2883.02 | 32 | 42.4 | 42.4 | 2883 | MagiCAD Pset_Pipe - Product variable 1: DN
Stålrør normaltykke | Nivå D + 1,2 m | ORIGINAL | 0 | KJØL R | Hydronic Return | 37= R 18° Kopi 1 | 0 | 2853.71 | 32 | 42.4 | 42.4 | 2853.7 | MagiCAD Pset_Pipe - Product variable 1: DN
Stålrør normaltykke | Nivå D + 1,2 m | ORIGINAL | 0 | GULVVARME T | Hydronic Supply | 32= T 35° Kopi 1 | 0 | 3400.2 | 50 | 60.2 | 60.2 | 3400.2 | MagiCAD Pset_Pipe - Product variable 1: DN
Stålrør normaltykke | Nivå D + 1,2 m | ORIGINAL | 0 | GULVVARME R | Hydronic Return | 32= R 27° Kopi 5 | 0 | 3400.2 | 50 | 60.2 | 60.2 | 3400.2 | MagiCAD Pset_Pipe - Product variable 1: DN
Stålrør normaltykke | Nivå D + 1,2 m | ORIGINAL | 0 | GULVVARME R | Hydronic Return | 32= R 27° Kopi 5 | 27 | 291.433 | 50 | 60.2 | 60.2 | 291.4 | MagiCAD Pset_Pipe - Product variable 1: DN
Stålrør normaltykke | Nivå D + 1,2 m | ORIGINAL | 0 | GULVVARME T | Hydronic Supply | 32= T 35° Kopi 1 | 27 | 452.781 | 50 | 60.2 | 60.2 | 452.8 | MagiCAD Pset_Pipe - Product variable 1: DN
Stålrør normaltykke | Nivå D + 1,2 m | ORIGINAL | 0 | KJØL T | Hydronic Supply | 37= T 9° Kopi 2 | 0 | 664.937 | 32 | 42.4 | 42.4 | 664.9 | MagiCAD Pset_Pipe - Product variable 1: DN
Stålrør normaltykke | Nivå D + 1,2 m | ORIGINAL | 0 | KJØL R | Hydronic Return | 37= R 18° Kopi 1 | 0 | 654.937 | 32 | 42.4 | 42.4 | 654.9 | MagiCAD Pset_Pipe - Product variable 1: DN
Stålrør normaltykke | Nivå D + 1,2 m | ORIGINAL | 0 | KJØL T | Hydronic Supply | 37= T 9° Kopi 2 | 0 | 36.127 | 32 | 42.4 | 42.4 | 36.1 | MagiCAD Pset_Pipe - Product variable 1: DN
Stålrør normaltykke | Nivå D + 1,2 m | ORIGINAL | 0 | KJØL R | Hydronic Return | 37= R 18° Kopi 1 | 0 | 29.829 | 32 | 42.4 | 42.4 | 29.8 | MagiCAD Pset_Pipe - Product variable 1: DN
Stålrør normaltykke | Nivå F - 0,7 m | ORIGINAL | 0 | KJØL T | Hydronic Supply | 37= T 9° Kopi 2 | 0 | 856.209 | 32 | 42.4 | 42.4 | 856.2 | MagiCAD Pset_Pipe - Product variable 1: DN
Stålrør normaltykke | Nivå F - 0,7 m | ORIGINAL | 0 | KJØL R | Hydronic Return | 37= R 18° Kopi 1 | 0 | 955.2 | 32 | 42.4 | 42.4 | 955.2 | MagiCAD Pset_Pipe - Product variable 1: DN
Stålrør normaltykke | Nivå F - 0,7 m | ORIGINAL | 0 | KJØL R | Hydronic Return | 37= R 18° Kopi 1 | 0 | 4130.8 | 20 | 26.6 | 26.6 | 4130.8 | MagiCAD Pset_Pipe - Product variable 1: DN
Stålrør normaltykke | Nivå F - 0,7 m | ORIGINAL | 0 | KJØL T | Hydronic Supply | 37= T 9° Kopi 2 | 0 | 4130.8 | 20 | 26.6 | 26.6 | 4130.8 | MagiCAD Pset_Pipe - Product variable 1: DN
Stålrør normaltykke | Nivå F - 0,7 m | ORIGINAL | 0 | KJØL T | Hydronic Supply | 37= T 9° Kopi 2 | 0 | 7.825 | 32 | 42.4 | 42.4 | 7.8 | MagiCAD Pset_Pipe - Product variable 1: DN
Stålrør normaltykke | Nivå F - 0,7 m | ORIGINAL | 0 | KJØL T | Hydronic Supply | 37= T 9° Kopi 2 | 0 | 190.953 | 32 | 42.4 | 42.4 | 191.4 | MagiCAD Pset_Pipe - Product variable 1: DN
Stålrør normaltykke | Nivå F - 0,7 m | ORIGINAL | 0 | KJØL R | Hydronic Return | 37= R 18° Kopi 1 | 0 | 3.372 | 32 | 42.4 | 42.4 | 3.4 | MagiCAD Pset_Pipe - Product variable 1: DN
Stålrør normaltykke | Nivå F - 0,7 m | ORIGINAL | 0 | KJØL R | Hydronic Return | 37= R 18° Kopi 1 | 0 | 10.2 | 32 | 10.4 | 42.4 | 42.4 | MagiCAD Pset_Pipe - Product variable 1: DN
Stålrør normaltykke | Nivå F - 0,7 m | ORIGINAL | 0 | KJØL R | Hydronic Return | 37= R 18° Kopi 1 | 0 | 60.468 | 32 | 42.4 | 42.4 | 60.2 | MagiCAD Pset_Pipe - Product variable 1: DN
Stålrør normaltykke | Nivå F - 0,7 m | ORIGINAL | 0 | KJØL R | Hydronic Return | 37= R 18° Kopi 1 | 0 | 238.426 | 32 | 42.4 | 42.4 | 238.4 | MagiCAD Pset_Pipe - Product variable 1: DN
Stålrør normaltykke | Nivå F - 0,7 m | ORIGINAL | 0 | KJØL R | Hydronic Return | 37= R 18° Kopi 1 | 0 | 123.4 | 32 | 42.4 | 42.4 | 123.3 | MagiCAD Pset_Pipe - Product variable 1: DN
Stålrør normaltykke | Nivå F - 0,7 m | ORIGINAL | 0 | KJØL T | Hydronic Supply | 37= T 9° Kopi 2 | 0 | 60.468 | 32 | 42.4 | 42.4 | 60.2 | MagiCAD Pset_Pipe - Product variable 1: DN
Stålrør normaltykke | Nivå F - 0,7 m | ORIGINAL | 0 | KJØL T | Hydronic Supply | 37= T 9° Kopi 2 | 0 | 42.968 | 32 | 42.4 | 42.4 | 43.2 | MagiCAD Pset_Pipe - Product variable 1: DN
Stålrør normaltykke | Nivå F - 0,7 m | ORIGINAL | 0 | KJØL T | Hydronic Supply | 37= T 9° Kopi 2 | 0 | 162.2 | 32 | 42.4 | 42.4 | 161.8 | MagiCAD Pset_Pipe - Product variable 1: DN
Stålrør normaltykke | Nivå F - 0,7 m | ORIGINAL | 0 | GULVVARME R | Hydronic Return | 32= R 27° Kopi 5 | 0 | 479.2 | 50 | 60.2 | 60.2 | 479.2 | MagiCAD Pset_Pipe - Product variable 1: DN
Stålrør normaltykke | Nivå F - 0,7 m | ORIGINAL | 0 | GULVVARME T | Hydronic Supply | 32= T 35° Kopi 1 | 0 | 609.2 | 50 | 60.2 | 60.2 | 609.2 | MagiCAD Pset_Pipe - Product variable 1: DN
2 x Stålrør normaltykke | Nivå F - 0,7 m | ORIGINAL | 0 | KJØL R | Hydronic Return | 37= R 18° Kopi 1 | 0 | 306.4 | 20 | 26.6 | 26.6 | 306.4 | MagiCAD Pset_Pipe - Product variable 1: DN
Stålrør normaltykke | Nivå F - 0,7 m | ORIGINAL | 0 | KJØL R | Hydronic Return | 37= R 18° Kopi 1 | 0 | 120.2 | 20 | 26.6 | 26.6 | 120.2 | MagiCAD Pset_Pipe - Product variable 1: DN
Stålrør normaltykke | Nivå F - 0,7 m | ORIGINAL | 0 | KJØL R | Hydronic Return | 37= R 18° Kopi 1 | 0 | 718.275 | 25 | 33.8 | 33.8 | 718.2 | MagiCAD Pset_Pipe - Product variable 1: DN
2 x Stålrør normaltykke | Nivå F - 0,7 m | ORIGINAL | 0 | KJØL R | Hydronic Return | 37= R 18° Kopi 1 | 0 | 169.62 | 20 | 26.6 | 26.6 | 169.6 | MagiCAD Pset_Pipe - Product variable 1: DN
2 x Stålrør normaltykke | Nivå F - 0,7 m | ORIGINAL | 0 | KJØL T | Hydronic Supply | 37= T 9° Kopi 2 | 0 | 266.4 | 20 | 26.6 | 26.6 | 266.4 | MagiCAD Pset_Pipe - Product variable 1: DN
Stålrør normaltykke | Nivå F - 0,7 m | ORIGINAL | 0 | KJØL T | Hydronic Supply | 37= T 9° Kopi 2 | 0 | 120.2 | 20 | 26.6 | 26.6 | 120.2 | MagiCAD Pset_Pipe - Product variable 1: DN
Stålrør normaltykke | Nivå F - 0,7 m | ORIGINAL | 0 | KJØL T | Hydronic Supply | 37= T 9° Kopi 2 | 0 | 622.788 | 25 | 33.8 | 33.8 | 622.8 | MagiCAD Pset_Pipe - Product variable 1: DN
2 x Stålrør normaltykke | Nivå F - 0,7 m | ORIGINAL | 0 | KJØL T | Hydronic Supply | 37= T 9° Kopi 2 | 0 | 53.2 | 20 | 26.6 | 26.6 | 53.2 | MagiCAD Pset_Pipe - Product variable 1: DN
Stålrør normaltykke | Nivå F - 0,7 m | ORIGINAL | 0 | KJØL R | Hydronic Return | 37= R 18° Kopi 1 | 0 | 131.9 | 20 | 26.6 | 26.6 | 131.9 | MagiCAD Pset_Pipe - Product variable 1: DN
Stålrør normaltykke | Nivå F - 0,7 m | ORIGINAL | 0 | KJØL T | Hydronic Supply | 37= T 9° Kopi 2 | 0 | 131.9 | 20 | 26.6 | 26.6 | 131.9 | MagiCAD Pset_Pipe - Product variable 1: DN
Stålrør normaltykke | Nivå F - 0,7 m | ORIGINAL | 0 | KJØL R | Hydronic Return | 37= R 18° Kopi 1 | 0 | 32.65 | 20 | 26.6 | 26.6 | 32.8 | MagiCAD Pset_Pipe - Product variable 1: DN
Stålrør normaltykke | Nivå F - 0,7 m | ORIGINAL | 0 | KJØL R | Hydronic Return | 37= R 18° Kopi 1 | 0 | 3781.03 | 32 | 42.4 | 42.4 | 3781 | MagiCAD Pset_Pipe - Product variable 1: DN
Stålrør normaltykke | Nivå F - 0,7 m | ORIGINAL | 0 | KJØL T | Hydronic Supply | 37= T 9° Kopi 2 | 0 | 32.65 | 20 | 26.6 | 26.6 | 32.8 | MagiCAD Pset_Pipe - Product variable 1: DN
Stålrør normaltykke | Nivå F - 0,7 m | ORIGINAL | 0 | KJØL T | Hydronic Supply | 37= T 9° Kopi 2 | 0 | 4040.13 | 32 | 42.4 | 42.4 | 4040.1 | MagiCAD Pset_Pipe - Product variable 1: DN
Stålrør normaltykke | Nivå F - 0,7 m | ORIGINAL | 0 | KJØL R | Hydronic Return | 37= R 18° Kopi 1 | 0 | 662.843 | 32 | 42.4 | 42.4 | 662.8 | MagiCAD Pset_Pipe - Product variable 1: DN
Stålrør normaltykke | Nivå F - 0,7 m | ORIGINAL | 0 | KJØL T | Hydronic Supply | 37= T 9° Kopi 2 | 0 | 435.479 | 32 | 42.4 | 42.4 | 435.5 | MagiCAD Pset_Pipe - Product variable 1: DN
Stålrør normaltykke | Nivå F - 0,7 m | ORIGINAL | 0 | KJØL R | Hydronic Return | 37= R 18° Kopi 1 | 0 | 3640.15 | 20 | 26.6 | 26.6 | 3640.1 | MagiCAD Pset_Pipe - Product variable 1: DN
Stålrør normaltykke | Nivå F - 0,7 m | ORIGINAL | 0 | KJØL R | Hydronic Return | 37= R 18° Kopi 1 | 0 | 273.2 | 20 | 26.6 | 26.6 | 273.2 | MagiCAD Pset_Pipe - Product variable 1: DN
Stålrør normaltykke | Nivå F - 0,7 m | ORIGINAL | 0 | KJØL R | Hydronic Return | 37= R 18° Kopi 1 | 0 | 416.45 | 20 | 26.6 | 26.6 | 416.4 | MagiCAD Pset_Pipe - Product variable 1: DN
Stålrør normaltykke | Nivå F - 0,7 m | ORIGINAL | 0 | KJØL T | Hydronic Supply | 37= T 9° Kopi 2 | 0 | 3791.4 | 20 | 26.6 | 26.6 | 3791.4 | MagiCAD Pset_Pipe - Product variable 1: DN
Stålrør normaltykke | Nivå F - 0,7 m | ORIGINAL | 0 | KJØL T | Hydronic Supply | 37= T 9° Kopi 2 | 0 | 457.395 | 20 | 26.6 | 26.6 | 457.4 | MagiCAD Pset_Pipe - Product variable 1: DN
Stålrør normaltykke | Nivå F - 0,7 m | ORIGINAL | 0 | KJØL T | Hydronic Supply | 37= T 9° Kopi 2 | 0 | 416.45 | 20 | 26.6 | 26.6 | 416.4 | MagiCAD Pset_Pipe - Product variable 1: DN
Stålrør normaltykke | Nivå F - 0,7 m | ORIGINAL | 0 | KJØL T | Hydronic Supply | 37= T 9° Kopi 2 | 0 | 356.141 | 20 | 26.6 | 26.6 | 356.3 | MagiCAD Pset_Pipe - Product variable 1: DN
Stålrør normaltykke | Nivå F - 0,7 m | ORIGINAL | 0 | KJØL R | Hydronic Return | 37= R 18° Kopi 1 | 0 | 229.573 | 20 | 26.6 | 26.6 | 229.6 | MagiCAD Pset_Pipe - Product variable 1: DN
2 x Stålrør normaltykke | Nivå F - 0,7 m | ORIGINAL | 0 | KJØL R | Hydronic Return | 37= R 18° Kopi 1 | 0 | 5.15 | 20 | 26.6 | 26.6 | 4.6 | MagiCAD Pset_Pipe - Product variable 1: DN
Stålrør normaltykke | Nivå F - 0,7 m | ORIGINAL | 0 | KJØL R | Hydronic Return | 37= R 18° Kopi 1 | 0 | 37.65 | 20 | 26.6 | 26.6 | 38 | MagiCAD Pset_Pipe - Product variable 1: DN
Stålrør normaltykke | Nivå F - 0,7 m | ORIGINAL | 0 | KJØL R | Hydronic Return | 37= R 18° Kopi 1 | 0 | 226.627 | 20 | 26.6 | 26.6 | 226.6 | MagiCAD Pset_Pipe - Product variable 1: DN
2 x Stålrør normaltykke | Nivå F - 0,7 m | ORIGINAL | 0 | KJØL T | Hydronic Supply | 37= T 9° Kopi 2 | 0 | 6.4 | 20 | 6.4 | 26.6 | 26.6 | MagiCAD Pset_Pipe - Product variable 1: DN
Stålrør normaltykke | Nivå F - 0,7 m | ORIGINAL | 0 | KJØL T | Hydronic Supply | 37= T 9° Kopi 2 | 0 | 51.4 | 20 | 26.6 | 26.6 | 51.4 | MagiCAD Pset_Pipe - Product variable 1: DN
Stålrør normaltykke | Nivå F - 0,7 m | ORIGINAL | 0 | KJØL T | Hydronic Supply | 37= T 9° Kopi 2 | 0 | 311.059 | 20 | 26.6 | 26.6 | 311.1 | MagiCAD Pset_Pipe - Product variable 1: DN
Stålrør normaltykke | Nivå F - 0,7 m | RESULT |  | 33 Brannslokking våt | Fire Protection Wet | 33= Våt Kopi 64 |  |  |  | 42 | 42 | 1354
Stålrør normaltykke | Nivå F - 0,7 m | RESULT |  | SPRINKEL | Fire Protection Wet | +TH=332.003 |  |  |  | 76 | 76 | 719
Stålrør normaltykke | Nivå F - 0,7 m | RESULT |  | GULVVARME T | Hydronic Supply | 32= T 35° Kopi 1 |  |  |  | 60 | 60 | 391 | MagiCAD Pset_Pipe - Product variable 1: DN
Stålrør normaltykke | Nivå D + 1,2 m | RESULT |  | GULVVARME T | Hydronic Supply | 32= T 35° Kopi 1 |  |  |  | 60 | 60 | 391 | MagiCAD Pset_Pipe - Product variable 1: DN
Stålrør normaltykke | Nivå D + 1,2 m | RESULT |  | 33 Brannslokking våt | Fire Protection Wet | 33= Våt Kopi 163 |  |  |  | 34 | 34 | 1802
Stålrør normaltykke | Nivå D + 1,2 m | RESULT |  | 33 Brannslokking våt | Fire Protection Wet | 33= Våt Kopi 163 |  |  |  | 42 | 42 | 2608
Stålrør normaltykke | Nivå D + 1,2 m | RESULT |  | 33 Brannslokking våt | Fire Protection Wet | 33= Våt Kopi 163 |  |  |  | 60 | 60 | 765
Stålrør normaltykke | Nivå D + 1,2 m | RESULT |  | 33 Brannslokking våt | Fire Protection Wet | 33= Våt Kopi 163 |  |  |  | 48 | 48 | 2510
Stålrør normaltykke | Nivå D + 1,2 m | RESULT |  | 33 Brannslokking våt | Fire Protection Wet | 33= Våt Kopi 163 |  |  |  | 42 | 42 | 2587

# IfcFlowSegment: Trekkerør, glatt (38)
Type - PredefinedType: CONDUITSEGMENT
ePset_Simplebim - Assembly Level: Leaf
Name | In | Splitting | NominalLength (mm) = Length [mm] (mm) | NominalWidth (mm) = NominalHeight (mm) | Height (Simplebim) (mm) = Width (Simplebim) (mm) | Length (Simplebim) (mm) | System code | Diameter [mm] (mm) | Group
3 x Trekkerør, glatt | Nivå D + 1,2 m | ORIGINAL | 2230.01 | 50 | 55.8 | 2230 | 5113 | 55.8 | Trekkerør for tele- og automasjon
20 x Trekkerør, glatt | Nivå F - 0,7 m | ORIGINAL | 2600 | 20 | 23 | 2600 | 4110 | 23 | Trekkerør generelt
10 x Trekkerør, glatt | Nivå F - 0,7 m | ORIGINAL | 1160 | 25 | 26.4 | 1160 | 4110 | 26.42 | Trekkerør generelt
5 x Trekkerør, glatt | Nivå D + 1,2 m | RESULT |  |  | 114 | 315 | 4110 |  | Trekkerør generelt

# IfcFlowSegment: Veggkanal
In: Nivå F - 0,7 m
Type - PredefinedType: CABLETRAYSEGMENT
MagiCAD Pset_Cabletray - Width [mm]: 123 mm; Height [mm]: 72 mm; Length [mm]: 900 mm; System code: 4112
ePset_SimplebimBasicQuantities - Height (Simplebim): 123 mm; Width (Simplebim): 72 mm; Length (Simplebim): 900 mm
Pset_CableCarrierSegmentTypeCableTraySegment - NominalWidth: 123 mm; NominalHeight: 72 mm; NominalLength: 900 mm
ePset_LocationTool - Splitting: ORIGINAL
ePset_Simplebim - Assembly Level: Leaf
Group: Veggkanal for generelt

# IfcFlowTerminal: A10-S350 118 WALL
In: Nivå F - 0,7 m
Type - Description: Glamox A10-S is a very versatile circular luminaire with high light output and a decorative ill
MagiCAD Pset_Device - System code: 442; Circuit order no: 32; Switchboard: +TH=433.055; Manufacturer: Glamox; Power Factor: 0.9; Length [mm]: 0 mm; Width [mm]: 0 mm; Height [mm]: 0 mm; Number of Poles: 1; User code: IB2120; Active Power: 20 W; Voltage: 230
ePset_LocationTool - Splitting: ORIGINAL
ePset_Simplebim - Assembly Level: Leaf
Pset_ElectricalDeviceCommon - NumberOfPoles: 1; ElectricalDeviceNominalPower: 20 W; NominalVoltage: 230
Pset_LightFixtureTypeCommon - TotalWattage: 20 W
Group: Belysningsutstyr

# IfcFlowTerminal: AP832 Himling
In: Nivå F - 0,7 m
Type - Description: WLAN AP832 for Himling/ Tag; PredefinedType: COMMUNICATIONSOUTLET
ePset_LocationTool - Splitting: ORIGINAL
Pset_OutletTypeCommon - IsPluggableOutlet: yes
MagiCAD Pset_Device - Manufacturer: MERU; Length [mm]: 0 mm; Width [mm]: 0 mm; Height [mm]: 0 mm
ePset_Simplebim - Assembly Level: Leaf

# IfcFlowTerminal: BRTR-2000-1150
In: Nivå D + 1,2 m
Type - Description: Wire mesh grilles, rectangular
ePset_Simplebim - Assembly Level: Leaf
ePset_LocationTool - Splitting: RESULT
MagiCAD Pset_AirTerminal - Manufacturer: Bevent Rasch; ProductCode: BRTR-2000-1150; Description: Wire mesh grilles, rectangular
Group: +TH=360.010 (28)

# IfcFlowTerminal: CC-15-K80-68DGR-STD-SKJULT I HIMLING
In: Nivå F - 0,7 m
Type - Description: Consealed sprinkler, STD, K=80
MagiCAD Pset_Sprinkler - Description: Consealed sprinkler, STD, K=80; Manufacturer: General; Nominal Release Temperature [°C]: 68; KFactor: 80
ePset_LocationTool - Splitting: ORIGINAL
ePset_Simplebim - Assembly Level: Leaf
Group: +TH=332.003

# IfcFlowTerminal: Datauttak dobbel Gulv - IKT
In: Nivå F - 0,7 m
Type - Description: Datauttak dobbel Gulv - IKT; PredefinedType: COMMUNICATIONSOUTLET
Pset_OutletTypeCommon - IsPluggableOutlet: yes
ePset_LocationTool - Splitting: ORIGINAL
ePset_Simplebim - Assembly Level: Leaf
MagiCAD Pset_Device - System code: 574; User code: -WD; Length [mm]: 0 mm; Width [mm]: 0 mm; Height [mm]: 0 mm
Group: Spredenett

# IfcFlowTerminal: Datauttak dobbel Tak - WLAN (2)
In: Nivå F - 0,7 m
Type - Description: Dobbelt datauttak i tak for WLAN; PredefinedType: COMMUNICATIONSOUTLET
ePset_LocationTool - Splitting: ORIGINAL
Pset_OutletTypeCommon - IsPluggableOutlet: yes
ePset_Simplebim - Assembly Level: Leaf
MagiCAD Pset_Device - System code: 574; User code: -WD; Length [mm]: 0 mm; Width [mm]: 0 mm; Height [mm]: 0 mm
Group: Spredenett

# IfcFlowTerminal: Datauttak dobbel Vegg - IKT (10)
In: Nivå F - 0,7 m
Type - Description: Datauttak dobbel Vegg - IKT; PredefinedType: COMMUNICATIONSOUTLET
ePset_LocationTool - Splitting: ORIGINAL
Pset_OutletTypeCommon - IsPluggableOutlet: yes
ePset_Simplebim - Assembly Level: Leaf
MagiCAD Pset_Device - System code: 574; User code: -WD; Length [mm]: 0 mm; Width [mm]: 0 mm; Height [mm]: 0 mm
Group: Spredenett
Name
Datauttak dobbel Vegg - IKT | MagiCAD Pset_Device - O1: Uttak for Monitor montert i VVS-sjakt
9 x Datauttak dobbel Vegg - IKT

# IfcFlowTerminal: Datauttak enkelt Vegg - IKT (2)
In: Nivå F - 0,7 m
Type - Description: Datauttak enkelt Vegg - IKT; PredefinedType: COMMUNICATIONSOUTLET
Pset_OutletTypeCommon - IsPluggableOutlet: yes
ePset_Simplebim - Assembly Level: Leaf
MagiCAD Pset_Device - System code: 574; User code: -WD; Length [mm]: 0 mm; Width [mm]: 0 mm; Height [mm]: 0 mm
ePset_LocationTool - Splitting: ORIGINAL
Group: Spredenett

# IfcFlowTerminal: Fire hydrant
In: Nivå F - 0,7 m
Type - Description: Fire hydrant
MagiCAD Pset_WaterDevices - Description: Fire hydrant; ProductCode: Fire hydrant; ConnectionSize_mm: 0 mm; qv_SizingFlow_ls: 0 m3/s; pTot_SizingFlow_Pa: 0 Pa; dpTot_SizingFlow_Pa: 0 Pa; User Code: FH1; Manufacturer: General
ePset_Simplebim - Assembly Level: Leaf
ePset_LocationTool - Splitting: ORIGINAL
Group: +TH=310.001

# IfcFlowTerminal: Gulvboks 400x400 (10)
In: Nivå F - 0,7 m
Type - Description: Gulvboks 400x400
Pset_ElectricalDeviceCommon - ElectricalDeviceNominalPower: 0 W; NumberOfPoles: 1; NominalVoltage: 0
ePset_Simplebim - Assembly Level: Leaf
MagiCAD Pset_Device - Length [mm]: 0 mm; Width [mm]: 0 mm; Height [mm]: 0 mm; Number of Poles: 1; Active Power: 0 W; Voltage: 0; Power Factor: 1; System code: 4115
ePset_LocationTool - Splitting: ORIGINAL
Group: Gulvboks

# IfcFlowTerminal: Høyttaler innfelt (4)
In: Nivå F - 0,7 m
Type - Description: Høyttaler innfelt
Classification: XS3.30 Not defined (NS3420); Group: PA-anlegg
MagiCAD Pset_Device - Length [mm]: 0 mm; Width [mm]: 0 mm; Height [mm]: 0 mm; National code: XS3.30; System code: 555; P1: -UH; Manufacturer: General
ePset_LocationTool - Splitting: ORIGINAL
ePset_Simplebim - Assembly Level: Leaf

# IfcFlowTerminal: IB1152 (6)
In: Nivå D + 1,2 m
Type - Description: Industrial luminaire IP 23, with special installation system which reduces installation time up to 50%
Pset_ElectricalDeviceCommon - NumberOfPoles: 1; ElectricalDeviceNominalPower: 54 W; NominalVoltage: 230
MagiCAD Pset_Device - System code: 442; Manufacturer: Glamox; Power Factor: 0.9; Length [mm]: 0 mm; Width [mm]: 0 mm; Height [mm]: 0 mm; Number of Poles: 1; Active Power: 54 W; Voltage: 230; User code: IB1152
ePset_Simplebim - Assembly Level: Leaf
Pset_LightFixtureTypeCommon - TotalWattage: 54 W
ePset_LocationTool - Splitting: ORIGINAL
Group: Belysningsutstyr

# IfcFlowTerminal: IB6102
In: Nivå D + 1,2 m
Type - Description: Powerful asymmetric uplighter
Pset_ElectricalDeviceCommon - NumberOfPoles: 1; NominalVoltage: 230; ElectricalDeviceNominalPower: 275 W
ePset_LocationTool - Splitting: ORIGINAL
MagiCAD Pset_Device - System code: 442; Circuit order no: 11; Manufacturer: Glamox; Switchboard: +TH=433.063; Length [mm]: 0 mm; Width [mm]: 0 mm; Height [mm]: 0 mm; Number of Poles: 1; Power Factor: 1; Voltage: 230; Active Power: 275 W; User code: IB6102; Product code: WE-EF FLA461-S 250W HIT FC2 EKSISTERENDE
ePset_Simplebim - Assembly Level: Leaf
Pset_LightFixtureTypeCommon - TotalWattage: 275 W
Group: Belysningsutstyr

# IfcFlowTerminal: IB7334 Zumtobel Puresign/Consign 150 ASI NDA (2)
In: Nivå F - 0,7 m
Type - Description: Markeringslys ensidig 30 meter leseavstand wire
Pset_ElectricalDeviceCommon - NumberOfPoles: 1; ElectricalDeviceNominalPower: 4.5 W; NominalVoltage: 230
ePset_LocationTool - Splitting: ORIGINAL
MagiCAD Pset_Device - User code: IB7334; System code: 443; Manufacturer: Zumtobel; Length [mm]: 0 mm; Width [mm]: 0 mm; Height [mm]: 0 mm; Number of Poles: 1; Circuit order no: 2; Power Factor: 1; Active Power: 4.5 W; Voltage: 230
ePset_Simplebim - Assembly Level: Leaf
Pset_LightFixtureTypeCommon - TotalWattage: 4.5 W
Group: Nødlys
Name | Switchboard
IB7334 Zumtobel Puresign/Consign 150 ASI NDA | +TH=443.232
IB7334 Zumtobel Puresign/Consign 150 ASI NDA | +TH=443.242

# IfcFlowTerminal: IB7405 Zumtobel Resclite C Antipanic ED NDA WH (3)
In: Nivå F
Type - Description: Ledelys innfelt i himling
Pset_ElectricalDeviceCommon - NumberOfPoles: 1; ElectricalDeviceNominalPower: 6 W; NominalVoltage: 230
Pset_LightFixtureTypeCommon - TotalWattage: 6 W
ePset_Simplebim - Assembly Level: Leaf
ePset_LocationTool - Splitting: ORIGINAL
MagiCAD Pset_Device - System code: 443; Product code: Resclite C Antipanic ED NDA WH; Manufacturer: Zumtobel; Length [mm]: 0 mm; Width [mm]: 0 mm; Height [mm]: 0 mm; Number of Poles: 1; Installation Code: 2; Circuit order no: 2; Power Factor: 1; Active Power: 6 W; Voltage: 230; User code: IB7405
Group: Nødlys
Name | Switchboard
2 x IB7405 Zumtobel Resclite C Antipanic ED NDA WH | +TH=443.232
IB7405 Zumtobel Resclite C Antipanic ED NDA WH | +TH=443.242

# IfcFlowTerminal: IB7414 Zumtobel Resclite C Spot AD NDA IP65 WH
In: Nivå D + 1,2 m
Type - Description: Ledelys Spot utenpåliggende IP65
Pset_ElectricalDeviceCommon - NumberOfPoles: 1; ElectricalDeviceNominalPower: 6 W; NominalVoltage: 230
ePset_LocationTool - Splitting: ORIGINAL
MagiCAD Pset_Device - Product code: Resclite C Spot AD NDA IP65 WH; System code: 443; Manufacturer: Zumtobel; User code: IB7414; Length [mm]: 0 mm; Width [mm]: 0 mm; Height [mm]: 0 mm; Number of Poles: 1; Power Factor: 1; Active Power: 6 W; Voltage: 230
Pset_LightFixtureTypeCommon - TotalWattage: 6 W
ePset_Simplebim - Assembly Level: Leaf
Group: Utstyr for nødlys

# IfcFlowTerminal: IB9510 (4)
In: Nivå F - 0,7 m
Type - Description: Powerful asymmetric uplighter
Pset_ElectricalDeviceCommon - NumberOfPoles: 1; NominalVoltage: 230; ElectricalDeviceNominalPower: 275 W
ePset_LocationTool - Splitting: ORIGINAL
MagiCAD Pset_Device - Product code: A52 1X400W GREY W/SEP BALLAST; System code: 442; Manufacturer: Glamox; User code: IB9510; Switchboard: +TH=433.065; Length [mm]: 0 mm; Width [mm]: 0 mm; Height [mm]: 0 mm; Number of Poles: 1; Circuit order no: 1; Power Factor: 1; Voltage: 230; Active Power: 275 W
ePset_Simplebim - Assembly Level: Leaf
Pset_LightFixtureTypeCommon - TotalWattage: 275 W
Group: Belysningsutstyr
Name | O1
IB9510 | A44
IB9510 | A43
IB9510 | A45
IB9510 | A46

# IfcFlowTerminal: Jordet-topolet-2-veis m_boks-i-gulv (10)
In: Nivå F - 0,7 m
Type - Description: Jordet topolet 2-veis m/boks GULV; PredefinedType: POWEROUTLET
Classification: WL1.2121 Not defined (NS3420); Group: Kursopplegg driftsteknisk
Pset_ElectricalDeviceCommon - ElectricalDeviceNominalPower: 0 W; NumberOfPoles: 1; NominalVoltage: 230
Pset_OutletTypeCommon - IsPluggableOutlet: yes
ePset_Simplebim - Assembly Level: Leaf
MagiCAD Pset_Device - Product code: Earthed recessed socket floor 2; National code: WL1.2121; Switchboard: +TH=433.065; Length [mm]: 0 mm; Width [mm]: 0 mm; Height [mm]: 0 mm; Number of Poles: 1; Active Power: 0 W; P1: -UE; Manufacturer: General; Power Factor: 1; Voltage: 230; System code: 461
ePset_LocationTool - Splitting: ORIGINAL
Name | Circuit order no
Jordet-topolet-2-veis m_boks-i-gulv | 53
Jordet-topolet-2-veis m_boks-i-gulv | 52
4 x Jordet-topolet-2-veis m_boks-i-gulv | 50
4 x Jordet-topolet-2-veis m_boks-i-gulv | 51

# IfcFlowTerminal: Jordet-topolet-2-veis m_boks-i-tak (17)
Type - Description: Jordet topolet 2-veis m/boks i tak; PredefinedType: POWEROUTLET
Classification: WL1.2121 Not defined (NS3420)
MagiCAD Pset_Device - National code: WL1.2121; Product code: Elko RS1091; IP_Code: IP20; User code: 02; Length [mm]: 0 mm; Width [mm]: 0 mm; Height [mm]: 0 mm; Number of Poles: 1; Active Power: 0 W; P1: -UE; Manufacturer: General; Power Factor: 1; Voltage: 230
Pset_ElectricalDeviceCommon - IP_Code: IP20; ElectricalDeviceNominalPower: 0 W; NumberOfPoles: 1; NominalVoltage: 230
Pset_OutletTypeCommon - IsPluggableOutlet: yes
ePset_Simplebim - Assembly Level: Leaf
ePset_LocationTool - Splitting: ORIGINAL
Name | In | System code | Installation Code | Group
10 x Jordet-topolet-2-veis m_boks-i-tak | Nivå D + 1,2 m | 441 | 3 | Kursopplegg belysningsutstyr
3 x Jordet-topolet-2-veis m_boks-i-tak | Nivå F - 0,7 m | 441 | 3 | Kursopplegg belysningsutstyr | MagiCAD Pset_Device - Switchboard: +TH=433.065; Circuit order no: 9
2 x Jordet-topolet-2-veis m_boks-i-tak | Nivå F - 0,7 m | 461 |  | Kursopplegg driftsteknisk | MagiCAD Pset_Device - Switchboard: +TH=433.075; Circuit order no: 54
2 x Jordet-topolet-2-veis m_boks-i-tak | Nivå F - 0,7 m | 441 |  | Kursopplegg belysningsutstyr | MagiCAD Pset_Device - Switchboard: +TH=433.065; Circuit order no: 7

# IfcFlowTerminal: Jordet-topolet-2-veis-Påvegg (VERT) (4)
Type - PredefinedType: POWEROUTLET
MagiCAD Pset_Device - Length [mm]: 0 mm; Width [mm]: 0 mm; Height [mm]: 0 mm; Number of Poles: 1; Active Power: 0 W; P1: -UE; Power Factor: 1; Voltage: 230; System code: 461
Pset_ElectricalDeviceCommon - ElectricalDeviceNominalPower: 0 W; NumberOfPoles: 1; NominalVoltage: 230
Pset_OutletTypeCommon - IsPluggableOutlet: yes
ePset_Simplebim - Assembly Level: Leaf
ePset_LocationTool - Splitting: ORIGINAL
Group: Kursopplegg driftsteknisk
Name | In | Circuit order no | Switchboard
3 x Jordet-topolet-2-veis-Påvegg (VERT) | Nivå F | 62 | +TH=433.065
Jordet-topolet-2-veis-Påvegg (VERT) | Nivå F - 0,7 m | 33 | +TH=433.055

# IfcFlowTerminal: Jordet-topolet-2-veis-m_boks (2)
In: Nivå F - 0,7 m
Type - Description: Jordet topolet 2-veis m/boks; PredefinedType: POWEROUTLET
Classification: WL1.2121 Not defined (NS3420)
Pset_ElectricalDeviceCommon - ElectricalDeviceNominalPower: 0 W; NumberOfPoles: 1; NominalVoltage: 230
Pset_OutletTypeCommon - IsPluggableOutlet: yes
ePset_LocationTool - Splitting: ORIGINAL
ePset_Simplebim - Assembly Level: Leaf
MagiCAD Pset_Device - National code: WL1.2121; Length [mm]: 0 mm; Width [mm]: 0 mm; Height [mm]: 0 mm; Number of Poles: 1; Active Power: 0 W; Power Factor: 0; P1: -UE; Manufacturer: General; Voltage: 230
Name | System code | Circuit order no | Switchboard | Group
Jordet-topolet-2-veis-m_boks | 441 | 32 | +TH=433.055 | Kursopplegg belysningsutstyr
Jordet-topolet-2-veis-m_boks | 461 | 84 | +TH=433.065 | Kursopplegg driftsteknisk

# IfcFlowTerminal: KSO-160
In: Nivå F - 0,7 m
Type - Description: Exhaust diffusor.
MagiCAD Pset_AirTerminal - Manufacturer: TROX Auranor; dpTot_SizingFlow_Pa: 0 Pa; qv_SizingFlow_ms: 0 m/s; ProductCode: KSO-160; qv_SizingFlow_ls: 55.556 m3/s; ConnectionSize_mm: 160; Description: Exhaust diffusor.
ePset_Simplebim - Assembly Level: Leaf
ePset_LocationTool - Splitting: ORIGINAL
Group: 36= Avtrekk 15

# IfcFlowTerminal: Koblingsboks tak-himling (3)
Type - Description: Jordet topolet 2-veis m/boks i tak; PredefinedType: POWEROUTLET
MagiCAD Pset_Device - User code: -QM; System code: 4332; Length [mm]: 0 mm; Width [mm]: 0 mm; Height [mm]: 0 mm; Number of Poles: 1; Active Power: 0 W; Manufacturer: General; Power Factor: 1; Voltage: 230
ePset_LocationTool - Splitting: ORIGINAL
Pset_ElectricalDeviceCommon - ElectricalDeviceNominalPower: 0 W; NumberOfPoles: 1; NominalVoltage: 230
Pset_OutletTypeCommon - IsPluggableOutlet: yes
ePset_Simplebim - Assembly Level: Leaf
Group: Kursopplegg for underfordelinger
Name | In | Switchboard | Circuit order no
Koblingsboks tak-himling | Nivå D + 1,2 m | MagiCAD Pset_Device - O1: KOBLINGSBOKS FOR: +TH=443.442-WC0601, -WD0601
Koblingsboks tak-himling | Nivå F - 0,7 m | +TH=433.065 | 1
Koblingsboks tak-himling | Nivå F - 0,7 m | +TH=433.065 | 10

# IfcFlowTerminal: Motorstyrt ventil (4)
In: Nivå D + 1,2 m
Type - Description: Motorstyrt ventil
Classification: XJ3.1 Not defined (NS3420); Group: KNX Ventilmotor
Pset_ElectricalDeviceCommon - ElectricalDeviceNominalPower: 0 W; NumberOfPoles: 1; NominalVoltage: 230
ePset_LocationTool - Splitting: ORIGINAL
ePset_Simplebim - Assembly Level: Leaf
MagiCAD Pset_Device - Product code: Other_E-Dummy-EE; User code: -XD; Length [mm]: 0 mm; Width [mm]: 0 mm; Height [mm]: 0 mm; Number of Poles: 1; Active Power: 0 W; Manufacturer: General; Power Factor: 1; Voltage: 230; System code: 5625; National code: XJ3.1

# IfcFlowTerminal: OTHER-EE-POWER-BALANCED-DUMMY (7)
In: Nivå F - 0,7 m
Type - Description: Fuktighetsføler
Description: Gulvboks 60x60; Group: Gulvboks
Pset_ElectricalDeviceCommon - ElectricalDeviceNominalPower: 0 W; NumberOfPoles: 1; NominalVoltage: 0
ePset_Simplebim - Assembly Level: Leaf
ePset_LocationTool - Splitting: ORIGINAL
MagiCAD Pset_Device - Length [mm]: 0 mm; Width [mm]: 0 mm; Height [mm]: 0 mm; Number of Poles: 1; Active Power: 0 W; Voltage: 0; Manufacturer: General; Power Factor: 1; System code: 4115

# IfcFlowTerminal: Orion-LOV-TA-250+Luna-200-250 (7)
In: Nivå F - 0,7 m
Type - Description: ATD for panneld ceiling
Classification: VE1.13332 Not defined (NS3420)
ePset_Simplebim - Assembly Level: Leaf
MagiCAD Pset_AirTerminal - ProductCode: Orion-LOV-TA-250+Luna-200-250; Description: ATD for panneld ceiling; User Code: AS012T; Manufacturer: TROX Auranor; dpTot_SizingFlow_Pa: 0 Pa; qv_SizingFlow_ms: 0 m/s; ConnectionSize_mm: 200; NationalCode: VE1.13332
ePset_LocationTool - Splitting: ORIGINAL
Name | qv_SizingFlow_ls (m3/s) | Group
5 x Orion-LOV-TA-250+Luna-200-250 | 69.444 | +TH=360.031 TL (1)
Orion-LOV-TA-250+Luna-200-250 | 69.444 | +TH=360.010 (12)
Orion-LOV-TA-250+Luna-200-250 | 83.333 | +TH=360.031 TL (1)

# IfcFlowTerminal: SP-15-K80-68DGR-STD-HIMLING (15)
In: Nivå F - 0,7 m
Type - Description: Spray, pendent installation, STD, K=80
ePset_Simplebim - Assembly Level: Leaf
ePset_LocationTool - Splitting: ORIGINAL
MagiCAD Pset_Sprinkler - Description: Spray, pendent installation, STD, K=80; Manufacturer: General; Nominal Release Temperature [°C]: 68; KFactor: 80
Name | Group
8 x SP-15-K80-68DGR-STD-HIMLING | +TH=332.003
SP-15-K80-68DGR-STD-HIMLING | 33= Våt Kopi 98
3 x SP-15-K80-68DGR-STD-HIMLING
SP-15-K80-68DGR-STD-HIMLING | 33= Våt Kopi 36
SP-15-K80-68DGR-STD-HIMLING | 33= Våt Kopi 37
SP-15-K80-68DGR-STD-HIMLING | 33= Våt Kopi 39

# IfcFlowTerminal: SP-15-K80-68DGR-STD-NEDOVER (9)
In: Nivå D + 1,2 m
Type - Description: Spray, pendent installation, STD, K=80
ePset_LocationTool - Splitting: ORIGINAL
ePset_Simplebim - Assembly Level: Leaf
MagiCAD Pset_Sprinkler - Description: Spray, pendent installation, STD, K=80; Manufacturer: General; Nominal Release Temperature [°C]: 68; KFactor: 80
Name | Group
8 x SP-15-K80-68DGR-STD-NEDOVER | 33= Våt Kopi 163
SP-15-K80-68DGR-STD-NEDOVER

# IfcFlowTerminal: SP-15-K80-68DGR-STD-STÅENDE (14)
In: Nivå F - 0,7 m
Type - Description: Spray, pendent installation, STD, K=80
ePset_Simplebim - Assembly Level: Leaf
ePset_LocationTool - Splitting: ORIGINAL
MagiCAD Pset_Sprinkler - Description: Spray, pendent installation, STD, K=80; Manufacturer: General; Nominal Release Temperature [°C]: 68; KFactor: 80
Name | Group
8 x SP-15-K80-68DGR-STD-STÅENDE | +TH=332.003
3 x SP-15-K80-68DGR-STD-STÅENDE
SP-15-K80-68DGR-STD-STÅENDE | 33= Våt Kopi 36
SP-15-K80-68DGR-STD-STÅENDE | 33= Våt Kopi 37
SP-15-K80-68DGR-STD-STÅENDE | 33= Våt Kopi 39

# IfcFlowTerminal: Sluk 75 plast
In: Nivå G - 2,0m
Type - Description: Sluk 75 plast
ePset_LocationTool - Splitting: ORIGINAL
MagiCAD Pset_DrainageDevices - Description: Sluk 75 plast; Product Code: Sluk 75 plast; NationalCode: UT5.101041; User Code: KN01T; ConnectionSize_mm: 0 mm
ePset_Simplebim - Assembly Level: Leaf
Group: 31= SPV Kopi 132

# IfcFlowTerminal: XW-15-K80-68DGR-QR (4)
In: Nivå F - 0,7 m
Type - Description: Extended coverage sprinkler, sidewall horizontal installation, QR, K=80
ePset_Simplebim - Assembly Level: Leaf
ePset_LocationTool - Splitting: ORIGINAL
MagiCAD Pset_Sprinkler - Product code: XW-15-K80-68DGR-QR; Description: Extended coverage sprinkler, sidewall horizontal installation, QR, K=80; User Code: Sidewall; Manufacturer: General; Nominal Release Temperature [°C]: 68; KFactor: 80
Group: +TH=332.003

# IfcFlowTreatmentDevice: LKR-160-600
In: Nivå F - 0,7 m
Type - Description: Circular sound attenuator.; PredefinedType: ROUND
ePset_LocationTool - Splitting: ORIGINAL
ePset_Simplebim - Assembly Level: Leaf
MagiCAD Pset_Silencer - ProductCode: LKR-160-600; User Code: LKR-600; Manufacturer: TROX Auranor; Description: Circular sound attenuator.; qv_SizingFlow_ls: 0 m3/s; pTot_SizingFlow_Pa: 0 Pa; dpTot_SizingFlow_Pa: 0 Pa
Group: 36= Avtrekk 15

# IfcFlowTreatmentDevice: LKR-315-1200
In: Nivå F - 0,7 m
Type - Description: Circular sound attenuator.; PredefinedType: ROUND
Classification: VB2.143122 Not defined (NS3420); Group: +TH=360.031 TL (1)
ePset_LocationTool - Splitting: ORIGINAL
MagiCAD Pset_Silencer - Manufacturer: TROX Auranor; User Code: QL07T; Description: Circular sound attenuator.; qv_SizingFlow_ls: 0 m3/s; pTot_SizingFlow_Pa: 0 Pa; dpTot_SizingFlow_Pa: 0 Pa; NationalCode: VB2.143122; ProductCode: LKR-315-1200
ePset_Simplebim - Assembly Level: Leaf

# IfcFlowTreatmentDevice: LKR-400-900
In: Nivå F - 0,7 m
Type - Description: Circular sound attenuator.; PredefinedType: ROUND
Classification: VB2.143122 Not defined (NS3420); Group: +TH=360.031 TL (1)
MagiCAD Pset_Silencer - ProductCode: LKR-400-900; Manufacturer: TROX Auranor; Description: Circular sound attenuator.; qv_SizingFlow_ls: 0 m3/s; pTot_SizingFlow_Pa: 0 Pa; dpTot_SizingFlow_Pa: 0 Pa; NationalCode: VB2.143122; User Code: QL06T
ePset_Simplebim - Assembly Level: Leaf
ePset_LocationTool - Splitting: ORIGINAL

# IfcFurnishingElement: V278 - brannskap1:V278 - Brannskap - 800 x 800 x 160 mm, V278 - brannskap1:V278 - Brannskap - 800 x 800 x 160 mm:36717381
In: Nivå F - 0,7 m
Type - Material: <Unnamed>
Pset_QuantityTakeOff - Reference: V278 - Brannskap - 800 x 800 x 160 mm
AVINOR - 07_Fase: F90; 03_Ansvar: FDV; 08_Status: S2; 06_Omrade: TH; 01_Lufthavnkode: ENGM
ePset_Simplebim - Assembly Level: Leaf
ePset_LocationTool - Splitting: ORIGINAL

# IfcMember: L Corner Mullion:A233 - Sprosse - 20 x 100 mm (36)
In: Nivå F - 0,7 m
Type - PredefinedType: MULLION; Material: Metal - Steel
ePset_LocationTool - Splitting: ORIGINAL
Pset_MemberCommon - Reference: A233 - Sprosse - 20 x 100 mm; IsExternal: no
Pset_QuantityTakeOff - Reference: A233 - Sprosse - 20 x 100 mm
AVINOR - 07_Fase: F90; 08_Status: S1; 03_Ansvar: FDV; 06_Omrade: TH; 01_Lufthavnkode: ENGM
ePset_Simplebim - Assembly Level: Leaf
ePset_SimplebimBasicQuantities - Width (Simplebim): 110 mm; Length (Simplebim): 110 mm
Name (L Corner Mullion:A233 - Sprosse - 20 x 100 mm:...) | Span (mm) = Height (Simplebim) (mm) | Volume, net (Simplebim) (m3) | Weight, as steel (Simplebim) (kg) | Area, sides, net (Simplebim) (m2)
37418746 | 1105 | 0.00442 | 34.697 | 0.4942
37418747 | 45 | 0.00018 | 1.413 | 0.0278
37418749 | 150 | 0.0006 | 4.71 | 0.074
37418760 | 1100 | 0.0044 | 34.54 | 0.492
37418816 | 45 | 0.00018 | 1.413 | 0.0278
37418825 | 55 | 0.00022 | 1.727 | 0.0322
37418832 | 45 | 0.00018 | 1.413 | 0.0278
37418840 | 55 | 0.00022 | 1.727 | 0.0322
37418848 | 45 | 0.00018 | 1.413 | 0.0278
37418856 | 55 | 0.00022 | 1.727 | 0.0322
37418865 | 55 | 0.00022 | 1.727 | 0.0322
37418872 | 55 | 0.00022 | 1.727 | 0.0322
37418880 | 45 | 0.00018 | 1.413 | 0.0278
37418888 | 55 | 0.00022 | 1.727 | 0.0322
37418896 | 45 | 0.00018 | 1.413 | 0.0278
37418905 | 45 | 0.00018 | 1.413 | 0.0278
37418912 | 55 | 0.00022 | 1.727 | 0.0322
37418920 | 45 | 0.00018 | 1.413 | 0.0278
37418928 | 55 | 0.00022 | 1.727 | 0.0322
37418936 | 45 | 0.00018 | 1.413 | 0.0278
37418944 | 55 | 0.00022 | 1.727 | 0.0322
37418952 | 45 | 0.00018 | 1.413 | 0.0278
37418960 | 55 | 0.00022 | 1.727 | 0.0322
37418968 | 55 | 0.00022 | 1.727 | 0.0322
37418976 | 55 | 0.00022 | 1.727 | 0.0322
37418985 | 45 | 0.00018 | 1.413 | 0.0278
37418993 | 45 | 0.00018 | 1.413 | 0.0278
37419000 | 45 | 0.00018 | 1.413 | 0.0278
37419008 | 45 | 0.00018 | 1.413 | 0.0278
37419017 | 55 | 0.00022 | 1.727 | 0.0322
37419086 | 750 | 0.003 | 23.55 | 0.338
37419087 | 750 | 0.003 | 23.55 | 0.338
37419088 | 750 | 0.003 | 23.55 | 0.338
37419089 | 750 | 0.003 | 23.55 | 0.338
37419090 | 600 | 0.0024 | 18.84 | 0.272
37419091 | 150 | 0.0006 | 4.71 | 0.074

# IfcMember: PL30*300, STÅLBJELKE
In: D
Description: PL30*300; Material: STEEL/S355
ePset_LocationTool - Splitting: ORIGINAL
Tekla Status - Status: Unknown; Assigned By: Me; Actual: 1; Scheduled: 0; Erection Comment: Missing Value
AVINOR - 10_Objektstatus: 0_Nytt/ New; 08_Status: S4; 07_Fase: F90; 04_Kontrakt: 182251; 06_Omrade: TH; 05_ID-nummer: +TH=223.013; 02_Prosjekt: A146091-1; 03_Ansvar: 181605; 09_Arbeidspakke: AP01; 01_Lufthavnkode: ENGM
Tekla Reinforcement - MATERIAL: S355; WEIGHT: 31.8754 kg; NAME: STÅLBJELKE; AREA_NET: 0.31708 m2; NUMBER: 1; ID: 394953950; PREFIX: DSB; LENGTH: 462.214 mm
ePset_Simplebim - Assembly Level: Leaf
Tekla Quantity - VOLUME_NET: 0.00405 m3; WEIGTH_NET: 31.8754 kg; VOLUME_GROSS: 0.00406 m3; AREA_NET: 0.31708 m2; AREA_GROSS: 0.31708 m2; Width: 30 mm; Heigth: 300 mm; WEIGTH_GROSS: 32.6554 kg; Length: 462.214 mm
Tekla Common - Grade: S355; Name: STÅLBJELKE; Top elevation: +209.774; Part mark: DSB-0(?); Assembly mark: SB-0(?); Profile: PL30*300; Class: 330; Bottom elevation: +209.540
ePset_SimplebimBasicQuantities - Volume, net (Simplebim): 0.00406055 m3; Weight, as steel (Simplebim): 31.8753 kg; Area, sides, net (Simplebim): 0.317084 m2; Height (Simplebim): 30 mm; Width (Simplebim): 300 mm; Length (Simplebim): 462.214 mm
Pset_MemberCommon - LoadBearing: no; Reference: DSB-0(?)

# IfcMember: PL5*80 (2)
In: F
Description: PL5*80; Material: STEEL/AISI304
Pset_MemberCommon - LoadBearing: no; Reference: DSSP-7688
Tekla Quantity - WEIGTH_GROSS: 0.1884 kg; WEIGTH_NET: 0.1884 kg; VOLUME_NET: 0.00002 m3; VOLUME_GROSS: 0.00002 m3; AREA_NET: 0.011 m2; AREA_GROSS: 0.011 m2; Width: 5 mm; Length: 60 mm; Heigth: 80 mm
Tekla Common - Profile: PL5*80; Top elevation: +213.725; Class: 380; Grade: AISI304; Assembly mark: SSP-691; Bottom elevation: +213.665; Part mark: DSSP-7688; Name: STÅLSPESIAL
Tekla Reinforcement - WEIGHT: 0.1884 kg; NUMBER: 1; MATERIAL: AISI304; AREA_NET: 0.011 m2; LENGTH: 60 mm; NAME: STÅLSPESIAL; PREFIX: DSSP
Tekla Status - Status: Unknown; Assigned By: Me; Actual: 1; Scheduled: 0; Erection Comment: Missing Value
ePset_LocationTool - Splitting: ORIGINAL
AVINOR - 10_Objektstatus: 0_Nytt/ New; 08_Status: S4; 07_Fase: F90; 04_Kontrakt: 182251; 06_Omrade: TH; 05_ID-nummer: +TH=223.017; 02_Prosjekt: A146091-1; 03_Ansvar: 181605; 09_Arbeidspakke: AP01; 01_Lufthavnkode: ENGM
ePset_Simplebim - Assembly Level: Leaf
ePset_SimplebimBasicQuantities - Weight, as steel (Simplebim): 0.1884 kg; Area, sides, net (Simplebim): 0.011 m2; Width (Simplebim): 5 mm; Height (Simplebim): 60 mm; Length (Simplebim): 80 mm; Volume, net (Simplebim): 0.000024 m3
Name | ID
STÅLSPESIAL | 394961610
STÅLSPESIAL | 394961335

# IfcMember: Rectangular Mullion:A233 - Sprosse - 165(post)+70(dekkprofil) x 50 mm (7)
In: Nivå G
Type - PredefinedType: MULLION; Material: T2_Metal_Aluminium
Pset_MemberCommon - IsExternal: yes; Reference: A233 - Sprosse - 165(post)+70(dekkprofil) x 50 mm
ePset_SimplebimBasicQuantities - Area, sides, net (Simplebim): 0.2629 m2; Volume, net (Simplebim): 0.004935 m3; Width (Simplebim): 50 mm; Length (Simplebim): 235 mm; Height (Simplebim): 420 mm
ePset_LocationTool - Splitting: RESULT
AVINOR - 07_Fase: F90; 03_Ansvar: FDV; 08_Status: S2; 06_Omrade: TH; 01_Lufthavnkode: ENGM
ePset_Simplebim - Assembly Level: Leaf
Pset_QuantityTakeOff - Reference: A233 - Sprosse - 165(post)+70(dekkprofil) x 50 mm
Name (Rectangular Mullion:A233 - Sprosse - 165(post)+70(dekkprofil) x 50 mm:...) | Weight, as steel (Simplebim) (kg)
37344746 | 38.7398
37344816 | 38.7398
37344817 | 38.7398
37344848 | 38.7397
37344869 | 38.7398
37344945 | 38.7398
37344976 | 38.7397

# IfcMember: Rectangular Mullion:A233 - Sprosse 50 mm - 100(post)+40(dekkprofil) (11)
In: Nivå G - 2,0 m
Type - PredefinedType: MULLION; Material: T2_Metal_Aluminium
Pset_MemberCommon - Reference: A233 - Sprosse 50 mm - 100(post)+40(dekkprofil); IsExternal: no
Pset_QuantityTakeOff - Reference: A233 - Sprosse 50 mm - 100(post)+40(dekkprofil)
AVINOR - 08_Status: S4; 07_Fase: F90; 06_Omrade: TH; 03_Ansvar: 182410; 01_Lufthavnkode: ENGM
ePset_Simplebim - Assembly Level: Leaf
ePset_SimplebimBasicQuantities - Width (Simplebim): 140 mm; Height (Simplebim): 50 mm
Name (Rectangular Mullion:A233 - Sprosse 50 mm - 100(post)+40(dekkprofil):...) | Span (mm) | Volume, net (Simplebim) (m3) | Area, sides, net (Simplebim) (m2) | Length (Simplebim) (mm) | Weight, as steel (Simplebim) (kg) | Splitting
45767289 | 1450 | 0.01015 | 0.565 | 1450 | 79.6775 | ORIGINAL
45767290 | 1450 | 0.01015 | 0.565 | 1450 | 79.6775 | ORIGINAL
45767292 | 1450 | 0.01015 | 0.565 | 1450 | 79.6775 | ORIGINAL
45767293 | 1450 | 0.01015 | 0.565 | 1450 | 79.6775 | ORIGINAL
45767294 | 1450 | 0.01015 | 0.565 | 1450 | 79.6775 | ORIGINAL
45767338 | 1450 | 0.01015 | 0.565 | 1450 | 79.6775 | ORIGINAL
45767339 | 1450 | 0.01015 | 0.565 | 1450 | 79.6775 | ORIGINAL
45767340 | 1450 | 0.01015 | 0.565 | 1450 | 79.6775 | ORIGINAL
45767341 | 1450 | 0.01015 | 0.565 | 1450 | 79.6775 | ORIGINAL
45767342 | 1450 | 0.01015 | 0.565 | 1450 | 79.6775 | ORIGINAL
45767291 |  | 0.00269877 | 0.160505 | 386 | 21.1854 | RESULT

# IfcMember: Rectangular Mullion:A233 - Sprosse 50 mm - 150(post)+50(dekkprofil) utgår (13)
In: Nivå D + 1,2 m
Type - PredefinedType: MULLION; Material: T2_Metal_Aluminium
Pset_QuantityTakeOff - Reference: A233 - Sprosse 50 mm - 150(post)+50(dekkprofil) utgår
ePset_LocationTool - Splitting: ORIGINAL
AVINOR - 07_Fase: F90; 06_Omrade: TH; 01_Lufthavnkode: ENGM
ePset_Simplebim - Assembly Level: Leaf
Pset_MemberCommon - IsExternal: no; Reference: A233 - Sprosse 50 mm - 150(post)+50(dekkprofil) utgår
Name (Rectangular Mullion:A233 - Sprosse 50 mm - 150(post)+50(dekkprofil) utgår:...) | Area, sides, net (Simplebim) (m2) | Weight, as steel (Simplebim) (kg) | Volume, net (Simplebim) (m3) | Width (Simplebim) (mm) | Length (Simplebim) (mm) | Height (Simplebim) (mm) | 08_Status | 03_Ansvar | Span (mm) | Group
6817495 | 1.15774 | 178.625 | 0.0227547 | 50 | 200 | 2275.47 | S1 | FDV | 2275
6817501 | 1.14494 | 176.616 | 0.0224988 | 200 | 2249.88 | 50 | S1 | FDV | 2249.88
6817506 | 0.0325 | 1.9625 | 0.00025 | 25 | 200 | 50 | S1 | FDV | 25
45658211 | 0.1525 | 20.8025 | 0.00265 | 200 | 265 | 50 | S4 | 182410 | 265 | Model Group:TH - Karnapper (members excluded):45660468
45658757 | 0.2025 | 28.6525 | 0.00365 | 50 | 200 | 365 | S4 | 182410 | 365 | Model Group:TH - Karnapper (members excluded):45660468
45658762 | 0.76 | 116.18 | 0.0148 | 200 | 1480 | 50 | S4 | 182410 | 1480 | Model Group:TH - Karnapper (members excluded):45660468
45658764 | 0.1775 | 24.7275 | 0.00315 | 50 | 200 | 315 | S4 | 182410 | 315 | Model Group:TH - Karnapper (members excluded):45660468
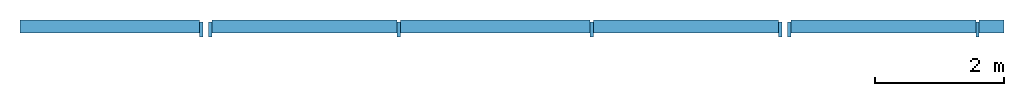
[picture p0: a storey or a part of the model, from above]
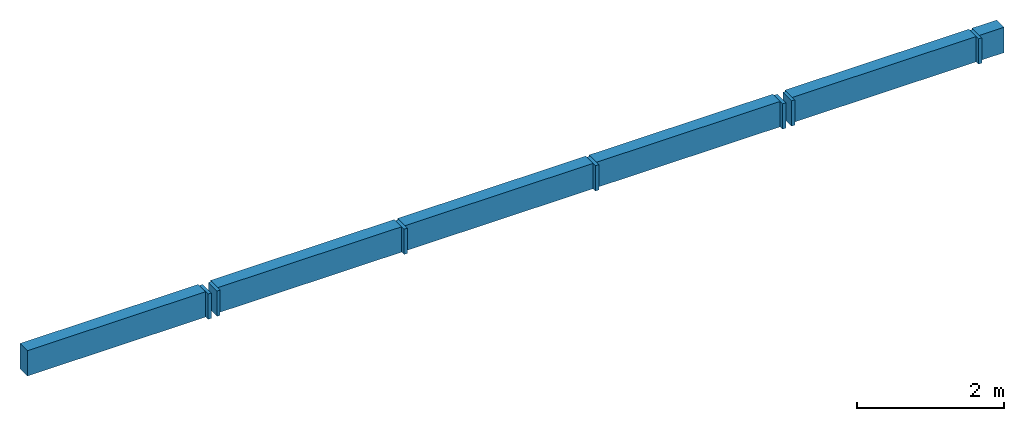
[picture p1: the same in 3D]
Properties of the parts of a building model (IFC2X3), part 6 of 7

# IfcMember: Rectangular Mullion:A233 - Sprosse 50 mm - 150(post)+50(dekkprofil) utgår (13)
Name (Rectangular Mullion:A233 - Sprosse 50 mm - 150(post)+50(dekkprofil) utgår:...) | Area, sides, net (Simplebim) (m2) | Weight, as steel (Simplebim) (kg) | Volume, net (Simplebim) (m3) | Width (Simplebim) (mm) | Length (Simplebim) (mm) | Height (Simplebim) (mm) | 08_Status | 03_Ansvar | Span (mm) | Group
45658769 | 0.235 | 33.755 | 0.0043 | 200 | 430 | 50 | S4 | 182410 | 430 | Model Group:TH - Karnapper (members excluded):45660468
45658771 | 0.1775 | 24.7275 | 0.00315 | 50 | 200 | 315 | S4 | 182410 | 315 | Model Group:TH - Karnapper (members excluded):45660468
45658226 | 0.6275 | 95.3775 | 0.01215 | 200 | 1215 | 50 | S4 | 182410 | 1215 | Model Group:TH - Karnapper (members excluded):45660468
45658228 | 0.19 | 26.69 | 0.0034 | 50 | 200 | 340 | S4 | 182410 | 340 | Model Group:TH - Karnapper (members excluded):45660468
45658774 | 0.2425 | 34.9325 | 0.00445 | 200 | 445 | 50 | S4 | 182410 | 445 | Model Group:TH - Karnapper (members excluded):45660468
45658781 | 0.1775 | 24.7275 | 0.00315 | 50 | 200 | 315 | S4 | 182410 | 315 | Model Group:TH - Karnapper (members excluded):45660468

# IfcOpeningElement: Opening (22)
Name | In | Group
B222 - HUP7:B222 - HUP 100x50x5:47060762:1 | Nivå F - 0,7 m | Model Group:A184862 - Kiosk NSOPØ 05.235 2 (members excluded):47061109
B222 - HUP7:B222 - HUP 100x50x5:47060762:1 | Nivå F | Model Group:A184862 - Kiosk NSOPØ 05.235 2 (members excluded):47061109
B222 - HUP7:B222 - HUP 100x50x5:47060785:1 | Nivå F - 0,7 m | Model Group:A184862 - Kiosk NSOPØ 05.235 2 (members excluded):47061109
B222 - HUP7:B222 - HUP 100x50x5:47060785:1 | Nivå F | Model Group:A184862 - Kiosk NSOPØ 05.235 2 (members excluded):47061109
B222 - HUP7:B222 - HUP 100x50x5:47061047:1 | Nivå F - 0,7 m | Model Group:A184862 - Kiosk NSOPØ 05.235 2 (members excluded):47061109
B222 - HUP7:B222 - HUP 100x50x5:47061047:1 | Nivå F | Model Group:A184862 - Kiosk NSOPØ 05.235 2 (members excluded):47061109
B222 - HUP7:B222 - HUP 100x50x5:47061049:1 | Nivå F - 0,7 m | Model Group:A184862 - Kiosk NSOPØ 05.235 2 (members excluded):47061109
B222 - HUP7:B222 - HUP 100x50x5:47061049:1 | Nivå F | Model Group:A184862 - Kiosk NSOPØ 05.235 2 (members excluded):47061109
B222 - HUP7:B222 - HUP 100x50x5:47061056:1 | Nivå F - 0,7 m | Model Group:A184862 - Kiosk NSOPØ 05.235 2 (members excluded):47061109
B222 - HUP7:B222 - HUP 100x50x5:47061056:1 | Nivå F | Model Group:A184862 - Kiosk NSOPØ 05.235 2 (members excluded):47061109
B222 - HUP7:B222 - HUP 100x50x5:47061058:1 | Nivå F - 0,7 m | Model Group:A184862 - Kiosk NSOPØ 05.235 2 (members excluded):47061109
B222 - HUP7:B222 - HUP 100x50x5:47061058:1 | Nivå F | Model Group:A184862 - Kiosk NSOPØ 05.235 2 (members excluded):47061109
B222 - HUP7:B222 - HUP 100x50x5:47061065:1 | Nivå F - 0,7 m | Model Group:A184862 - Kiosk NSOPØ 05.235 2 (members excluded):47061109
B222 - HUP7:B222 - HUP 100x50x5:47061065:1 | Nivå F | Model Group:A184862 - Kiosk NSOPØ 05.235 2 (members excluded):47061109
B222 - HUP7:B222 - HUP 100x50x5:47061067:1 | Nivå F - 0,7 m | Model Group:A184862 - Kiosk NSOPØ 05.235 2 (members excluded):47061109
B222 - HUP7:B222 - HUP 100x50x5:47061067:1 | Nivå F | Model Group:A184862 - Kiosk NSOPØ 05.235 2 (members excluded):47061109
A20 - Slagdør - Enkel:A243 - DI_LTO - 0790 x 2240 mm:2640284:1 | Nivå F - 0,7 m
A20 - Slagdør - Enkel2:A243 - DI_LTO - 1090 x 2090 mm:47060831:1 | Nivå F - 0,7 m
2 x Floor:A245 - Metalplate 5mm:47057754 | Nivå F - 0,7 m | Model Group:A184862 - Kiosk NSOPØ 05.235 2 (members excluded):47061109
Basic Wall:A241 - FSVF-100 (100/100 ps-p):2640279 | Nivå F
Basic Wall:A241 - SXVXS-75:47060828 | Nivå F

# IfcPlate: Basic Wall:A231 - Yttervegg - Tettfelt Systemvindu (2)
In: Nivå D + 1,2 m
Type - PredefinedType: CURTAIN_PANEL; Material: Metal - Preget plate 5 mm, T2_Tre Finerplate 15 mm, _NSW Isolasjon trykkfast 150 mm, T2_Tre Finerplate 15 mm, Metal - Preget plate 5 mm
Pset_QuantityTakeOff - Reference: A231 - Yttervegg - Tettfelt Systemvindu
Pset_PlateCommon - Reference: A231 - Yttervegg - Tettfelt Systemvindu; IsExternal: yes; LoadBearing: no
ePset_LocationTool - Splitting: ORIGINAL
AVINOR - 08_Status: S4; 07_Fase: F90; 06_Omrade: TH; 03_Ansvar: 182410; 01_Lufthavnkode: ENGM
ePset_Simplebim - Assembly Level: Leaf
Group: Model Group:TH - Karnapper (members excluded):45660468
Name (Basic Wall:A231 - Yttervegg - Tettfelt Systemvindu:...) | Volume, net (Simplebim) (m3) | Weight, as steel (Simplebim) (kg) | Area, largest surface, net (Simplebim) (m2)
45658765 | 0.022743 | 178.533 | 0.1197
45658782 | 0.0221445 | 173.834 | 0.11655

# IfcPlate: Basic Wall:A234 - Blindfelt (eksisterende pir) (6)
In: Nivå G
Type - PredefinedType: CURTAIN_PANEL; Material: _NSW Aluminium 10 mm, _NSW Luftspalte 25 mm, _NSW Luftspalte 45 mm, _NSW Isolasjon 115 mm, _NSW Aluminium 5 mm
AVINOR - 01_Lufthavnkode: ENGM
Pset_QuantityTakeOff - Reference: A234 - Blindfelt (eksisterende pir)
Pset_PlateCommon - IsExternal: yes; LoadBearing: no; Reference: A234 - Blindfelt (eksisterende pir)
ePset_LocationTool - Splitting: RESULT
ePset_Simplebim - Assembly Level: Leaf
Name (Basic Wall:A234 - Blindfelt (eksisterende pir):...) | Volume, net (Simplebim) (m3) | Area, largest surface, net (Simplebim) (m2) | Weight, as steel (Simplebim) (kg)
45814962 | 0.234643 | 1.17321 | 1841.95
45814964 | 0.24192 | 1.2096 | 1899.07
45814966 | 0.2478 | 1.239 | 1945.23
45814965 | 0.24192 | 1.2096 | 1899.07
45814967 | 0.24192 | 1.2096 | 1899.07
45814969 | 0.032366 | 0.16183 | 254.073

# IfcPlate: Empty System Panel:A234 - Empty System Panel (16)
In: Nivå F - 0,7 m
Type - PredefinedType: CURTAIN_PANEL; Material: _NSW Luftspalte
Pset_PlateCommon - Reference: A234 - Empty System Panel; IsExternal: no
AVINOR - 07_Fase: F90; 03_Ansvar: FDV; 08_Status: S2; 06_Omrade: TH; 01_Lufthavnkode: ENGM
ePset_Simplebim - Assembly Level: Leaf
Pset_QuantityTakeOff - Reference: A234 - Empty System Panel
Name (Empty System Panel:A234 - Empty System Panel:...) | Weight, as steel (Simplebim) (kg) | Area, largest surface, net (Simplebim) (m2) | Volume, net (Simplebim) (m3) | Splitting
37419061 | 14.3066 | 1.8225 | 0.0018225 | ORIGINAL
37418676 | 3.26989 | 0.416547 | 0.000416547 | RESULT
37418734 | 0.804748 | 0.12302 | 0.000102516 | RESULT
37418963 | 0.343745 | 0.0437892 | 0.0000437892 | RESULT
37418971 | 0.343745 | 0.0437892 | 0.0000437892 | RESULT
37419011 | 0.343745 | 0.0437892 | 0.0000437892 | RESULT
37418859 | 0.343745 | 0.0437892 | 0.0000437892 | RESULT
37418835 | 0.343745 | 0.0437892 | 0.0000437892 | RESULT
37418851 | 0.343745 | 0.0437892 | 0.0000437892 | RESULT
37418867 | 0.343745 | 0.0437892 | 0.0000437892 | RESULT
37418883 | 0.343745 | 0.0437892 | 0.0000437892 | RESULT
37418907 | 0.343745 | 0.0437892 | 0.0000437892 | RESULT
37418923 | 0.343745 | 0.0437892 | 0.0000437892 | RESULT
37418939 | 0.343745 | 0.0437892 | 0.0000437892 | RESULT
37418955 | 0.343745 | 0.0437892 | 0.0000437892 | RESULT
37418819 | 0.343745 | 0.0437892 | 0.0000437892 | RESULT

# IfcPlate: PL10*120 (6)
In: F
Description: PL10*120; Material: STEEL/S355
Tekla Quantity - AREA_GROSS: 0.01644 m2; AREA_NET: 0.03802 m2; VOLUME_GROSS: 0.00015 m3; VOLUME_NET: 0.00015 m3; Width: 10 mm; Heigth: 120 mm; Length: 137 mm; WEIGTH_GROSS: 1.29054 kg; WEIGTH_NET: 1.29054 kg
Tekla Status - Status: Unknown; Assigned By: Me; Actual: 1; Scheduled: 0; Erection Comment: Missing Value
ePset_SimplebimBasicQuantities - Area, largest surface, net (Simplebim): 0.01644 m2; Volume, net (Simplebim): 0.0001644 m3; Weight, as steel (Simplebim): 1.29054 kg
AVINOR - 10_Objektstatus: 0_Nytt/ New; 08_Status: S4; 07_Fase: F90; 04_Kontrakt: 182251; 06_Omrade: TH; 05_ID-nummer: +TH=223.017; 02_Prosjekt: A146091-1; 03_Ansvar: 181605; 09_Arbeidspakke: AP01; 01_Lufthavnkode: ENGM
ePset_Simplebim - Assembly Level: Leaf
Pset_PlateCommon - Reference: DSSP-7697; LoadBearing: no
Tekla Common - Grade: S355; Bottom elevation: +213.560; Part mark: DSSP-7697; Class: 380; Assembly mark: SSP-693; Profile: PL10*120; Top elevation: +213.680; Name: STÅLSPESIAL
ePset_LocationTool - Splitting: ORIGINAL

# IfcPlate: PL12*140 (38)
Description: PL12*140; Material: STEEL/S355
ePset_LocationTool - Splitting: ORIGINAL
Tekla Status - Status: Unknown; Assigned By: Me; Actual: 1; Scheduled: 0; Erection Comment: Missing Value
AVINOR - 10_Objektstatus: 0_Nytt/ New; 08_Status: S4; 07_Fase: F90; 04_Kontrakt: 182251; 06_Omrade: TH; 02_Prosjekt: A146091-1; 03_Ansvar: 181605; 09_Arbeidspakke: AP01; 01_Lufthavnkode: ENGM
ePset_Simplebim - Assembly Level: Leaf
Pset_PlateCommon - LoadBearing: no; Reference: DSB-0(?)
Tekla Quantity - Width: 12 mm; Heigth: 140 mm
Tekla Common - Grade: S355; Name: STÅLBJELKE; Part mark: DSB-0(?); Assembly mark: SB-0(?); Class: 330; Profile: PL12*140
Name | In | Area, largest surface, net (Simplebim) (m2) | Weight, as steel (Simplebim) (kg) = WEIGTH_NET (kg) | Volume, net (Simplebim) (m3) | 05_ID-nummer | VOLUME_NET (m3) = VOLUME_GROSS (m3) | AREA_NET (m2) | AREA_GROSS (m2) | Length (mm) | WEIGTH_GROSS (kg) | Top elevation | Bottom elevation
6 x STÅLBJELKE | D | 0.04155 | 3.91401 | 0.0004986 | +TH=223.009 | 0.00049 | 0.09345 | 0.042 | 300 | 3.9564 | +210.009 | +209.709
12 x STÅLBJELKE | D | 0.035671 | 3.36021 | 0.000428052 | +TH=223.013 | 0.00043 | 0.08056 | 0.0364 | 260 | 3.42888 | +210.020 | +209.760
12 x STÅLBJELKE | F | 0.035671 | 3.36021 | 0.000428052 | +TH=223.017 | 0.00043 | 0.08056 | 0.0364 | 260 | 3.42888 | +213.400 | +213.140
4 x STÅLBJELKE | D | 0.04972 | 4.68362 | 0.00059664 | +TH=223.013 | 0.0006 | 0.11111 | 0.05012 | 358 | 4.7213 | +209.969 | +209.611
4 x STÅLBJELKE | D | 0.04986 | 4.69681 | 0.00059832 | +TH=223.013 | 0.0006 | 0.11141 | 0.05026 | 359 | 4.73449 | +209.970 | +209.611

# IfcPlate: PL15*140 (6)
In: D
Description: PL15*140; Material: STEEL/S355
Tekla Status - Status: Unknown; Assigned By: Me; Actual: 1; Scheduled: 0; Erection Comment: Missing Value
AVINOR - 10_Objektstatus: 0_Nytt/ New; 08_Status: S4; 07_Fase: F90; 04_Kontrakt: 182251; 06_Omrade: TH; 05_ID-nummer: +TH=223.013; 02_Prosjekt: A146091-1; 03_Ansvar: 181605; 09_Arbeidspakke: AP01; 01_Lufthavnkode: ENGM
ePset_Simplebim - Assembly Level: Leaf
Tekla Quantity - Width: 15 mm; Heigth: 140 mm
Pset_PlateCommon - LoadBearing: no; Reference: DSB-0(?)
Tekla Common - Profile: PL15*140; Grade: S355; Name: STÅLBJELKE; Part mark: DSB-0(?); Assembly mark: SB-0(?); Class: 330
ePset_LocationTool - Splitting: ORIGINAL
Name | WEIGTH_NET (kg) | AREA_GROSS (m2) | AREA_NET (m2) | WEIGTH_GROSS (kg) | VOLUME_NET (m3) = VOLUME_GROSS (m3) | Length (mm) | Area, largest surface, net (Simplebim) (m2) | Weight, as steel (Simplebim) (kg) | Volume, net (Simplebim) (m3) | Bottom elevation | Top elevation
2 x STÅLBJELKE | 4.2131 | 0.03668 | 0.08309 | 4.31907 | 0.00054 | 262 | 0.03578 | 4.2131 | 0.0005367 | +209.759 | +210.021
2 x STÅLBJELKE | 4.2131 | 0.03668 | 0.08309 | 4.31907 | 0.00054 | 262 | 0.03578 | 4.21309 | 0.0005367 | +209.759 | +210.021
2 x STÅLBJELKE | 6.44942 | 0.05536 | 0.12515 | 6.51914 | 0.00082 | 395.459 | 0.0549643 | 6.44942 | 0.000821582 | +209.574 | +209.969

# IfcPlate: PL15*300 (4)
In: D
Description: PL15*300; Material: STEEL/S355
Tekla Common - Grade: S355; Profile: PL15*300; Top elevation: +209.730
Tekla Quantity - Width: 15 mm; Heigth: 300 mm
Tekla Status - Status: Unknown; Assigned By: Me; Actual: 1; Scheduled: 0; Erection Comment: Missing Value
ePset_LocationTool - Splitting: ORIGINAL
AVINOR - 10_Objektstatus: 0_Nytt/ New; 08_Status: S4; 07_Fase: F90; 05_ID-nummer: +TH=223.009; 04_Kontrakt: 182251; 06_Omrade: TH; 02_Prosjekt: A146091-1; 03_Ansvar: 181605; 09_Arbeidspakke: AP01; 01_Lufthavnkode: ENGM
ePset_Simplebim - Assembly Level: Leaf
Pset_PlateCommon - LoadBearing: no
Name | Bottom elevation | Name | Part mark = Reference | Assembly mark | Class | VOLUME_GROSS (m3) = VOLUME_NET (m3) | AREA_GROSS (m2) | WEIGTH_GROSS (kg) | WEIGTH_NET (kg) = Weight, as steel (Simplebim) (kg) | Length (mm) | AREA_NET (m2) | Volume, net (Simplebim) (m3) | Area, largest surface, net (Simplebim) (m2)
2 x STÅLBJELKE | +209.150 | STÅLBJELKE | DSB-0(?) | SB-0(?) | 330 | 0.00218 | 0.174 | 20.4885 | 17.1326 | 580 | 0.31699 | 0.0021825 | 0.1455
STÅLSPESIAL | +209.175 | STÅLSPESIAL | DSSP-7713 | SSP-700 | 380 | 0.00207 | 0.1665 | 19.6054 | 16.2495 | 555 | 0.30124 | 0.00207 | 0.138
STÅLSPESIAL | +209.175 | STÅLSPESIAL | DSSP-7713 | SSP-699 | 380 | 0.00207 | 0.1665 | 19.6054 | 16.2495 | 555 | 0.30124 | 0.00207 | 0.138

# IfcPlate: PL20*140 (16)
In: D
Description: PL20*140; Material: STEEL/S355
Tekla Status - Status: Unknown; Assigned By: Me; Actual: 1; Scheduled: 0; Erection Comment: Missing Value
AVINOR - 10_Objektstatus: 0_Nytt/ New; 08_Status: S4; 07_Fase: F90; 04_Kontrakt: 182251; 06_Omrade: TH; 02_Prosjekt: A146091-1; 03_Ansvar: 181605; 09_Arbeidspakke: AP01; 01_Lufthavnkode: ENGM
ePset_LocationTool - Splitting: ORIGINAL
ePset_Simplebim - Assembly Level: Leaf
Tekla Common - Grade: S355; Name: STÅLBJELKE; Part mark: DSB-0(?); Assembly mark: SB-0(?); Profile: PL20*140; Class: 330
Pset_PlateCommon - LoadBearing: no; Reference: DSB-0(?)
Tekla Quantity - Width: 20 mm; Heigth: 140 mm
Name | Weight, as steel (Simplebim) (kg) = WEIGTH_NET (kg) | Area, largest surface, net (Simplebim) (m2) | Volume, net (Simplebim) (m3) | 05_ID-nummer | Top elevation | Bottom elevation | VOLUME_NET (m3) = VOLUME_GROSS (m3) | WEIGTH_GROSS (kg) | AREA_GROSS (m2) | Length (mm) | AREA_NET (m2)
2 x STÅLBJELKE | 11.6839 | 0.07442 | 0.0014884 | +TH=223.009 | +209.709 | +209.171 | 0.0015 | 11.8252 | 0.07532 | 538 | 0.17526
6 x STÅLBJELKE | 11.7279 | 0.0747 | 0.001494 | +TH=223.009 | +209.710 | +209.171 | 0.0015 | 11.8692 | 0.0756 | 540 | 0.1759
4 x STÅLBJELKE | 11.662 | 0.07428 | 0.0014856 | +TH=223.009 | +209.708 | +209.171 | 0.0015 | 11.8033 | 0.07518 | 537 | 0.17494
2 x STÅLBJELKE | 4.98004 | 0.03172 | 0.0006344 | +TH=223.013 | +209.969 | +209.741 | 0.00063 | 5.01144 | 0.03192 | 228 | 0.07793
2 x STÅLBJELKE | 7.33661 | 0.04673 | 0.0009346 | +TH=223.009 | +209.508 | +209.171 | 0.00093 | 7.40726 | 0.04718 | 337 | 0.11219

# IfcPlate: PL5*100 (6)
In: F
Description: PL5*100; Material: STEEL/AISI304
ePset_SimplebimBasicQuantities - Volume, net (Simplebim): 0.00005 m3; Weight, as steel (Simplebim): 0.3925 kg; Area, largest surface, net (Simplebim): 0.01 m2
Tekla Common - Bottom elevation: +213.570; Name: STÅLMONTASJE; Class: 370; Profile: PL5*100; Grade: AISI304; Top elevation: +213.670; Part mark: DSM-684; Assembly mark: SM-0(?)
Tekla Status - Status: Unknown; Assigned By: Me; Actual: 1; Scheduled: 0; Erection Comment: Missing Value
Tekla Quantity - VOLUME_GROSS: 0.00005 m3; VOLUME_NET: 0.00005 m3; AREA_NET: 0.022 m2; Width: 5 mm; Heigth: 100 mm; Length: 100 mm; WEIGTH_NET: 0.3925 kg; WEIGTH_GROSS: 0.3925 kg; AREA_GROSS: 0.01 m2
AVINOR - 10_Objektstatus: 0_Nytt/ New; 08_Status: S4; 07_Fase: F90; 04_Kontrakt: 182251; 06_Omrade: TH; 05_ID-nummer: +TH=223.017; 02_Prosjekt: A146091-1; 03_Ansvar: 181605; 09_Arbeidspakke: AP01; 01_Lufthavnkode: ENGM
ePset_LocationTool - Splitting: ORIGINAL
ePset_Simplebim - Assembly Level: Leaf
Pset_PlateCommon - LoadBearing: no; Reference: DSM-684

# IfcPlate: System Panel:A234 - Glass - 20 mm (2)
In: Nivå D + 1,2 m
Type - PredefinedType: CURTAIN_PANEL; Material: Glass(Avinor)
ePset_LocationTool - Splitting: ORIGINAL
AVINOR - 08_Status: S4; 07_Fase: F90; 06_Omrade: TH; 03_Ansvar: 182410; 01_Lufthavnkode: ENGM
ePset_Simplebim - Assembly Level: Leaf
Pset_PlateCommon - IsExternal: no; Reference: A234 - Glass - 20 mm
Pset_QuantityTakeOff - Reference: A234 - Glass - 20 mm
Group: Model Group:TH - Karnapper (members excluded):45660468
Name (System Panel:A234 - Glass - 20 mm:...) | Weight, as steel (Simplebim) (kg) | Volume, net (Simplebim) (m3) | Area, largest surface, net (Simplebim) (m2)
45658756 | 71.957 | 0.0091665 | 0.458325
45658768 | 11.8692 | 0.001512 | 0.0756

# IfcPlate: System Panel:A245 - KL-M00 - - - skal byttes manuelt (4)
In: Nivå F - 0,7 m
Type - PredefinedType: CURTAIN_PANEL; Material: Metal - Preget plate
Pset_QuantityTakeOff - Reference: A245 - KL-M00 - - - skal byttes manuelt
Pset_PlateCommon - Reference: A245 - KL-M00 - - - skal byttes manuelt; IsExternal: no
ePset_Simplebim - Assembly Level: Leaf
AVINOR - 08_Status: S4; 07_Fase: F90; 03_Ansvar: 182412; 06_Omrade: TH; 02_Prosjekt: A184862; 01_Lufthavnkode: ENGM
ePset_LocationTool - Splitting: ORIGINAL
Group: Model Group:A184862 - Kiosk NSOPØ 05.235 2 (members excluded):47061109
Name (System Panel:A245 - KL-M00 - - - skal byttes manuelt:...) | Weight, as steel (Simplebim) (kg) | Area, largest surface, net (Simplebim) (m2) | Volume, net (Simplebim) (m3)
47060944 | 707.44 | 4.50599 | 0.0901197
47060943 | 136.59 | 0.87 | 0.0174
47060992 | 360.917 | 2.29883 | 0.0459767
47060994 | 136.59 | 0.87 | 0.0174

# IfcPlate: System Panel:A245 - Metallkasett Inv.20mm - Offset 30mm (12)
In: Nivå F - 0,7 m
Type - PredefinedType: CURTAIN_PANEL; Material: Metal - Steel
Pset_PlateCommon - IsExternal: no; Reference: A245 - Metallkasett Inv.20mm - Offset 30mm
Pset_QuantityTakeOff - Reference: A245 - Metallkasett Inv.20mm - Offset 30mm
AVINOR - 07_Fase: F90; 08_Status: S1; 03_Ansvar: FDV; 06_Omrade: TH; 01_Lufthavnkode: ENGM
ePset_Simplebim - Assembly Level: Leaf
Name (System Panel:A245 - Metallkasett Inv.20mm - Offset 30mm:...) | Area, largest surface, net (Simplebim) (m2) | Weight, as steel (Simplebim) (kg) | Volume, net (Simplebim) (m3) | Splitting
37418666 | 0.105 | 16.485 | 0.0021 | ORIGINAL
37418735 | 0.0545 | 8.5565 | 0.00109 | ORIGINAL
37419041 | 0.087 | 13.659 | 0.00174 | ORIGINAL
37419072 | 0.0873409 | 13.7125 | 0.00174682 | ORIGINAL
37419049 | 1.4792 | 232.235 | 0.0295841 | ORIGINAL
37419051 | 1.4792 | 232.235 | 0.0295841 | ORIGINAL
37418642 | 0.72982 | 114.582 | 0.0145964 | RESULT
37418640 | 0.72982 | 114.582 | 0.0145964 | RESULT
37418638 | 0.72982 | 114.582 | 0.0145964 | RESULT
37418636 | 0.583856 | 91.6654 | 0.0116771 | RESULT
37418634 | 0.145964 | 22.9164 | 0.00291928 | RESULT
37418739 | 0.145964 | 22.9164 | 0.00291928 | RESULT

# IfcPlate: System Panel:A245 - T1 - Glass - 10 mm (7)
In: Nivå F - 0,7 m
Type - PredefinedType: CURTAIN_PANEL; Material: Glass(Avinor)
Pset_PlateCommon - Reference: A245 - T1 - Glass - 10 mm; IsExternal: no
Pset_QuantityTakeOff - Reference: A245 - T1 - Glass - 10 mm
ePset_Simplebim - Assembly Level: Leaf
ePset_LocationTool - Splitting: ORIGINAL
AVINOR - 08_Status: S4; 07_Fase: F90; 03_Ansvar: 182412; 06_Omrade: TH; 02_Prosjekt: A184862; 01_Lufthavnkode: ENGM
Group: Model Group:A184862 - Kiosk NSOPØ 05.235 2 (members excluded):47061109
Name (System Panel:A245 - T1 - Glass - 10 mm:...) | Area, largest surface, net (Simplebim) (m2) | Weight, as steel (Simplebim) (kg) | Volume, net (Simplebim) (m3)
47060913 | 2.22591 | 174.734 | 0.0222591
47060940 | 2.55 | 200.175 | 0.0255
47060923 | 2.55 | 200.175 | 0.0255
47060921 | 2.55 | 200.175 | 0.0255
47060919 | 2.55 | 200.175 | 0.0255
47060917 | 2.55 | 200.175 | 0.0255
47060915 | 2.55 | 200.175 | 0.0255

# IfcPlate: System Panel:A245 - Trepanel eksisterende (2)
In: Nivå F - 0,7 m
Type - PredefinedType: CURTAIN_PANEL; Material: T2_Tre Finerplate
Pset_PlateCommon - Reference: A245 - Trepanel eksisterende; IsExternal: no
Pset_QuantityTakeOff - Reference: A245 - Trepanel eksisterende
AVINOR - 07_Fase: F90; 08_Status: S1; 03_Ansvar: FDV; 06_Omrade: TH; 01_Lufthavnkode: ENGM
ePset_Simplebim - Assembly Level: Leaf
ePset_LocationTool - Splitting: ORIGINAL
Name (System Panel:A245 - Trepanel eksisterende:...) | Weight, as steel (Simplebim) (kg) | Area, largest surface, net (Simplebim) (m2) | Volume, net (Simplebim) (m3)
37418743 | 162.208 | 1.03317 | 0.0206635
37418745 | 161.475 | 1.0285 | 0.02057

# IfcPlate: System Panel:A245 - Trepanel eksisterende 2 (14)
In: Nivå F - 0,7 m
Type - PredefinedType: CURTAIN_PANEL; Material: T2_Tre Finerplate
Pset_QuantityTakeOff - Reference: A245 - Trepanel eksisterende 2
Pset_PlateCommon - Reference: A245 - Trepanel eksisterende 2; IsExternal: no
AVINOR - 07_Fase: F90; 08_Status: S1; 03_Ansvar: FDV; 06_Omrade: TH; 01_Lufthavnkode: ENGM
ePset_Simplebim - Assembly Level: Leaf
ePset_LocationTool - Splitting: RESULT
Name (System Panel:A245 - Trepanel eksisterende 2:...) | Area, largest surface, net (Simplebim) (m2) | Volume, net (Simplebim) (m3) | Weight, as steel (Simplebim) (kg)
37418987 | 0.0535202 | 0.00214081 | 16.8053
37418995 | 0.0535202 | 0.00214081 | 16.8053
37419003 | 0.0437892 | 0.00175157 | 13.7498
37418827 | 0.0535202 | 0.00214081 | 16.8053
37418843 | 0.0535202 | 0.00214081 | 16.8053
37418899 | 0.0535202 | 0.00214081 | 16.8053
37418875 | 0.0535202 | 0.00214081 | 16.8053
37418891 | 0.0535202 | 0.00214081 | 16.8053
37418915 | 0.0535202 | 0.00214081 | 16.8053
37418931 | 0.0535202 | 0.00214081 | 16.8053
37418947 | 0.0535202 | 0.00214081 | 16.8053
37418979 | 0.0535202 | 0.00214081 | 16.8053
37418741 | 0.0535202 | 0.00214081 | 16.8053
37418811 | 0.0535202 | 0.00214081 | 16.8053

# IfcPlate: System Panel:UTGAAR - A245 - Metallkasett Inv. - 20 mm - Offset 30 mm (6)
In: Nivå F - 0,7 m
Type - PredefinedType: CURTAIN_PANEL; Material: Metal - Preget plate
Pset_PlateCommon - IsExternal: no; Reference: UTGAAR - A245 - Metallkasett Inv. - 20 mm - Offset 30 mm
AVINOR - 07_Fase: F90; 08_Status: S1; 03_Ansvar: FDV; 06_Omrade: TH; 01_Lufthavnkode: ENGM
ePset_Simplebim - Assembly Level: Leaf
ePset_LocationTool - Splitting: ORIGINAL
Pset_QuantityTakeOff - Reference: UTGAAR - A245 - Metallkasett Inv. - 20 mm - Offset 30 mm
Name (System Panel:UTGAAR - A245 - Metallkasett Inv. - 20 mm - Offset 30 mm:...) | Area, largest surface, net (Simplebim) (m2) | Volume, net (Simplebim) (m3) | Weight, as steel (Simplebim) (kg)
37419043 | 0.348 | 0.00696 | 54.636
37419073 | 0.349364 | 0.00698727 | 54.8501
37419045 | 0.435 | 0.0087 | 68.295
37419074 | 0.436705 | 0.00873409 | 68.5626
37419047 | 0.435 | 0.0087 | 68.295
37419075 | 0.436705 | 0.00873409 | 68.5626

# IfcRailing: Railing:A247 - Aviser (5)
In: Nivå F - 0,7 m
Material: <Unnamed>; Group: Model Group:A184862 - Kiosk NSOPØ 05.235 2 (members excluded):47061109
ePset_LocationTool - Splitting: ORIGINAL
Pset_RailingCommon - Height: 1219.2 mm; IsExternal: no; Reference: A247 - Aviser
ePset_Simplebim - Assembly Level: Leaf
AVINOR - 08_Status: S4; 07_Fase: F90; 03_Ansvar: 182412; 06_Omrade: TH; 02_Prosjekt: A184862; 01_Lufthavnkode: ENGM
Pset_QuantityTakeOff - Reference: A247 - Aviser
Name (Railing:A247 - Aviser:...) | Length (mm) | Height (mm) | Width (mm)
47060632 | 3325.56 | 30 | 2946.11
47060639 | 3339.04 | 29.9999 | 625.435
47060648 | 9543.08 | 29.995 | 1789.11
47060926 | 6880 | 29.9813 | 165.002
47060970 | 1303 | 29.9813 | 165.002

# IfcRoof: A255 - X-finer 7 - 18mm:A255 - X-finer 7 - 18mm, A255 - X-finer 7 - 18mm:A255 - X-finer 7 - 18mm:45656947
In: Nivå F
Material: _NSW X-finer med skarvur horrisontal; Group: Model Group:TH - Karnapper (members excluded):45660468
Pset_QuantityTakeOff - Reference: A255 - X-finer 7 - 18mm
ePset_Simplebim - Assembly Level: Topmost
AVINOR - 08_Status: S4; 07_Fase: F90; 06_Omrade: TH; 03_Ansvar: 182410; 01_Lufthavnkode: ENGM
ePset_SimplebimBasicQuantities - Volume, net (Simplebim): 0.275234 m3; Height: 18 mm; Width: 311 mm; Length: 49292 mm
Pset_RoofCommon - IsExternal: yes; Reference: A255 - X-finer 7 - 18mm; TotalArea: 0.00558373 m2

# IfcRoof: Basic Roof:A260 - Tak - 570mm, Basic Roof:A260 - Tak - 570mm:45656911
In: Nivå F - 0,7 m
ePset_LocationTool - Splitting: RESULT
Pset_QuantityTakeOff - Reference: A260 - Tak - 570mm
ePset_SimplebimBasicQuantities - Thickness (Simplebim): 911.17 mm; Perimeter (Simplebim): 28719 mm; Volume, net (Simplebim): 26.8144 m3; Area, largest surface, net (Simplebim): 33.6811 m2; Area, sides, net (Simplebim): 26.1679 m2
AVINOR - 08_Status: S4; 07_Fase: F90; 06_Omrade: TH; 03_Ansvar: 182410; 01_Lufthavnkode: ENGM
Pset_RoofCommon - IsExternal: yes; Reference: A260 - Tak - 570mm
ePset_Simplebim - Assembly Level: Leaf
Group: Model Group:TH - Karnapper (members excluded):45660468

# IfcSlab: 100*13310, PÅSTØP
In: F
Description: 100*13310; PredefinedType: FLOOR
Tekla Common - Bottom elevation: +210.030; Part mark: Concrete_PST-1-27; Name: PÅSTØP; Top elevation: +210.130; Profile: 100*13310; Grade: C35/45; Class: 262; Assembly mark: PST-1022
AVINOR - 07_Fase: F90; 02_Prosjekt: T1; 03_Ansvar: FDV; 04_Kontrakt: FDV; 08_Status: S2; 10_Objektstatus: 3_Eksisterende/ Existing; 06_Omrade: TH; 01_Lufthavnkode: ENGM
ePset_LocationTool - Splitting: RESULT
ePset_SimplebimBasicQuantities - Area, sides, net (Simplebim): 5.24644 m2; Thickness (Simplebim): 100.001 mm; Perimeter (Simplebim): 52463.7 mm; Volume, net (Simplebim): 13.2371 m3; Area, largest surface, net (Simplebim): 132.371 m2; Area, top, net (Simplebim): 132.371 m2
ePset_Simplebim - Assembly Level: Leaf
Tekla Status - Status: Unknown; Assigned By: Me; Actual: 1; Scheduled: 0; Erection Comment: Missing Value
Pset_SlabCommon - Reference: Concrete_PST-1-27; LoadBearing: no

# IfcSlab: 100*3600, PÅSTØP
In: G
Description: 100*3600; PredefinedType: FLOOR
Pset_SlabCommon - LoadBearing: no; Reference: Concrete_PLD-1-248
AVINOR - 07_Fase: F90; 02_Prosjekt: T1; 03_Ansvar: FDV; 04_Kontrakt: FDV; 08_Status: S2; 10_Objektstatus: 3_Eksisterende/ Existing; 06_Omrade: TH; 01_Lufthavnkode: ENGM
ePset_LocationTool - Splitting: RESULT
ePset_Simplebim - Assembly Level: Leaf
ePset_SimplebimBasicQuantities - Volume, net (Simplebim): 5.47608 m3; Area, sides, net (Simplebim): 3.77973 m2; Area, largest surface, net (Simplebim): 54.7608 m2; Area, top, net (Simplebim): 54.7608 m2; Perimeter (Simplebim): 37797.3 mm; Thickness (Simplebim): 100 mm
Tekla Common - Profile: 100*3600; Name: PÅSTØP; Bottom elevation: +213.560; Assembly mark: PST-1251; Part mark: Concrete_PLD-1-248; Grade: C35/45; Class: 262; Top elevation: +213.660
Tekla Status - Status: Unknown; Assigned By: Me; Actual: 1; Scheduled: 0; Erection Comment: Missing Value

# IfcSlab: 125*3020, PLASSTØPTDEKKE
In: D
Description: 125*3020; PredefinedType: FLOOR
AVINOR - 10_Objektstatus: 0_Nytt/ New; 08_Status: S4; 07_Fase: F90; 04_Kontrakt: 182251; 06_Omrade: TH; 02_Prosjekt: A146091-1; 05_ID-nummer: +TH=251.011; 03_Ansvar: 181605; 09_Arbeidspakke: AP01; 01_Lufthavnkode: ENGM
Pset_SlabCommon - Reference: Concrete_PLD-1-342; LoadBearing: no
ePset_Simplebim - Assembly Level: Leaf
Tekla Common - Part mark: Concrete_PLD-1-342; Top elevation: +210.165; Profile: 125*3020; Name: PLASSTØPTDEKKE; Assembly mark: PLD-3248; Bottom elevation: +210.041; Grade: C35/45; Class: 260
Tekla Status - Status: Unknown; Assigned By: Me; Actual: 1; Scheduled: 0; Erection Comment: Missing Value
ePset_SimplebimBasicQuantities - Perimeter (Simplebim): 210208 mm; Thickness (Simplebim): 124.2 mm; Area, sides, net (Simplebim): 26.1078 m2; Volume, net (Simplebim): 4.17545 m3; Area, top, net (Simplebim): 38.6698 m2; Area, largest surface, net (Simplebim): 38.6698 m2
ePset_LocationTool - Splitting: RESULT

# IfcSlab: 250*1615, PREFABDEKKE
In: F
Description: 250*1615; PredefinedType: FLOOR; Material: CONCRETE/C45/55 250 mm
Tekla Quantity - WEIGTH_NET: 1744.21 kg; AREA_NET: 7.52153 m2; VOLUME_GROSS: 0.72675 m3; VOLUME_NET: 0.72675 m3; Heigth: 1615.02 mm; Width: 250 mm; WEIGTH_GROSS: 1744.22 kg; AREA_GROSS: 2.90704 m2; Length: 1800 mm
Tekla Common - Bottom elevation: +209.765; Profile: 250*1615; Name: PREFABDEKKE; Top elevation: +210.015; Grade: C45/55; Assembly mark: PD-616; Class: 160; Part mark: Concrete_PD-1-13
ePset_SimplebimBasicQuantities - Area, sides, net (Simplebim): 1.70751 m2; Area, top, net (Simplebim): 2.90701 m2; Area, largest surface, net (Simplebim): 2.90701 m2; Thickness (Simplebim): 250 mm; Volume, net (Simplebim): 0.726752 m3; Perimeter (Simplebim): 6830.04 mm
ePset_Simplebim - Assembly Level: Leaf
ePset_LocationTool - Splitting: ORIGINAL
Pset_SlabCommon - LoadBearing: no; Reference: Concrete_PD-1-13
AVINOR - 07_Fase: F90; 02_Prosjekt: T1; 05_ID-nummer: +TA=251.003; 03_Ansvar: FDV; 04_Kontrakt: FDV; 08_Status: S2; 10_Objektstatus: 3_Eksisterende/ Existing; 06_Omrade: TH; 01_Lufthavnkode: ENGM
Tekla Status - Status: Unknown; Assigned By: Me; Actual: 1; Scheduled: 0; Erection Comment: Missing Value

# IfcSlab: 265*110 (3)
In: F
Description: 265*110; PredefinedType: FLOOR
AVINOR - 07_Fase: F90; 02_Prosjekt: T1; 03_Ansvar: FDV; 04_Kontrakt: FDV; 08_Status: S2; 10_Objektstatus: 3_Eksisterende/ Existing; 06_Omrade: TH; 01_Lufthavnkode: ENGM
ePset_SimplebimBasicQuantities - Thickness (Simplebim): 265 mm
Pset_SlabCommon - LoadBearing: no; Reference: Concrete-19003
ePset_Simplebim - Assembly Level: Leaf
Tekla Common - Bottom elevation: +209.765; Top elevation: +210.030; Profile: 265*110; Name: PÅSTØP; Grade: C30/37; Part mark: Concrete-19003; Class: 262; Assembly mark: PST-1022
Tekla Status - Status: Unknown; Assigned By: Me; Actual: 1; Scheduled: 0; Erection Comment: Missing Value
Name | Area, sides, net (Simplebim) (m2) | Area, top, net (Simplebim) (m2) | Area, largest surface, net (Simplebim) (m2) | Perimeter (Simplebim) (mm) | Volume, net (Simplebim) (m3) | Splitting
PÅSTØP | 4.4573 | 0.913004 | 2.1995 | 16820 | 0.241946 | ORIGINAL | Material: CONCRETE/C30/37 265 mm; Tekla Quantity - AREA_GROSS: 0.91301 m2; VOLUME_NET: 0.24195 m3; VOLUME_GROSS: 0.24195 m3; Heigth: 110.001 mm; Width: 265 mm; Length: 8300 mm; AREA_NET: 6.28331 m2; WEIGTH_NET: 580.67 kg; WEIGTH_GROSS: 580.673 kg
PÅSTØP | 1.40349 | 0.279192 | 0.672595 | 5296.19 | 0.073986 | RESULT
PÅSTØP | 1.68041 | 0.336665 | 0.811055 | 6341.17 | 0.0892162 | RESULT

# IfcSlab: A255 - X-finer 7 - 18mm:A255 - X-finer 7 - 18mm, A255 - X-finer 7 - 18mm:A255 - X-finer 7 - 18mm:45656947:1
In: Nivå F
Type - PredefinedType: ROOF
Pset_SlabCommon - IsExternal: yes; Reference: A255 - X-finer 7 - 18mm
AVINOR - 08_Status: S4; 07_Fase: F90; 06_Omrade: TH; 03_Ansvar: 182410; 01_Lufthavnkode: ENGM
ePset_Simplebim - Assembly Level: Leaf
Pset_ReinforcementBarPitchOfSlab - Reference: A255 - X-finer 7 - 18mm; sets with these values: 2
ePset_SimplebimBasicQuantities - Perimeter (Simplebim): 31251.1 mm; Area, largest surface, net (Simplebim): 4.74546 m2; Area, top, net (Simplebim): 4.74546 m2; Volume, net (Simplebim): 0.0854237 m3; Thickness (Simplebim): 18 mm; Area, sides, net (Simplebim): 0.56252 m2
ePset_LocationTool - Splitting: RESULT
Group: Model Group:TH - Karnapper (members excluded):45660468

# IfcSlab: Floor:A245 - Metalplate 5mm, Floor:A245 - Metalplate 5mm:47060701
In: Nivå F - 0,7 m
Type - PredefinedType: FLOOR; Material: _NSW Stål 5 mm
Pset_ReinforcementBarPitchOfSlab - Reference: A245 - Metalplate 5mm; sets with these values: 2
Pset_SlabCommon - Reference: A245 - Metalplate 5mm; IsExternal: no; LoadBearing: no; PitchAngle: 0 deg
ePset_SimplebimBasicQuantities - Volume, net (Simplebim): 0.0415033 m3; Area, largest surface, net (Simplebim): 8.30064 m2; Area, top, net (Simplebim): 8.30064 m2; Thickness (Simplebim): 5 mm; Area, sides, net (Simplebim): 0.229758 m2; Perimeter (Simplebim): 45951.7 mm
ePset_Simplebim - Assembly Level: Leaf
ePset_LocationTool - Splitting: ORIGINAL
AVINOR - 08_Status: S4; 07_Fase: F90; 03_Ansvar: 182412; 06_Omrade: TH; 02_Prosjekt: A184862; 01_Lufthavnkode: ENGM
Group: Model Group:A184862 - Kiosk NSOPØ 05.235 2 (members excluded):47061109

# IfcSlab: Floor:A250 - Gulv - 550mm, Floor:A250 - Gulv - 550mm:45656874
In: Nivå F - 0,7 m
Type - PredefinedType: FLOOR; Material: 254 - Gulvoverflate - Limtre 15 mm, 254 - Gulvoppbygging - Påstøp 20 mm, 252 - Gulv på grunn - Isolasjon under dekke 125 mm, 252 - Gulv på grunn - Brannisolasjon R90 25 mm, 252 - Gulv på grunn - Bindingsverk med isolasjon 220 mm, 252 - Gulv på grunn - Bindingsverk med isolasjon 150 mm, 252 - Gulv på grunn - GU-Plate 9 mm, 252 - Gulv på grunn - Luftspalte 116 mm
AVINOR - 08_Status: S4; 07_Fase: F90; 05_ID-nummer: +TH=254.026; 06_Omrade: TH; 03_Ansvar: 182410; 01_Lufthavnkode: ENGM
ePset_LocationTool - Splitting: RESULT
ePset_SimplebimBasicQuantities - Area, top, net (Simplebim): 61.1232 m2; Area, sides, net (Simplebim): 53.1511 m2; Volume, net (Simplebim): 21.951 m3; Area, largest surface, net (Simplebim): 38.3591 m2; Thickness (Simplebim): 680 mm; Perimeter (Simplebim): 78163.4 mm
Pset_SlabCommon - IsExternal: no; LoadBearing: yes; Reference: A250 - Gulv - 550mm
Pset_ReinforcementBarPitchOfSlab - Reference: A250 - Gulv - 550mm; sets with these values: 2
ePset_Simplebim - Assembly Level: Leaf
Group: Model Group:TH - Karnapper (members excluded):45660468

# IfcSlab: Floor:A254 - GU-B02 - Vinyl 3mm, Floor:A254 - GU-B02 - Vinyl 3mm:47060897
In: Nivå F - 0,7 m
Type - PredefinedType: FLOOR; Material: T2 - Rubber 3 mm, _NSW Gulv (Generell) 22 mm
ePset_SimplebimBasicQuantities - Perimeter (Simplebim): 17871.2 mm; Area, sides, net (Simplebim): 0.446779 m2; Volume, net (Simplebim): 0.40619 m3; Thickness (Simplebim): 25 mm; Area, largest surface, net (Simplebim): 16.2476 m2; Area, top, net (Simplebim): 16.2476 m2
Pset_SlabCommon - Reference: A254 - GU-B02 - Vinyl 3mm; IsExternal: no; LoadBearing: no; PitchAngle: 0 deg
Pset_QuantityTakeOff - Reference: A254 - GU-B02 - Vinyl 3mm; sets with these values: 2
ePset_Simplebim - Assembly Level: Leaf
AVINOR - 08_Status: S4; 07_Fase: F90; 03_Ansvar: 182412; 06_Omrade: TH; 02_Prosjekt: A184862; 01_Lufthavnkode: ENGM
ePset_LocationTool - Splitting: ORIGINAL
Group: Model Group:A184862 - Kiosk NSOPØ 05.235 2 (members excluded):47061109

# IfcSlab: Floor:A254 - GU-G0X Glass 32 LYS (8)
In: Nivå F - 0,7 m
Type - PredefinedType: FLOOR; Material: Glass(Avinor) 8 mm, _NSW Luftspalte 2 mm, Glass(Avinor) 10 mm, _NSW Luftspalte 2 mm, Glass(Avinor) 10 mm
Pset_QuantityTakeOff - Reference: A254 - GU-G0X Glass 32 LYS; sets with these values: 2
ePset_LocationTool - Splitting: ORIGINAL
ePset_Simplebim - Assembly Level: Leaf
AVINOR - 08_Status: S4; 07_Fase: F90; 03_Ansvar: 182412; 06_Omrade: TH; 02_Prosjekt: A184862; 01_Lufthavnkode: ENGM
ePset_SimplebimBasicQuantities - Thickness (Simplebim): 32 mm
Pset_SlabCommon - Reference: A254 - GU-G0X Glass 32 LYS; IsExternal: no; LoadBearing: no; PitchAngle: 0 deg
Group: Model Group:A184862 - Kiosk NSOPØ 05.235 2 (members excluded):47061109
Name (Floor:A254 - GU-G0X Glass 32 LYS:...) | Area, top, net (Simplebim) (m2) = Area, largest surface, net (Simplebim) (m2) | Area, sides, net (Simplebim) (m2) | Perimeter (Simplebim) (mm) | Volume, net (Simplebim) (m3)
47060770 | 1.88944 | 0.186255 | 5820.45 | 0.0604622
47060770:2 | 4.07091 | 0.278496 | 8703 | 0.130269
47060770:3 | 3.27431 | 0.258356 | 8073.61 | 0.104778
47060770:4 | 2.82922 | 0.304632 | 9519.74 | 0.0905352
47060770:5 | 1.94689 | 0.194663 | 6083.22 | 0.0623003
47060770:6 | 3.37528 | 0.263404 | 8231.36 | 0.108009
47060770:7 | 3.85092 | 0.286288 | 8946.49 | 0.123229
47060770:8 | 3.16802 | 0.256864 | 8027 | 0.101377

# IfcSlab: Floor:A254 - Gulvoppbygging m_f.o - 30mm - stålplategulv, Floor:A254 - Gulvoppbygging m_f.o - 30mm - stålplategulv:37559269
In: Nivå G - 2,0 m
Type - PredefinedType: FLOOR; Material: _NSW Stål 5 mm, _NSW Generell 25 mm
Type - Pset_ReinforcementBarPitchOfSlab - Description: eksisterende stålplategulv nivå G pir
AVINOR - 07_Fase: F90; 03_Ansvar: FDV; 08_Status: S2; 06_Omrade: TH; 01_Lufthavnkode: ENGM
Pset_SlabCommon - Reference: A254 - Gulvoppbygging m_f.o - 30mm - stålplategulv; IsExternal: no; LoadBearing: no; PitchAngle: 0 deg
Pset_ReinforcementBarPitchOfSlab - Reference: A254 - Gulvoppbygging m_f.o - 30mm - stålplategulv; sets with these values: 2
ePset_LocationTool - Splitting: ORIGINAL
ePset_Simplebim - Assembly Level: Leaf
ePset_SimplebimBasicQuantities - Area, largest surface, net (Simplebim): 0.397691 m2; Area, top, net (Simplebim): 0.397691 m2; Volume, net (Simplebim): 0.0119307 m3; Area, sides, net (Simplebim): 0.0812917 m2; Thickness (Simplebim): 30 mm; Perimeter (Simplebim): 2709.72 mm
Group: Model Group:A240 - eksisterende gallerivegg i pir G-2 / bak sjakt (members excluded):37559234

# IfcSlab: Floor:A254 - Gulvoppbygging m_f.o - 40mm - tre, Floor:A254 - Gulvoppbygging m_f.o - 40mm - tre:37454827
In: Nivå G - 2,0 m
Type - PredefinedType: FLOOR; Material: T2 - Dekke uten skravur 40 mm
Type - Pset_ReinforcementBarPitchOfSlab - Description: eksisterende tregulv
Pset_ReinforcementBarPitchOfSlab - Reference: A254 - Gulvoppbygging m_f.o - 40mm - tre; sets with these values: 2
Pset_SlabCommon - Reference: A254 - Gulvoppbygging m_f.o - 40mm - tre; IsExternal: no; LoadBearing: no
AVINOR - 07_Fase: F90; 03_Ansvar: FDV; 08_Status: S2; 06_Omrade: TH; 01_Lufthavnkode: ENGM
ePset_SimplebimBasicQuantities - Area, largest surface, net (Simplebim): 54.4633 m2; Area, top, net (Simplebim): 54.4633 m2; Area, sides, net (Simplebim): 1.50892 m2; Thickness (Simplebim): 40 mm; Perimeter (Simplebim): 37722.9 mm; Volume, net (Simplebim): 2.17854 m3
ePset_LocationTool - Splitting: RESULT
ePset_Simplebim - Assembly Level: Leaf

# IfcSlab: Floor:A254 - Gulvoppbygging m_f.o - 70mm - stein, Floor:A254 - Gulvoppbygging m_f.o - 70mm - stein:36645965
In: Nivå F - 0,7 m
Type - PredefinedType: FLOOR; Material: T2 - Dekke uten skravur 70 mm
Type - Pset_ReinforcementBarPitchOfSlab - Description: eksisterende steingulv
AVINOR - 07_Fase: F90; 03_Ansvar: FDV; 08_Status: S2; 06_Omrade: TH; 01_Lufthavnkode: ENGM
ePset_LocationTool - Splitting: RESULT
ePset_SimplebimBasicQuantities - Area, largest surface, net (Simplebim): 13.3936 m2; Area, top, net (Simplebim): 13.3936 m2; Thickness (Simplebim): 70 mm; Perimeter (Simplebim): 18032.6 mm; Area, sides, net (Simplebim): 1.26228 m2; Volume, net (Simplebim): 0.937551 m3
ePset_Simplebim - Assembly Level: Leaf
Pset_SlabCommon - Reference: A254 - Gulvoppbygging m_f.o - 70mm - stein; IsExternal: no; LoadBearing: no
Pset_QuantityTakeOff - Reference: A254 - Gulvoppbygging m_f.o - 70mm - stein; sets with these values: 2

# IfcSlab: Floor:A254 - eksisterende gangbar glass pir - 27mm (6)
In: Nivå G - 2,0 m
Type - PredefinedType: FLOOR; Material: Glass(Avinor) 27 mm
ePset_SimplebimBasicQuantities - Thickness (Simplebim): 27 mm
AVINOR - 07_Fase: F90; 03_Ansvar: FDV; 08_Status: S2; 06_Omrade: TH; 01_Lufthavnkode: ENGM
Pset_SlabCommon - IsExternal: no; LoadBearing: no; Reference: A254 - eksisterende gangbar glass pir - 27mm
ePset_Simplebim - Assembly Level: Leaf
Pset_ReinforcementBarPitchOfSlab - Reference: A254 - eksisterende gangbar glass pir - 27mm; sets with these values: 2
Name (Floor:A254 - eksisterende gangbar glass pir - 27mm:...) | Area, sides, net (Simplebim) (m2) | Volume, net (Simplebim) (m3) | Area, largest surface, net (Simplebim) (m2) = Area, top, net (Simplebim) (m2) | Perimeter (Simplebim) (mm) | Splitting | PitchAngle (deg) | Group
37451319 | 0.17955 | 0.0266855 | 0.98835 | 6650 | ORIGINAL | 0 | Model Group:A254 - eksisterende glassgulv i pir G ved fasade / __generell (members excluded):37451330
37451367 | 0.17955 | 0.0266855 | 0.98835 | 6650 | ORIGINAL | 0 | Model Group:A254 - eksisterende glassgulv i pir G ved fasade / __generell (members excluded):37451392
37451374 | 0.17955 | 0.0266855 | 0.98835 | 6650 | ORIGINAL | 0 | Model Group:A254 - eksisterende glassgulv i pir G ved fasade / __generell (members excluded):37451392
37451381 | 0.17955 | 0.0266855 | 0.98835 | 6650 | ORIGINAL | 0 | Model Group:A254 - eksisterende glassgulv i pir G ved fasade / __generell (members excluded):37451392
37451454 | 0.17955 | 0.0266855 | 0.98835 | 6650 | ORIGINAL | 0 | Model Group:A254 - eksisterende glassgulv i pir G ved fasade / __generell (members excluded):37451479
37451461 | 0.0398713 | 0.00363604 | 0.134661 | 1476.72 | RESULT |  | Model Group:A254 - eksisterende glassgulv i pir G ved fasade / __generell (members excluded):37451479

# IfcSlab: Floor:B251 - TRP - 70 mm, Floor:B251 - TRP - 70 mm:37559262
In: Nivå G - 2,0 m
Type - PredefinedType: FLOOR; Material: _NSW Generell Gulv (Floor) 70 mm
ePset_SimplebimBasicQuantities - Area, largest surface, net (Simplebim): 0.408502 m2; Area, top, net (Simplebim): 0.408502 m2; Perimeter (Simplebim): 2570.3 mm; Volume, net (Simplebim): 0.0285939 m3; Area, sides, net (Simplebim): 0.179921 m2; Thickness (Simplebim): 70 mm
AVINOR - 07_Fase: F90; 03_Ansvar: FDV; 08_Status: S2; 06_Omrade: TH; 01_Lufthavnkode: ENGM
Pset_ReinforcementBarPitchOfSlab - Reference: B251 - TRP - 70 mm; sets with these values: 2
Pset_SlabCommon - Reference: B251 - TRP - 70 mm; IsExternal: no; LoadBearing: no
ePset_LocationTool - Splitting: RESULT
ePset_Simplebim - Assembly Level: Leaf
Group: Model Group:A240 - eksisterende gallerivegg i pir G-2 / bak sjakt (members excluded):37559234

# IfcSlab: Floor:B254 - Påstøp m/f.o - 100 mm, Floor:B254 - Påstøp m/f.o - 100 mm:37559279
In: Nivå G - 2,0 m
Type - PredefinedType: FLOOR; Material: _NSW Gulv (Generell) 100 mm
ePset_LocationTool - Splitting: RESULT
AVINOR - 07_Fase: F90; 03_Ansvar: FDV; 08_Status: S2; 06_Omrade: TH; 01_Lufthavnkode: ENGM
ePset_SimplebimBasicQuantities - Area, largest surface, net (Simplebim): 0.408502 m2; Area, top, net (Simplebim): 0.408502 m2; Volume, net (Simplebim): 0.0408484 m3; Area, sides, net (Simplebim): 0.257045 m2; Perimeter (Simplebim): 2570.45 mm; Thickness (Simplebim): 100 mm
Pset_QuantityTakeOff - Reference: B254 - Påstøp m/f.o - 100 mm; sets with these values: 2
Pset_SlabCommon - IsExternal: no; LoadBearing: no; Reference: B254 - Påstøp m/f.o - 100 mm
ePset_Simplebim - Assembly Level: Leaf
Group: Model Group:A240 - eksisterende gallerivegg i pir G-2 / bak sjakt (members excluded):37559234

# IfcSlab: HD265 (29)
Description: HD265; PredefinedType: FLOOR
AVINOR - 07_Fase: F90; 02_Prosjekt: T1; 03_Ansvar: FDV; 04_Kontrakt: FDV; 08_Status: S2; 10_Objektstatus: 3_Eksisterende/ Existing; 06_Omrade: TH; 01_Lufthavnkode: ENGM
Tekla Common - Grade: C45/55; Profile: HD265; Name: HULLDEKKE; Class: 162
Pset_SlabCommon - LoadBearing: no
ePset_Simplebim - Assembly Level: Leaf
ePset_SimplebimBasicQuantities - Thickness (Simplebim): 265 mm
Tekla Status - Status: Unknown; Assigned By: Me; Actual: 1; Scheduled: 0; Erection Comment: Missing Value
Name | In | Splitting | Assembly mark | Top elevation | Part mark = Reference | Bottom elevation | Volume, net (Simplebim) (m3) | Area, sides, net (Simplebim) (m2) | Perimeter (Simplebim) (mm) | Area, largest surface, net (Simplebim) (m2) | Area, top, net (Simplebim) (m2) | 05_ID-nummer
2 x HULLDEKKE | G | ORIGINAL | HD-3541 | +213.560 | Concrete_HD-1-216 | +213.295 | 1.52551 | 18.1156 | 68360.8 | 10.2302 | 16.4761 | Material: CONCRETE/C45/55; Tekla Quantity - AREA_NET: 51.1949 m2; VOLUME_GROSS: 1.53013 m3; AREA_GROSS: 0 m2; WEIGTH_GROSS: 3672.32 kg; VOLUME_NET: 1.52551 m3; WEIGTH_NET: 3661.21 kg; Heigth: 265 mm; Width: 1200 mm; Length: 8768 mm
HULLDEKKE | G | ORIGINAL | HD-3363 | +213.560 | Concrete_HD-1-38 | +213.295 | 1.50525 | 18.6919 | 70535.4 | 10.2302 | 16.0261 | Material: CONCRETE/C45/55; Tekla Quantity - AREA_NET: 50.8441 m2; VOLUME_GROSS: 1.53013 m3; AREA_GROSS: 0 m2; WEIGTH_GROSS: 3672.32 kg; VOLUME_NET: 1.50525 m3; WEIGTH_NET: 3612.59 kg; Heigth: 265 mm; Width: 1200 mm; Length: 8768 mm
HULLDEKKE | F | ORIGINAL | HD-3985 | +210.030 | Concrete_HD-1-288 | +209.765 | 1.33837 | 16.7683 | 63276.7 | 9.49504 | 14.3781 | +TA=251.001 | Material: CONCRETE/C45/55; Tekla Quantity - AREA_NET: 45.6135 m2; VOLUME_GROSS: 1.4345 m3; AREA_GROSS: 0 m2; WEIGTH_GROSS: 3442.8 kg; VOLUME_NET: 1.33837 m3; WEIGTH_NET: 3212.1 kg; Heigth: 265 mm; Width: 1200 mm; Length: 8220 mm
6 x HULLDEKKE | F | ORIGINAL | HD-3538 | +210.030 | Concrete_HD-1-213 | +209.765 | 1.43016 | 17.0051 | 64170.3 | 9.59077 | 15.4463 | +TA=251.001 | Material: CONCRETE/C45/55; Tekla Quantity - AREA_NET: 48.017 m2; VOLUME_GROSS: 1.4345 m3; AREA_GROSS: 0 m2; WEIGTH_GROSS: 3442.8 kg; VOLUME_NET: 1.43016 m3; WEIGTH_NET: 3432.39 kg; Heigth: 265 mm; Width: 1200 mm; Length: 8220 mm
HULLDEKKE | G | RESULT | HD-3363 | +213.560 | Concrete_HD-1-38 | +213.295 | 0.475553 | 6.15749 | 23235.8 | 3.23437 | 5.05909
2 x HULLDEKKE | G | RESULT | HD-3541 | +213.560 | Concrete_HD-1-216 | +213.295 | 0.482305 | 5.9654 | 22510.9 | 3.23437 | 5.20909
HULLDEKKE | G | RESULT | HD-3363 | +213.560 | Concrete_HD-1-38 | +213.295 | 0.565735 | 7.23394 | 27297.9 | 3.84399 | 6.02485
2 x HULLDEKKE | G | RESULT | HD-3541 | +213.560 | Concrete_HD-1-216 | +213.295 | 0.57321 | 7.02418 | 26506.3 | 3.84399 | 6.1909
HULLDEKKE | F | RESULT | HD-3360 | +210.030 | Concrete_HD-1-35 | +209.765 | 0.413713 | 5.29289 | 19973.2 | 2.91468 | 4.46942 | +TA=251.001
3 x HULLDEKKE | F | RESULT | HD-3538 | +210.030 | Concrete_HD-1-213 | +209.765 | 0.434632 | 5.41015 | 20415.7 | 2.91468 | 4.69421 | +TA=251.001
HULLDEKKE | F | RESULT | HD-3986 | +210.030 | Concrete_HD-1-289 | +209.765 | 0.184072 | 3.00167 | 11327.1 | 1.17421 | 1.82843 | +TA=251.001
HULLDEKKE | F | RESULT | HD-3487 | +210.030 | Concrete_HD-1-162 | +209.765 | 0.217313 | 2.90491 | 10961.9 | 1.45731 | 2.34705 | +TA=251.001
HULLDEKKE | F | RESULT | HD-3361 | +210.030 | Concrete_HD-1-36 | +209.765 | 0.501932 | 17.1092 | 64562.8 | 3.5243 | 0.0843057 | +TA=251.001
6 x HULLDEKKE | F | RESULT | HD-3538 | +210.030 | Concrete_HD-1-213 | +209.765 | 0.525538 | 6.46894 | 24411.1 | 3.5243 | 5.67603 | +TA=251.001

# IfcSlab: PLNJABE155*40*42.6*71*32.5, PLASSTØPTDEKKE
In: G
Description: PLNJABE155*40*42.6*71*32.5; PredefinedType: FLOOR; Material: CONCRETE/C35/45
AVINOR - 07_Fase: F90; 02_Prosjekt: T1; 03_Ansvar: FDV; 04_Kontrakt: FDV; 08_Status: S2; 10_Objektstatus: 3_Eksisterende/ Existing; 06_Omrade: TH; 01_Lufthavnkode: ENGM
ePset_LocationTool - Splitting: ORIGINAL
ePset_SimplebimBasicQuantities - Volume, net (Simplebim): 0.319363 m3; Area, top, net (Simplebim): 1.7736 m2; Area, largest surface, net (Simplebim): 1.7736 m2; Perimeter (Simplebim): 10284.1 mm; Area, sides, net (Simplebim): 2.03215 m2; Thickness (Simplebim): 197.6 mm
Tekla Quantity - AREA_NET: 4.9248 m2; Width: 880.002 mm; Length: 2030 mm; AREA_GROSS: 4.94696 m2; WEIGTH_GROSS: 771.947 kg; VOLUME_GROSS: 0.32164 m3; VOLUME_NET: 0.31936 m3; WEIGTH_NET: 766.471 kg; Heigth: 197.6 mm
Pset_SlabCommon - LoadBearing: no; Reference: Concrete-20478
ePset_Simplebim - Assembly Level: Leaf
Tekla Common - Top elevation: +213.699; Assembly mark: PLD-2851; Name: PLASSTØPTDEKKE; Grade: C35/45; Profile: PLNJABE155*40*42.6*71*32.5; Bottom elevation: +213.501; Class: 260; Part mark: Concrete-20478
Tekla Status - Status: Unknown; Assigned By: Me; Actual: 1; Scheduled: 0; Erection Comment: Missing Value

# IfcSlab: PLNJABE56.4*40*42.6*71*32.5, PLASSTØPTDEKKE
In: G
Description: PLNJABE56.4*40*42.6*71*32.5; PredefinedType: FLOOR
AVINOR - 07_Fase: F90; 02_Prosjekt: T1; 03_Ansvar: FDV; 04_Kontrakt: FDV; 08_Status: S2; 10_Objektstatus: 3_Eksisterende/ Existing; 06_Omrade: TH; 01_Lufthavnkode: ENGM
Tekla Common - Part mark: Concrete-20694; Assembly mark: PLD-2851; Name: PLASSTØPTDEKKE; Grade: C35/45; Bottom elevation: +213.561; Class: 260; Top elevation: +213.660; Profile: PLNJABE56.4*40*42.6*71*32.5
Pset_SlabCommon - Reference: Concrete-20694; LoadBearing: no
ePset_SimplebimBasicQuantities - Area, sides, net (Simplebim): 0.561122 m2; Perimeter (Simplebim): 5667.9 mm; Area, largest surface, net (Simplebim): 0.573884 m2; Volume, net (Simplebim): 0.046851 m3; Area, top, net (Simplebim): 0.573884 m2; Thickness (Simplebim): 99 mm
ePset_Simplebim - Assembly Level: Leaf
Tekla Status - Status: Unknown; Assigned By: Me; Actual: 1; Scheduled: 0; Erection Comment: Missing Value
ePset_LocationTool - Splitting: RESULT

# IfcSystem (38)
Name | Description
+TH=360.031 TL (1) | +TH=360.031 TL (1)
36= Avtrekk 15 | 36= Avtrekk 15
+TH=360.031 | +TH=360.031
+TH=360.010 (28) | +TH=360.010 (28)
+TH=360.010 (12) | +TH=360.010 (12)
33= Våt Kopi 163 | 33= Våt Kopi 163
+TH=332.003 | +TH=332.003
33= Våt Kopi 64 | 33= Våt Kopi 64
33= Våt Kopi 98 | 33= Våt Kopi 98
33= Våt Kopi 36 | 33= Våt Kopi 36
33= Våt Kopi 37 | 33= Våt Kopi 37
33= Våt Kopi 39 | 33= Våt Kopi 39
+TH=310.001 | +TH=310.001
+TH=310.002 | +TH=310.002
+TH=310.003 | +TH=310.003
32= R 27° Kopi 5 | 32= R 27° Kopi 5
32= T 35° Kopi 1 | 32= T 35° Kopi 1
31= SPV Kopi 77 | 31= SPV Kopi 77
37= T 9° Kopi 2 | 37= T 9° Kopi 2
37= R 18° Kopi 1 | 37= R 18° Kopi 1
31= SPV Kopi 61 | 31= SPV Kopi 61
31=KV Kopi 23 | 31=KV Kopi 23
+TH=313.304 | +TH=313.304
+TH=313.000. | +TH=313.000.
+TH=313.310 | +TH=313.310
31= SPV Kopi 74 | 31= SPV Kopi 74
31= SPV Kopi 47 | 31= SPV Kopi 47
31= SPV Kopi 132 | 31= SPV Kopi 132
Bæresystem generelt | 410 | MagiCAD Pset_System - Description: Bæresystem generelt; Code: 410
Bæresystem for elkraft | 4111 | MagiCAD Pset_System - Description: Bæresystem for elkraft; Code: 4111
Brannalarm | 542 | MagiCAD Pset_System - Description: Brannalarm; Code: 542
Spredenett | 574 | MagiCAD Pset_System - Description: Spredenett; Code: 574
PA-anlegg | 555 | MagiCAD Pset_System - Description: PA-anlegg; Code: 555
Trekkerør generelt | 4110 | MagiCAD Pset_System - Description: Trekkerør generelt; Code: 4110
Veggkanal for generelt | 4112 | MagiCAD Pset_System - Description: Veggkanal for generelt; Code: 4112
KNX Binærutgang | 5624 | MagiCAD Pset_System - Description: KNX Binærutgang; Code: 5624
Trekkerør for tele- og automasjon | 5113 | MagiCAD Pset_System - Description: Trekkerør for tele- og automasjon; Code: 5113
Gulvkanal | 4115 | MagiCAD Pset_System - Description: Gulvkanal; Code: 4115

# IfcWall: Basic Wall:A231 - X-finer med beslag (2)
In: Nivå E
Type - PredefinedType: STANDARD; Material: T2_Metal_Aluminium 1 mm, T2_X-finer 15 mm
ePset_SimplebimBasicQuantities - Thickness (Simplebim): 16 mm; Height (Simplebim): 355 mm
AVINOR - 07_Fase: F90; 03_Ansvar: FDV; 08_Status: S2; 06_Omrade: TH; 01_Lufthavnkode: ENGM
Pset_WallCommon - IsExternal: no; ExtendToStructure: no; LoadBearing: no; Reference: A231 - X-finer med beslag
ePset_Simplebim - Assembly Level: Leaf
ePset_LocationTool - Splitting: RESULT
Pset_ReinforcementBarPitchOfWall - Reference: A231 - X-finer med beslag; sets with these values: 2
Name (Basic Wall:A231 - X-finer med beslag:...) | Area, side, gross, larger (Simplebim) (m2) = Area, side, gross, average (Simplebim) (m2) = Area, side, net, larger (Simplebim) (m2) = Area, side, gross, smaller (Simplebim) (m2) = Area, side, net, average (Simplebim) (m2) = Area, side, net, smaller (Simplebim) (m2) = Area, largest surface, net (Simplebim) (m2) | Volume, net (Simplebim) (m3) | Area, side, gross, AABB (Simplebim) (m2) | Length (Simplebim) (mm)
37344745 | 1.02527 | 0.0164044 | 1.02524 | 2888
37344996 | 1.21076 | 0.0193721 | 1.2109 | 3411

# IfcWall: Basic Wall:A231 - Yttervegg - Isolasjonsjikt 165mm, Basic Wall:A231 - Yttervegg - Isolasjonsjikt 165mm:13669607
In: Nivå E
Type - PredefinedType: STANDARD; Material: _NSW Isolasjon 165 mm
Type - Pset_ReinforcementBarPitchOfWall - Description: Generell yttervegg 200mm
Pset_ReinforcementBarPitchOfWall - Reference: A231 - Yttervegg - Isolasjonsjikt 165mm; sets with these values: 2
ePset_SimplebimBasicQuantities - Volume, net (Simplebim): 1.02233 m3; Thickness (Simplebim): 165 mm; Height (Simplebim): 405 mm; Length (Simplebim): 15299 mm; Area, largest surface, net (Simplebim): 6.19597 m2; Area, side, gross, larger (Simplebim): 6.19597 m2; Area, side, gross, average (Simplebim): 6.19597 m2; Area, side, net, average (Simplebim): 6.19597 m2; Area, side, net, smaller (Simplebim): 6.19597 m2; Area, side, net, larger (Simplebim): 6.19597 m2; Area, side, gross, smaller (Simplebim): 6.19597 m2; Area, side, gross, AABB (Simplebim): 6.19609 m2
AVINOR - 07_Fase: F90; 08_Status: S1; 03_Ansvar: FDV; 06_Omrade: TH; 01_Lufthavnkode: ENGM
ePset_Simplebim - Assembly Level: Leaf
Pset_WallCommon - IsExternal: yes; ExtendToStructure: no; LoadBearing: no; Reference: A231 - Yttervegg - Isolasjonsjikt 165mm
ePset_LocationTool - Splitting: RESULT

# IfcWall: Basic Wall:A231 - Yttervegg - Isolasjonsjikt 185mm, Basic Wall:A231 - Yttervegg - Isolasjonsjikt 185mm:13669633
In: Nivå F - 0,7 m
Type - PredefinedType: STANDARD; Material: _NSW Isolasjon 185 mm
Type - Pset_ReinforcementBarPitchOfWall - Description: Generell yttervegg 200mm
ePset_LocationTool - Splitting: RESULT
Pset_WallCommon - IsExternal: yes; ExtendToStructure: no; LoadBearing: no; Reference: A231 - Yttervegg - Isolasjonsjikt 185mm
ePset_SimplebimBasicQuantities - Area, side, gross, AABB (Simplebim): 3.77622 m2; Area, largest surface, net (Simplebim): 3.77625 m2; Area, side, gross, larger (Simplebim): 3.77625 m2; Area, side, gross, average (Simplebim): 3.77625 m2; Area, side, net, larger (Simplebim): 3.77625 m2; Area, side, gross, smaller (Simplebim): 3.77625 m2; Area, side, net, average (Simplebim): 3.77625 m2; Area, side, net, smaller (Simplebim): 3.77625 m2; Thickness (Simplebim): 184 mm; Height (Simplebim): 315 mm; Length (Simplebim): 11988 mm; Volume, net (Simplebim): 0.698606 m3
Pset_ReinforcementBarPitchOfWall - Reference: A231 - Yttervegg - Isolasjonsjikt 185mm; sets with these values: 2
AVINOR - 08_Status: S4; 07_Fase: F90; 03_Ansvar: FDV; 06_Omrade: TH; 04_Kontrakt: 72467; 02_Prosjekt: 72101; 01_Lufthavnkode: ENGM
ePset_Simplebim - Assembly Level: Leaf

# IfcWall: Basic Wall:A231 - Yttervegg - Isolasjonsjikt 200mm (5)
In: Nivå D + 1,2 m
Type - PredefinedType: STANDARD; Material: _NSW Isolasjon trykkfast 200 mm
Type - Pset_ReinforcementBarPitchOfWall - Description: Generell yttervegg 200mm
ePset_SimplebimBasicQuantities - Thickness (Simplebim): 200 mm; Height (Simplebim): 565 mm
Pset_QuantityTakeOff - Reference: A231 - Yttervegg - Isolasjonsjikt 200mm; sets with these values: 2
ePset_LocationTool - Splitting: RESULT
Pset_WallCommon - Reference: A231 - Yttervegg - Isolasjonsjikt 200mm; IsExternal: yes; ExtendToStructure: no; LoadBearing: no
AVINOR - 07_Fase: F90; 06_Omrade: TH; 01_Lufthavnkode: ENGM
ePset_Simplebim - Assembly Level: Leaf
Name (Basic Wall:A231 - Yttervegg - Isolasjonsjikt 200mm:...) | Area, side, gross, larger (Simplebim) (m2) = Area, side, gross, average (Simplebim) (m2) = Area, side, net, larger (Simplebim) (m2) = Area, side, gross, smaller (Simplebim) (m2) = Area, side, net, average (Simplebim) (m2) = Area, side, net, smaller (Simplebim) (m2) = Area, largest surface, net (Simplebim) (m2) | Area, side, gross, AABB (Simplebim) (m2) | Volume, net (Simplebim) (m3) | Length (Simplebim) (mm) | 08_Status | 03_Ansvar
6986370 | 0.381375 | 0.381375 | 0.076275 | 675 | S1 | FDV
6986371 | 1.87048 | 1.87071 | 0.374096 | 3311 | S1 | FDV
6986373 | 1.87048 | 1.87071 | 0.374096 | 3311 | S1 | FDV
45658126 | 0.678 | 0.678 | 0.1356 | 1200 | S4 | 182410 | Group: Model Group:TH - Karnapper (members excluded):45660468
45658166 | 0.6215 | 0.6215 | 0.1243 | 1100 | S4 | 182410 | Group: Model Group:TH - Karnapper (members excluded):45660468

# IfcWall: Basic Wall:A241 - FFS, Basic Wall:A241 - FFS:47060657
In: Nivå F
Type - PredefinedType: STANDARD; Material: T2_Gips Protect F 12.5 mm, T2_X-finer 12 mm, T2_X-finer 12 mm
Pset_QuantityTakeOff - Reference: A241 - FFS; sets with these values: 2
ePset_SimplebimBasicQuantities - Area, side, gross, AABB (Simplebim): 11.0107 m2; Volume, net (Simplebim): 0.385986 m3; Area, side, gross, smaller (Simplebim): 10.575 m2; Area, side, net, larger (Simplebim): 10.575 m2; Area, side, net, smaller (Simplebim): 10.575 m2; Area, side, net, average (Simplebim): 10.575 m2; Area, side, gross, average (Simplebim): 10.575 m2; Area, side, gross, larger (Simplebim): 10.575 m2; Area, largest surface, net (Simplebim): 10.575 m2; Thickness (Simplebim): 36.5 mm; Height (Simplebim): 1930 mm; Length (Simplebim): 5705 mm
Pset_WallCommon - Reference: A241 - FFS; IsExternal: no; ExtendToStructure: no; LoadBearing: no
ePset_Simplebim - Assembly Level: Leaf
AVINOR - 08_Status: S4; 07_Fase: F90; 03_Ansvar: 182412; 06_Omrade: TH; 02_Prosjekt: A184862; 01_Lufthavnkode: ENGM
ePset_LocationTool - Splitting: ORIGINAL
Group: Model Group:A184862 - Kiosk NSOPØ 05.235 2 (members excluded):47061109

# IfcWall: Basic Wall:A241 - FSVF-100 (100/100 ps-p) (4)
Type - PredefinedType: STANDARD; Material: T2_Gips Protect F 15 mm, T2_Gips Standard 12.5 mm, _NSW Stålstender, uisolert 100 mm, T2_Gips Protect F 15 mm
Type - Pset_ReinforcementBarPitchOfWall - Description: Tilsvarende: T2 - IVEGG-150 - Forprosjekt
Type - Pset_WallCommon - AcousticRating: -
Pset_WallCommon - Reference: A241 - FSVF-100 (100/100 ps-p); IsExternal: no; ExtendToStructure: no; LoadBearing: no
AVINOR - 07_Fase: F90; 03_Ansvar: FDV; 08_Status: S2; 06_Omrade: TH; 01_Lufthavnkode: ENGM
ePset_LocationTool - Splitting: RESULT
Pset_QuantityTakeOff - Reference: A241 - FSVF-100 (100/100 ps-p); sets with these values: 2
ePset_SimplebimBasicQuantities - Thickness (Simplebim): 142 mm
ePset_Simplebim - Assembly Level: Leaf
Name (Basic Wall:A241 - FSVF-100 (100/100 ps-p):...) | In | Area, side, gross, AABB (Simplebim) (m2) | Area, side, gross, smaller (Simplebim) (m2) = Area, side, net, smaller (Simplebim) (m2) = Area, side, net, average (Simplebim) (m2) = Area, side, gross, average (Simplebim) (m2) = Area, largest surface, net (Simplebim) (m2) = Area, side, gross, larger (Simplebim) (m2) = Area, side, net, larger (Simplebim) (m2) | Volume, net (Simplebim) (m3) | Length (Simplebim) (mm) | Height (Simplebim) (mm)
28231049 | Nivå F | 2.884 | 2.58889 | 0.368917 | 1030 | 2800
28231049 | Nivå F - 0,7 m | 0.721 | 0.721416 | 0.102802 | 1030 | 700
2640280 | Nivå F | 2.4864 | 2.48666 | 0.354349 | 888 | 2800
2640280 | Nivå F - 0,7 m | 0.6216 | 0.621666 | 0.0885874 | 888 | 700

# IfcWall: Basic Wall:A241 - RVR-100 (100/100 c/c400 r-r) (2)
In: Nivå E
Type - PredefinedType: STANDARD; Material: Plate - Gips 12.5 mm, _NSW Stålstender, uisolert 100 mm, Plate - Gips 12.5 mm
Type - Pset_ReinforcementBarPitchOfWall - Description: Tilsvarende: T2 - IVEGG-150 - Forprosjekt
AVINOR - 08_Status: S4; 07_Fase: F90; 05_ID-nummer: +TH=241.002; 03_Ansvar: 72612; 06_Omrade: TH; 04_Kontrakt: 72467; 02_Prosjekt: 72101; 01_Lufthavnkode: ENGM
ePset_LocationTool - Splitting: RESULT
Pset_QuantityTakeOff - Reference: A241 - RVR-100 (100/100 c/c400 r-r); sets with these values: 2
ePset_SimplebimBasicQuantities - Volume, net (Simplebim): 0.155375 m3; Area, largest surface, net (Simplebim): 1.243 m2; Area, side, gross, AABB (Simplebim): 1.243 m2; Area, side, gross, larger (Simplebim): 1.243 m2; Area, side, gross, average (Simplebim): 1.243 m2; Area, side, net, average (Simplebim): 1.243 m2; Area, side, net, smaller (Simplebim): 1.243 m2; Area, side, net, larger (Simplebim): 1.243 m2; Area, side, gross, smaller (Simplebim): 1.243 m2; Thickness (Simplebim): 125 mm; Height (Simplebim): 565 mm; Length (Simplebim): 2200 mm
Pset_WallCommon - Reference: A241 - RVR-100 (100/100 c/c400 r-r); IsExternal: no; ExtendToStructure: no; LoadBearing: no
ePset_Simplebim - Assembly Level: Leaf
Name (Basic Wall:A241 - RVR-100 (100/100 c/c400 r-r):...)
35300537
35292700

# IfcWall: Basic Wall:A241 - RVR-77 (75/75 r-rr), Basic Wall:A241 - RVR-77 (75/75 r-rr):47061008
In: Nivå F
Type - PredefinedType: STANDARD; Material: Plate - Gips 12.5 mm, _NSW Stålstender, uisolert 75 mm, Plate - Gips 12.5 mm, Plate - Gips 12.5 mm
Type - Pset_ReinforcementBarPitchOfWall - Description: Internt i toalettrom
Pset_ReinforcementBarPitchOfWall - Reference: A241 - RVR-77 (75/75 r-rr); sets with these values: 2
ePset_SimplebimBasicQuantities - Area, side, gross, larger (Simplebim): 0.784259 m2; Area, side, net, larger (Simplebim): 0.784259 m2; Area, side, net, average (Simplebim): 0.784259 m2; Area, side, gross, average (Simplebim): 0.784259 m2; Area, largest surface, net (Simplebim): 0.784259 m2; Area, side, net, smaller (Simplebim): 0.784259 m2; Area, side, gross, smaller (Simplebim): 0.784259 m2; Volume, net (Simplebim): 0.0842525 m3; Area, side, gross, AABB (Simplebim): 0.886844 m2; Thickness (Simplebim): 112.5 mm; Length (Simplebim): 368.75 mm; Height (Simplebim): 2405 mm
Pset_WallCommon - Reference: A241 - RVR-77 (75/75 r-rr); IsExternal: no; ExtendToStructure: no; LoadBearing: no
ePset_Simplebim - Assembly Level: Leaf
ePset_LocationTool - Splitting: ORIGINAL
AVINOR - 08_Status: S4; 07_Fase: F90; 03_Ansvar: 182412; 06_Omrade: TH; 02_Prosjekt: A184862; 01_Lufthavnkode: ENGM
Group: Model Group:A184862 - Kiosk NSOPØ 05.235 2 (members excluded):47061109
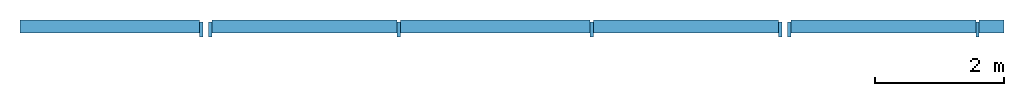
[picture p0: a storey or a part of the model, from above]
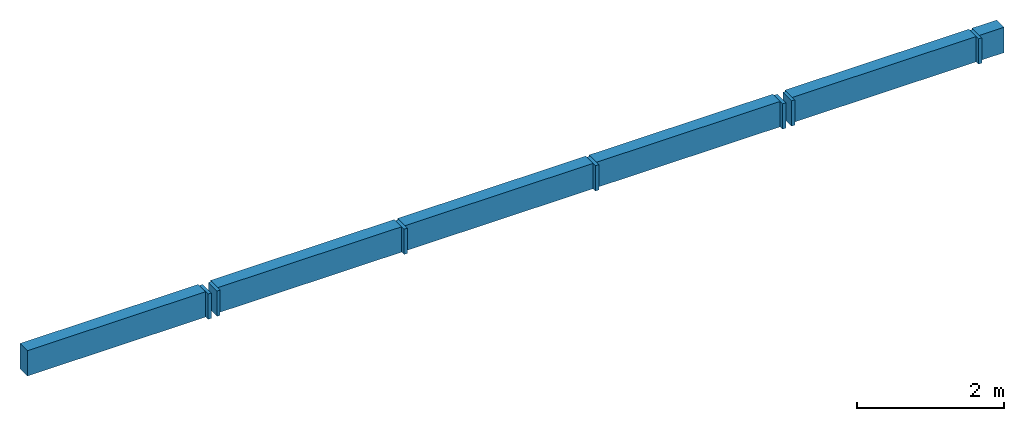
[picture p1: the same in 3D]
Properties of the parts of a building model (IFC2X3), part 7 of 7

# IfcWall: Basic Wall:A241 - SVS-100 (100/100 g-g) (11)
In: Nivå E
Type - PredefinedType: STANDARD; Material: Plate - Gips 12.5 mm, _NSW Stålstender, uisolert 100 mm, Plate - Gips 12.5 mm
Type - Pset_ReinforcementBarPitchOfWall - Description: Tilsvarende: T2 - IVEGG-125 - Forprosjekt
Pset_WallCommon - Reference: A241 - SVS-100 (100/100 g-g); IsExternal: no; ExtendToStructure: no; LoadBearing: no
AVINOR - 07_Fase: F90; 03_Ansvar: FDV; 08_Status: S2; 06_Omrade: TH; 01_Lufthavnkode: ENGM
ePset_LocationTool - Splitting: RESULT
ePset_SimplebimBasicQuantities - Height (Simplebim): 565 mm
ePset_Simplebim - Assembly Level: Leaf
Pset_QuantityTakeOff - Reference: A241 - SVS-100 (100/100 g-g); sets with these values: 2
Name (Basic Wall:A241 - SVS-100 (100/100 g-g):...) | Thickness (Simplebim) (mm) | Length (Simplebim) (mm) | Area, side, gross, AABB (Simplebim) (m2) | Area, side, net, smaller (Simplebim) (m2) = Area, side, net, average (Simplebim) (m2) = Area, side, gross, smaller (Simplebim) (m2) = Area, side, net, larger (Simplebim) (m2) = Area, side, gross, average (Simplebim) (m2) = Area, side, gross, larger (Simplebim) (m2) = Area, largest surface, net (Simplebim) (m2) | Volume, net (Simplebim) (m3)
2614779 | 126 | 2522 | 1.42493 | 1.42501 | 0.178127
2614785 | 125 | 3867 | 2.18486 | 2.18457 | 0.273072
37825776 | 124 | 970 | 0.54805 | 0.54805 | 0.0685063
2614780 | 125 | 2407 | 1.35996 | 1.35996 | 0.169994
2614781 | 126 | 1644 | 0.92886 | 0.929058 | 0.116132
2614786 | 125 | 1166 | 0.65879 | 0.65879 | 0.0823488
2614787 | 126 | 430 | 0.24295 | 0.243232 | 0.0304041
2614788 | 125 | 1041 | 0.588165 | 0.588165 | 0.0735206
2614782 | 125 | 5794 | 3.27361 | 3.27333 | 0.409166
2614784 | 126 | 2396 | 1.35374 | 1.35402 | 0.169253
2614783 | 125 | 1155 | 0.652575 | 0.652293 | 0.0815366

# IfcWall: Basic Wall:A241 - Skjørt (SV-75 S) 3, Basic Wall:A241 - Skjørt (SV-75 S) 3:47060938
In: Nivå F - 0,7 m
Type - PredefinedType: STANDARD; Material: Plate - Gips 12.5 mm, _NSW Stålstender, uisolert 75 mm
Type - Pset_ReinforcementBarPitchOfWall - Description: 12.5mm Gipsplater - 75mm Stålstender
Type - Pset_ConcreteElementGeneral - FireRating: EI30
Type - Pset_WallCommon - FireRating: EI30
Pset_QuantityTakeOff - Reference: A241 - Skjørt (SV-75 S) 3; sets with these values: 2
ePset_LocationTool - Splitting: ORIGINAL
Pset_WallCommon - Reference: A241 - Skjørt (SV-75 S) 3; IsExternal: no; ExtendToStructure: no; LoadBearing: no
ePset_Simplebim - Assembly Level: Leaf
AVINOR - 08_Status: S4; 07_Fase: F90; 03_Ansvar: 182412; 06_Omrade: TH; 02_Prosjekt: A184862; 01_Lufthavnkode: ENGM
ePset_SimplebimBasicQuantities - Area, side, gross, smaller (Simplebim): 7.83662 m2; Area, side, net, larger (Simplebim): 7.83662 m2; Area, side, net, smaller (Simplebim): 7.83662 m2; Area, side, net, average (Simplebim): 7.83662 m2; Area, side, gross, average (Simplebim): 7.83662 m2; Area, side, gross, larger (Simplebim): 7.83662 m2; Area, largest surface, net (Simplebim): 7.83662 m2; Volume, net (Simplebim): 0.685704 m3; Thickness (Simplebim): 87.5 mm; Length (Simplebim): 10385.5 mm; Area, side, gross, AABB (Simplebim): 7.90252 m2; Height (Simplebim): 760.919 mm
Group: Model Group:A184862 - Kiosk NSOPØ 05.235 2 (members excluded):47061109

# IfcWall: Basic Wall:A242 - IGV Glass Opal 14mm, Basic Wall:A242 - IGV Glass Opal 14mm:47060612
In: Nivå F
Type - PredefinedType: STANDARD; Material: Kledning 14 mm
Pset_QuantityTakeOff - Reference: A242 - IGV Glass Opal 14mm; sets with these values: 2
Pset_WallCommon - IsExternal: no; ExtendToStructure: no; LoadBearing: no; Reference: A242 - IGV Glass Opal 14mm
ePset_Simplebim - Assembly Level: Leaf
ePset_LocationTool - Splitting: ORIGINAL
AVINOR - 08_Status: S4; 07_Fase: F90; 03_Ansvar: 182412; 06_Omrade: TH; 02_Prosjekt: A184862; 01_Lufthavnkode: ENGM
ePset_SimplebimBasicQuantities - Area, side, gross, smaller (Simplebim): 2.36283 m2; Area, side, net, larger (Simplebim): 2.36283 m2; Area, side, net, smaller (Simplebim): 2.36283 m2; Area, side, net, average (Simplebim): 2.36283 m2; Area, side, gross, average (Simplebim): 2.36283 m2; Area, side, gross, larger (Simplebim): 2.36283 m2; Area, largest surface, net (Simplebim): 2.36283 m2; Area, side, gross, AABB (Simplebim): 2.49356 m2; Thickness (Simplebim): 14 mm; Height (Simplebim): 1930 mm; Length (Simplebim): 1292 mm; Volume, net (Simplebim): 0.0330796 m3
Group: Model Group:A184862 - Kiosk NSOPØ 05.235 2 (members excluded):47061109

# IfcWallStandardCase: Basic Wall:A231 - X-finer med beslag, Basic Wall:A231 - X-finer med beslag:37344868
In: Nivå E
Type - PredefinedType: STANDARD; Material: T2_Metal_Aluminium 1 mm, T2_X-finer 15 mm
AVINOR - 07_Fase: F90; 03_Ansvar: FDV; 08_Status: S2; 06_Omrade: TH; 01_Lufthavnkode: ENGM
ePset_LocationTool - Splitting: ORIGINAL
Pset_WallCommon - IsExternal: no; ExtendToStructure: no; LoadBearing: no; Reference: A231 - X-finer med beslag
ePset_SimplebimBasicQuantities - Volume, net (Simplebim): 0.05112 m3; Height (Simplebim): 355 mm; Thickness (Simplebim): 16 mm; Length (Simplebim): 9000 mm; Area, side, gross, AABB (Simplebim): 3.195 m2; Area, largest surface, net (Simplebim): 3.195 m2; Area, side, gross, smaller (Simplebim): 3.195 m2; Area, side, net, larger (Simplebim): 3.195 m2; Area, side, net, smaller (Simplebim): 3.195 m2; Area, side, net, average (Simplebim): 3.195 m2; Area, side, gross, average (Simplebim): 3.195 m2; Area, side, gross, larger (Simplebim): 3.195 m2
ePset_Simplebim - Assembly Level: Leaf
Pset_ReinforcementBarPitchOfWall - Reference: A231 - X-finer med beslag; sets with these values: 2

# IfcWallStandardCase: Basic Wall:A241 - F-15, Basic Wall:A241 - F-15:37559291
In: Nivå G - 2,0 m
Type - PredefinedType: STANDARD; Material: T2_Gips Protect F 15 mm
ePset_LocationTool - Splitting: ORIGINAL
AVINOR - 07_Fase: F90; 03_Ansvar: FDV; 08_Status: S2; 06_Omrade: TH; 01_Lufthavnkode: ENGM
Pset_WallCommon - IsExternal: no; ExtendToStructure: no; LoadBearing: no; Reference: A241 - F-15
ePset_SimplebimBasicQuantities - Height (Simplebim): 230.5 mm; Thickness (Simplebim): 15 mm; Area, largest surface, net (Simplebim): 0.0953118 m2; Area, side, gross, average (Simplebim): 0.0953118 m2; Area, side, gross, larger (Simplebim): 0.0953118 m2; Area, side, gross, smaller (Simplebim): 0.0953118 m2; Area, side, net, larger (Simplebim): 0.0953118 m2; Area, side, net, smaller (Simplebim): 0.0953118 m2; Area, side, net, average (Simplebim): 0.0953118 m2; Area, side, gross, AABB (Simplebim): 0.0953118 m2; Volume, net (Simplebim): 0.00142968 m3; Length (Simplebim): 413.5 mm
ePset_Simplebim - Assembly Level: Leaf
Pset_QuantityTakeOff - Reference: A241 - F-15; sets with these values: 2
Group: Model Group:A240 - eksisterende gallerivegg i pir G-2 / bak sjakt (members excluded):37559234

# IfcWallStandardCase: Basic Wall:A241 - FFS (12)
Type - PredefinedType: STANDARD; Material: T2_Gips Protect F 12.5 mm, T2_X-finer 12 mm, T2_X-finer 12 mm
Pset_QuantityTakeOff - Reference: A241 - FFS; sets with these values: 2
Pset_WallCommon - Reference: A241 - FFS; IsExternal: no; ExtendToStructure: no; LoadBearing: no
ePset_LocationTool - Splitting: ORIGINAL
ePset_Simplebim - Assembly Level: Leaf
AVINOR - 08_Status: S4; 07_Fase: F90; 03_Ansvar: 182412; 06_Omrade: TH; 02_Prosjekt: A184862; 01_Lufthavnkode: ENGM
Group: Model Group:A184862 - Kiosk NSOPØ 05.235 2 (members excluded):47061109
Name (Basic Wall:A241 - FFS:...) | In | Volume, net (Simplebim) (m3) | Thickness (Simplebim) (mm) | Height (Simplebim) (mm) | Length (Simplebim) (mm) | Area, side, gross, AABB (Simplebim) (m2) = Area, side, gross, larger (Simplebim) (m2) = Area, side, net, larger (Simplebim) (m2) | Area, largest surface, net (Simplebim) (m2) | Area, side, gross, average (Simplebim) (m2) = Area, side, net, average (Simplebim) (m2) | Area, side, gross, smaller (Simplebim) (m2) = Area, side, net, smaller (Simplebim) (m2)
47060657 | Nivå F - 0,7 m | 0.145763 | 36.5 | 700 | 5705 | 3.9935 | 3.9935 | 3.9935 | 3.9935
47060674 | Nivå F - 0,7 m | 0.0124838 | 36.5 | 700 | 488.602 | 0.342021 | 0.342021 | 0.342021 | 0.342021
47060674 | Nivå F | 0.0344196 | 36.5 | 1930 | 488.602 | 0.943001 | 0.943001 | 0.943001 | 0.943001
47060675 | Nivå F - 0,7 m | 0.00656997 | 36.5 | 700 | 257.142 | 0.179999 | 0.179999 | 0.179999 | 0.179999
47060675 | Nivå F | 0.0181143 | 36.5 | 1930 | 257.142 | 0.496283 | 0.496283 | 0.496283 | 0.496283
47060766 | Nivå F - 0,7 m | 0.0120085 | 36.5 | 700 | 470 | 0.329 | 0.329 | 0.329 | 0.329
47060766 | Nivå F | 0.0331092 | 36.5 | 1930 | 470 | 0.9071 | 0.9071 | 0.9071 | 0.9071
47061002 | Nivå F - 0,7 m | 0.0514949 |  |  |  |  | 1.42662
47061003 | Nivå F - 0,7 m | 0.0523219 | 36.5 | 550 | 2606.36 | 1.4335 | 1.4335 | 1.43348 | 1.43346
47061004 | Nivå F - 0,7 m | 0.0516265 |  |  |  |  | 1.43025
47061005 | Nivå F - 0,7 m | 0.078694 | 36.5 | 550 | 3920 | 2.156 | 2.156 | 2.156 | 2.156
47061006 | Nivå F - 0,7 m | 0.0661989 |  |  |  |  | 1.83063

# IfcWallStandardCase: Basic Wall:A241 - FSVF-100 (100/100 ps-p) (2)
Type - PredefinedType: STANDARD; Material: T2_Gips Protect F 15 mm, T2_Gips Standard 12.5 mm, _NSW Stålstender, uisolert 100 mm, T2_Gips Protect F 15 mm
Type - Pset_ReinforcementBarPitchOfWall - Description: Tilsvarende: T2 - IVEGG-150 - Forprosjekt
Type - Pset_WallCommon - AcousticRating: -
ePset_LocationTool - Splitting: ORIGINAL
Pset_WallCommon - Reference: A241 - FSVF-100 (100/100 ps-p); IsExternal: no; ExtendToStructure: no; LoadBearing: no
AVINOR - 07_Fase: F90; 03_Ansvar: FDV; 08_Status: S2; 06_Omrade: TH; 01_Lufthavnkode: ENGM
Pset_QuantityTakeOff - Reference: A241 - FSVF-100 (100/100 ps-p); sets with these values: 2
ePset_SimplebimBasicQuantities - Length (Simplebim): 1945 mm; Thickness (Simplebim): 142.5 mm
ePset_Simplebim - Assembly Level: Leaf
Name (Basic Wall:A241 - FSVF-100 (100/100 ps-p):...) | In | Area, largest surface, net (Simplebim) (m2) | Area, side, gross, AABB (Simplebim) (m2) | Area, side, net, larger (Simplebim) (m2) = Area, side, net, average (Simplebim) (m2) = Area, side, net, smaller (Simplebim) (m2) | Area, side, gross, average (Simplebim) (m2) = Area, side, gross, larger (Simplebim) (m2) = Area, side, gross, smaller (Simplebim) (m2) | Height (Simplebim) (mm) | Volume, net (Simplebim) (m3)
2640279 | Nivå F - 0,7 m | 0.401616 | 1.3615 | 0.7945 | 2.6251 | 700 | 0.113216
2640279 | Nivå F | 4.1824 | 5.446 | 4.1824 | 6.013 | 2800 | 0.595992

# IfcWallStandardCase: Basic Wall:A241 - RVR-77 (75/75 r-rr) (3)
Type - PredefinedType: STANDARD; Material: Plate - Gips 12.5 mm, _NSW Stålstender, uisolert 75 mm, Plate - Gips 12.5 mm, Plate - Gips 12.5 mm
Type - Pset_ReinforcementBarPitchOfWall - Description: Internt i toalettrom
Pset_ReinforcementBarPitchOfWall - Reference: A241 - RVR-77 (75/75 r-rr); sets with these values: 2
ePset_LocationTool - Splitting: ORIGINAL
ePset_SimplebimBasicQuantities - Thickness (Simplebim): 112.5 mm
Pset_WallCommon - Reference: A241 - RVR-77 (75/75 r-rr); IsExternal: no; ExtendToStructure: no; LoadBearing: no
ePset_Simplebim - Assembly Level: Leaf
AVINOR - 08_Status: S4; 07_Fase: F90; 03_Ansvar: 182412; 06_Omrade: TH; 02_Prosjekt: A184862; 01_Lufthavnkode: ENGM
Group: Model Group:A184862 - Kiosk NSOPØ 05.235 2 (members excluded):47061109
Name (Basic Wall:A241 - RVR-77 (75/75 r-rr):...) | In | Area, side, gross, AABB (Simplebim) (m2) = Area, side, gross, larger (Simplebim) (m2) = Area, side, gross, average (Simplebim) (m2) = Area, side, net, average (Simplebim) (m2) = Area, side, net, smaller (Simplebim) (m2) = Area, side, net, larger (Simplebim) (m2) = Area, side, gross, smaller (Simplebim) (m2) = Area, largest surface, net (Simplebim) (m2) | Length (Simplebim) (mm) | Volume, net (Simplebim) (m3) | Height (Simplebim) (mm)
47060848 | Nivå F - 0,7 m | 1.0445 | 1492.14 | 0.117506 | 700
47060848 | Nivå F | 3.58114 | 1492.14 | 0.402878 | 2400
47061008 | Nivå F - 0,7 m | 0.215884 | 308.406 | 0.024287 | 700

# IfcWallStandardCase: Basic Wall:A241 - SXV-75 (4)
Type - PredefinedType: STANDARD; Material: _NSW Isolasjon 75 mm, _NSW X-finer 12.5 mm, Plate - Gips 12.5 mm
Pset_QuantityTakeOff - Reference: A241 - SXV-75; sets with these values: 2
Pset_WallCommon - Reference: A241 - SXV-75; IsExternal: no; ExtendToStructure: no; LoadBearing: no
ePset_LocationTool - Splitting: ORIGINAL
ePset_Simplebim - Assembly Level: Leaf
ePset_SimplebimBasicQuantities - Thickness (Simplebim): 100 mm
AVINOR - 08_Status: S4; 07_Fase: F90; 03_Ansvar: 182412; 06_Omrade: TH; 02_Prosjekt: A184862; 01_Lufthavnkode: ENGM
Group: Model Group:A184862 - Kiosk NSOPØ 05.235 2 (members excluded):47061109
Name (Basic Wall:A241 - SXV-75:...) | In | Area, side, gross, larger (Simplebim) (m2) = Area, side, gross, average (Simplebim) (m2) = Area, side, net, larger (Simplebim) (m2) = Area, side, gross, smaller (Simplebim) (m2) = Area, side, net, average (Simplebim) (m2) = Area, side, net, smaller (Simplebim) (m2) = Area, largest surface, net (Simplebim) (m2) = Area, side, gross, AABB (Simplebim) (m2) | Volume, net (Simplebim) (m3) | Height (Simplebim) (mm) | Length (Simplebim) (mm)
47060861 | Nivå F - 0,7 m | 1.036 | 0.1036 | 700 | 1480
47060861 | Nivå F | 3.552 | 0.3552 | 2400 | 1480
47060862 | Nivå F - 0,7 m | 1.134 | 0.1134 | 700 | 1620
47060862 | Nivå F | 3.8799 | 0.38799 | 2395 | 1620

# IfcWallStandardCase: Basic Wall:A241 - SXVXS-75 (16)
Type - PredefinedType: STANDARD; Material: Plate - Gips 12.5 mm, _NSW X-finer 12.5 mm, _NSW Isolasjon 75 mm, _NSW X-finer 12.5 mm, Plate - Gips 12.5 mm
ePset_SimplebimBasicQuantities - Thickness (Simplebim): 125 mm
Pset_WallCommon - Reference: A241 - SXVXS-75; IsExternal: no; ExtendToStructure: no; LoadBearing: no
ePset_LocationTool - Splitting: ORIGINAL
Pset_QuantityTakeOff - Reference: A241 - SXVXS-75; sets with these values: 2
ePset_Simplebim - Assembly Level: Leaf
AVINOR - 08_Status: S4; 07_Fase: F90; 03_Ansvar: 182412; 06_Omrade: TH; 02_Prosjekt: A184862; 01_Lufthavnkode: ENGM
Group: Model Group:A184862 - Kiosk NSOPØ 05.235 2 (members excluded):47061109
Name (Basic Wall:A241 - SXVXS-75:...) | In | Volume, net (Simplebim) (m3) | Height (Simplebim) (mm) | Length (Simplebim) (mm) | Area, side, net, smaller (Simplebim) (m2) = Area, side, net, average (Simplebim) (m2) = Area, side, net, larger (Simplebim) (m2) | Area, side, gross, smaller (Simplebim) (m2) = Area, side, gross, average (Simplebim) (m2) = Area, side, gross, larger (Simplebim) (m2) | Area, largest surface, net (Simplebim) (m2) | Area, side, gross, AABB (Simplebim) (m2)
47060680 | Nivå F - 0,7 m | 1.01062 | 700 | 11550 | 8.085 | 8.085 | 8.085 | 8.085
47060680 | Nivå F | 3.10165 | 2148.33 | 11550 | 24.8132 | 24.8132 | 24.8132 | 24.8132
47060764 | Nivå F - 0,7 m | 0.0746057 | 700 | 852.637 | 0.596846 | 0.596846 | 0.596846 | 0.596846
47060764 | Nivå F | 0.255791 | 2400 | 852.637 | 2.04633 | 2.04633 | 2.04633 | 2.04633
47060765 | Nivå F - 0,7 m | 0.0667055 | 700 | 762.349 | 0.533644 | 0.533644 | 0.533644 | 0.533644
47060765 | Nivå F | 0.228705 | 2400 | 762.349 | 1.82964 | 1.82964 | 1.82964 | 1.82964
47060828 | Nivå F - 0,7 m | 0.178141 | 700 | 3145.89 | 1.42512 | 3.76722 | 0.858124 | 2.20212
47060828 | Nivå F | 0.74813 | 2400 | 3145.89 | 5.98504 | 8.32714 | 5.98504 | 7.55014
47060829 | Nivå F - 0,7 m | 0.463658 | 700 | 5298.95 | 3.70926 | 3.70926 | 3.70926 | 3.70926
47060829 | Nivå F | 1.58637 | 2395 | 5298.95 | 12.691 | 12.691 | 12.691 | 12.691
47060830 | Nivå F - 0,7 m | 0.286147 | 700 | 3270.25 | 2.28918 | 2.28918 | 2.28918 | 2.28917
47060830 | Nivå F | 0.790992 | 1935 | 3270.25 | 6.32793 | 6.32793 | 6.32793 | 6.32793
47060832 | Nivå F - 0,7 m | 0.062125 | 700 | 710 | 0.497 | 0.497 | 0.497 | 0.497
47060832 | Nivå F | 0.171288 | 1930 | 710 | 1.3703 | 1.3703 | 1.3703 | 1.3703
47060847 | Nivå F - 0,7 m | 0.236895 | 700 | 2707.37 | 1.89516 | 1.89516 | 1.89516 | 1.89516
47060847 | Nivå F | 0.812212 | 2400 | 2707.37 | 6.4977 | 6.4977 | 6.4977 | 6.4977

# IfcWallStandardCase: Basic Wall:A241 - Skjørt (SV-75 S) 3 (3)
In: Nivå F - 0,7 m
Type - PredefinedType: STANDARD; Material: Plate - Gips 12.5 mm, _NSW Stålstender, uisolert 75 mm
Type - Pset_ReinforcementBarPitchOfWall - Description: 12.5mm Gipsplater - 75mm Stålstender
Type - Pset_ConcreteElementGeneral - FireRating: EI30
Type - Pset_WallCommon - FireRating: EI30
Pset_QuantityTakeOff - Reference: A241 - Skjørt (SV-75 S) 3; sets with these values: 2
ePset_SimplebimBasicQuantities - Thickness (Simplebim): 87.5 mm
Pset_WallCommon - Reference: A241 - Skjørt (SV-75 S) 3; IsExternal: no; ExtendToStructure: no; LoadBearing: no
ePset_LocationTool - Splitting: ORIGINAL
ePset_Simplebim - Assembly Level: Leaf
AVINOR - 08_Status: S4; 07_Fase: F90; 03_Ansvar: 182412; 06_Omrade: TH; 02_Prosjekt: A184862; 01_Lufthavnkode: ENGM
Group: Model Group:A184862 - Kiosk NSOPØ 05.235 2 (members excluded):47061109
Name (Basic Wall:A241 - Skjørt (SV-75 S) 3:...) | Area, side, gross, AABB (Simplebim) (m2) = Area, largest surface, net (Simplebim) (m2) = Area, side, gross, larger (Simplebim) (m2) = Area, side, gross, average (Simplebim) (m2) = Area, side, net, larger (Simplebim) (m2) = Area, side, gross, smaller (Simplebim) (m2) = Area, side, net, average (Simplebim) (m2) = Area, side, net, smaller (Simplebim) (m2) | Length (Simplebim) (mm) | Volume, net (Simplebim) (m3) | Height (Simplebim) (mm)
47060945 | 0.0783125 | 437.5 | 0.00685234 | 179
47060989 | 0.213848 | 427.697 | 0.0187117 | 500
47060990 | 0.942625 | 1885.25 | 0.0824797 | 500

# IfcWallStandardCase: Basic Wall:A242 - IGV Glass 14mm (14)
Type - PredefinedType: STANDARD; Material: Glass(Avinor) 14 mm
Pset_ReinforcementBarPitchOfWall - Reference: A242 - IGV Glass 14mm; sets with these values: 2
Pset_WallCommon - Reference: A242 - IGV Glass 14mm; IsExternal: no; ExtendToStructure: no; LoadBearing: no
ePset_Simplebim - Assembly Level: Leaf
AVINOR - 08_Status: S4; 07_Fase: F90; 03_Ansvar: 182412; 06_Omrade: TH; 02_Prosjekt: A184862; 01_Lufthavnkode: ENGM
ePset_LocationTool - Splitting: ORIGINAL
Group: Model Group:A184862 - Kiosk NSOPØ 05.235 2 (members excluded):47061109
Name (Basic Wall:A242 - IGV Glass 14mm:...) | In | Area, largest surface, net (Simplebim) (m2) | Volume, net (Simplebim) (m3)
47060596 | Nivå F - 0,7 m | 0.289034 | 0.0101178
47060596 | Nivå F | 0.796909 | 0.0278962
47060597 | Nivå F - 0,7 m | 0.892065 | 0.0124455
47060597 | Nivå F | 2.46592 | 0.0344028
47060598 | Nivå F - 0,7 m | 0.903472 | 0.0126041
47060598 | Nivå F | 2.49746 | 0.0348413
47060604 | Nivå F - 0,7 m | 1.09702 | 0.0152895
47060604 | Nivå F | 3.03249 | 0.0422646
47060605 | Nivå F - 0,7 m | 1.09646 | 0.0152818
47060605 | Nivå F | 3.03094 | 0.0422431
47060606 | Nivå F - 0,7 m | 1.09515 | 0.0152381
47060606 | Nivå F | 3.02731 | 0.0421224
47060607 | Nivå F - 0,7 m | 1.09592 | 0.0152742
47060607 | Nivå F | 3.02943 | 0.0422222

# IfcWallStandardCase: Basic Wall:A242 - IGV Glass Opal 14mm (16)
Type - PredefinedType: STANDARD; Material: Kledning 14 mm
Pset_QuantityTakeOff - Reference: A242 - IGV Glass Opal 14mm; sets with these values: 2
Pset_WallCommon - IsExternal: no; ExtendToStructure: no; LoadBearing: no; Reference: A242 - IGV Glass Opal 14mm
ePset_Simplebim - Assembly Level: Leaf
ePset_LocationTool - Splitting: ORIGINAL
AVINOR - 08_Status: S4; 07_Fase: F90; 03_Ansvar: 182412; 06_Omrade: TH; 02_Prosjekt: A184862; 01_Lufthavnkode: ENGM
Group: Model Group:A184862 - Kiosk NSOPØ 05.235 2 (members excluded):47061109
Name (Basic Wall:A242 - IGV Glass Opal 14mm:...) | In | Length (Simplebim) (mm) | Thickness (Simplebim) (mm) | Area, largest surface, net (Simplebim) (m2) | Area, side, net, smaller (Simplebim) (m2) = Area, side, net, average (Simplebim) (m2) = Area, side, gross, smaller (Simplebim) (m2) = Area, side, net, larger (Simplebim) (m2) = Area, side, gross, average (Simplebim) (m2) = Area, side, gross, larger (Simplebim) (m2) = Area, side, gross, AABB (Simplebim) (m2) | Volume, net (Simplebim) (m3) | Height (Simplebim) (mm)
47060610 | Nivå F - 0,7 m | 1371.86 | 14 | 0.960304 | 0.960304 | 0.0134443 | 700
47060610 | Nivå F | 1371.86 | 14 | 3.40908 | 3.40908 | 0.0477271 | 2485
47060612 | Nivå F - 0,7 m | 1292 | 14 | 0.9044 | 0.9044 | 0.0126616 | 700
47060613 | Nivå F - 0,7 m | 790.306 | 14 | 0.553214 | 0.553214 | 0.007745 | 700
47060613 | Nivå F | 790.306 | 14 | 1.52529 | 1.52529 | 0.0213541 | 1930
47060681 | Nivå F - 0,7 m | 1302 | 14 | 0.9114 | 0.9114 | 0.0127596 | 700
47060681 | Nivå F | 1302 | 14 | 2.22077 | 2.22077 | 0.0310907 | 1705.66
47060780 | Nivå F - 0,7 m |  |  | 0.866582 |  | 0.0120779
47060781 | Nivå F - 0,7 m |  |  | 0.866582 |  | 0.0120779
47060782 | Nivå F - 0,7 m | 2590 | 14 | 1.4245 | 1.4245 | 0.019943 | 550
47060783 | Nivå F - 0,7 m |  |  | 0.866804 |  | 0.012061
47060784 | Nivå F - 0,7 m |  |  | 0.86741 |  | 0.0120896
47060787 | Nivå F - 0,7 m | 829 | 14 | 0.5803 | 0.5803 | 0.0081242 | 700
47060787 | Nivå F | 829 | 14 | 1.41399 | 1.41399 | 0.0197959 | 1705.66
47060850 | Nivå F - 0,7 m | 3941.09 | 14 | 2.1676 | 2.1676 | 0.0303464 | 550
47061007 | Nivå F - 0,7 m |  |  | 2.10964 |  | 0.0293696

# IfcWallStandardCase: Basic Wall:A245 - MP-5 Metallplate 5mm (8)
Type - PredefinedType: STANDARD; Material: T2 Stål Galvanisert 5 mm
Type - Pset_ReinforcementBarPitchOfWall - Description: metallplate 5mm ikke perforert
Pset_QuantityTakeOff - Reference: A245 - MP-5 Metallplate 5mm; sets with these values: 2
ePset_LocationTool - Splitting: ORIGINAL
ePset_SimplebimBasicQuantities - Thickness (Simplebim): 5 mm
Pset_WallCommon - IsExternal: no; ExtendToStructure: no; LoadBearing: no; Reference: A245 - MP-5 Metallplate 5mm
ePset_Simplebim - Assembly Level: Leaf
AVINOR - 08_Status: S4; 07_Fase: F90; 03_Ansvar: 182412; 06_Omrade: TH; 02_Prosjekt: A184862; 01_Lufthavnkode: ENGM
Group: Model Group:A184862 - Kiosk NSOPØ 05.235 2 (members excluded):47061109
Name (Basic Wall:A245 - MP-5 Metallplate 5mm:...) | In | Area, side, gross, larger (Simplebim) (m2) = Area, side, gross, average (Simplebim) (m2) = Area, side, net, larger (Simplebim) (m2) = Area, side, gross, smaller (Simplebim) (m2) = Area, side, net, average (Simplebim) (m2) = Area, side, net, smaller (Simplebim) (m2) = Area, largest surface, net (Simplebim) (m2) = Area, side, gross, AABB (Simplebim) (m2) | Volume, net (Simplebim) (m3) | Length (Simplebim) (mm) | Height (Simplebim) (mm)
47060656 | Nivå F - 0,7 m | 0.259 | 0.001295 | 370 | 700
47060656 | Nivå F | 0.714095 | 0.00357048 | 369.998 | 1930
47061046 | Nivå F - 0,7 m | 0.259 | 0.001295 | 370 | 700
47061046 | Nivå F | 0.714095 | 0.00357048 | 369.998 | 1930
47061055 | Nivå F - 0,7 m | 0.259 | 0.001295 | 370 | 700
47061055 | Nivå F | 0.714095 | 0.00357048 | 369.998 | 1930
47061064 | Nivå F - 0,7 m | 0.259 | 0.001295 | 370 | 700
47061064 | Nivå F | 0.714095 | 0.00357048 | 369.998 | 1930
